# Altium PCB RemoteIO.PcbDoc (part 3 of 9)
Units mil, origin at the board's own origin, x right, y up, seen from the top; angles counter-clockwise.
Board outline 7874.02 x 2362.2 mil, 6 copper layers (Top Layer, GND1, Layer 2, PWR, GND2, Bottom Layer), stack 60.956 mil thick; 686 components, 447 nets, 2681 pads, 1481 vias.

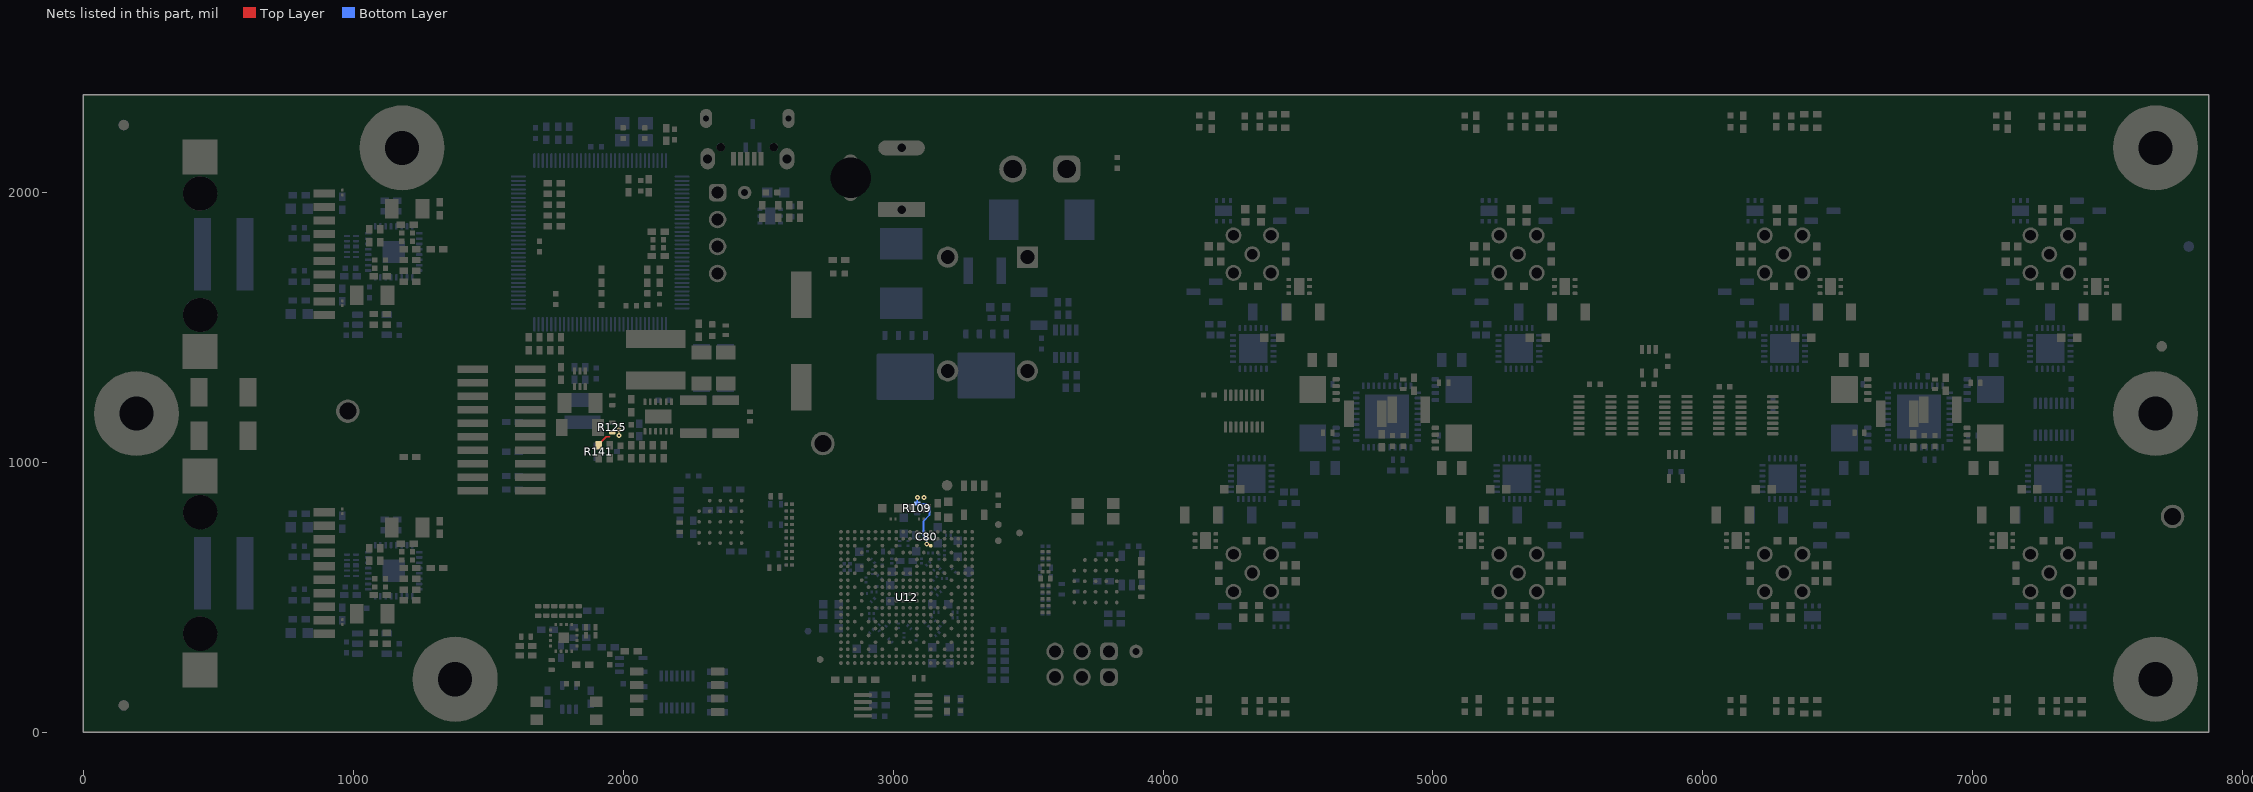
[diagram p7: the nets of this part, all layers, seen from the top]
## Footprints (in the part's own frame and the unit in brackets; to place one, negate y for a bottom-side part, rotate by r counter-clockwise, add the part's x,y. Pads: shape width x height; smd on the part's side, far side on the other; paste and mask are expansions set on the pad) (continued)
WE-MAPI_5030 [mm] "SMD Power Inductor, 2-leads, body 5.6x5.6mm"
  rect 1.7x5.6 smd: 1(-1.95,0) 2(1.95,0)
  silkscreen extent -0.75,-2.8 0.75,2.8, body extent -2.7,-2.7 2.7,2.7, height 3.1
WE-VS_0603 [mm] "SMD Varistor, 2-Leads, body 1.60x0.80mm"
  rect 0.75x0.7 smd: 1(-0.725,0) 2(0.725,0)
  body extent -0.8,-0.4 0.8,0.4, height 0.8
WEEE_Minimum [mil] "WEEElie bin"
  silkscreen extent -95,-172 99,104
WL-SMCC_0402_Green [mm] "SMD, 2-Leads, Body 1x0.5mm"
  rrect17% 0.6x0.6 smd: 1(-0.55,0) 2(0.55,0)
  body extent -0.5,-0.25 0.5,0.25, height 0.39
WURTH_61300311121 [mm] "Header, 2.54mm, 3x1, TH"
  rrect50% 1.65x1.65 hole 1.15: 1(-2.54,0)
  round 1.65 hole 1.15: 2(0,0) 3(2.54,0)
  body extent -3.81,-1.27 3.81,1.27, height 8.54
WURTH_61300411121 [mm] "Header, 2.54mm, 4x1, TH"
  rrect50% 1.65x1.65 hole 1.15: 1(-3.81,0)
  round 1.65 hole 1.15: 2(-1.27,0) 3(1.27,0) 4(3.81,0)
  body extent -5.08,-1.27 5.08,1.27, height 8.54
ZFG0304A-MFG [mm] "Recommended Land Pattern"
  round 0.35 smd paste+0 mask-1000: A1(-6.175,6.175) A2(-5.525,6.175) A3(-4.875,6.175) A4(-4.225,6.175) A5(-3.575,6.175) A6(-2.925,6.175) A7(-2.275,6.175) A8(-1.625,6.175) A9(-0.975,6.175) A10(-0.325,6.175) A11(0.325,6.175) A12(0.975,6.175) A13(1.625,6.175) A14(2.275,6.175) A15(2.925,6.175) A16(3.575,6.175) A17(4.225,6.175) A18(4.875,6.175) A19(5.525,6.175) A20(6.175,6.175) B1(-6.175,5.525) B2(-5.525,5.525) B3(-4.875,5.525) B4(-4.225,5.525) B5(-3.575,5.525) B6(-2.925,5.525) B7(-2.275,5.525) B8(-1.625,5.525) B9(-0.975,5.525) B10(-0.325,5.525) B11(0.325,5.525) B12(0.975,5.525) B13(1.625,5.525) B14(2.275,5.525) B15(2.925,5.525) B16(3.575,5.525) B17(4.225,5.525) B18(4.875,5.525) B19(5.525,5.525) B20(6.175,5.525) C1(-6.175,4.875) C2(-5.525,4.875) C3(-4.875,4.875) C5(-3.575,4.875) C7(-2.275,4.875) C9(-0.975,4.875) C12(0.975,4.875) C14(2.275,4.875) C16(3.575,4.875) C18(4.875,4.875) C19(5.525,4.875) C20(6.175,4.875) D1(-6.175,4.225) D2(-5.525,4.225) D4(-4.225,4.225) D6(-2.925,4.225) D8(-1.625,4.225) D10(-0.325,4.225) D11(0.325,4.225) D13(1.625,4.225) D15(2.925,4.225) D17(4.225,4.225) D19(5.525,4.225) D20(6.175,4.225) E1(-6.175,3.575) E2(-5.525,3.575) E3(-4.875,3.575) E5(-3.575,3.575) E7(-2.275,3.575) E9(-0.975,3.575) E12(0.975,3.575) E14(2.275,3.575) E16(3.575,3.575) E18(4.875,3.575) E19(5.525,3.575) E20(6.175,3.575) F1(-6.175,2.925) F2(-5.525,2.925) F4(-4.225,2.925) F6(-2.925,2.925) F7(-2.275,2.925) F9(-0.975,2.925) F12(0.975,2.925) F14(2.275,2.925) F15(2.925,2.925) F17(4.225,2.925) F19(5.525,2.925) F20(6.175,2.925) G1(-6.175,2.275) G2(-5.525,2.275) G3(-4.875,2.275) G5(-3.575,2.275) G6(-2.925,2.275) G7(-2.275,2.275) G8(-1.625,2.275) G9(-0.975,2.275) G10(-0.325,2.275) G11(0.325,2.275) G12(0.975,2.275) G13(1.625,2.275) G14(2.275,2.275) G15(2.925,2.275) G16(3.575,2.275) G18(4.875,2.275) G19(5.525,2.275) G20(6.175,2.275) H1(-6.175,1.625) H2(-5.525,1.625) H4(-4.225,1.625) H7(-2.275,1.625) H8(-1.625,1.625) H9(-0.975,1.625) H10(-0.325,1.625) H11(0.325,1.625) H12(0.975,1.625) H13(1.625,1.625) H14(2.275,1.625) H17(4.225,1.625) H19(5.525,1.625) H20(6.175,1.625) J1(-6.175,0.975) J2(-5.525,0.975) J3(-4.875,0.975) J5(-3.575,0.975) J6(-2.925,0.975) J7(-2.275,0.975) J8(-1.625,0.975) J9(-0.975,0.975) J10(-0.325,0.975) J11(0.325,0.975) J12(0.975,0.975) J13(1.625,0.975) J14(2.275,0.975) J15(2.925,0.975) J16(3.575,0.975) J18(4.875,0.975) J19(5.525,0.975) J20(6.175,0.975) K1(-6.175,0.325) K2(-5.525,0.325) K4(-4.225,0.325) K7(-2.275,0.325) K8(-1.625,0.325) K9(-0.975,0.325) K10(-0.325,0.325) K11(0.325,0.325) K12(0.975,0.325) K13(1.625,0.325) K14(2.275,0.325) K17(4.225,0.325) K19(5.525,0.325) K20(6.175,0.325) L1(-6.175,-0.325) L2(-5.525,-0.325) L4(-4.225,-0.325) L7(-2.275,-0.325) L8(-1.625,-0.325) L9(-0.975,-0.325) L10(-0.325,-0.325) L11(0.325,-0.325) L12(0.975,-0.325) L13(1.625,-0.325) L14(2.275,-0.325) L17(4.225,-0.325) L19(5.525,-0.325) L20(6.175,-0.325) M1(-6.175,-0.975) M2(-5.525,-0.975) M3(-4.875,-0.975) M5(-3.575,-0.975) M6(-2.925,-0.975) M7(-2.275,-0.975) M8(-1.625,-0.975) M9(-0.975,-0.975) M10(-0.325,-0.975) M11(0.325,-0.975) M12(0.975,-0.975) M13(1.625,-0.975) M14(2.275,-0.975) M15(2.925,-0.975) M16(3.575,-0.975) M18(4.875,-0.975) M19(5.525,-0.975) M20(6.175,-0.975) N1(-6.175,-1.625) N2(-5.525,-1.625) N4(-4.225,-1.625) N7(-2.275,-1.625) N8(-1.625,-1.625) N9(-0.975,-1.625) N10(-0.325,-1.625) N11(0.325,-1.625) N12(0.975,-1.625) N13(1.625,-1.625) N14(2.275,-1.625) N17(4.225,-1.625) N19(5.525,-1.625) N20(6.175,-1.625) P1(-6.175,-2.275) P2(-5.525,-2.275) P3(-4.875,-2.275) P5(-3.575,-2.275) P6(-2.925,-2.275) P7(-2.275,-2.275) P8(-1.625,-2.275) P9(-0.975,-2.275) P10(-0.325,-2.275) P11(0.325,-2.275) P12(0.975,-2.275) P13(1.625,-2.275) P14(2.275,-2.275) P15(2.925,-2.275) P16(3.575,-2.275) P18(4.875,-2.275) P19(5.525,-2.275) P20(6.175,-2.275) R1(-6.175,-2.925) R2(-5.525,-2.925) R4(-4.225,-2.925) R6(-2.925,-2.925) R7(-2.275,-2.925) R9(-0.975,-2.925) R12(0.975,-2.925) R14(2.275,-2.925) R15(2.925,-2.925) R17(4.225,-2.925) R19(5.525,-2.925) R20(6.175,-2.925) T1(-6.175,-3.575) T2(-5.525,-3.575) T3(-4.875,-3.575) T5(-3.575,-3.575) T7(-2.275,-3.575) T9(-0.975,-3.575) T12(0.975,-3.575) T14(2.275,-3.575) T16(3.575,-3.575) T18(4.875,-3.575) T19(5.525,-3.575) T20(6.175,-3.575) U1(-6.175,-4.225) U2(-5.525,-4.225) U4(-4.225,-4.225) U6(-2.925,-4.225) U8(-1.625,-4.225) U10(-0.325,-4.225) U11(0.325,-4.225) U13(1.625,-4.225) U15(2.925,-4.225) U17(4.225,-4.225) U19(5.525,-4.225) U20(6.175,-4.225) V1(-6.175,-4.875) V2(-5.525,-4.875) V3(-4.875,-4.875) V5(-3.575,-4.875) V7(-2.275,-4.875) V9(-0.975,-4.875) V12(0.975,-4.875) V14(2.275,-4.875) V16(3.575,-4.875) V18(4.875,-4.875) V19(5.525,-4.875) V20(6.175,-4.875) W1(-6.175,-5.525) W2(-5.525,-5.525) W3(-4.875,-5.525) W4(-4.225,-5.525) W5(-3.575,-5.525) W6(-2.925,-5.525) W7(-2.275,-5.525) W8(-1.625,-5.525) W9(-0.975,-5.525) W10(-0.325,-5.525) W11(0.325,-5.525) W12(0.975,-5.525) W13(1.625,-5.525) W14(2.275,-5.525) W15(2.925,-5.525) W16(3.575,-5.525) W17(4.225,-5.525) W18(4.875,-5.525) W19(5.525,-5.525) W20(6.175,-5.525) Y1(-6.175,-6.175) Y2(-5.525,-6.175) Y3(-4.875,-6.175) Y4(-4.225,-6.175) Y5(-3.575,-6.175) Y6(-2.925,-6.175) Y7(-2.275,-6.175) Y8(-1.625,-6.175) Y9(-0.975,-6.175) Y10(-0.325,-6.175) Y11(0.325,-6.175) Y12(0.975,-6.175) Y13(1.625,-6.175) Y14(2.275,-6.175) Y15(2.925,-6.175) Y16(3.575,-6.175) Y17(4.225,-6.175) Y18(4.875,-6.175) Y19(5.525,-6.175) Y20(6.175,-6.175)
  silkscreen extent -7.38,-6.78 6.78,6.77, body extent -6.63,-6.63 6.63,6.63, height 1.3

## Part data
C1.1 C1.2 C1.3 C1.4 C1.5 C1.6 C1.7 C1.8 C40.1 C40.2 C40.3 C40.4 C40.5 C40.6 C40.7 C40.8: library part CMP-0119636-1, "WCAP-CSGP Multilayer Ceramic Chip Capacitor, General Purpose, size 1206, X7R, 1µF, 50VDC", Capacitance Tolerance=+/-10%, Case/Size Code=1206, Insulation Resistance=0.5GOhm, Manufacturer="Wurth Elektronik", Operating Temperature Max=125°C, Operating Temperature Min=-55°C, PartNumber='885012208093, Rated Voltage (DC)=50V
C2.1 C2.2 C2.3 C2.4 C2.5 C2.6 C2.7 C2.8: library part CMP-0115435-1, "WCAP-CSGP Multilayer Ceramic Chip Capacitor, General Purpose, size 0603, X7R, 1µF, 16VDC", Capacitance Tolerance=+/-10%, Case/Size Code=0603, Insulation Resistance=0.1GOhm, Manufacturer="Wurth Elektronik", Operating Temperature Max=125°C, Operating Temperature Min=-55°C, Rated Voltage (DC)=16V
C3 C4 C5 C6 C7 C8 C9 C10 C23 C24 C30 C33 C34 C36 C37 C38 C103 C117 C135.1 C135.2 C137.1 C137.2 C139.1 C139.2 C141.1 C141.2 C142.1 C142.2 C143 C149 C150 C151 C152 C153 C157 C162 C170: library part CMP-0119143-1, "WCAP-CSGP Multilayer Ceramic Chip Capacitor, General Purpose, size 0402, X5R, 100nF, 25VDC", Capacitance Tolerance=+/-20%, Case/Size Code=0402, Insulation Resistance=5GOhm, Manufacturer="Wurth Elektronik", Operating Temperature Max=85°C, Operating Temperature Min=-55°C, PartNumber='885012105018, Rated Voltage (DC)=25V
C11 C12 C13 C14 C16 C17 C18 C19: library part CMP-0119538-1, "WCAP-CSGP Multilayer Ceramic Chip Capacitor, General Purpose, size 0805, X7R, 22nF, 100VDC", Capacitance Tolerance=+/-10%, Case/Size Code=0805, Insulation Resistance=4.5GOhm, Manufacturer="Wurth Elektronik", Operating Temperature Max=125°C, Operating Temperature Min=-55°C, Rated Voltage (DC)=100V
C15 C20: library part CMP-0097308-1, "100 pF ±5% 100V Ceramic Capacitor C0G, NP0 0402 (1005 Metric)", Digikey Part Number=732-12055-1-ND, Manufacturer="Wurth Electronics", Mouser Part Number=710-885012005080, Operating Temperature Range="-55°C to +125°C", TempCo=30ppm/°C, Temperature Characteristic=NP0, Tolerance_%=5%, ValueDisplayed=100pF
C21 C22 C148 C163: library part CMP-0119705-1, "WCAP-CSGP Multilayer Ceramic Chip Capacitor, General Purpose, size 1210, X7R, 2.2µF, 100VDC", Capacitance Tolerance=+/-10%, Case/Size Code=1210, Insulation Resistance=0.05GOhm, Manufacturer="Wurth Elektronik", Operating Temperature Max=125°C, Operating Temperature Min=-55°C, PartNumber='885012209071, Rated Voltage (DC)=100V
C25 C26 C27 C28 C29 C32 C35 C39 C41 C42 C43 C130.1 C130.2 C133.1 C133.2 C136.1 C136.2 C138.1 C138.2 C144 C146 C154 C155 C158 C159 C164: library part CMP-0064924-2, "CAP, CERM, 1 uF, 10 V,+/- 20%, X5R, 0402", Cap_Case=0402, Manufacturer="Wurth Elektronik", Supplier Part Number 1=732-7489-1-ND, TempCo=X5R, Tolerance_%=20%, Value1=Unknown, Value2=10V, ValueDisplayed=1uF
C31 C131.1 C131.2 C134.1 C134.2 C145 C147 C156 C167 C168.1 C168.2 C169.1 C169.2: library part CMP-0119242-1, "WCAP-CSGP Multilayer Ceramic Chip Capacitor, General Purpose, size 0402, X7R, 10nF, 10VDC", Capacitance Tolerance=+/-10%, Case/Size Code=0402, Insulation Resistance=10GOhm, Manufacturer="Wurth Elektronik", Operating Temperature Max=125°C, Operating Temperature Min=-55°C, Rated Voltage (DC)=10V
C44 C45 C46 C61 C63 C65 C66 C75 C84 C86 C91 C92 C93 C100 C121 C123 C125: library part CMP-0119149-1, "WCAP-CSGP Multilayer Ceramic Chip Capacitor, General Purpose, size 0603, X5R, 4.7µF, 6.3VDC", Capacitance Tolerance=+/-20%, Case/Size Code=0603, Insulation Resistance=0.02GOhm, Manufacturer="Wurth Elektronik", Operating Temperature Max=85°C, Operating Temperature Min=-55°C, Rated Voltage (DC)=6.3V
C47 C48 C49 C50 C51 C52 C53 C54 C55 C56 C57 C58 C59 C60 C62 C64 C67 C68 C69 C70 C71 C72 C73 C74 C76 C77 C78 C79 C80 C81 C82 C83 C85 C87 C88 C89 C90 C94 C95 C96 C97 C98 C99 C101 C102 C122 C124 C126: library part CMP-0119120-1, "WCAP-CSGP Multilayer Ceramic Chip Capacitor, General Purpose, size 0201, X5R Class II, 100nF, 6.3VDC", Capacitance Tolerance=+/-10%, Case/Size Code=0201, Insulation Resistance=0.5GOhm, Manufacturer="Wurth Elektronik", Operating Temperature Max=85°C, Operating Temperature Min=-55°C, Rated Voltage (DC)=6.3V
C104 C105 C106 C107 C120: library part CMP-0096739-1, "4.7 µF ±10% 50V Ceramic Capacitor X7R 1210 (3225 Metric)", Digikey Part Number=732-7386-1-ND, Manufacturer=Wurth, Mouser Part Number=710-885012209048, Operating Temperature Range="-55°C to +125°C", TempCo=15%, Temperature Characteristic=X7R, Tolerance_%=10%, ValueDisplayed=4.7uF
C108 C109 C115: library part CMP-0064937-2, "CAP, CERM, 22 uF, 10 V,+/- 10%, X7R, 1206", Cap_Case=1206, Manufacturer="Wurth Elektronik", Supplier Part Number 1=732-7566-1-ND, TempCo=X7R, Tolerance_%=10%, Value1=Unknown, Value2=10V, ValueDisplayed=22uF
C110 C111 C113 C129.1 C129.2 C132.1 C132.2: library part CMP-0750070-1, "CAP, CERM, 10 µF, 16 V,+/- 10%, X7R, 1206", Cap_Case=1206, Manufacturer="Wurth Elektronik", TempCo=X7R, Tolerance_%=10%, Value2=16V, ValueDisplayed=10µF
C112 C114: library part CMP-0112443-1, "WCAP-CSRF Multilayer Ceramic Chip Capacitor, High Frequency, size 0402, NP0 Class I, 27pF, 50VDC", Capacitance Tolerance=+/-5%, Case/Size Code=0402, Insulation Resistance=10GOhm, Manufacturer="Wurth Elektronik", Operating Temperature Max=125°C, Operating Temperature Min=-55°C, Rated Voltage (DC)=50V
C116: library part CMP-0114361-1, "WCAP-AS5H Aluminum Electrolytic Capacitor, V-Chip, D10 x H10.5mm, 220µF, 35V", Capacitance Tolerance=+/-20%, Leakage Current=77uA, Manufacturer="Wurth Elektronik", Operating Temperature Max=105°C, Operating Temperature Min=-40°C, Rated Voltage (DC)=35V, Ripple Current=280mA
C118: library part CMP-0119630-1, "WCAP-CSGP Multilayer Ceramic Chip Capacitor, General Purpose, size 1206, X7R, 100nF, 50VDC", Capacitance Tolerance=+/-10%, Case/Size Code=1206, Insulation Resistance=5GOhm, Manufacturer="Wurth Elektronik", Operating Temperature Max=125°C, Operating Temperature Min=-55°C, Rated Voltage (DC)=50V
C119: library part CMP-0119892-1, "WCAP-CSST Multilayer Ceramic Chip Capacitor, Soft Termination, size 0603, X7R Class II, 22nF, 50VDC", Capacitance Tolerance=+/-10%, Case/Size Code=0603, Insulation Resistance=10GOhm, Manufacturer="Wurth Elektronik", Operating Temperature Max=125°C, Operating Temperature Min=-55°C, Rated Voltage (DC)=50V
C127.1 C127.2: library part CMP-0006473-2, "CAP, CERM, 4.7 pF, 50 V, +/- 1%, C0G/NP0, 0402", Cap_Case=0402, Manufacturer=MuRata, Supplier Part Number 1=490-8210-1-ND, TempCo=C0G/NP0, Tolerance_%=1%, Value1=Unknown, Value2=50V, ValueDisplayed=4.7pF
C128.1 C128.2: library part CMP-0119293-1, "WCAP-CSGP Multilayer Ceramic Chip Capacitor, General Purpose, size 0402, X7R, 2.2nF, 50VDC", Capacitance Tolerance=+/-10%, Case/Size Code=0402, Insulation Resistance=10GOhm, Manufacturer="Wurth Elektronik", Operating Temperature Max=125°C, Operating Temperature Min=-55°C, Rated Voltage (DC)=50V
C140.1 C140.2: library part CMP-0009301-2, "CAP, CERM, 0.01 uF, 2000 V, +/- 10%, X7R, 1825", Cap_Case=1825, Manufacturer=AVX, Supplier Part Number 1=478-4008-1-ND, TempCo=X7R, Tolerance_%=10%, Value1=Unknown, Value2=2000V, ValueDisplayed=0.01uF
C160 C161: library part CMP-0124909-1, "12 pF ±2% 50V Ceramic Capacitor C0G, NP0 0402 (1005 Metric)", Digikey Part Number=732-885392005127CT-ND, Manufacturer=Wurth, Mouser Part Number=710-885392005127, Operating Temperature Range="-55°C to +125°C", TempCo=30ppm/°C, Temperature Characteristic=NP0, Tolerance_%=2%, ValueDisplayed=12pF
C165.1 C165.2 C165.3 C165.4 C165.5 C165.6 C165.7 C165.8 C166.1 C166.2 C166.3 C166.4 C166.5 C166.6 C166.7 C166.8: library part CMP-0118895-1, "WCAP-CSGP Multilayer Ceramic Chip Capacitor, General Purpose, size 0603, NP0, 1nF, 50VDC", Capacitance Tolerance=+/-5%, Case/Size Code=0603, Insulation Resistance=10GOhm, Manufacturer="Wurth Elektronik", Operating Temperature Max=125°C, Operating Temperature Min=-55°C, Rated Voltage (DC)=50V
D1 D2 D3 D4 D5 D6 D7 D8: library part CMP-0125609-1, "Green, Red 520nm Green, 625nm Red LED Indication - Discrete 3.2V Green, 2V Red 0606 (1616 Metric)", Color="Red, Green", Digikey Part Number=732-150066RG74000CT-ND, Forward Current=20mA, Manufacturer=Wurth, Mouser Part Number=710-150066RG74000, Operating Temperature Range="-40°C to +85°C"
D9 D10 D11 D12 D13 D14 D15 D16 D20 D21 D22 D24 D29 D30 D31: library part CMP-0081765-2, "LED, Green, SMD", Color=Green, Manufacturer="Wurth Elektronik", Power_TotalModule=99mW, Value1=0.099W, Value2=3.2V
D23 D28: library part CMP-0122246-1, "Red 624nm LED Indication - Discrete 2V 0402 (1005 Metric)", Color=Red, Digikey Part Number=732-13422-1-ND, Forward Current=20mA, Manufacturer=Wurth, Mouser Part Number=710-150040RS73240, Operating Temperature Range="-40°C to +85°C", Power_TotalModule=48mW
D25: library part CMP-0005695-3, "Diode, TVS, Bi, 33 V, SMC", Manufacturer=Bourns, Value1=1500W
D26.1 D26.2 D27.1 D27.2: library part CMP-0120655-1, "1-pF, 5.5-V, 30-KV ESD protection device in 0201 package 2-X2SON -40 to 125", Breakdown Voltage=6V, Clamping Voltage=3.8V, Digikey Part Number=296-ESD441DPLRTR-ND, Manufacturer="Texas Instruments", Mouser Part Number=595-ESD441DPLR, Operating Temperature Range="-40°C to +125°C", ValueDisplayed=1pF
D35: library part CMP-0091708-1, "12.4V (Typ) Clamp 5.5A (8/20µs) Ipp Tvs Diode Surface Mount SC-70-3", Breakdown Voltage=6.5V, Clamping Voltage=9.7V, Digikey Part Number=296-TPD2E2U06DCKRCT-ND, Manufacturer="Texas Instruments", Mouser Part Number=595-TPD2E2U06DCKR, Operating Temperature Range="-40°C to +125°C", ValueDisplayed=1.5pF
F1: library part CMP-0003609-2, "Fuse, 10 A, 125 VAC, 72 VDC, SMD", Irating_A=10A, Manufacturer=Eaton, Supplier Part Number 1=283-2961-1-ND
FID1 FID2 FID3 FID4 FID5 FID6: library part CMP-0077181-1, "Fiducial mark.  There is nothing to buy or mount.", Manufacturer=N/A
H1 H2 H3 H9 H11 H12: library part CMP-0003617-1, "Machine Screw, Round, #4-40 x 1/4, Nylon, Philips panhead", Manufacturer="B&F Fastener Supply", Supplier Part Number 1=H542-ND
H5 H6 H7 H10 H13 H14: library part CMP-0003610-1, "Standoff, Hex, 0.5\"L #4-40 Nylon", Manufacturer=Keystone, Supplier Part Number 1=36-1902C-ND
J1.1 J1.2 J1.3 J1.4 J1.5 J1.6 J1.7 J1.8: "WR-CIRCM12 Screw Mating Panel Connector Female Metal PG9, THT, 5p", Insulation Resistance=100MΩ, Manufacturer="Wurth Elektronik", Max Operating Temperature=90°C, Min Operating Temperature=-40°C, PartNumber='643260100605, Rated Current=5A, Withstanding Voltage="1000V AC", Working Voltage=60V
J2: library part CMP-0127094-1, "Power Barrel Connector Jack 2.10mm ID (0.083\"), 5.50mm OD (0.217\") Through Hole, Right Angle", Current_A=5A, Digikey Part Number=732-5930-ND, Manufacturer=Wurth, Mouser Part Number=710-694106301002, Operating Temperature Range="-40°C to +85°C", Voltage_V=30V
J3: library part CMP-0075640-2, "Header, 1.27mm, 10x2, Tin, SMT", Color=Black, Current_A=3.1A, Manufacturer=Samtec, Supplier Part Number 1=SAM8792-ND
J4.1 J4.2: "WE-RJ45 LAN Transformer, SMT, 10/100 Base-T, Tab Down, 1 Port", Manufacturer="Wurth Elektronik", Max Operating Temperature=85°C, Min Operating Temperature=-40°C
J5: "WR-TBL Series 3055 PCB Header Horizontal Entry with Plastic Latches, THT, pitch 5.08mm, 02p", Manufacturer="Wurth Elektronik", Max Operating Temperature=105°C, Min Operating Temperature=-40°C, Rated Current=16A, Working Voltage=300V
J6: library part CMP-0054798-2, "Header, 2.54 mm, 4x1, Gold, TH", Color=Black, Manufacturer="Wurth Elektronik", PartNumber=61300411121, Supplier Part Number 1=732-5317-ND
J7: library part CMP-0086695-3, "USB - micro B USB 2.0 Receptacle Connector 5 Position Surface Mount, Right Angle; Through Hole", Current_A=3A, Manufacturer="Wurth Electronics", Voltage_V=30V
J8 J9: library part CMP-0054796-4, "Header, 2.54 mm, 3x1, Gold, TH", Manufacturer="Wurth Elektronik", Supplier Part Number 1=732-5316-ND
L1 L7.1 L7.2 L8.1 L8.2 L9: library part CMP-0003233-1, "Ferrite Bead, 600 ohm @ 100 MHz, 0.3 A, 0402", Manufacturer="Wurth Elektronik", Supplier Part Number 1=732-2388-1-ND, Value1="0.6 ohm", Value2=0.3A, ValueDisplayed="600 ohm"
L2 L3: library part CMP-0003214-1, "Ferrite Bead, 120 ohm @ 100 MHz, 0.5 A, 0402", Manufacturer="Wurth Elektronik", Supplier Part Number 1=710-74279271, Value1="0.2 ohm", Value2=0.5A, ValueDisplayed="120 ohm"
L4: library part CMP-0099177-1, "WE-MAPI SMT Power Inductor, size 5030, 6.8uH, 4.3A, 48.3mOhm", Case/Size Code=5030, DC Resistance=42mOhm, DC Resistance Max=48.3mOhm, Inductance=6.8uH, Manufacturer="Wurth Elektronik", Operating Temperature Max=125°C, Operating Temperature Min=-40°C, Rated Current=4.3A, Saturation Current=5.7A, Self Resonant Frequency=15.5MHz
L5: library part CMP-0099114-2, "WE-MAPI SMT Power Inductor, size 3020, 1uH, 4A, 32mOhm", Case/Size Code=3020, DC Resistance=26mOhm, DC Resistance Max=32mOhm, Inductance=1uH, Manufacturer="Wurth Elektronik", Operating Temperature Max=125°C, Operating Temperature Min=-40°C, Rated Current=4A, Saturation Current=5A, Self Resonant Frequency=67MHz
L6: library part CMP-0098028-1, "2 mH @ 10 kHz 2 Line Common Mode Choke Through Hole 10A DCR 6mOhm", Digikey Part Number=732-5584-ND, Manufacturer="Wurth Electronics", Mouser Part Number=710-7448031002, Operating Temperature Range="-40°C to +125°C", Test Frequency=10kHz, Tolerance_%=50%
LBL1: library part CMP-0003625-1, "Thermal Transfer Printable Labels, 0.650\" W x 0.200\" H - 10,000 per roll", Manufacturer=Brady, Supplier Part Number 1=97C5133
Logo1: library part CMP-0074838-1, "Texas Instrument Corporate Signature"
Logo2: library part CMP-0074844-1
Logo3: library part CMP-0074847-1, "FCC_disclaimer"
Logo4: library part CMP-0074769-1
Logo5: library part CMP-0074837-2, "IEC 61010-1 Hot Surface Warning", Manufacturer="Texas Instruments"
Q1 Q2 Q3 Q4 Q5 Q6 Q7 Q8: library part CMP-0000826-2, "MOSFET, N-CH, 60 V, 35 A, DNH0008A (VSONP-8)", Alternate Manufacturer=None, Manufacturer="Texas Instruments", Supplier Part Number 1=CSD18543Q3A-ND, Value1=0.01, Value2="11.1 nC"
Q9 Q10: library part CMP-0000823-2, "MOSFET, N-CH, 60 V, 100 A, DNK0008A (VSON-CLIP-8)", Alternate Manufacturer=None, Manufacturer="Texas Instruments", Supplier Part Number 1=296-41076-1-ND, Value1=0.003, Value2="41 nC"
Q11: library part CMP-0000486-2, "Transistor, NPN, 45 V, 0.1 A, AEC-Q101, SOT-323", Manufacturer="NXP Semiconductor", Supplier Part Number 1=568-6067-1-ND, Value1="0.1 A", Value2=800
R1.1 R1.2 R1.3 R1.4 R1.5 R1.6 R1.7 R1.8 R27 R28 R30 R33 R34 R35 R37 R73 R85 R87 R88 R98 R99 R101 R102 R103 R104 R105 R106 R107 R108 R109 R110 R111 R112 R117 R125 R137 R139 R155 R156 R157 R158 R159 R160 R161 R162: library part CMP-0093210-1, "Jumper 0.063W, 1/16W Chip Resistor 0402 (1005 Metric) - Thick Film", Digikey Part Number=541-4062-1-ND, Manufacturer=Vishay, Mouser Part Number=71-CRCW04020000Z0EDC, Operating Temperature Range="-55°C to +155°C", Power_W=63mW
R2.1 R2.2 R2.3 R2.4 R2.5 R2.6 R2.7 R2.8 R29 R42 R43 R63 R64 R89 R90 R91 R92 R94 R95 R96 R97 R100 R113 R141 R144 R145 R146 R147 R148 R149 R150 R164.1 R164.2 R189.1 R189.2 R190.1 R190.2 R208 R209: library part CMP-0026825-5, "RES, 10 k, 5%, 0.063 W, AEC-Q200 Grade 0, 0402", Manufacturer=Vishay-Dale, Power_W=63mW, Supplier Part Number 1=541-10KJCT-ND, TempCo="200 ppm/C", Tolerance_%=5%, Value2=0.063W, Value_Code=10k0, ValueDisplayed=10k
R3 R4 R5 R6 R7 R8 R9 R10 R11 R12 R13 R14 R15 R16 R17 R18 R32 R36 R61 R83 R123 R143 R197 R198 R199 R200 R206: library part CMP-0026071-3, "RES, 1.00 k, 1%, 0.063 W, AEC-Q200 Grade 0, 0402", Manufacturer=Vishay-Dale, Power_W=63mW, Supplier Part Number 1=541-1.00KLCT-ND, TempCo="100 ppm/C", Tolerance_%=1%, Value2=0.063W, Value_Code=1k00, ValueDisplayed=1.00k
R19 R20 R21 R22 R23 R24 R25 R26 R138 R140 R142 R195 R207: library part CMP-0026918-5, "RES, 3.3 k, 5%, 0.063 W, AEC-Q200 Grade 0, 0402", Manufacturer=Vishay-Dale, Power_W=63mW, Supplier Part Number 1=541-3.3KJCT-ND, TempCo="200 ppm/C", Tolerance_%=5%, Value2=0.063W, Value_Code=3k30, ValueDisplayed=3.3k
R31: library part CMP-0026004-3, "RES, 13.3 k, 1%, 0.063 W, AEC-Q200 Grade 0, 0402", Manufacturer=Vishay-Dale, Power_W=63mW, Supplier Part Number 1=541-13.3KLCT-ND, TempCo="100 ppm/C", Tolerance_%=1%, Value2=0.063W, Value_Code=13k3, ValueDisplayed=13.3k
R38: library part CMP-0026187-2, "RES, 23.7 k, 1%, 0.063 W, AEC-Q200 Grade 0, 0402", Manufacturer=Vishay-Dale, Power_W=63mW, Supplier Part Number 1=541-23.7KLCT-ND, TempCo="100 ppm/C", Tolerance_%=1%, Value2=0.063W, Value_Code=23k7, ValueDisplayed=23.7k
R39 R40 R118 R119 R120: library part CMP-0026908-3, "RES, 33, 5%, 0.063 W, AEC-Q200 Grade 0, 0402", Manufacturer=Vishay-Dale, Power_W=63mW, Supplier Part Number 1=541-33JCT-ND, TempCo="200 ppm/C", Tolerance_%=5%, Value2=0.063W, Value_Code=33R0, ValueDisplayed=33
R41: library part CMP-0026890-5, "RES, 2.2 k, 5%, 0.063 W, AEC-Q200 Grade 0, 0402", Manufacturer=Vishay-Dale, Power_W=63mW, Supplier Part Number 1=541-2.2KJCT-ND, TempCo="200 ppm/C", Tolerance_%=5%, Value2=0.063W, Value_Code=2k20, ValueDisplayed=2.2k
R44 R45 R47 R48 R49 R50 R51 R65 R66 R68 R69 R70 R71 R72: library part CMP-0028027-1, "RES, 49.9 k, 1%, 0.05 W, 0201", Manufacturer="Yageo America", Power_W=50mW, Supplier Part Number 1=603-RC0201FR-7D49K9L, TempCo="200 ppm/C", Tolerance_%=1%, Value2=0.05W, Value_Code=49k9, ValueDisplayed=49.9k
R46 R67: library part CMP-0027242-1, "RES, 4.7 k, 5%, 0.05 W, 0201", Manufacturer="Yageo America", Power_W=50mW, Supplier Part Number 1=603-RC0201JR-7D4K7L, TempCo="200 ppm/C", Tolerance_%=5%, Value2=0.05W, Value_Code=4k70, ValueDisplayed=4.7k
R52 R53 R54 R55 R56 R57 R58 R59 R60 R74 R75 R76 R77 R78 R79 R80 R81 R82: library part CMP-0027210-3, "RES, 22, 5%, 0.05 W, 0201", Manufacturer="Yageo America", Power_W=50mW, Supplier Part Number 1=603-RC0201JR-7D22RL, TempCo="200 ppm/C", Tolerance_%=5%, Value2=0.05W, Value_Code=22R0, ValueDisplayed=22
R62 R84 R121 R122 R127 R128 R129 R130 R134: library part CMP-0026721-1, "RES, 100 k, 1%, 0.0625 W, 0402", Manufacturer="Yageo America", Power_W=62.5mW, Supplier Part Number 1=311-100KLRCT-ND, TempCo="100 ppm/C", Tolerance_%=1%, Value2=0.0625W, Value_Code=100k
R86 R114 R115: library part CMP-0027008-4, "RES, 0, 5%, 0.05 W, 0201", Manufacturer=Vishay-Dale, Power_W=50mW, Supplier Part Number 1=72M6743, TempCo=ppm/C, Tolerance_%=5%, Value2=0.05W, Value_Code=0000, ValueDisplayed=0
R93: library part CMP-0026964-3, "RES, 68, 5%, 0.063 W, AEC-Q200 Grade 0, 0402", Manufacturer=Vishay-Dale, Power_W=63mW, Supplier Part Number 1=541-68JCT-ND, TempCo="200 ppm/C", Tolerance_%=5%, Value2=0.063W, Value_Code=68R0, ValueDisplayed=68
R124: library part CMP-0026290-2, "RES, 31.6 k, 1%, 0.063 W, AEC-Q200 Grade 0, 0402", Manufacturer=Vishay-Dale, Power_W=63mW, Supplier Part Number 1=541-31.6KLCT-ND, TempCo="100 ppm/C", Tolerance_%=1%, Value2=0.063W, Value_Code=31k6, ValueDisplayed=31.6k
R126: library part CMP-0025956-3, "RES, 107 k, 1%, 0.063 W, AEC-Q200 Grade 0, 0402", Manufacturer=Vishay-Dale, Power_W=63mW, Supplier Part Number 1=541-107KLCT-ND, TempCo="100 ppm/C", Tolerance_%=1%, Value2=0.063W, Value_Code=107k
R131 R201: library part CMP-0026824-3, "RES, 100, 5%, 0.063 W, AEC-Q200 Grade 0, 0402", Manufacturer=Vishay-Dale, Power_W=63mW, Supplier Part Number 1=541-100JCT-ND, TempCo="200 ppm/C", Tolerance_%=5%, Value2=0.063W, Value_Code=100R, ValueDisplayed=100
R132: library part CMP-0026340-2, "RES, 3.92 k, 1%, 0.063 W, AEC-Q200 Grade 0, 0402", Manufacturer=Vishay-Dale, Power_W=63mW, Supplier Part Number 1=541-3.92KLCT-ND, TempCo="100 ppm/C", Tolerance_%=1%, Value2=0.063W, Value_Code=3k92, ValueDisplayed=3.92k
R133: library part CMP-0026555-2, "RES, 7.50 k, 1%, 0.063 W, AEC-Q200 Grade 0, 0402", Manufacturer=Vishay-Dale, Power_W=63mW, Supplier Part Number 1=541-7.50KLCT-ND, TempCo="100 ppm/C", Tolerance_%=1%, Value2=0.063W, Value_Code=7k50, ValueDisplayed=7.50k
R135: library part CMP-0026592-2, "RES, 8.87 k, 1%, 0.063 W, AEC-Q200 Grade 0, 0402", Manufacturer=Vishay-Dale, Power_W=63mW, Supplier Part Number 1=541-8.87KLCT-ND, TempCo="100 ppm/C", Tolerance_%=1%, Value2=0.063W, Value_Code=8k87, ValueDisplayed=8.87k
R136: library part CMP-0026963-3, "RES, 68 k, 5%, 0.063 W, AEC-Q200 Grade 0, 0402", Manufacturer=Vishay-Dale, Power_W=63mW, Supplier Part Number 1=541-68KJCT-ND, TempCo="200 ppm/C", Tolerance_%=5%, Value2=0.063W, Value_Code=68k0, ValueDisplayed=68k
R151 R152 R153 R154 R203 R204 R205 R212: library part CMP-0026880-3, "RES, 22, 5%, 0.063 W, AEC-Q200 Grade 0, 0402", Manufacturer=Vishay-Dale, Power_W=63mW, Supplier Part Number 1=541-22JCT-ND, TempCo="200 ppm/C", Tolerance_%=5%, Value2=0.063W, Value_Code=22R0, ValueDisplayed=22
R163.1 R163.2: library part CMP-0026515-2, "RES, 6.49 k, 1%, 0.063 W, AEC-Q200 Grade 0, 0402", Manufacturer=Vishay-Dale, Power_W=63mW, Supplier Part Number 1=541-6.49KLCT-ND, TempCo="100 ppm/C", Tolerance_%=1%, Value2=0.063W, Value_Code=6k49, ValueDisplayed=6.49k
R166.1 R166.2 R167.1 R167.2 R168.1 R168.2 R171.1 R171.2 R172.1 R172.2: library part CMP-0026237-2, "RES, 2.49 k, 1%, 0.063 W, AEC-Q200 Grade 0, 0402", Manufacturer=Vishay-Dale, Power_W=63mW, Supplier Part Number 1=541-2.49KLCT-ND, TempCo="100 ppm/C", Tolerance_%=1%, Value2=0.063W, Value_Code=2k49, ValueDisplayed=2.49k
R176.1 R176.2 R177.1 R177.2 R178.1 R178.2 R181.1 R181.2 R182.1 R182.2: library part CMP-0026088-3, "RES, 1.50 k, 1%, 0.063 W, AEC-Q200 Grade 0, 0402", Manufacturer=Vishay-Dale, Power_W=63mW, Supplier Part Number 1=541-1.50KLCT-ND, TempCo="100 ppm/C", Tolerance_%=1%, Value2=0.063W, Value_Code=1k50, ValueDisplayed=1.50k
R191.1 R191.2 R192.1 R192.2: library part CMP-0025756-4, "RES, 220, 5%, 0.1 W, AEC-Q200 Grade 0, 0603", Manufacturer=Vishay-Dale, Power_W=100mW, Supplier Part Number 1=541-220GCT-ND, TempCo="200 ppm/C", Tolerance_%=5%, Value2=0.1W, Value_Code=220R, ValueDisplayed=220
R193.1 R193.2: library part CMP-0016081-3, "RES, 1.0 M, 5%, 0.75 W, AEC-Q200 Grade 0, 2010", Manufacturer=Vishay-Dale, Power_W=750mW, Supplier Part Number 1=541-1.0MWCT-ND, TempCo="200 ppm/C", Tolerance_%=5%, Value2=0.75W, Value_Code=1M00, ValueDisplayed=1.0M
R194: library part CMP-0026441-2, "RES, 52.3 k, 1%, 0.063 W, AEC-Q200 Grade 0, 0402", Manufacturer=Vishay-Dale, Power_W=63mW, Supplier Part Number 1=541-52.3KLCT-ND, TempCo="100 ppm/C", Tolerance_%=1%, Value2=0.063W, Value_Code=52k3, ValueDisplayed=52.3k
R196: library part CMP-0078244-2, "RES, 30.0 k, 1%, 0.063 W, AEC-Q200 Grade 0, 0402", Manufacturer=Vishay-Dale, Power_W=63mW, Supplier Part Number 1=541-30.0KLCT-ND, TempCo="100 ppm/C", Tolerance_%=1%, Value2=0.063W, Value_Code=30k0, ValueDisplayed=30.0k
R210: library part CMP-0026413-2, "RES, 4.87 k, 1%, 0.063 W, AEC-Q200 Grade 0, 0402", Manufacturer=Vishay-Dale, Power_W=63mW, Supplier Part Number 1=541-4.87KLCT-ND, TempCo="100 ppm/C", Tolerance_%=1%, Value2=0.063W, Value_Code=4k87, ValueDisplayed=4.87k
R211: library part CMP-0026946-3, "RES, 51, 5%, 0.063 W, AEC-Q200 Grade 0, 0402", Manufacturer=Vishay-Dale, Power_W=63mW, Supplier Part Number 1=541-51JCT-ND, TempCo="200 ppm/C", Tolerance_%=5%, Value2=0.063W, Value_Code=51R0, ValueDisplayed=51
R213: library part CMP-0025862-4, "RES, 8.2 k, 5%, 0.1 W, AEC-Q200 Grade 0, 0603", Manufacturer=Vishay-Dale, Power_W=100mW, Supplier Part Number 1=541-8.2KGCT-ND, TempCo="200 ppm/C", Tolerance_%=5%, Value2=0.1W, Value_Code=8k20, ValueDisplayed=8.2k
RV1.1 RV1.2 RV1.3 RV1.4 RV1.5 RV1.6 RV1.7 RV1.8 RV2.1 RV2.2 RV2.3 RV2.4 RV2.5 RV2.6 RV2.7 RV2.8 RV3.1 RV3.2 RV3.3 RV3.4 RV3.5 RV3.6 RV3.7 RV3.8 RV4.1 RV4.2 RV4.3 RV4.4 RV4.5 RV4.6 RV4.7 RV4.8 RV5.1 RV5.2 RV5.3 RV5.4 RV5.5 RV5.6 RV5.7 RV5.8 RV6.1 RV6.2 RV6.3 RV6.4 RV6.5 RV6.6 RV6.7 RV6.8: library part 82556300, "WE-VS SMT Varistor, size 0603, 30VAC, 38VDC", (Reverse) Breakdown Voltage=47V, (Reverse) Peak Pulse Current=30A, Case/Size Code=0603, Clamping Voltage=77V, Manufacturer="Wurth Elektronik", Max Operating Temperature=85°C, Min Operating Temperature=-40°C, Operating Voltage (AC)=30V, Operating Voltage (DC)=38V
S1: library part CMP-0002302-1, "Switch, SPST, Off-Mom, 0.05 A, 12 VDC, SMD", CurrentRating_mA=50A, Manufacturer="Wurth Elektronik", Supplier Part Number 1=732-10143-1-ND
SW1: library part CMP-0093176-1, "Dip Switch SPST 4 Position Surface Mount Slide (Standard) Actuator 25mA 24VDC", Coil Resistance_ohm=100mΩ, Contact Current Rating=25mA, Digikey Part Number=732-3854-1-ND, Manufacturer=Wurth, Mouser Part Number=710-416131160804, Operating Temperature Range="-40°C to +85°C"
SW2: library part CMP-0093456-1, "Tactile Switch SPST-NO Side Actuated Surface Mount, Right Angle", Coil Resistance_ohm=100mΩ, Contact Current Rating=50mA, Digikey Part Number=732-7057-1-ND, Manufacturer="Wurth Electronics", Mouser Part Number=710-434351045816, Operating Force=160gf, Operating Temperature Range="-40°C to +85°C"
TP1 TP2: library part CMP-0003825-1, "1mm Test Point, SMT", Manufacturer=Any
TP3 TP4 TP5: library part CMP-0055143-2, "Test Point, Compact, Black, TH", Color=Black, Manufacturer="Keystone Electronics", Supplier Part Number 1=36-5006-ND
TP6 TP7 TP8 TP9 TP10 TP11 TP12: library part CMP-0078143-4, "TEST POINT.  No entry in BOM.", Manufacturer=N/A
U1.1 U1.2 U1.3 U1.4 U1.5 U1.6 U1.7 U1.8: library part CMP-0044977-1, "Dual Channel IO-Link Device PHY with Integrated LDO and SPI Interface", Manufacturer="Texas Instruments", Max Supply Voltage=36V, Min Supply Voltage=4.5V, Operating Temperature Range="-40°C to +150°C"
U2: library part CMP-0051326-3, "Single Bus Buffer Gate With 3-State Outputs, DCK0005A, LARGE T&R", F @ Nom Voltage(Max)(Mhz)=150, Generic Part Number=SN74LVC1G125, ICC @ Nom Voltage(Max)(mA)=0.01, Manufacturer="Texas Instruments", Operating Temperature Range(C)="-40 to 125,-40 to 85", Rating=Catalog, tpd @ Nom Voltage(Max)(ns)=9,5.5,4.5,4, Voltage(Nom)(V)=1.8,2.5,3.3,5
U3 U4 U6 U8 U9: library part CMP-0093041-1, "Eight-bit shift registers with Schmitt-trigger inputs and with output registers", Digikey Part Number=296-SN74HCS594DYYRCT-ND, Frequency_Fixed=115MHz, Manufacturer="Texas Instruments", Max Supply Voltage=6V, Min Supply Voltage=2V, Mouser Part Number=595-SN74HCS594DYYR, Nominal Supply Current=0.1uA, Operating Temperature Range="-40°C to +125°C"
U5: library part CMP-0093040-1, "Counter Shift Registers 8-bit parallel-load shift registers with Schmitt-trigger inputs", Frequency_Fixed=170MHz, Manufacturer="Texas Instruments", Max Supply Voltage=6V, Min Supply Voltage=2V, Mouser Part Number=595-SN74HCS165DYYR, Nominal Supply Current=0.1uA, Operating Temperature Range="-40°C to +125°C"
U7: library part CMP-0051641-4, "Single Schmitt-Trigger Inverter, DCK0005A (SOT-SC70-5)", Alternate Manufacturer="Texas Instruments", Alternate PartNumber=SN74LVC1G14DCKT, F @ Nom Voltage(Max)(Mhz)=150, Generic Part Number=SN74LVC1G14, ICC @ Nom Voltage(Max)(mA)=0.01, Operating Temperature Range="-40 to 125 C", Rating=Catalog, tpd @ Nom Voltage(Max)(ns)=11,6.5,5.5,5, Voltage(Nom)(V)=1.8,2.5,3.3,5
U10 U11: library part CMP-0093389-2, "65-mΩ, Quad-Channel Smart High-Side Switch with SPI interface and Diagnostics", Manufacturer="Texas Instruments", Max Supply Voltage=36V, Min Supply Voltage=3V, Operating Temperature Range="to +150°C"
U12: library part CMP-0126016-1, "ARM® Cortex®-R5F Sitara™ Microcontroller IC 32-Bit Dual-Core 500MHz 512KB (512K x 8) Tightly Coupled Memory (TCM) 304-NFBGA (13.25x13.25)", Digikey Part Number=296-AM2612AOFFHIZFGRCT-ND, Frequency_Fixed=500MHz, Manufacturer="Texas Instruments", Max Supply Voltage=3.465V, Min Supply Voltage=1.14V, Mouser Part Number=595-AM2612AOFFHIZFGR, Operating Temperature Range="-40°C to +125°C"
U13: library part CMP-0086110-1, "3V 512M-BIT [x 1/x 8] CMOS MXSMIO(R)(SERIAL MULTI I/O)FLASH MEMORY, BGA-24", Manufacturer="Macronix International Co., LTD"
U14: library part CMP-0126808-1, "DRAM IoT RAM 128Mb OPI (x8) DDR 133MHz, 3V, Ind. Temp., BGA24", Frequency_Fixed=133MHz, Manufacturer="AP Memory", Max Supply Voltage=3.6V, Min Supply Voltage=2.7V, Mouser Part Number=878-APS12808L3OBMBA, Nominal Supply Current=500-700uA, Operating Temperature Range="-40°C to +85°C"
U15: library part CMP-0127143-1, "Schmitt-trigger inputs quadruple bus buffer gates with 3-state outputs 14-SOT-23-THIN -40 to 125", Digikey Part Number=296-SN74HCS125DYYRCT-ND, Manufacturer="Texas Instruments", Max Supply Voltage=6V, Min Supply Voltage=2V, Mouser Part Number=595-SN74HCS125DYYR, Nominal Supply Current=0.1uA, Operating Temperature Range="-40°C to +125°C"
U16 U21: library part CMP-0051704-3, "Single Schmitt-Trigger Buffer, DCK0005A, LARGE T&R", F @ Nom Voltage(Max)(Mhz)=150, Generic Part Number=SN74LVC1G17, ICC @ Nom Voltage(Max)(mA)=0.01, Manufacturer="Texas Instruments", Operating Temperature Range(C)="-40 to 125,-40 to 85", Rating=Catalog, tpd @ Nom Voltage(Max)(ns)=11,6.5,5.5,5, Voltage(Nom)(V)=1.8,2.5,3.3,5
U17 U18 U26.1 U26.2: library part CMP-0051264-2, "Single 2-Input Positive–AND Gate with Open Drain Output,  DBV0005A (SOT-23-5)", F @ Nom Voltage(Max)(Mhz)=75, Generic Part Number=SN74AHC1G09, ICC @ Nom Voltage(Max)(mA)=0.01, Manufacturer="Texas Instruments", Operating Temperature Range="-55 to 125 C", Rating=Catalog, tpd @ Nom Voltage(Max)(ns)=11,7.5, Voltage(Nom)(V)=3.3,5
U19.1 U19.2: library part CMP-0124715-2, "Deterministic, Low-Latency, Low-Power, 10/100 Mbps, Industrial Ethernet PHY", Manufacturer="Texas Instruments", Max Supply Voltage=3.6V, Min Supply Voltage=1.62V, Operating Temperature Range="-40°C to +85°C"
U20: library part CMP-0051588-2, "Single 2-Input Positive-AND Gate, DBV0005A, LARGE T&R", Alternate Manufacturer="Texas Instruments", F @ Nom Voltage(Max)(Mhz)=150, Generic Part Number=SN74LVC1G08, ICC @ Nom Voltage(Max)(mA)=0.01, Operating Temperature Range(C)="-40 to 125,-40 to 85", Rating=Catalog, tpd @ Nom Voltage(Max)(ns)=4.5,6,4,5, Voltage(Nom)(V)=1.8,2.5,3.3,5
U22: library part CMP-0126121-1, "5 output reference-less clock generator with bulk acoustic wave (BAW) 16-TQFN -40 to 85", Digikey Part Number=296-LMK3C0105V33RERRTR-ND, Manufacturer="Texas Instruments", Max Frequency=200MHz, Max Supply Voltage=3.465V, Min Supply Voltage=1.71V, Mouser Part Number=595-LMK3C0105V33RERR, Operating Temperature Range="-40°C to +85°C"
U23: library part CMP-0096682-1, "4-V to 36-V, 5-A Synchronous Step-Down DC/DC Converter with Low IQ", Manufacturer="Texas Instruments", Max Supply Voltage=36V, Min Supply Voltage=4V, Nominal Supply Current=25uA, Operating Temperature Range="-40°C to +150°C", Output Voltage=1-16V, Switching Frequency=200-1100kHz
U24: library part CMP-0121127-1, "3-A, High-Efficiency, Synchronous Buck Converter in a SOT563 Package", Manufacturer="Texas Instruments", Max Supply Voltage=5.5V, Min Supply Voltage=2.5V, Nominal Supply Current=28.5uA, Operating Temperature Range="-40°C to +125°C", Output Voltage=0.6-5.5V, Switching Frequency=2.2MHz
U25: library part CMP-0095525-1, "Low IQ High Side Switch Controller With Reverse Polarity and Overvoltage Protection", Manufacturer="Texas Instruments", Max Supply Voltage=60V, Min Supply Voltage=4V, Nominal Supply Current=45uA, Operating Temperature Range="-40°C to +150°C"
U27.1 U27.2: library part CMP-0079927-2, "ESD204, DQA0010A (USON-10)", Alternate Manufacturer="Texas Instruments", Alternate PartNumber=ESD204DQAT
U28: library part CMP-0005248-2, "256K I2C™ CMOS Serial EEPROM, TSSOP-8", Manufacturer=Microchip, Supplier Part Number 1=24AA256-I/ST-ND
U29: library part CMP-0066914-5, "1% High-Accuracy, 1-A, Low-Dropout Regulator with Reverse Current Protection, DRV0006A (WSON-6)", Alternate Manufacturer="Texas Instruments", Alternate PartNumber=TPS7A3701DRVT
U30: library part CMP-0077953-1, "MSP432E401YTPDT, PDT0128A (TQFP-128)", Alternate Manufacturer="Texas Instruments", Alternate PartNumber=MSP432E401YTPDTR
U31.1 U31.2 U31.3 U31.4 U31.5 U31.6 U31.7 U31.8 U32.1 U32.2 U32.3 U32.4 U32.5 U32.6 U32.7 U32.8: library part CMP-0013424-7, "33-V Precision Surge Protection Clamp, DRV0006A (WSON-6)", Alternate Manufacturer="Texas Instruments", Alternate PartNumber=TVS3300DRVT
U33.1 U33.2 U33.3 U33.4 U33.5 U33.6 U33.7 U33.8 U34.1 U34.2 U34.3 U34.4 U34.5 U34.6 U34.7 U34.8: library part CMP-0097428-1, "Surge Protection Device in SOT-23 Package", Breakdown Voltage=37.8V, Clamping Voltage=57V, Manufacturer="Texas Instruments", Operating Supply Voltage=36V, Operating Temperature Range="-40°C to +125°C", ValueDisplayed=50pF
Y1: library part CMP-0094478-1, "Crystal 16 MHz ±20ppm Crystal 8pF 70 Ohms 4-SMD, No Lead", Digikey Part Number=732-830064296CT-ND, Frequency Stability=20ppm, Frequency_Fixed=16MHz, Load Capacitance=8pF, Manufacturer=Wurth, Mouser Part Number=710-830064296, Operating Temperature Range="-10°C to +70°C"
ZZ1: library part CMP-0003616-3
ZZ2: library part CMP-0077236-1
ZZ3: library part CMP-0077237-1
ZZ4: library part CMP-0077238-1

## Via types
v1: diameter 18, hole 8, Top Layer to Bottom Layer, tented both sides, 1314 vias
v2: diameter 19.68, hole 7.87, Top Layer to Bottom Layer, tented both sides, 133 vias
v3: diameter 19.68, hole 7.87, Top Layer to Bottom Layer, 34 vias

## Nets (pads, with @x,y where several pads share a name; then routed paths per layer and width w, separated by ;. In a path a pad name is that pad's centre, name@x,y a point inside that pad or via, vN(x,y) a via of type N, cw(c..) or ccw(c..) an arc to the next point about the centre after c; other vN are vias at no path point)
1V25: C80.2 R109.2 R125.2 R141.2 U12.V7 | length 313.4
  Top Layer w6: R141.2@1910,1063.62 1910,1067.56 1937.44,1095 1950,1095 ; R125.2@1960,1112.28 R125.2@1964.87,1117.16 ; v1@1978.91,1117.16 1981.75,1120 v1(1985,1120) ; v1(3124.83,698.51) 3127.12,696.21 3133.18,696.21 3137.46,691.93 U12.V7@3139.57,691.93
  Bottom Layer w6: v1(3090,870) R109.2@3090,847.72 3122.28,847.72 3135.04,834.96 3135.04,805.04 3112.59,782.59 3112.59,726.84 3116.84,722.59 3116.97,722.59 3123.23,716.34 C80.2@3125,716.34 ; v1(3124.83,698.51) 3124.91,698.59 3124.91,716.25 C80.2@3125,716.34 ; C80.2@3126.77,716.34 C80.2@3125,716.34
  other v1: 3115,870 1985,1100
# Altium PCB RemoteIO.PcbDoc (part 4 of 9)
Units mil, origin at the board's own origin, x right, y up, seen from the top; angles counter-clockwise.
Board outline 7874.02 x 2362.2 mil, 6 copper layers (Top Layer, GND1, Layer 2, PWR, GND2, Bottom Layer), stack 60.956 mil thick; 686 components, 447 nets, 2681 pads, 1481 vias.

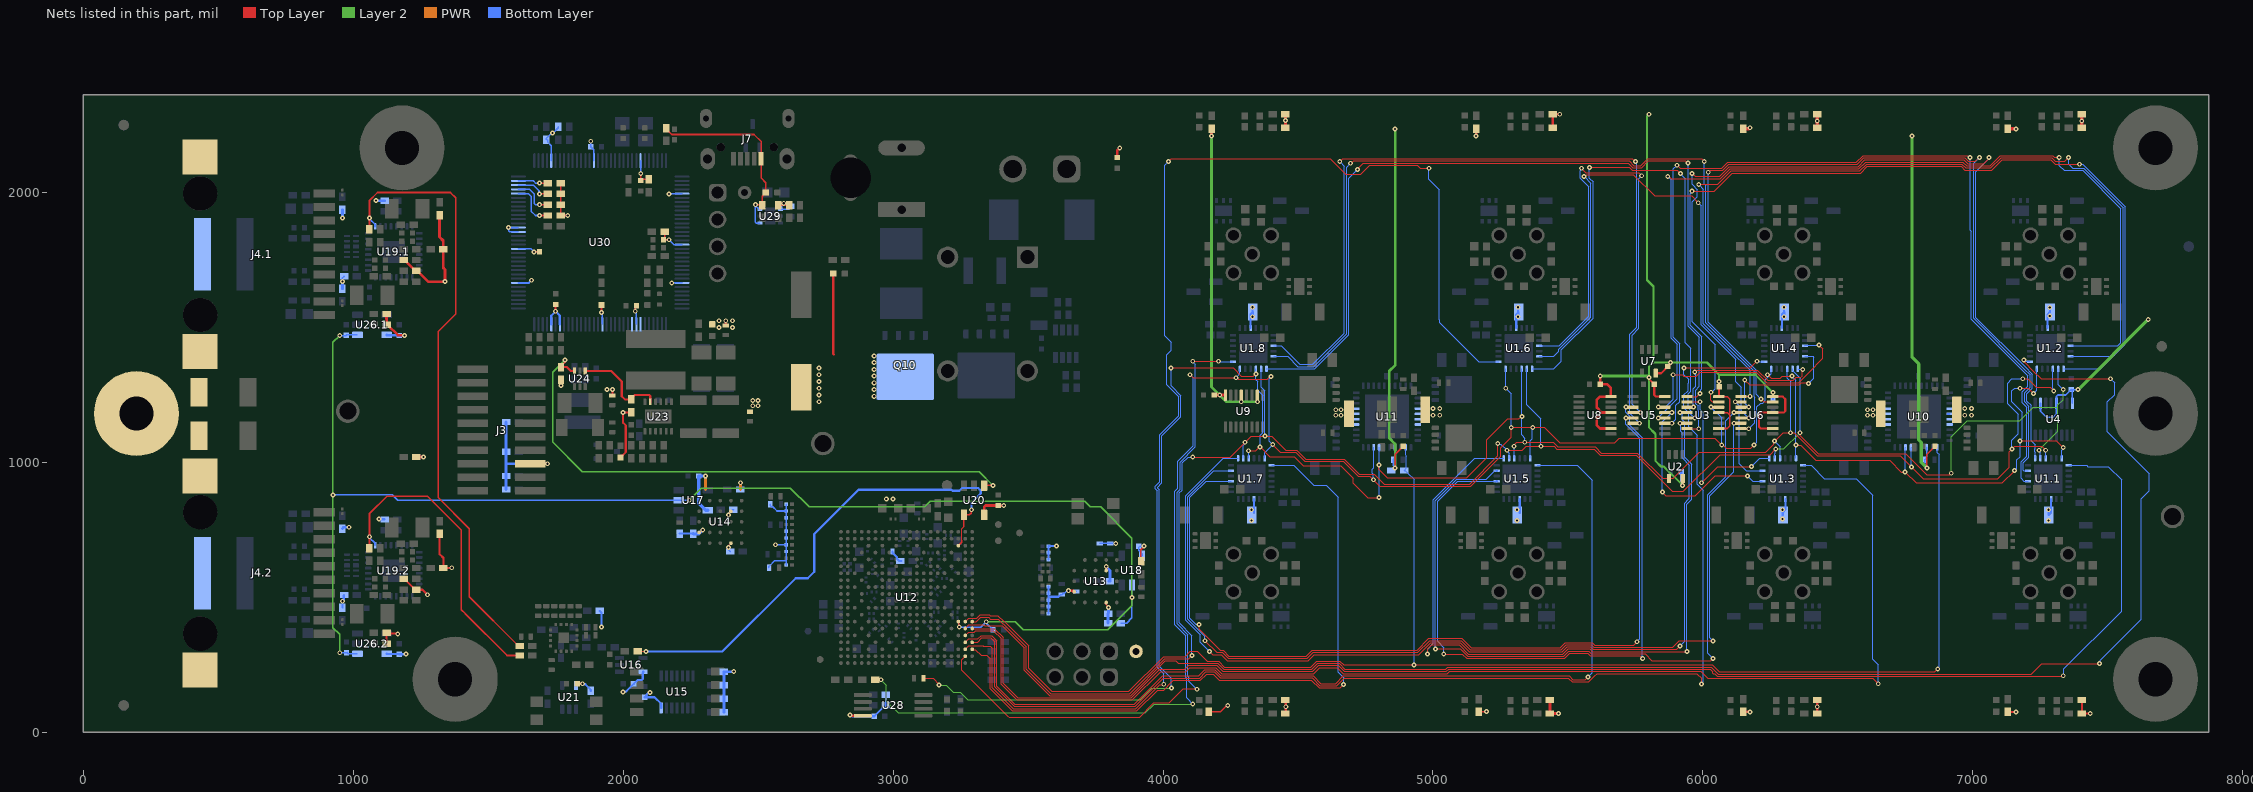
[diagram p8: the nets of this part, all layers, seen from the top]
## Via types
v1: diameter 18, hole 8, Top Layer to Bottom Layer, tented both sides, 1314 vias
v2: diameter 19.68, hole 7.87, Top Layer to Bottom Layer, tented both sides, 133 vias
v3: diameter 19.68, hole 7.87, Top Layer to Bottom Layer, 34 vias

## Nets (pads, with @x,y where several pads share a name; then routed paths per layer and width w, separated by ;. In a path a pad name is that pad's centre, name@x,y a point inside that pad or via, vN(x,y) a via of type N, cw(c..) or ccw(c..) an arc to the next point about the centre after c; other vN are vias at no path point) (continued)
3V3: C3.2 C4.2 C5.2 C6.2 C7.2 C8.2 C9.2 C10.2 C23.2 C24.2 C25.1 C26.1 C27.1 C28.1 C29.1 C30.2 C32.1 C33.2 C34.2 C36.2 C37.2 C38.2 C142.1.2 C142.2.2 C143.2 C170.2 D21.2 D22.2 J3.5 L1.2 L3.2 L7.1.2 L7.2.2 L8.1.2 L8.2.2 R3.2 R4.2 R5.2 R6.2 R7.2 R8.2 R9.2 R10.2 R11.2 R12.2 R13.2 R14.2 R15.2 R16.2 R17.2 R18.2 R19.2 R20.2 R21.2 R22.2 R23.2 R24.2 R25.2 R26.2 R28.2 R29.2 R34.2 R41.1 R42.2 R43.2 R44.2 R45.2 R46.2 R47.2 R48.2 R49.2 R50.2 R51.2 R63.2 R64.2 R65.2 R66.2 R67.2 R68.2 R69.2 R70.2 R71.2 R72.2 R89.2 R90.2 R91.2 R92.2 R94.2 R95.2 R96.2 R97.2 R100.2 R110.2 R113.1 R117.2 R121.2 R127.2 R139.2 R145.1 R146.1 R147.2 R148.2 R149.2 R150.2 R164.1.2 R164.2.2 R166.1.2 R166.2.2 R167.1.2 R167.2.2 R168.1.2 R168.2.2 R171.1.2 R171.2.2 R172.1.2 R172.2.2 R189.1.2 R189.2.2 R190.1.2 R190.2.2 TP12.1 U2.5 U3.10 U3.13 U3.16 U4.10 U4.13 U4.16 U5.16 U6.10 U6.13 U6.16 U7.5 U8.10 U8.13 U8.16 U9.10 U9.13 U9.16 U10.4 U11.4 U13.B4 U13.D1 U13.E4 U14.B4 U14.D1 U14.E4 U15.14 U16.5 U17.5 U18.5 U20.5 U21.5 U26.1.5 U26.2.5 U28.8 | length 13502.6
  Top Layer w6: U14.D1@2281.26,740.63 2283.26,740.63 2292.63,750 v1(2295,750) ; v1(2390,685) 2392.3,687.3 2392.3,692.19 2399.37,699.26 U14.E4@2399.37,701.26 ; v1(2390,805) 2390,808 2399.37,817.37 U14.B4@2399.37,819.37 ; U13.E4@3787.19,478.76 3787.19,476.65 3795.75,468.09 3795.75,464.57 v1(3798.04,462.27) ; R97.2@3917.81,631.12 3917.81,676.73 3930,688.91 v1(3930,690) ; R25.2@4170,76.38 4213.13,76.38 4236.75,100 v1(4240,100) ; v1(4290,1225) 4290.08,1225.08 4290.08,1248.98 U9.13@4290.16,1249.06 ; v1(4860,980) 4860,1030.31 C23.2@4890,1060.31 ; R23.2@5170,76.38 5170.4,76.78 v1(5198.19,76.78) ; v1(5925,915) 5925.3,915.3 5925.3,940.41 U2.5@5925.59,940.71 ; U3.10@6059.06,1125.79 6090.79,1125.79 6099,1134 6099,1176 6090.16,1184.84 U3.13@6059.06,1184.84 ; U3.16@6059.06,1243.9 6091.1,1243.9 6099,1236 6099,1180 ; v1(6830,980) 6830,1030.31 C24.2@6860,1060.31
  Top Layer w8: R164.2.2@1125,327.52 R164.2.2@1123.62,328.9 L7.2.2@1123.62,368.9 1123.62,375.38 1132.09,366.91 1163.09,366.91 v1(1165,365) ; R190.2.2@1186.38,568.9 1190.32,568.9 1198.13,561.09 1198.13,560.46 1229.68,528.9 R168.2.2@1233.62,528.9 1234.2,528.32 1256.68,528.32 v1(1275,510) ; L8.2.2@1320,735.28 1320,660 1334.17,645.83 1334.17,609.45 1364.45,609.45 v1(1365,610) ; v1(1770,1285) R127.2@1770,1306.38 ; C38.2@1829.69,180 v1(1850,180) ; R139.2@1960,1247.72 v1(1960,1270) ; D22.2@1990,1018.35 2009.81,1038.16 2009.81,1137.48 2000,1147.29 v1(2000,1185) 2028.62,1185 R121.2@2030,1186.38 ; v1(2840,65) 2843.39,61.61 U28.8@2887.8,61.61 ; U13.B4@3789.37,599.37 3789.69,599.69 3789.69,614.68 v1(3790,615) ; v1@5801.91,1307.78 C5.2@5819.69,1290 ; C5.2@5820,1290 5820,1250 5826.1,1243.9 U5.16@5859.06,1243.9 ; U7.5@5825.59,1330.71 5845.4,1330.71 C9.2@5870,1355.31 5878.09,1363.4 5878.09,1368.09 v1(5880,1370) ; v1(6060,1300) 6060,1280.31 C6.2@6060.31,1280 U3.16@6060.31,1245.8 ; R21.2@6150,76.38 6173.62,76.38 v1(6175,75) ; U6.10@6259.06,1125.79 6214.69,1125.79 6208,1132.47 6208,1178 6215,1185 U6.13@6260,1185 ; U6.13@6260,1184.84 6299.84,1184.84 6305,1190 6305,1235 6296.1,1243.9 U6.16@6259.06,1243.9 6260,1244.84 v1(6260,1258.79) ; R7.2@6423.62,70 v1(6423.62,95) R8.2@6423.62,120 ; R19.2@7130,72.44 R19.2@7130,76.38 7131.38,75 v1(7160,75) ; R3.2@7399.69,70 R3.2@7403.62,70 ; R4.2@7405,120 7405,71.38 R3.2@7403.62,70 ; v1(7435,70) R3.2@7403.62,70
  Top Layer w10: L7.1.2@1123.62,1550 R164.1.2@1123.62,1510 1127.56,1510 1166.03,1471.53 1188.47,1471.53 v1(1190,1470) ; R190.1.2@1186.38,1750 1190.32,1750 1222.87,1717.44 1222.87,1716.81 1229.68,1710 R168.1.2@1233.62,1710 1237.56,1710 1277.56,1670 v1(1340,1670) 1340,1715 1333.62,1721.38 R171.1.2@1333.62,1790 1333.62,1821.38 1320,1835 L8.1.2@1320,1916.38 ; R41.1@1233.62,1020 v1(1260,1020) ; J3.5@1656.5,995 v1(1720,995) ; R117.2@2380,1507.72 v1(2380,1525) ; U20.5@3337.4,805.87 3337.4,834.46 3343.26,840.31 C37.2@3390,840.31 3390.32,840 v1(3410,840) ; v1(3650,525) 3665.87,525 3670.24,520.63 U13.D1@3671.26,520.63 ; C170.2@3830,2129.69 3830,2155 v1(3840,2165) ; v1(4180,2210) R26.2@4180,2236.38 ; C3.2@4190,1250 4230.2,1250 U9.16@4231.1,1249.06 ; U9.10@4349.21,1249.06 4349.61,1248.66 4349.61,1225.39 v1(4350,1225) ; R15.2@4453.62,70 4455,71.38 v1(4455,95) ; v1@4453.62,96.38 4455,97.76 4455,118.62 R16.2@4453.62,120 ; R17.2@4453.62,2243.62 v1(4453.62,2266.81) R18.2@4453.62,2290 ; v1(5160,2210) R24.2@5160,2236.38 ; R12.2@5433.62,120 R11.2@5433.62,70 v1(5465,70) ; R13.2@5445,2240 5443.62,2241.38 R14.2@5443.62,2290 v1(5470,2290) ; C4.2@5619.69,1290 5619.69,1319.69 v1(5620,1320) ; C4.2@5619.84,1289.85 5645.15,1289.85 5659.06,1275.94 U8.16@5659.06,1243.9 5618.44,1243.9 5607,1232.46 5607,1203 5625,1185 ; U8.10@5659.06,1125.79 5618.76,1125.79 5607,1137.54 5607,1167 5625,1185 ; U8.13@5659.06,1184.84 5658.98,1184.92 5625.08,1184.92 5625,1185
  Top Layer w12: R22.2@6150,2236.38 6171.38,2236.38 v1(6175,2240) ; R9.2@6423.62,2240 v1(6423.62,2265) R10.2@6423.62,2290 ; R20.2@7130,2236.38 7153.62,2236.38 7155,2235 v1(7160,2235) ; R5.2@7403.62,2240 v1(7403.62,2265) R6.2@7403.62,2290
  Layer 2 w8: v1(5800,2290) 5793,2283 5793,1675.87 5817,1651.87 5817,1372 ; v1(5925,915) 5855,985 5845,985 5825,1005 5825,1105 5822.66,1107.34 5800,1130 v1(5800,1315) 5800,1320 5800,1355 5817,1372 ; v1(6060,1300) 6060,1325 ; v1(6260,1258.79) 6193.79,1325 6060,1325 ; 5817,1372 5819,1370 v1(5880,1370) 6015,1370 6060,1325
  Layer 2 w10: v1(4180,2210) 4180,1280 v1(4210,1250) 4235,1225 v1(4290,1225) v1(4350,1225) ; v1(4860,980) 4860,1068.47 4838.13,1090.34 4838.13,1338.13 4860,1360 v1(4860,2235) ; v1(5620,1320) v1@5800,1320
  Layer 2 w12: v1(6775,2210) 6775,1390 6800,1365 6800,1083.31 6809,1074.31 6809,1001 v1(6830,980) ; v1(7390,1270) v1(7650,1530)
  PWR w10: 2435,900 v1(2435,925)
  PWR w12: 2305,900 v1(2305,950)
  Bottom Layer w6: v1(960,1670) 960,1683.62 R189.1.2@966.38,1690 ; v1(2390,685) 2390,676.38 C29.1@2396.38,670 ; v1(2390,805) 2392.3,807.3 2392.3,812.61 2404.68,825 C32.1@2408.62,825 ; R63.2@2540,610 2540,614.5 2560.94,635.44 2602.49,635.44 2603.98,633.95 R71.2@2603.98,620 ; R64.2@2545,845 2545,840.5 2549.5,836 2554,836 2570,820 R67.2@2603.98,820 ; v1(2565,695) R65.2@2603.98,695 ; 2603.98,635.44 R70.2@2603.98,670 R65.2@2603.98,695 ; R66.2@2603.98,845 R67.2@2603.98,820 ; R43.2@3615.5,505 3620.5,510 R43.2@3625,510 3629.5,514.5 3634,514.5 3642.2,522.7 3647.7,522.7 v1(3650,525) 3651.25,523.75 3676.56,523.75 C27.1@3677.81,522.5 ; R96.2@3765,700 R42.2@3805,700 v1(3825,700) ; C30.2@3910,685 3910,674.33 3913.51,670.82 3913.59,670.82 3922.4,662.01 U18.5@3922.4,654.13 ; C30.2@3915,690 v1(3930,690) ; R34.2@4857.16,1014.87 R34.2@4852.28,1010 4852.28,989.19 R29.2@4860,981.47 ; R34.2@4857.16,1019.96 4859.53,1022.33 U11.4@4859.53,1055.83 ; U10.4@6829.53,1055.83 6829.53,1022.33 6827.16,1019.96 6827.16,1014.87 R28.2@6822.28,1010 6822.28,989.19 6830,981.47 v1(6830,980) ; U4.10@7250.79,1219.06 7250.79,1189.39 7272.1,1168.07 7298.07,1168.07 7310,1180 U4.13@7310,1219.06 ; U4.13@7309.84,1219.06 7310.03,1219.24 7310.03,1245.03 7315,1250 7344.68,1250 7364.68,1270 7365,1270 7368.9,1266.1 U4.16@7368.9,1219.06 ; C10.2@7365,1270.31 7365.31,1270 v1(7390,1270) ; R65.2@2603.98,695 R72.2@2603.98,720 R69.2@2603.98,745 R68.2@2603.98,795 R67.2@2603.98,820
  Bottom Layer w8: R166.2.2@960,462.52 960.58,463.1 v1(960.58,485.58) 964.77,489.77 964.77,507.29 R189.2.2@966.38,508.9 ; v1(1095,790) 1095.55,789.45 1115.83,789.45 R172.2.2@1116.38,788.9 ; U26.2.5@1124.13,291.5 1125.28,290.35 1168.85,290.35 C142.2.2@1170,289.21 1170.39,289.61 1194.61,289.61 v1(1195,290) ; U21.5@1825.59,174.29 1825.59,176.13 1829.46,180 v1(1850,180) 1851.91,178.09 1859.47,178.09 1880,157.56 R100.2@1880,153.62 ; L1.2@1913.62,450 1920,443.62 v1(1920,390) ; v1(2000,150) 2001.91,151.91 2011.6,151.91 C36.2@2039.69,180 2053.16,193.47 2068.1,193.47 2072.79,198.16 2072.79,220.54 2074.29,222.04 U16.5@2074.29,224.41 ; v1(2100,148) 2098.09,146.09 2092.83,146.09 2085.84,139.09 2085.84,136.16 C34.2@2080,130.31 2116.34,130.31 2140.94,105.71 U15.14@2140.94,90.94 ; R95.2@2210,736.38 C28.1@2260,736.38 ; v1(2840,65) 2842.71,65 2847.7,60 C143.2@2930.31,60 2961.87,91.56 2961.87,92.19 2969.68,100 R146.1@2973.62,100 R145.1@2973.62,140 ; R110.2@2997.72,670 2997.72,666.06 3014.63,649.15 3014.63,642.81 3022.44,635 L3.2@3026.38,635 L3.2@3030,635 ; R49.2@3576.02,440 R44.2@3576.02,465 R47.2@3576.02,490 3576.02,502.5 ; R45.2@3576.02,540 R51.2@3576.02,515 3576.02,502.5 ; R46.2@3576.02,640 R50.2@3576.02,665 R48.2@3576.02,690 v1(3605,690) ; R43.2@3615.5,505 3613,502.5 3576.02,502.5 ; C8.2@5919.69,965 5919.69,923.02 5925,917.71 v1(5925,915) ; C7.2@6260,1234.69 v1(6260,1258.79)
  Bottom Layer w10: R167.2.2@960,755.28 964.72,760 v1(985,760) ; R166.1.2@960,1643.62 v1(960,1670) ; v1(960,1905) R167.1.2@960,1936.38 ; v1(1085,1970) R172.1.2@1116.38,1970 ; U26.1.5@1124.13,1472.6 1125.28,1471.46 1168.85,1471.46 C142.1.2@1170,1470.31 1170.15,1470.16 1189.84,1470.16 v1(1190,1470) ; R150.2@1566.38,900 R148.2@1566.38,950 1566.38,995 ; R147.2@1566.38,1150 R149.2@1566.38,1040 1566.38,995 ; v1(1720,995) 1566.38,995 ; R89.2@2373.62,75 R90.2@2373.62,125 R91.2@2373.62,175 R92.2@2373.62,225 v1(2410,225) ; R94.2@2433.62,900 2433.62,923.62 v1(2435,925) ; v1(3790,615) 3790,612.84 3803.62,599.21 C25.1@3803.62,560 C25.1@3799.68,560 ; R113.1@3796.38,405 C26.1@3796.38,440 ; C26.1@3798.04,443.04 v1(3798.04,462.27)
  Bottom Layer w12: C28.1@2260,736.38 2261.38,735 2280,735 v1(2295,750) ; v1(2305,950) C33.2@2279.69,950 2279.69,849.17 2306.26,822.6 U17.5@2314.13,822.6
  other v1: 2975,865 3000,865 1940,1270 2355,1500 2405,1500 2355,1525 2405,1525
3V3_PG: R121.1 U23.5 U24.4 | length 348.3
  Top Layer w8: U24.4@1859.68,1339.13 1955.87,1339.13 1995,1300 1995,1245 2006.38,1233.62 R121.1@2030,1233.62 2030,1237.56 2042.44,1250 2095.79,1250 2100.47,1245.31 U23.5@2100.47,1224.72
24V: C21.2 C22.2 C40.1.2 C40.2.2 C40.3.2 C40.4.2 C40.5.2 C40.6.2 C40.7.2 C40.8.2 C116.1 C148.2 C163.2 D20.2 Q10.5 Q10.6 Q10.7 Q10.8 Q10.9@3045,1317.44 R137.2 U1.1.9 U1.2.9 U1.3.9 U1.4.9 U1.5.9 U1.6.9 U1.7.9 U1.8.9 U10.14 U10.15 U10.16 U10.17 U10.34 U10.35 U10.36 U10.37 U11.14 U11.15 U11.16 U11.17 U11.34 U11.35 U11.36 U11.37 | length 1032.1
  Top Layer w8: D20.2@2778.35,1700 2778.35,1401.65 2780,1400
  Bottom Layer w8: U1.8.9@4324.33,1497.5 4324.33,1548.39 C40.8.2@4331.5,1555.55 ; v1(4331.5,1575) C40.8.2@4331.5,1555.55 ; C40.7.2@4337.09,813.82 U1.7.9@4337.09,864.7 ; U1.6.9@5308.58,1497.5 5308.58,1548.39 C40.6.2@5315.75,1555.55 ; v1(5315.75,1575) C40.6.2@5315.75,1555.55 ; C40.5.2@5321.34,813.82 U1.5.9@5321.34,864.7 ; U1.4.9@6292.83,1497.5 6292.83,1548.39 C40.4.2@6300,1555.55 ; v1(6295,790) C40.3.2@6295,815 ; C40.3.2@6296.77,805 C40.3.2@6296.77,816.77 ; v1(6300,1575) C40.4.2@6300,1555.55 ; U1.3.9@6305.59,864.7 6305.59,825.59 C40.3.2@6296.77,816.77 ; U10.35@6907.28,1179.84 U10.35@6914.17,1179.84 ; U1.2.9@7277.09,1497.5 7277.09,1548.39 C40.2.2@7285.91,1557.2 C40.2.2@7285.91,1574.27 ; v1(7280,825) 7281.02,823.98 C40.1.2@7281.02,805 7289.84,813.82 U1.1.9@7289.84,864.7 ; C40.8.2@4331.5,1555.55 C40.8.2@4333.15,1557.2 4333.15,1541.65 v1(4331.5,1540) C40.8.2@4331.5,1555.55 ; C40.6.2@5315.75,1555.55 C40.6.2@5317.4,1557.2 5317.4,1541.65 v1(5315.75,1540) C40.6.2@5315.75,1555.55 ; C40.3.2@6295,815 C40.3.2@6296.77,816.77 ; C40.3.2@6295,815 v1(6295,825) 6296.77,823.23 C40.3.2@6296.77,816.77 ; C40.4.2@6300,1555.55 v1(6300,1540) 6301.65,1541.65 C40.4.2@6301.65,1557.2 C40.4.2@6300,1555.55
  other v1: 4327.24,785 5311.5,785 7280,785 4327.24,825 5311.5,825 4640,1175 4660,1175 5000.39,1175 5025.39,1175 6610,1175 6630,1175 6970,1175 6995,1175 4640,1195 4660,1195 6610,1195 6630,1195 5000.39,1200 5025.39,1200 6970,1200 6995,1200 2480,1210 2500,1210 2725,1225 2480,1230 2500,1230 2930,1245 2725,1250 2930,1270 2725,1275 2930,1295 2725,1300 2930,1320 2725,1325 2930,1345 2725,1350 2930,1370 2930,1395 7285,1542.2 7285,1574.27
25MHz.1: C127.1.1 R119.2 U19.1.9 | length 2304
  Top Layer w6.45: C127.1.1@1060,1860 C127.1.1@1060,1863.62 v1(1060,1905) 1060,1970 1090,2000 1360,2000 1380,1980 1380,1550 1315,1485 1315,870 1430,755 1430,502.44 1612.44,320 R119.2@1616.38,320
  Bottom Layer w6.45: v1(1060,1905) 1060,1902.48 1081.1,1881.38 U19.1.9@1081.1,1874.49
25MHz.2: C127.2.1 R118.2 U19.2.9 | length 1166.2
  Top Layer w6.45: C127.2.1@1060,682.52 v1(1060,725) 1060,810 1125,875 1275,875 1400,750 1400,455 1416.03,438.97 ; 1417.5,437.5 1570,285 R118.2@1616.38,285
  Bottom Layer w6.45: v1(1060,725) 1060,721.38 1081.1,700.28 U19.2.9@1081.1,693.39
+3V3_XDS110: C145.2 C146.1 C149.2 C150.2 C151.2 C152.2 C153.2 C154.1 C155.1 C156.2 D30.2 R194.2 R197.2 R198.2 R199.2 R200.2 R208.1 R211.2 U29.1 U30.7 U30.8 U30.9 U30.16 U30.26 U30.28 U30.39 U30.47 U30.51 U30.52 U30.69 U30.79 U30.90 U30.101 U30.113 U30.122 | length 1307.5
  Top Layer w6: v1(1670,1780) 1689.69,1780 C153.2@1690,1780.31 ; R197.2@1768.62,2035 R198.2@1768.62,1995 R199.2@1768.62,1955 R200.2@1768.62,1915 v1(1795,1915) ; v1(1920,1555) D30.2@1920,1583.35 ; v1(2045,1560) 2045,1575.32 C151.2@2049.69,1580 ; v1@2065,2065 2065,2045 2068.62,2048.62 C154.1@2095,2048.62 ; C156.2@2149.69,1825 v1(2170,1825) ; C156.2@2153.62,1825 C155.1@2153.62,1855 ; v1(2595,1960) 2581.38,1960 C146.1@2575,1953.62 R194.2@2615,1953.62
  Top Layer w8: v1@1750,1555 C152.2@1750,1585.31
  Bottom Layer w6: U30.47@1611.85,1791.38 1658.62,1791.38 v1(1670,1780) ; U30.51@1611.85,1854.37 1579.86,1854.37 1575.59,1858.63 1575.59,1864.46 1575,1865.05 v1(1575,1870) 1575.12,1870.12 U30.52@1611.85,1870.12 ; R211.2@1715,2196.38 1715,2200.32 1734.68,2220 1737.68,2220 v1(1738.82,2221.14) ; R211.2@1720,2195 1720,2187.44 1733.9,2173.54 U30.69@1733.9,2118.15 ; v1@1740.32,2220 1760,2239.68 R208.1@1760,2243.62 ; v1(1880,2190) 1880.31,2189.69 C150.2@1880.31,2170 1891.38,2158.94 U30.79@1891.38,2118.15 ; v1(1920,1555) 1922.87,1552.13 U30.16@1922.87,1511.85 ; v1(2045,1560) 2045,1556.75 2048.86,1552.89 U30.8@2048.86,1511.85 ; U30.90@2064.61,2118.15 2064.8,2117.95 2064.8,2070.2 v1(2065,2070) ; v1(2170,1825) 2187.87,1807.13 U30.113@2218.15,1807.13 ; v1(2170,1995) 2171.1,1996.1 U30.101@2218.15,1996.1 ; v1(2180,1665) 2180.39,1665.39 U30.122@2218.15,1665.39 ; U29.1@2583.39,1937.87 U29.1@2584.87,1937.87 ; v1(2595,1960) 2587.78,1952.78 2587.78,1940.78 U29.1@2584.87,1937.87 ; C145.2@2625,1949.69 2613.19,1937.87 U29.1@2584.87,1937.87
  Bottom Layer w8: U30.39@1611.85,1665.39 1650.39,1665.39 v1(1660,1675) ; U30.28@1733.9,1511.85 1733.96,1511.91 1733.96,1543.96 v1(1750,1560) 1765.33,1544.67 1765.33,1511.91 U30.26@1765.39,1511.85
+5V0_USB: C144.1 D31.2 J7.1 R201.1 U29.4 U29.6 | length 752.6
  Top Layer w6: R201.1@2160,2238.62 2160,2234.68 2179.68,2215 2485,2215 2511.18,2188.82 J7.1@2511.18,2125 2511.18,2053.82 2528.31,2036.69 D31.2@2528.31,2000 2515,1986.69 C144.1@2515,1953.62 2513.62,1955 v1(2490,1955)
  Bottom Layer w6: v1(2490,1955) v1@2490,1951.54 ; U29.4@2506.61,1886.69 2493.51,1886.69 2490,1890.21 v1@2490,1951.54 ; U29.6@2506.61,1937.87 2503.66,1937.87 v1@2490,1951.54
\Fault: U1.1.20 U1.2.20 U1.3.20 U1.4.20 U1.5.20 U1.6.20 U1.7.20 U1.8.20 U12.G1 | length 6982
  Top Layer w4: U12.G1@3293.11,410.43 3308.92,410.43 3325.49,427 3353.79,427 3360.79,420 3389.16,420 3406.16,403 3408.31,403 3494,317.31 3494,233.95 3583.95,144 3876.63,144 4005.63,273 4095.24,273 v1(4107.24,285) ; v1(4110,1020) 4249.3,1020 v1(4304.17,1074.88) 4326.97,1097.67 v1(4377.48,1097.67) 4403.45,1097.67 4455.07,1046.05 4495.26,1046.05 4529.31,1012 4671.99,1012 4726.99,957 4783,957 4820,920 5135.87,920 5240.16,1024.29 v1(5240.16,1070) ; v1(5274,1045) 5330.28,1045 5345.28,1060 5448.69,1060 5459.37,1049.31 5598.16,1049.31 5620.47,1027 5753,1027 5887,893 5928,893 6064,1029 6249,1029 v1(6270,1050) ; v1(6360,1110) 6361.66,1108.34 6361.66,1098.44 6427.1,1033 6752,1033 6830,955 6915,955 v1(6920,960)
  Layer 2 w4: v1(6270,1050) 6300,1050 v1(6360,1110) ; v1(6920,960) 6920,1095 6979,1154 7174,1154 7223.94,1203.94 7315,1203.94 ; v1(7245,1045) 7315,1115 7315,1203.94 ; v1(7335,1270) 7335,1233.11 7315,1213.11 7315,1203.94
  Bottom Layer w4: v1(4107.24,285) 4107.24,358.35 4060,405.6 4060,886.96 4071,897.96 4071,998.31 4092.69,1020 v1(4110,1020) ; U1.7.20@4297.72,1015.3 4297.72,1064.63 4304.17,1071.09 v1(4304.17,1074.88) ; U1.8.20@4363.7,1346.91 4363.7,1278.79 4377.48,1265.01 v1(4377.48,1097.67) ; v1(5240.16,1070) 5242.84,1067.32 5251.67,1067.32 5272.8,1046.2 5272.8,1043.8 5281.97,1034.63 U1.5.20@5281.97,1015.3 U1.5.20@5280.94,1016.32 ; U1.6.20@5347.95,1346.91 5347.95,1214.39 5400,1162.34 v1(5400,1060) ; U1.3.20@6266.22,1015.3 6266.22,1033 6268.22,1035 6268.22,1048.22 v1(6270,1050) ; U1.4.20@6332.2,1346.91 6332.2,1340.22 6360,1312.42 v1(6360,1110) ; v1(7245,1045) 7245,1041.21 7250.47,1035.74 U1.1.20@7250.47,1015.3 ; U1.2.20@7316.46,1346.91 7316.46,1288.54 v1(7335,1270)
\FLT: R29.1 U10.2 U11.2 U12.G2 | length 5546
  Top Layer w4: U12.G2@3267.52,410.43 3279.91,422.82 3310,422.82 3322.18,435 3357.1,435 3360.1,432 3388.47,432 3409.47,411 3411.63,411 3502,320.63 3502,237.27 3587.27,152 3873.31,152 4002.31,281 4082.03,281 4101.03,300 4127.16,300 4163.16,264 4205.79,264 4227.79,242 4548.04,242 4570.04,264 4655.47,264 4669.47,250 v1(4930,250) ; v1@4931.34,250 6034.49,250 6060.49,224 6859,224 v1(6870,235)
  Bottom Layer w4: U11.2@4898.9,1055.83 4898.9,1025.84 4901.59,1023.14 4901.59,977.97 R29.1@4893.62,970 4897.56,970 4907.37,960.19 4930,937.56 v1(4930,250) ; U10.2@6868.9,1055.83 6868.9,1036.1 6875,1030 6875,243.79 6870,238.79 v1(6870,235)
\POR: R93.1 U12.V3 U20.4 | length 1863.7
  Top Layer w3.5: 3254.72,754.72 3255,755
  Top Layer w4: R93.1@2053.62,300 v1(2085,300) ; 3254.72,711.38 3254.72,754.72 ; 3255,755 3262.6,762.6
  Top Layer w5: U12.V3@3241.93,689.55 U12.V3@3241.93,691.93 3254.72,704.72 3254.72,711.38 ; 3262.6,762.6 U20.4@3262.6,805.87 3283.08,805.87 3289.44,812.23 3289.44,824.44 v1(3290,825)
  Bottom Layer w8: v1(2085,300) 2368.03,300 2639.01,570.99 2684.01,570.99 2708,594.97 2708,734.97 2872.03,899 3216,899 3220,895 3245,895 3255,905 3315.63,905 3320.31,900.31 3320.31,900 3325,895.31 3325,885 3290,850 v1(3290,825)
\WARMRST: C167.2 C169.1.2 C169.2.2 R113.2 U12.G3 U17.2 U18.2 U26.1.1 U26.2.1 | length 5590.9
  Top Layer w6: U12.G3@3241.93,410.43 3243.42,408.94 3243.42,391.58 v1(3245,390)
  Layer 2 w5: v1(950,295) 950,363.08 925,388.08 v1(925,880) 925,1445 v1(950,1470) ; v1(2245,860) 2290,905 2620,905 2690,835 3117.73,835 3138.23,855.5 3709.5,855.5 3730,835 3770,835 3885,720 v1(3885,500) 3885,470 3795,380 3650,380 3649.5,379.5 3482.72,379.5 3452.22,410 v1(3345,410)
  Bottom Layer w5: v1(925,880) 1145,880 1165,860 U17.2@2205.87,860 v1(2245,860) ; v1(950,295) 950.31,295.31 C169.2.2@975,295.31 ; v1(950,1470) 973.6,1470 C169.1.2@974.32,1470.72 976.19,1472.6 U26.1.1@1015.87,1472.6 ; C169.2.2@976.76,297.08 982.34,291.5 U26.2.1@1015.87,291.5 ; v1(3245,390) 3325,390 v1(3345,410) 3347.49,407.51 3347.49,402.83 C167.2@3370.31,380 ; R113.2@3843.62,405 3865,405 3885,425 v1(3885,500) U18.2@3885,545.87
CS1: U1.1.1 U12.F1 | length 5376.3
  Top Layer w4: U12.F1@3293.11,384.84 3375.16,384.84 3408,352 3408,181.63 3461.63,128 3883.25,128 3988.25,233 4080.41,233 4095.41,248 4199.16,248 4221.16,226 4554.67,226 4576.67,248 4648.84,248 4670.84,226 5050.21,226 5058.21,234 6027.87,234 6036.65,225.21 6036.65,219.34 6039,217 6044.87,217 6053.87,208 7333,208 v1(7335,210)
  Bottom Layer w4: v1(7335,210) 7337.53,212.53 7337.53,235.15 7551,448.63 7551,935.31 7501.31,985 7425.86,985 7421.65,989.21 U1.1.1@7355.3,989.21
CS2: U1.2.1 U12.F2 | length 6071.2
  Top Layer w4: U12.F2@3267.52,384.84 3280.72,398.04 3335.74,398.04 3338.79,395 3405,395 3486,314 3486,230.64 3580.64,136 3879.94,136 4008.94,265 4047.43,265 4056.43,256 4202.48,256 4224.47,234 4551.35,234 4573.35,256 4652.15,256 4674.15,234 5046.9,234 5054.9,242 6031.18,242 6057.18,216 7216,216 7255,255 v1(7470,255) ; v1(7189.04,1379.8) 7191.72,1377.12 7191.72,1371.2 7222.32,1340.6 7252.92,1310 v1(7510,1310)
  Bottom Layer w4: v1(7189.04,1379.8) 7192.83,1379.8 7196.91,1375.72 7208.91,1375.72 U1.2.1@7211.63,1372.99 ; v1(7470,255) 7471.63,256.63 7471.63,266.58 7624,418.95 7624,864.69 7654,894.69 7654,958.73 7499,1113.73 7499,1225.16 7525,1251.16 7525,1295 v1(7510,1310)
CS3: U1.3.1 U12.E2 | length 4707.3
  Top Layer w4: U12.E2@3267.52,359.25 3279.91,371.64 3301.64,371.64 3306.84,376.84 3371.84,376.84 3400,348.69 3400,178.31 3458.31,120 3886.57,120 3991.57,225 4084.73,225 4099.73,240 4195.85,240 4217.85,218 4557.98,218 4579.98,240 4645.53,240 4668.53,217 5052.53,217 5061.53,226 5992,226 6018,200 6630,200 v1(6650,180)
  Bottom Layer w4: U1.3.1@6371.04,989.21 6400.79,989.21 6450,940 6567.63,940 6630,877.63 6630,271.31 6650,251.31 v1(6650,180)
CS4: U1.4.1 U12.D1 | length 4584.8
  Top Layer w4: 3306,334.69 3294.14,334.69 U12.D1@3293.11,333.66 3312.82,333.66 3329.15,350 3362.37,350 3376,336.37 3376,168.37 3448.37,96 3896.51,96 4001.51,201 4135.38,201 4158.39,224 4189.22,224 4211.22,202 4552.57,202 4581.57,173 4642.79,173 4670.79,201 5501.47,201 5515.47,187 5578,187 5600,209 5609,218 5977,218 5995,200 v1(5995,179) ; v1(5930,1350) 6175,1350 v1(6200,1375)
  Bottom Layer w4: v1(5930,1350) 5930,1325.2 5947,1308.2 5947,1295.77 5945,1293.77 5945,1265 5930,1250 5930,1202.53 5948,1184.53 5948,1132.32 5980,1100.32 5980,918.79 6002,896.79 6002,188.34 5995,181.34 v1(5995,179) ; v1(6200,1375) 6201,1374 6226.38,1374 U1.4.1@6227.38,1372.99
CS5: U1.5.1 U12.D2 | length 3578.8
  Top Layer w4: U12.D2@3267.52,333.66 3279.91,346.05 3313.89,346.05 3325.84,358 3365.69,358 3384,339.69 3384,171.69 3451.69,104 3893.2,104 3998.2,209 4132.07,209 4155.07,232 4192.53,232 4214.53,210 4555.88,210 4584.88,181 4639.47,181 4667.47,209 5504.79,209 5518.79,195 5564.79,195 v1(5575.05,205.26)
  Bottom Layer w4: U1.5.1@5386.79,989.21 5535.23,989.21 5590.63,933.81 5590.63,220.84 v1(5575.05,205.26)
CS6: U1.6.1 U12.C2 | length 4863.5
  Top Layer w4: U12.C2@3267.52,308.07 3279.91,320.46 3333.33,320.46 3333.79,320 3360,320 3368,312 3368,165.06 3445.06,88 3899.82,88 3987.52,175.7 3999.89,175.7 v1(4002.52,178.32) ; v1(4020,2115) 4021.21,2115 4031.21,2125 4619.43,2125 4676.43,2068 4733,2068 4766,2101 4941.63,2101 4952.63,2090 v1(4985,2090)
  Bottom Layer w4: v1(4002.52,178.32) 4002.52,217.62 3979,241.14 3979,894.94 3972.05,901.89 3972.05,912.15 3988.08,928.18 3988.08,1102.34 4058,1172.26 4058,1244.2 4014,1288.2 4014,1399 4030,1415 4030,1445 4006,1469 4006,2101 v1(4020,2115) ; v1(4985,2090) 4985,2050 5024.22,2010.78 5024.22,1529.56 5024.83,1528.96 5024.83,1517.65 5169.48,1372.99 U1.6.1@5243.13,1372.99
CS7: U1.7.1 U12.C1 | length 2617.9
  Top Layer w4: U12.C1@3294.98,309.94 U12.C1@3293.11,308.07 3294.98,306.2 3305.11,306.2 3326.31,285 3347.66,285 3360,272.66 3360,161.75 3441.75,80 3903.14,80 3980.14,157 4002.41,157 4017.21,171.8 4017.21,172.42 4037.79,193 4138.7,193 4161.7,216 4185.91,216 4207.91,194 4549.25,194 4578.25,165 4656,165 v1(4669,178)
  Bottom Layer w4: U1.7.1@4402.54,989.21 4484.73,989.21 4558.78,915.16 4604.8,915.16 4648.57,871.39 4648.57,222.96 4669,202.53 v1(4669,178)
CS8: U1.8.1 U12.B2 | length 2471.2
  Top Layer w4: U12.B2@3267.52,282.48 3255,269.96 3255,230 3425,60 3425.65,60 3429.65,56 3913.08,56 3966.08,109 4023.81,109 4075.81,161 4124.39,161 v1(4125.39,160) ; v1(4110,1375) v1(4205,1375)
  Bottom Layer w4: v1(4110,1375) 4110,1372.13 4119.17,1362.96 4119.17,1057.8 4063,1001.63 4063,901.28 4052,890.28 4052,402.28 4092.24,362.04 4092.24,207.09 4095.17,204.16 4095.17,190.21 v1(4125.39,160) ; v1(4205,1375) 4206.22,1373.78 4206.22,1372.99 U1.8.1@4258.88,1372.99
DCDC_PG: R127.1 U20.1 U24.6 | length 2142.6
  Top Layer w6: R127.1@1770,1353.62 1770,1357.56 1785,1372.56 v1(1785,1380) ; U20.1@3337.4,914.13 3338.27,915 v1(3370,915)
  Top Layer w8: R127.1@1770,1353.62 1791.38,1353.62 1805.87,1339.13 U24.6@1820.32,1339.13
  Layer 2 w6: v1(1785,1380) 1739,1334 1739,1076 1849,966 3319,966 v1(3370,915)
DEBUG_ID4: R197.1 U30.63 | length 113
  Top Layer w6: v1(1690,2035) R197.1@1721.38,2035
  Bottom Layer w6: U30.63@1611.85,2043.35 1666.65,2043.35 1675,2035 v1(1690,2035)
DEBUG_ID5: R198.1 U30.62 | length 128.9
  Top Layer w6: v1(1690,1995) R198.1@1721.38,1995
  Bottom Layer w6: U30.62@1611.85,2027.6 1667.4,2027.6 1688.27,2006.73 1688.27,1996.73 v1(1690,1995)
DEBUG_ID6: R199.1 U30.61 | length 153.6
  Top Layer w6: v1(1690,1955) R199.1@1721.38,1955
  Bottom Layer w6: U30.61@1611.85,2011.85 1653.15,2011.85 1670,1995 1670,1960 1675,1955 v1(1690,1955)
DEBUG_ID7: R200.1 U30.60 | length 175.3
  Top Layer w6: v1(1690,1915) R200.1@1721.38,1915
  Bottom Layer w6: U30.60@1611.85,1996.1 1648.9,1996.1 1660,1985 1660,1930 1675,1915 v1(1690,1915)
DIN: R39.2 U1.1.24 U1.2.24 U1.3.24 U1.4.24 U1.5.24 U1.6.24 U1.7.24 U1.8.24 U3.14 U10.8 U11.8 | length 8344.1
  Top Layer w4: v1(4100,1325) 4111.38,1313.62 4274.26,1313.62 4279.34,1308.54 4386.43,1308.54 4396.52,1318.63 v1(4400.31,1318.63) ; v1(4406.38,1066.08) 4434.41,1038.05 4491.95,1038.05 4525.99,1004 4668.67,1004 4723.67,949 4766.67,949 v1(4779.67,936) 4795.67,920 4803.67,912 5139.18,912 5251,1023.81 5251,1054.53 5290,1093.53 v1(5290,1130) v1(5370,1130) 5412.63,1130 5469.31,1073.31 5673.31,1073.31 5690,1090 6043.79,1090 v1@6068.79,1065 ; v1(6070,1065) 6073.79,1065 6085.79,1053 6178,1053 v1(6190,1065) ; v1(6240,1325) 6252.8,1312.2 6287.2,1312.2 6295,1320 v1(6330,1320) ; v1(6345,1065) 6346.26,1063.74 6362.42,1063.74 6418.16,1008 6692,1008 6735.61,964.39 v1(6749.39,964.39) 6789.79,924 7109,924 v1(7155,970) ; v1(7175,1080) 7310,1080 v1(7335,1055) ; v1(7175,1275) 7205,1275 v1(7225,1255)
  Top Layer w8: R39.2@2933.62,195 v1(2955,195) ; v1(6030,1205) 6030.24,1204.76 6058.82,1204.76 U3.14@6059.06,1204.53
  Layer 2 w4: v1(2955,195) 2975,175 2975,115.26 3018.26,72 3934.37,72 3967.37,105 v1(4110,105)
  Bottom Layer w4: v1(4100,1325) 4111.17,1313.83 4111.17,1061.11 4055,1004.94 4055,904.59 4044,893.59 4044,398.97 4084.24,358.73 4084.24,203.78 4087.17,200.85 4087.17,127.83 v1(4110,105) ; v1(4270.47,1313.62) 4285.17,1328.32 4285.17,1346.7 U1.8.24@4284.96,1346.91 ; U1.7.24@4376.46,1015.3 4376.46,1036.16 v1(4406.38,1066.08) 4393.42,1079.04 4393.42,1309.29 4400.31,1316.17 v1(4400.31,1318.63) ; v1(4779.67,936) 4779.67,955.29 4775.23,959.73 4775.23,975.23 4780.79,980.79 U11.8@4780.79,1055.83 ; U1.6.24@5269.61,1346.52 5269.61,1275.39 v1(5270,1275) 5290,1255 v1(5290,1130) ; U1.5.24@5360.71,1015.3 5360.71,1080.71 5367.32,1087.32 5367.32,1127.32 v1(5370,1130) ; v1(6030,1205) 6070,1165 v1(6070,1065) ; v1(6190,1065) 6200,1075 6200,1206.21 6213.79,1220 6221.21,1220 6232,1230.79 6232,1307 v1@6245,1320 ; v1(6240,1325) v1@6245,1320 ; U1.4.24@6253.46,1346.91 6253.46,1328.46 v1@6245,1320 ; v1(6330,1320) 6345,1305 v1(6345,1065) U1.3.24@6344.96,1015.3 ; v1(6749.39,964.39) 6750.09,965.09 6750.09,1055.13 U10.8@6750.79,1055.83 ; v1(7155,970) 7155,971.06 7163.29,979.34 7163.29,1009.35 7175,1021.06 v1(7175,1080) 7184,1089 7184,1186 7145,1225 7145,1265 7155,1275 v1(7175,1275) ; v1(7225,1255) 7237.72,1267.72 U1.2.24@7237.72,1346.91 ; U1.1.24@7329.21,1015.3 7329.21,1045.42 7335,1051.21 v1(7335,1055)
DIO_EN1: U1.1.19 U3.15 | length 3315
  Top Layer w4: v1(5960,2070) 5961.21,2070 5971.21,2060 6062.63,2060 6098.63,2096 6574.94,2096 6599.94,2121 6966.47,2121 6980.47,2107 7040.79,2107 v1@7061.01,2127.22 ; v1(6030,1260) 6030,1230 6034.73,1225.27 6058,1225.27 U3.15@6059.06,1224.21
  Bottom Layer w4: v1(5960,2070) 5960,2030 5980,2010 5980,1984.6 5961,1965.6 5961,1520.69 6045,1436.69 6045,1272.5 6032.5,1260 v1(6030,1260) ; v1@7060.81,2127.02 7011,2077.21 7011,1536.63 7191.63,1356 7220,1327.63 7220,1275 7200,1255 7200,1227.63 7216,1211.63 7216,1079.82 7230.47,1065.34 7230.47,1051.69 7230,1051.21 7230,1038.79 7230.79,1038 U1.1.19@7230.79,1015.3
  other v1: 7060,2130
DIO_EN2: U1.2.19 U3.1 | length 3338.4
  Top Layer w4: U3.1@5940.94,1243.9 5977.06,1243.9 5988.16,1255 v1(5990,1255) ; v1(5960,2005) 6041.57,2005 6108.57,2072 6584.88,2072 6609.88,2097 6956.53,2097 6970.53,2083 7070.63,2083 7108.63,2121 7289,2121 7305,2105 v1(7395,2105)
  Bottom Layer w4: v1(5960,2005) 5960,2002.66 5953,1995.66 5953,1508.31 5995,1466.31 5995,1273.69 5991.31,1270 5991.31,1256.31 v1(5990,1255) ; U1.2.19@7336.14,1346.91 7474.28,1346.91 7565,1437.63 7565,1946.66 7407.44,2104.23 7395.77,2104.23 v1(7395,2105)
DIO_EN3: U1.3.19 U3.2 | length 646.2
  Top Layer w4: U3.2@5940.94,1224.21 5941.34,1224.61 5989.61,1224.61 v1(5990,1225) ; v1(5995,925) 6055,985 v1(6180,985)
  Bottom Layer w4: v1(5990,1225) 5990,1195.32 6002,1183.32 6002,934.34 5995,927.34 v1(5995,925) ; v1(6180,985) 6210.3,1015.3 U1.3.19@6246.54,1015.3
DIO_EN4: U1.4.19 U3.3 | length 626.3
  Top Layer w4: U3.3@5940.94,1204.53 5941.42,1205 v1(5965,1205) ; v1(5970,1335) 5972.34,1335 5979.34,1342 6201.79,1342 6239.58,1304.21 6335.42,1304.21 6346.21,1315 6362.37,1315 6367.32,1319.95 6367.32,1342.32 v1(6370,1345)
  Bottom Layer w4: v1(5965,1205) 5965,1273.69 5973,1281.69 5973,1325.66 5972.68,1325.98 5972.68,1332.32 v1(5970,1335) ; U1.4.19@6351.89,1346.91 6353.8,1345 v1(6370,1345)
DIO_EN5: U1.5.19 U3.4 | length 2854.9
  Top Layer w4: v1(4980,290) 4980,308.94 4995.06,324 5097.55,324 5131.55,290 5481.55,290 5500.55,309 5580.23,309 5589.9,299.34 v1(5940.71,299.34) ; v1(5915,1185) 5915.08,1184.92 5940.87,1184.92 U3.4@5940.94,1184.84
  Bottom Layer w4: v1(4980,290) 4980,308.35 5000.98,329.33 5000.98,862.07 5154.21,1015.3 U1.5.19@5262.28,1015.3 ; v1(5915,1185) 5923.5,1176.5 5923.5,1157.71 5932,1149.21 5932,1019.96 5958.34,993.61 5958.34,863.97 5940,845.63 5940,300.04 v1(5940.71,299.34)
DIO_EN6: U1.6.19 U3.5 | length 2201.9
  Top Layer w4: v1(5580,2093) 5728.16,2093 5739.16,2082 5904.53,2082 v1(5916.54,2070) ; U3.5@5940.94,1165.16 5941.02,1165.08 5969.92,1165.08 v1(5970,1165)
  Bottom Layer w4: U1.6.19@5367.64,1346.91 5446.91,1346.91 5475,1375 5475,1416.83 5593,1534.83 5593,2039.64 5580,2052.64 v1(5580,2093) ; v1(5916.54,2070) 5935.66,2050.88 5935.66,1443.15 5955,1423.8 5955,1263.69 5945,1253.69 5945,1201.79 5956,1190.79 5956,1179 v1(5970,1165)
DIO_EN7: U1.7.19 U3.6 | length 3560.8
  Top Layer w4: v1(4172.11,300) 4184.11,288 4215.73,288 4237.73,266 4538.1,266 4560.1,288 4947.75,288 4991.75,332 5100.86,332 5134.86,298 5478.24,298 5497.24,317 5583.55,317 5593.21,307.34 5902.34,307.34 v1(5915,320) ; v1(5915,1145) 5915.24,1145.24 5940.71,1145.24 U3.6@5940.94,1145.47
  Bottom Layer w4: v1(4172.11,300) 4138.24,333.87 4138.24,361.3 4118.71,380.83 4084,415.54 4084,877.02 4095,888.02 4222.27,1015.3 U1.7.19@4278.03,1015.3 ; v1(5915,320) 5932,337 5932,848.94 5948.51,865.45 5948.51,866.47 5950.34,868.31 5950.34,990.3 5924,1016.64 5924,1109.08 5917.57,1115.51 5917.57,1142.43 v1(5915,1145)
DIO_EN8: U1.8.19 U3.7 | length 3296.3
  Top Layer w4: v1(4720,2085) 4720,2086.99 4742.01,2109 5723.47,2109 5740.47,2092 5773.31,2092 5798.31,2117 5935.66,2117 5942.66,2110 v1(5945,2110) ; U3.7@5940.94,1125.79 5941.34,1125.39 5984.61,1125.39 v1(5985,1125)
  Bottom Layer w4: U1.8.19@4383.39,1346.91 4562.29,1346.91 4688,1472.62 4688,2053 v1(4720,2085) ; v1(5945,2110) 5945,1505 5987,1463 5987,1282 5973,1268 5973,1218.21 5982,1209.21 5982,1192 5985,1189 v1(5985,1125)
DIO_RX1: U1.1.15 U5.11 | length 3453.1
  Top Layer w4: U5.11@5859.06,1145.47 5859.29,1145.24 5884.76,1145.24 v1(5885,1145) ; v1(5904.53,2101) 5915.53,2090 6070,2090 6092,2112 6568.31,2112 6593.31,2137 6980.66,2137 6987.66,2130 v1(6990,2130)
  Bottom Layer w4: v1(5885,1145) 5900,1160 5900,1211.31 5914,1225.31 5914,1440.5 5890.71,1463.79 5890.71,2087.17 v1(5904.53,2101) ; v1(6990,2130) 6990,1860 6995,1855 6995,1530 7204,1321 7204,1281.63 7184,1261.63 7184,1221 7200,1205 7200,1023.43 7179.29,1002.72 7179.29,940.71 7189.63,930.37 7204.49,930.37 U1.1.15@7204.7,930.16
DIO_RX2: U1.2.15 U5.12 | length 3480
  Top Layer w4: v1(5835,1165) 5858.9,1165 U5.12@5859.06,1165.16 ; v1(5870,2060) 5873.64,2060 5882.43,2051.21 6065.15,2051.21 6101.94,2088 6578.25,2088 6603.25,2113 6963.16,2113 6977.16,2099 7064,2099 7102,2137 7295.63,2137 7302.63,2130 v1(7320,2130)
  Bottom Layer w4: v1(5835,1165) 5906,1236 5906,1437.19 5882.71,1460.48 5882.71,2047.3 v1(5870,2060) ; v1(7320,2130) 7320,2100 7338,2082 7407.04,2082 7549,1940.04 7549,1444.25 7536.79,1432.05 U1.2.15@7362.22,1432.05
DIO_RX3: U1.3.15 U5.13 | length 751.2
  Top Layer w4: v1(5850,890) 5863,877 5972,877 6045,950 v1(6165,950) ; U5.13@5859.06,1184.84 5884.84,1184.84 v1(5885,1185)
  Bottom Layer w4: v1(5850,890) 5850,1150 5882.66,1182.66 5885,1182.66 v1(5885,1185) ; v1(6165,950) 6184.84,930.16 U1.3.15@6220.45,930.16
DIO_RX4: U1.4.15 U5.14 | length 905.1
  Top Layer w4: v1(5835,1205) 5835.47,1204.53 U5.14@5859.06,1204.53 ; v1(5890,1325) 5925,1325 5930,1320 5976.21,1320 5985,1328.79 5990.21,1334 6198.47,1334 6236.27,1296.21 6354.89,1296.21 6393.69,1335 6444.34,1385.66 6444.34,1420.66 v1(6430,1435)
  Bottom Layer w4: v1(5835,1205) 5860,1205 5890,1235 v1(5890,1325) ; U1.4.15@6377.97,1432.05 6379.45,1433.52 6428.52,1433.52 v1(6430,1435)
DIO_RX5: U1.5.15 U5.3 | length 2569.3
  Top Layer w4: v1(5040,290) 5108.92,290 5124.92,274 5488.18,274 5507.18,293 5573.61,293 5583.27,283.34 5767.01,283.34 v1(5777,273.34) ; v1(5715,1205) 5715.24,1204.76 5740.71,1204.76 U5.3@5740.94,1204.53
  Bottom Layer w4: v1(5040,290) 5040,313.74 5016.98,336.76 5016.98,855.44 5091.7,930.16 U1.5.15@5236.2,930.16 ; v1(5715,1205) 5715,1186.21 5730,1171.21 5730,1137.31 5775,1092.31 5775,275.34 v1(5777,273.34)
  Bottom Layer w8: U1.5.15@5235.48,930.88 U1.5.15@5236.2,930.16
DIO_RX6: U1.6.15 U5.4 | length 1960.7
  Top Layer w4: v1(5550,2090) 5566,2074 5761.65,2074 v1(5773.31,2062.34) ; U5.4@5740.94,1184.84 5741.02,1184.92 5769.31,1184.92 v1(5769.39,1185)
  Bottom Layer w4: U1.6.15@5393.72,1432.05 5467.59,1432.05 5577,1541.46 5577,2021.79 5545,2053.79 5545,2081.21 5550,2086.21 v1(5550,2090) ; v1(5769.39,1185) 5738,1216.39 5738,1471.69 5763,1496.69 5763,2051.44 5773.31,2061.75 v1(5773.31,2062.34)
DIO_RX7: U1.7.15 U5.5 | length 3289.3
  Top Layer w4: v1(4133.66,400.21) 4133.66,382.31 4211.97,304 4222.36,304 4244.36,282 4531.47,282 4553.47,304 4941.12,304 4985.12,348 5107.49,348 5141.49,314 5471.61,314 5490.61,333 5590.17,333 5599.84,323.34 5743.65,323.34 v1(5756.31,336) ; v1(5715,1165) 5715.08,1165.08 5740.87,1165.08 U5.5@5740.94,1165.16
  Bottom Layer w4: v1(4133.66,400.21) 4132.9,400.96 4121.2,400.96 4100,422.17 4100,870.39 4111,881.39 4159.76,930.16 U1.7.15@4251.95,930.16 ; v1(5715,1165) 5715,1140.99 5767,1088.99 5767,346.69 v1(5756.31,336)
DIO_RX8: U1.8.15 U5.6 | length 3101.3
  Top Layer w4: v1(4655,2115) 4656.21,2115 4666.21,2125 5737.66,2125 5747.66,2115 v1(5750,2115) ; U5.6@5740.94,1145.47 5764.53,1145.47 v1(5765,1145)
  Bottom Layer w4: U1.8.15@4409.47,1432.05 4437.22,1432.05 4506.36,1362.91 4555.67,1362.91 4672,1479.24 4672,2098 v1(4655,2115) ; v1@5755,2111.79 5755,1500 5730,1475 5730,1182.53 5765,1147.53 v1(5765,1145)
DIO_TX1: U1.1.17 U6.15 | length 3304.4
  Top Layer w4: v1(6020,2075) 6022.34,2075 6029.34,2082 6073.31,2082 6095.31,2104 6571.63,2104 6596.63,2129 6969.79,2129 6983.79,2115 7010,2115 v1(7025,2130) ; v1(6215,1235) 6225.79,1224.21 U6.15@6259.06,1224.21
  Bottom Layer w4: v1(6020,2075) 6020,1518.84 6198,1340.84 6198,1252 v1(6215,1235) ; v1(7025,2130) 7003,2108 7003,1533.31 7188.31,1348 7212,1324.31 7212,1278.31 7192,1258.31 7192,1224.31 7208,1208.31 7208,1020.12 7187.29,999.41 7187.29,971.87 7189.63,969.53 U1.1.17@7204.7,969.53
DIO_TX2: U1.2.17 U6.1 | length 3344
  Top Layer w4: v1(5985,2030) 6055.25,2030 6105.25,2080 6581.57,2080 6606.57,2105 6959.85,2105 6973.85,2091 7067.31,2091 7105.31,2129 7292.31,2129 7306.31,2115 7340,2115 v1(7355,2130) ; U6.1@6140.94,1243.9 6141.5,1244.45 6174.45,1244.45 v1(6175,1245)
  Bottom Layer w4: v1(5985,2030) 6002,2013 6002,1514.21 6096.21,1420 6175,1341.21 v1(6175,1245) ; v1(7355,2130) 7355,2105 7370,2090 7410.35,2090 7557,1943.35 7557,1440.94 7508.74,1392.68 U1.2.17@7362.22,1392.68
DIO_TX3: U1.3.17 U6.2 | length 353.5
  Top Layer w4: v1(6120,1225) 6120.79,1224.21 U6.2@6140.94,1224.21
  Bottom Layer w4: v1(6120,1225) 6134.61,1210.39 6134.61,995.39 6160.47,969.53 U1.3.17@6220.45,969.53
DIO_TX4: U1.4.17 U6.3 | length 516.5
  Top Layer w4: U6.3@6140.94,1204.53 6141.18,1204.76 6169.76,1204.76 v1(6170,1205) ; v1(6155,1305) 6173,1287 6357,1287 6365,1295 v1@6386.14,1295
  Bottom Layer w4: v1(6155,1305) 6155,1220 v1(6170,1205) ; U1.4.17@6377.97,1392.68 6408.65,1392.68 6410.99,1390.33 6410.99,1312.21 v1(6391.89,1293.11)
DIO_TX5: U1.5.17 U6.4 | length 2875.4
  Top Layer w4: v1(5008.98,309) 5101.23,309 5128.23,282 5484.87,282 5503.87,301 5576.92,301 5586.58,291.34 5785.66,291.34 5811,266 6028.46,266 6035.81,273.34 v1(6037.81,273.34) ; v1(6115,1185) 6115.08,1184.92 6140.87,1184.92 U6.4@6140.94,1184.84
  Bottom Layer w4: v1(5008.98,309) 5008.98,858.75 5088.38,938.16 5198.14,938.16 5229.51,969.53 U1.5.17@5236.2,969.53 ; v1(6037.81,273.34) 6018,293.15 6018,880 6085,947 6085,1155 v1(6115,1185)
  Bottom Layer w8: U1.5.17@5235.48,968.8 U1.5.17@5236.2,969.53
DIO_TX6: U1.6.17 U6.5 | length 2161.1
  Top Layer w4: v1(5560,2060) 5563.34,2060 5569.35,2066 5742.31,2066 5821.11,1987.2 5958,1987.2 v1(5983,1962.2) ; U6.5@6140.94,1165.16 6141.22,1164.88 6169.72,1164.88 v1(6170,1164.61)
  Bottom Layer w4: U1.6.17@5393.72,1392.68 5447.31,1392.68 5467,1412.36 5467,1420.14 5585,1538.14 5585,2035 v1(5560,2060) ; v1(5983,1962.2) 5994,1951.2 5994,1510.9 6122.43,1382.47 6122.43,1299.21 6142.61,1279.04 6142.61,1192 v1(6170,1164.61)
DIO_TX7: U1.7.17 U6.6 | length 3609.1
  Top Layer w4: v1(4155.07,339.69) 4198.76,296 4219.04,296 4241.04,274 4534.78,274 4556.78,296 4944.44,296 4988.44,340 5104.17,340 5138.17,306 5474.93,306 5493.93,325 5586.86,325 5596.53,315.34 5889.12,315.34 5912.64,338.85 v1(6037.81,338.85) ; v1(6115,1145) 6115.24,1145.24 6140.71,1145.24 U6.6@6140.94,1145.47
  Bottom Layer w4: v1(4155.07,339.69) 4155.07,355.78 4092,418.85 4092,873.71 4103,884.71 4187.82,969.53 U1.7.17@4251.95,969.53 ; v1(6037.81,338.85) 6026,350.66 6026,876.69 6115,965.69 v1(6115,1145) v1@6116.61,1146.61
DIO_TX8: U1.8.17 U6.7 | length 3416.4
  Top Layer w4: v1(4694.52,2108.61) 4698.31,2108.61 4706.7,2117 5726.79,2117 5743.79,2100 5770,2100 5795,2125 5995,2125 v1(6005,2115) ; U6.7@6140.94,1125.79 6141.34,1125.39 6169.61,1125.39 v1(6170,1125)
  Bottom Layer w4: U1.8.17@4409.47,1392.68 4462.2,1392.68 4499.96,1354.91 4558.98,1354.91 4680,1475.93 4680,2094.09 v1(4694.52,2108.61) ; v1(6005,2115) 6005,2031.21 6010,2026.21 6010,1517.53 6190,1337.53 6190,1243.26 6192,1241.26 6192,1147 v1(6170,1125)
DOUT: R35.1 U1.1.21 U1.2.21 U1.3.21 U1.4.21 U1.5.21 U1.6.21 U1.7.21 U1.8.21 U2.4 U10.7 U11.7 | length 7907.9
  Top Layer w4: R35.1@3112.72,200 3148.69,200 3170,178.69 v1(3170,175) ; v1(4030,1350) 4260,1350 4290.31,1319.69 4334.67,1319.69 4342.25,1327.27 v1(4344.02,1327.27) ; v1(4317.24,1043.27) 4344.19,1043.27 4358.73,1057.8 v1(4359.47,1057.8) 4395.22,1022.05 4485.32,1022.05 4519.37,988 4658.21,988 4704.65,941.56 4704.65,923.02 4739.98,887.7 4757.67,870 v1(4800,870) ; v1(4800,990) 4800,973.94 4829.94,944 5125.93,944 5200.18,1018.25 5200.18,1084.02 5277.16,1161 5317.79,1161 5326.79,1170 v1(5330,1170) ; v1(5300,1060) 5300,1063.79 5306.69,1070.48 5306.69,1071.69 5310,1075 v1(5340,1075) 5445,1075 5462.69,1057.31 5601.47,1057.31 5623.79,1035 5756.31,1035 5850.61,940.71 U2.4@5874.41,940.71 5890.71,940.71 5987,1037 6233.21,1037 6263.39,1067.18 6263.39,1078.39 v1(6265,1080) 6268.41,1080 6298.41,1110 v1(6325,1110) 6338.79,1110 6423.79,1025 6731.21,1025 6770,986.21 6770,985 6771.89,983.11 v1(6773.11,983.11) 6816.21,940 7092.47,940 7135,982.53 7135,1040 7155,1060 7255,1060 v1(7270,1045) ; v1(7185,1310) 7203.69,1310 7235.69,1278 7287,1278 v1(7300,1265)
  Layer 2 w4: v1(3170,175) 3196.66,175 3199,172.66 3199,172.16 3222.16,149 3249.18,149 3277.18,121 3915.49,121 3957.81,163.32 4029.32,163.32 v1(4031,165)
  Bottom Layer w4: v1(4030,1350) 4030,1283.51 4066,1247.51 4066,1168.94 3996.08,1099.03 3996.08,924.87 3980.05,908.83 3980.05,905.2 3987,898.25 3987,244.45 4031,200.45 v1(4031,165) ; v1(4317.24,1043.27) 4317.32,1043.19 4317.32,1015.37 U1.7.21@4317.4,1015.3 ; U1.8.21@4344.02,1346.91 v1(4344.02,1327.27) 4344.02,1306.7 4350.51,1300.21 4350.51,1268.08 4369.17,1249.42 4369.17,1110.58 4359.84,1101.24 4359.84,1065.16 4357.63,1062.95 4357.63,1059.64 v1(4359.47,1057.8) ; v1(4800,870) 4800.24,870.24 v1@4800.24,990 ; v1(4800,990) v1@4800.24,990 ; U11.7@4800.47,1055.83 4800.24,1055.59 v1@4800.24,990 ; v1(5300,1060) 5300.83,1059.17 5300.83,1016.12 U1.5.21@5301.65,1015.3 ; U1.6.21@5328.27,1346.91 5328.27,1101.73 5340,1090 v1(5340,1075) ; v1(6265,1080) 6285.91,1059.09 U1.3.21@6285.91,1015.3 ; U1.4.21@6312.52,1346.91 6312.52,1312.48 6325,1300 v1(6325,1110) ; U10.7@6770.47,1055.83 6771.79,1054.51 6771.79,984.42 v1(6773.11,983.11) ; v1(7145,1050) 7145,1082.53 7168,1105.53 7168,1179.37 7129,1218.37 7129,1294 7145,1310 v1(7185,1310) ; v1(7270,1045) 7270.08,1044.92 7270.08,1015.37 U1.1.21@7270.16,1015.3 ; U1.2.21@7296.77,1346.91 7296.77,1272.02 7300,1268.79 v1(7300,1265)
EARTH: C140.1.2 C140.2.2 H2.1 J4.1.Shell J4.2.Shell R193.1.1 R193.2.1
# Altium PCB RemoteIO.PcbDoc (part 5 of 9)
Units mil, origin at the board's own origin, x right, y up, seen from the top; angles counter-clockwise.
Board outline 7874.02 x 2362.2 mil, 6 copper layers (Top Layer, GND1, Layer 2, PWR, GND2, Bottom Layer), stack 60.956 mil thick; 686 components, 447 nets, 2681 pads, 1481 vias.

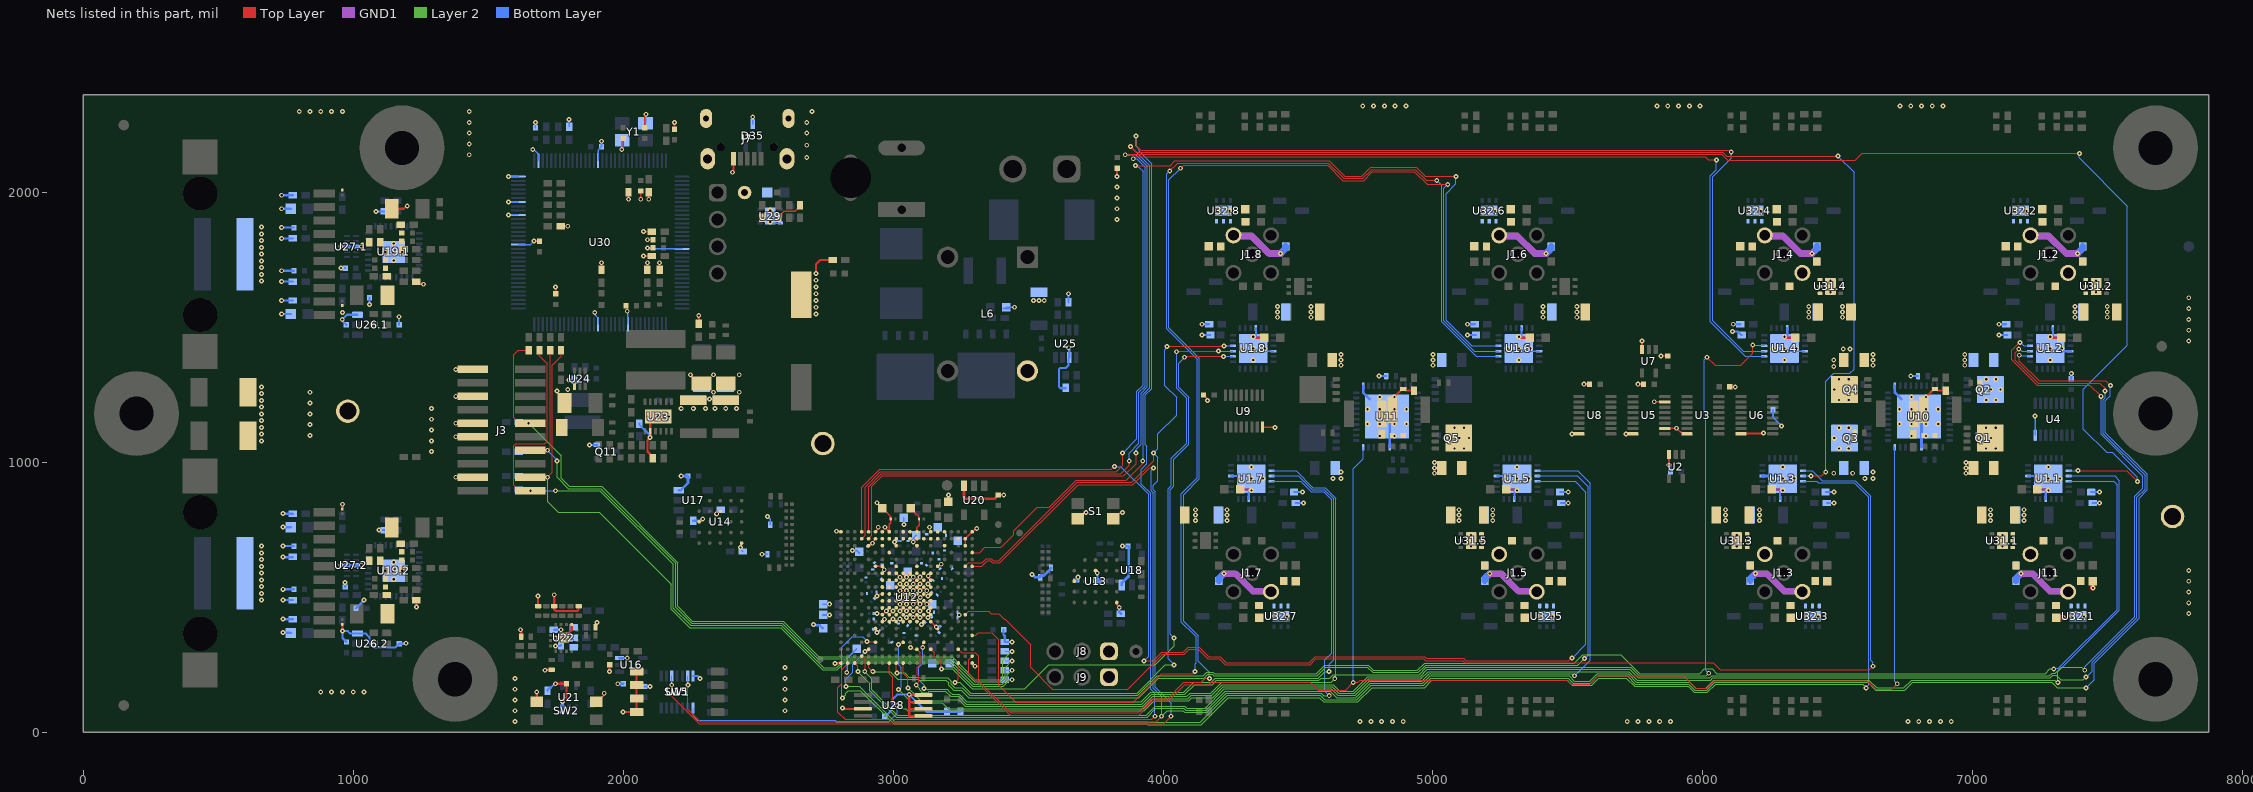
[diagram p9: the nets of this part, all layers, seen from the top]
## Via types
v1: diameter 18, hole 8, Top Layer to Bottom Layer, tented both sides, 1314 vias
v2: diameter 19.68, hole 7.87, Top Layer to Bottom Layer, tented both sides, 133 vias
v3: diameter 19.68, hole 7.87, Top Layer to Bottom Layer, 34 vias

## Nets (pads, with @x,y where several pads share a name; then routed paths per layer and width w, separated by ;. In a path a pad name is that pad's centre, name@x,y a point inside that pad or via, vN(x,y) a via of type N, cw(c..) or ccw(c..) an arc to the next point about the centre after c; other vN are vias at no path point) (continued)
GND: C1.1.1 C1.2.1 C1.3.1 C1.4.1 C1.5.1 C1.6.1 C1.7.1 C1.8.1 C2.1.1 C2.2.1 C2.3.1 C2.4.1 C2.5.1 C2.6.1 C2.7.1 C2.8.1 C3.1 C4.1 C5.1 C6.1 C7.1 C8.1 C9.1 C10.1 C11.1 C12.1 C13.1 C14.1 C15.1 C16.1 C17.1 C18.1 C19.1 C20.1 C21.1 C22.1 C23.1 C24.1 C25.2 C26.2 C27.2 C28.2 C29.2 C30.1 C31.1 C32.2 C33.1 C34.1 C35.2 C36.1 C37.1 C38.1 C39.2 C40.1.1 C40.2.1 C40.3.1 C40.4.1 C40.5.1 C40.6.1 C40.7.1 C40.8.1 C41.2 C42.2 C43.2 C44.1 C45.1 C46.1 C47.1 C48.1 C49.1 C50.1 C51.1 C52.1 C53.1 C54.1 C55.1 C56.1 C57.1 C58.1 C59.1 C60.1 C61.1 C62.1 C63.1 C64.1 C65.1 C66.1 C67.1 C68.1 C69.1 C70.1 C71.1 C72.1 C73.1 C74.1 C75.1 C76.1 C77.1 C78.1 C79.1 C80.1 C81.1 C82.1 C83.1 C84.1 C85.1 C86.1 C87.1 C88.1 C89.1 C90.1 C91.1 C92.1 C93.1 C94.1 C95.1 C96.1 C97.1 C98.1 C99.1 C100.1 C101.1 C102.1 C104.1 C105.1 C106.1 C107.1 C108.2 C109.2 C110.2 C111.2 C113.2 C115.2 C116.2 C118.1 C119.1 C121.1 C122.1 C123.1 C124.1 C125.1 C126.1 C127.1.2 C127.2.2 C128.1.1 C128.2.1 C129.1.2 C129.2.2 C130.1.2 C130.2.2 C131.1.1 C131.2.1 C132.1.2 C132.2.2 C133.1.2 C133.2.2 C134.1.1 C134.2.1 C135.1.1 C135.2.1 C136.1.2 C136.2.2 C137.1.1 C137.2.1 C138.1.2 C138.2.2 C139.1.1 C139.2.1 C140.1.1 C140.2.1 C141.1.1 C141.2.1 C142.1.1 C142.2.1 C143.1 C144.2 C146.2 C147.1 C148.1 C149.1 C150.1 C151.1 C152.1 C153.1 C154.2 C155.2 C156.1 C157.1 C158.2 C159.2 C160.1 C161.1 C162.1 C163.1 C164.2 C165.1.1 C165.2.1 C165.3.1 C165.4.1 C165.5.1 C165.6.1 C165.7.1 C165.8.1 C166.1.1 C166.2.1 C166.3.1 C166.4.1 C166.5.1 C166.6.1 C166.7.1 C166.8.1 C167.1 C168.1.1 C168.2.1 C169.1.1 C169.2.1 C170.1 D26.1.2 D26.2.2 D27.1.2 D27.2.2 D35.3 J1.1.3 J1.2.3 J1.3.3 J1.4.3 J1.5.3 J1.6.3 J1.7.3 J1.8.3 J3.4 J3.10 J3.12 J3.16 J3.20 J7.5 J7.Z1 J7.Z2 J7.Z3 J7.Z4 J8.1 J9.1 L6.4 Q11.2 R1.1.1 R1.2.1 R1.3.1 R1.4.1 R1.5.1 R1.6.1 R1.7.1 R1.8.1 R2.1.1 R2.2.1 R2.3.1 R2.4.1 R2.5.1 R2.6.1 R2.7.1 R2.8.1 R27.1 R30.2 R31.1 R32.1 R33.1 R36.1 R37.2 R38.1 R61.1 R62.1 R83.1 R84.1 R105.1 R106.1 R107.1 R108.1 R111.1 R112.1 R124.1 R128.1 R132.1 R133.1 R135.1 R136.1 R138.1 R142.1 R143.1 R144.1 R163.1.1 R163.2.1 R176.1.1 R176.2.1 R177.1.1 R177.2.1 R178.1.1 R178.2.1 R181.1.1 R181.2.1 R182.1.1 R182.2.1 R191.1.1 R191.2.1 R192.1.1 R192.2.1 R193.1.2 R193.2.2 R195.1 R196.1 R206.1 R207.1 R209.2 R210.1 R213.1 RV3.1.1 RV3.2.1 RV3.3.1 RV3.4.1 RV3.5.1 RV3.6.1 RV3.7.1 RV3.8.1 RV4.1.1 RV4.2.1 RV4.3.1 RV4.4.1 RV4.5.1 RV4.6.1 RV4.7.1 RV4.8.1 RV6.1.2 RV6.2.2 RV6.3.2 RV6.4.2 RV6.5.2 RV6.6.2 RV6.7.2 RV6.8.2 S1.2 S1.4 SW1.1 SW1.2 SW1.3 SW1.4 SW2.1 SW2.3 TP3.1 TP4.1 TP5.1 TP9.1 U1.1.10 U1.1.16 U1.1.25 U1.2.10 U1.2.16 U1.2.25 U1.3.10 U1.3.16 U1.3.25 U1.4.10 U1.4.16 U1.4.25 U1.5.10 U1.5.16 U1.5.25 U1.6.10 U1.6.16 U1.6.25 U1.7.10 U1.7.16 U1.7.25 U1.8.10 U1.8.16 U1.8.25 U2.3 U3.8 U4.8 U5.8 U5.10 U5.15 U6.8 U7.3 U8.8 U9.8 U10.5 U10.21 U10.41 U11.5 U11.21 U11.41 U12.A1 U12.A20 U12.F6 U12.F15 U12.G7 U12.G8 U12.G9 U12.G10 U12.G11 U12.G12 U12.G13 U12.G14 U12.H7 U12.H8 U12.H9 U12.H10 U12.H11 U12.H12 U12.H13 U12.H14 U12.J7 U12.J8 U12.J9 U12.J10 U12.J11 U12.J12 U12.J13 U12.J14 U12.K7 U12.K8 U12.K9 U12.K10 U12.K11 U12.K12 U12.K13 U12.K14 U12.L7 U12.L8 U12.L9 U12.L10 U12.L11 U12.L12 U12.L13 U12.L14 U12.M7 U12.M8 U12.M9 U12.M10 U12.M11 U12.M12 U12.M13 U12.M14 U12.N7 U12.N8 U12.N9 U12.N10 U12.N11 U12.N12 U12.N13 U12.N14 U12.P7 U12.P8 U12.P9 U12.P10 U12.P11 U12.P12 U12.P13 U12.P14 U12.R6 U12.R9 U12.R12 U12.R14 U12.R15 U12.U13 U12.V2 U12.V5 U12.V9 U12.V12 U12.V14 U12.V16 U12.W2 U12.W3 U12.W6 U12.W7 U12.W8 U12.W9 U12.W10 U12.W11 U12.W12 U12.W13 U12.W14 U12.W15 U12.Y1 U12.Y5 U12.Y6 U12.Y7 U12.Y9 U12.Y10 U12.Y11 U12.Y13 U12.Y14 U12.Y15 U12.Y20 U13.B3 U13.C1 U13.E5 U14.B3 U14.C1 U14.E5 U15.7 U16.3 U17.3 U18.3 U19.1.33 U19.2.33 U20.3 U21.3 U22.1 U22.17 U23.8 U23.13 U24.1 U25.2 U26.1.3 U26.2.3 U27.1.3@977.13,1800 U27.1.8@1010,1800 U27.2.3@977.13,618.9 U27.2.8@1010,618.9 U28.1 U28.2 U28.3 U28.4 U28.7 U29.3 U29.7@2545,1912.28 U30.10 U30.17 U30.48 U30.55 U30.58 U30.64 U30.66 U30.80 U30.114 U32.1.1 U32.1.2 U32.1.3 U32.1.7@7390,430 U32.2.1 U32.2.2 U32.2.3 U32.2.7@7176.93,1932.2 U32.3.1 U32.3.2 U32.3.3 U32.3.7@6405.75,430 U32.4.1 U32.4.2 U32.4.3 U32.4.7@6192.68,1932.2 U32.5.1 U32.5.2 U32.5.3 U32.5.7@5421.5,430 U32.6.1 U32.6.2 U32.6.3 U32.6.7@5208.43,1932.2 U32.7.1 U32.7.2 U32.7.3 U32.7.7@4437.24,430 U32.8.1 U32.8.2 U32.8.3 U32.8.7@4224.17,1932.2 Y1.2 Y1.4 | length 13264.5
  Top Layer w6: v1(1670,1820) 1689.69,1820 C153.1@1690,1819.68 ; C152.1@1750,1624.68 v1(1750,1650) ; R210.1@1768.62,1875 v1(1795,1875) ; R195.1@1920,1713.62 v1(1920,1740) ; v1(1995,2160) 1995,2163.25 2000,2168.25 C160.1@2000,2200.32 ; C151.1@2010.32,1580 2015,1575.32 v1(2015,1560) ; v1(2020,1975) C158.2@2020,2001.38 ; v1(2065,1975) C149.1@2065,2005.32 ; v1(2075,1765) C159.2@2106.38,1765 ; v1(2075,1855) C155.2@2106.38,1855 ; C161.1@2080,2239.68 2080,2281.75 2085,2286.75 v1(2085,2290) ; R207.1@2090,1713.62 v1(2090,1740) ; v1(2090,1795) C157.1@2110.32,1795 ; v1(2090,1825) C156.1@2110.32,1825 ; v1(2095,1975) C154.2@2095,2001.38 ; R206.1@2135,1713.62 v1(2135,1740) ; C147.1@2190,2234.68 v1(2190,2260) ; U14.C1@2281.26,780 2283.13,780 2293.13,790 v1(2295,790) ; v1(2346.49,809.68) 2348.4,809.68 2358.09,819.37 U14.B3@2360,819.37 U14.B3@2360,817.37 ; v1@2437.33,690.57 2437.33,699.85 U14.E5@2438.74,701.26 ; C146.2@2575,1906.38 2575,1910.32 2594.68,1930 2635.32,1930 2655,1949.68 R196.1@2655,1953.62 ; U12.V16@2909.25,691.93 2911.36,691.93 2920.34,700.91 v1(2923.51,700.91) ; v1@2925,700 2925,705.57 2934.84,715.41 U12.W15@2934.84,717.52 ; U12.F15@2934.84,384.84 2936.33,383.35 2936.33,376.92 2940,373.25 v1(2940,370) ; U12.R15@2934.84,615.16 U12.R14@2960.43,615.16 ; v1(2940,505) 2943.25,505 2949.55,511.31 2958.94,511.31 U12.L14@2960.43,512.8 ; v1(2940,850.5) C125.1@2960.47,830 2981.71,808.76 2990.52,799.95 2990.52,790.82 C126.1@2991.34,790 2991.34,776.34 2986.02,771.02 U12.Y13@2986.02,743.11 ; U12.G14@2960.43,410.43 2960.43,410.75 2968.57,418.9 v1(2968.57,419.22) ; U12.H14@2960.43,436.02 2960.73,436.02 2974.7,450 v1(2975,450) ; U12.V14@2960.43,691.93 U12.V14@2961.18,691.93 ; U12.W14@2960.43,717.52 U12.W14@2961.46,717.52 ; v1(2970,760) 2975,755 2975,754.13 U12.Y13@2986.02,743.11 ; U12.G13@2986.02,410.43 2988.13,410.43 2997.7,420 v1(3000,420) ; U12.H13@2986.02,436.02 v1(3000,450) ; U12.Y13@2986.02,742.07 U12.Y13@2986.02,743.11 ; U12.P12@3011.61,589.57 3011.61,589.17 3025.55,575.23 v1(3025.55,574.83) ; U12.W12@3011.61,717.07 U12.W12@3011.61,717.52 ; v1(3025,420) 3026.32,420 3035.89,410.43 U12.G11@3037.2,410.43 ; v1(3025.55,474.83) 3025.55,475.19 3037.2,486.84 U12.K11@3037.2,487.2 ; v1(3025.55,524.83) 3025.55,525.78 3037.2,537.43 U12.M11@3037.2,538.39 ; v1(3026.22,450) 3026.22,450.32 3037.2,461.3 U12.J11@3037.2,461.61 ; v1(3026.22,500) 3026.22,500.91 3037.2,511.89 U12.L11@3037.2,512.8 ; v1(3026.22,550) 3026.22,551.5 3037.2,562.48 U12.N11@3037.2,563.98 ; v1(3050,425) 3050,424.11 3062.8,411.32 U12.G10@3062.8,410.43 ; v1(3050,450) 3050.59,450 3062.2,461.61 U12.J10@3062.8,461.61 ; v1(3050,475) 3050.3,475 3062.5,487.2 U12.K10@3062.8,487.2 ; v1(3050,500) U12.L10@3062.8,512.8 ; v1(3050,525) 3050,525.3 3062.8,538.09 U12.M10@3062.8,538.39 ; v1(3050,550) 3050,550.59 3062.8,563.39 U12.N10@3062.8,563.98 ; v1(3050,575) 3050,575.89 3062.8,588.68 U12.P10@3062.8,589.57 ; C123.1@3065.47,830 3095.52,799.95 3095.52,790.82 C124.1@3096.34,790 3096.34,766.34 3095,765 ; v1(3075,425) 3076.18,425 3087.2,436.02 U12.H9@3088.39,436.02 ; v1(3075,450) 3075.89,450 3087.5,461.61 U12.J9@3088.39,461.61 ; v1(3075,475) 3075.59,475 3087.8,487.2 U12.K9@3088.39,487.2 ; v1(3075,500) 3075.3,500 3088.09,512.8 U12.L9@3088.39,512.8 ; v1(3075,525) U12.M9@3088.39,538.39 ; v1(3075,550) 3075,550.59 U12.N9@3088.39,563.98 ; v1(3075,575) 3075,575.59 3088.39,588.98 U12.P9@3088.39,589.57 ; v1(3075,705) 3075.43,705 3087.95,717.52 U12.W9@3088.39,717.52 ; U12.Y9@3088.39,743.11 3088.39,759.3 3094.54,765.46 ; v1(3100,425) 3101.48,425 3112.5,436.02 U12.H8@3113.98,436.02 ; v1(3100,450) 3101.18,450 3112.8,461.61 U12.J8@3113.98,461.61 ; v1(3100,475) 3100.89,475 3113.09,487.2 U12.K8@3113.98,487.2 ; v1(3100,525) 3100.46,525 3113.84,538.39 U12.M8@3113.98,538.39 ; v1(3100,550) U12.N8@3113.98,563.98 ; v1(3100,575) 3100,575.3 3113.98,589.27 U12.P8@3113.98,589.57 ; v1(3100.59,500) 3113.39,512.8 U12.L8@3113.98,512.8 ; v1(3105,400) 3105,400.73 3113.98,409.7 U12.G8@3113.98,410.43 ; v1(3125,475) 3126.18,475 3138.39,487.2 U12.K7@3139.57,487.2 ; v1(3125,525) v1@3130,530 ; v1(3130,425) 3130,425.73 3139.57,435.3 U12.H7@3139.57,436.02 ; v1(3130,505) 3130.89,505 3138.68,512.8 U12.L7@3139.57,512.8 ; v1(3130,550) 3130,548.98 3139.57,539.41 U12.M7@3139.57,538.39 ; v1(3130.25,579.93) 3132.54,577.64 3132.54,573.11 3139.57,566.08 U12.N7@3139.57,563.98 ; v1(3130.75,450) 3130.75,451.4 3139.57,460.22 U12.J7@3139.57,461.61 ; U12.G7@3139.57,410.43 v1(3160,390) U12.F6@3165.16,384.84 ; U12.R6@3165.16,615.16 3167.26,615.16 3172.48,620.37 3176.11,620.37 v1(3178.41,622.67) ; C121.1@3205,854.53 v1(3205,880) ; U12.V2@3267.52,691.93 U12.W2@3267.52,717.52 U12.Y1@3293.11,743.11 U12.Y1@3295,745 ; C37.1@3389.69,880 C37.1@3390,879.68 3409.68,879.68 v1(3410,880) ; U13.C1@3671.26,560 3671.26,560.63 3685,574.37 v1(3685,575) ; S1.2@3684.06,791.46 3686.02,791.46 3707.27,812.7 3712.7,812.7 v1(3715,815) ; U13.B3@3752.11,599.37 U13.B3@3750,599.37 3750,597.92 3756.6,591.32 v1(3756.6,589.87) ; S1.4@3815.94,791.46 3817.91,791.46 3839.16,812.7 3847.7,812.7 v1(3850,815) ; U13.E5@3826.56,478.76 3826.56,476.65 3837.81,465.39 v1(3837.81,462.5) ; C3.1@4150.25,1250.07 C3.1@4150.32,1250 4162.7,1237.62 4162.7,1232.3 v1(4165,1230) ; U9.8@4368.9,1130.94 4369.84,1130 v1(4415,1130) ; v1(5515,1105) 5515.55,1105.55 5540.39,1105.55 U8.8@5540.94,1106.1 ; v1(5715,1105) 5715.55,1105.55 5740.39,1105.55 U5.8@5740.94,1106.1 ; U7.3@5774.41,1419.29 5774.7,1419.59 5774.7,1449.7 v1(5775,1450) ; v1(5820,1225) 5820.39,1224.61 5858.66,1224.61 U5.15@5859.06,1224.21 ; v1(5845,1395) 5869.69,1395 C9.1@5870,1394.68 ; U5.10@5859.06,1125.79 5859.59,1126.32 5902.04,1126.32 v1(5902.57,1126.85) 5916.54,1112.88 5919.4,1112.88 5926.18,1106.1 U3.8@5940.94,1106.1 ; U2.3@5874.41,1029.29 5874.7,1029 5874.7,990.3 v1(5875,990) ; U6.8@6140.94,1106.1 6142.29,1107.44 6223.66,1107.44 v1(6225,1108.79)
  Top Layer w8: v1(960,375) D27.2.2@960,400.24 ; D26.2.2@960,827.56 v1(960,845) ; v1(960,1555) v1@965,1555 ; C132.1.2@1142.91,1940 1187.29,1940 1197.29,1950 v1(1200,1950) ; R178.2.1@1233.62,488.9 1235,487.52 v1(1235,465) ; R178.1.1@1233.62,1670 1241.43,1662.19 1255.1,1662.19 1257.29,1660 v1(1260,1660) ; SW2.3@1679.76,113.46 1679.76,149.76 v1(1680,150) ; R107.1@1685,467.72 v1(1685,505) ; v1@1745,508 R108.1@1745,467.72 1745,455 1750,450 1830.31,450 1835,454.69 R106.1@1835,467.72 ; v1(1750,180) 1755,180 C38.1@1790.32,180 1790.32,130.32 v1(1775,115) ; v2(1780,350) 1809.53,379.53 U22.1@1809.53,399.21 ; R105.1@1897.72,390 1900,392.28 1900,404 v1(1903,407) ; SW2.1@1900.24,113.46 1904.17,113.46 1930,139.29 v1(1930,145) ; v1(1950,225) C31.1@1950,250.32 ; v1(2000,75) SW1.4@2050,75 SW1.3@2050,125 SW1.2@2050,175 SW1.1@2050,225 ; R135.1@2110,1016.38 2110,1020.32 2090,1040.32 2090,1082.49 2099.88,1092.37 v1(2100,1092.37) 2100.24,1092.61 2100.24,1115.04 U23.8@2100.47,1115.28 2100.47,1148.41 2122.06,1170 v2(2130,1170) ; R138.1@2280,1513.62 v1(2280,1545) ; v1(2405,2075) 2405,2077.71 2408.82,2081.52 J7.5@2408.82,2125 ; C116.2@2660,1621.26 C116.2@2660,1670.47 ; v1(2715,1700) 2715,1735 2730,1750 R136.1@2776.38,1750 ; v1(2790,745) 2790.94,744.06 2805.94,744.06 U12.Y20@2806.89,743.11 ; v1(2812.02,90) 2814.82,87.2 U28.7@2887.8,87.2 ; U12.Y15@2934.84,743.11 2934.84,744.67 2943.09,752.92 2943.09,758.09 v1(2945,760) ; v1@3060,133.7 3060,108.11 ; v1@3064.69,138.39 U28.4@3112.2,138.39 ; U28.1@3112.2,61.61 3111.4,60.81 3060.81,60.81 3060,60 3060,82.52 ; U28.2@3112.2,87.2 3064.69,87.2 3060,82.52 ; U28.3@3112.2,112.8 3064.69,112.8 3060,108.11 ; U12.Y1@3293.11,743.11 3294.67,743.11 3304.65,753.09 3308.09,753.09 v1(3310,755) ; v1(3830,2060) C170.1@3830,2090.32 ; C2.7.1@4286.77,900 4320.78,900 4321.85,898.93 4326.17,898.93 v2@4327.24,900 ; v2@4334.17,1462.2 4335.24,1463.28 4339.57,1463.28 4340.64,1462.2 C2.8.1@4374.65,1462.2 ; C163.1@4856.97,1243.19 R37.2@4886.06,1272.28 ; R37.2@4890,1272.28 4893.94,1272.28 4899.84,1266.38 R38.1@4930,1266.38 ; v1(5005.39,980) C19.1@5032.99,980 ; C2.5.1@5271.02,900 5305.03,900 5306.1,898.93 5310.42,898.93 v2@5311.5,900 ; v2@5318.43,1462.2 5319.5,1463.28 5323.82,1463.28 5324.89,1462.2 C2.6.1@5358.9,1462.2 ; v1(5560,1290) C4.1@5580.32,1290 ; C2.3.1@6255.28,900 6289.28,900 6290.35,898.93 6294.68,898.93 v2@6295.75,900 ; v2@6302.68,1462.2 6303.75,1463.28 6308.07,1463.28 6309.15,1462.2 C2.4.1@6343.15,1462.2 ; v2(6826.97,1241.85) 6826.97,1243.19 6856.06,1272.28 R30.2@6860,1272.28 6863.94,1272.28 6869.84,1266.38 R31.1@6900,1266.38 ; v1(6975,980) C14.1@7002.6,980 ; C2.1.1@7239.53,900 7273.53,900 7274.6,898.93 7278.93,898.93 v2@7280,900 ; v2@7286.93,1462.2 7288,1463.28 7292.33,1463.28 7293.4,1462.2 C2.2.1@7327.4,1462.2 ; 3060,82.52 3060,108.11
  Top Layer w10: v1(1380,945) J3.4@1443.5,945 ; v1(1380,1095) J3.10@1443.5,1095 ; v1(1380,1145) J3.12@1443.5,1145 ; v1(1380,1245) J3.16@1443.5,1245 ; v1(1380,1345) J3.20@1443.5,1345 ; v1(1620,380) 1622.28,377.72 R112.1@1622.28,355 ; v1(1710,230) 1712.28,232.28 R111.1@1735,232.28 ; v1@2250,1320 2252.09,1320 2279.17,1292.91 C111.2@2290,1292.91 ; v1(2785,255) 2786.17,256.17 2806.17,256.17 U12.A20@2806.89,256.89 ; v1@2967.22,600.31 v1(2967.22,602.48) ; U20.3@3262.6,914.13 3262.6,870.86 3268.46,865 3375.32,865 C37.1@3390,879.68 ; U12.A1@3293.11,256.89 3293.11,256.28 3303.78,245.61 v1(3303.78,245) ; v1@3685,573.43 v1@3685,574.37 ; v1(5760,1290) C5.1@5780.32,1290 ; C6.1@6099.68,1280 v1(6120,1280)
  Top Layer w20: C166.1.1@7309.53,425 v1(7335,425) ; v1(7445,535) C165.1.1@7445,560.47
  GND1 w25: v1(4226.24,588.13) 4268.04,588.13 4333.28,522.89 4394.36,522.89 J1.7.3@4397.24,520 ; J1.8.3@4264.17,1842.2 4267.06,1839.32 4328.14,1839.32 4393.38,1774.08 v1(4435.17,1774.08) ; v1(5210.49,588.13) 5252.29,588.13 5317.53,522.89 5378.61,522.89 J1.5.3@5381.5,520 ; J1.6.3@5248.43,1842.2 5251.31,1839.32 5312.39,1839.32 5377.63,1774.08 v1(5419.43,1774.08) ; v1(6194.75,588.13) 6236.54,588.13 6301.78,522.89 6362.86,522.89 J1.3.3@6365.75,520 ; J1.4.3@6232.68,1842.2 6235.57,1839.32 6296.64,1839.32 6361.88,1774.08 v1(6403.68,1774.08) ; v1(7179,588.13) 7220.8,588.13 7286.03,522.89 7347.11,522.89 J1.1.3@7350,520 ; J1.2.3@7216.93,1842.2 7219.82,1839.32 7280.9,1839.32 7346.13,1774.08 v1(7387.93,1774.08)
  Bottom Layer w6: v1(1575,1965) 1575.2,1964.8 1611.65,1964.8 U30.58@1611.85,1964.61 ; v1(1575,2060) 1575.55,2059.45 1611.49,2059.45 U30.64@1611.85,2059.09 ; v1@1577.36,1917.36 U30.55@1611.85,1917.36 ; U30.48@1611.85,1807.13 1657.13,1807.13 v1(1670,1820) ; v1(1665,2160) 1668.14,2160 1686.65,2141.49 U30.66@1686.65,2118.15 ; C162.1@1675,2239.68 v1(1675,2260) ; R209.2@1800,2243.62 v1(1800,2270) ; v1(1895,1555) 1897.3,1552.7 1897.3,1545.3 1907.13,1535.47 U30.17@1907.13,1511.85 ; U30.80@1907.13,2118.15 1907.13,2157.45 C150.1@1919.68,2170 1919.68,2189.68 v1(1920,2190) ; v1(1995,2160) 1995,2191.81 Y1.2@1996.69,2193.5 ; v1(2015,1560) 2017.36,1557.64 U30.10@2017.36,1511.85 ; Y1.4@2083.31,2256.5 2083.31,2288.31 v1(2085,2290) ; v1(2090,1795) 2095,1795 2098.62,1791.38 U30.114@2218.15,1791.38 ; v1@2350,810 2348.63,811.37 2348.63,816.19 2357.44,825 C32.2@2361.38,825 ; v1(2435,685) 2435,678.62 C29.2@2443.62,670 ; D35.3@2480,2253.31 v1(2480,2280) ; v1@2515,659.31 2531.94,659.31 R83.1@2534,661.38 ; v1(2535,800) 2545,790 R84.1@2545,770 ; v3(2545,1890.63) 2548.94,1886.69 U29.3@2583.39,1886.69 ; C63.1@2740.47,475 v1(2765,475) ; v1(2828.34,221.66) 2830,223.33 2830,274.53 C91.1@2865.47,310 ; C95.1@2928.66,440 v1(2940,440) ; v1(3040,770) C100.1@3040,794.53 ; v1(3075,705) 3075,719.53 C75.1@3085,729.53 ; v1(3105,400) 3107.3,402.3 3113.44,402.3 3117.27,406.12 C51.1@3118.88,406.12 ; v1(3160,390) 3163.25,390 3167.12,393.88 3169.77,393.88 3171.02,395.13 3172.62,395.13 C99.1@3173.88,393.88 ; C119.1@3419.53,1575 v1(3450,1575) ; U1.7.16@4251.95,949.84 4298.78,949.84 U1.7.25@4301.42,947.2 ; U1.8.25@4371.42,1422.2 4381.26,1412.36 U1.8.16@4409.47,1412.36 ; U1.5.16@5236.2,949.84 5301.65,949.84 v2(5311.5,940) ; v2(5318.43,1422.2) 5328.27,1412.36 U1.6.16@5393.72,1412.36 ; v1(5875,990) 5880.32,984.68 C8.1@5880.32,965 ; C7.1@6260,1195.32 6260,1167.14 v1(6291.52,1135.63) ; v2(6302.68,1422.2) 6312.52,1412.36 U1.4.16@6377.97,1412.36 ; v1(7231,1172.21) 7231.1,1172.11 U4.8@7231.1,1100.94
  Bottom Layer w8: v1(735,1550) R191.1.1@768.5,1550 ; v1(735,1600) R176.1.1@776.38,1600 ; v1(735,1670) C138.1.2@776.38,1670 ; v1(735,1710) C141.1.1@780.32,1710 ; v1(735,1830) C136.1.2@776.38,1830 ; v1(735,1870) C139.1.1@780.32,1870 ; v1(735,1940) R192.1.1@768.5,1940 ; v1(735,1990) R177.1.1@776.38,1990 ; v1(740,370) 741.1,368.9 R191.2.1@768.5,368.9 ; v1(740,420) 741.1,418.9 R176.2.1@776.38,418.9 ; v1(740,490) C138.2.2@776.38,490 ; v1(740,530) C141.2.1@780.32,530 ; v1(740,650) 741.1,648.9 C136.2.2@776.38,648.9 ; v1(740,691.1) 741.11,690 C139.2.1@780.32,690 ; v1(740,761.1) 741.1,760 R192.2.1@768.5,760 ; v1(740,811.1) 741.1,810 R177.2.1@776.38,810 ; v1(955,620) 956.1,618.9 U27.2.3@977.13,618.9 U27.2.8@1010,618.9 1028.9,618.9 v1(1030,620) ; v1(955,1720) C128.1.1@970.32,1720 ; v1(955,1800) U27.1.3@977.13,1800 U27.1.8@1010,1800 v1(1030,1800) ; v1(970,555) 970.32,554.68 C128.2.1@970.32,538.89 ; C169.1.1@974.32,1510.09 961.44,1522.97 961.44,1528.09 v1(959.52,1530) 976.92,1547.4 U26.1.3@1015.87,1547.4 ; C169.2.1@975,334.68 960,349.68 v1(960,375) 980,375 988.7,366.3 U26.2.3@1015.87,366.3 1046.2,366.3 1060,352.5 1060,330 1075,315 1156.42,315 C142.2.1@1170,328.58 1193.58,328.58 v1(1195,330) ; C168.2.1@1010.32,460 v1(1040.19,489.88) ; v1(1060,1585) 1060,1588.79 C168.1.1@1060,1610.32 ; v1(1085,1930) R182.1.1@1116.38,1930 ; v1(1095,750) 1115.28,750 R182.2.1@1116.38,748.9 ; C142.1.1@1170,1509.68 v1(1170,1540) ; C35.2@1720,153.62 1720,157.56 1727.81,165.37 1731.75,165.37 1744.46,178.09 1748.09,178.09 v1(1750,180) ; C39.2@1743.62,380 v1(1770,380) ; v1(1750,320) 1766.38,320 C41.2@1770,323.62 ; U21.3@1774.41,85.71 1774.7,86 1774.7,114.7 v1(1775,115) ; v1(1800,1305) 1818.62,1305 R128.1@1820,1306.38 ; v1(1875,1065) 1902.01,1065 Q11.2@1902.6,1065.59 ; v1(1980,180) C36.1@2000.32,180 ; U16.3@1985.71,275.59 1986.3,275 v1(2015,275) ; R124.1@2060,1143.62 2060,1139.68 2098.09,1101.6 2098.09,1094.28 v1(2100,1092.37) ; C34.1@2080,169.68 2099.68,169.68 v1(2100,170) ; U15.7@2259.06,209.06 2275.94,209.06 v1(2285,200) ; v1(2705,400) 2707.71,400 2710.96,396.75 2728.72,396.75 C44.1@2740.47,385 ; C61.1@2740.47,435 v1(2765,435) ; v1(2850.2,674.21) 2865.32,674.21 C84.1@2875,664.53 ; C143.1@2969.68,60 2975.53,65.85 2978.34,65.85 2989.65,77.16 2998,85.51 2998,123 3015,140 v1(3060,140) 3123.62,76.38 R142.1@3200,76.38 R143.1@3250,76.38 ; v1(3005,705) 3007.71,705 3011.23,708.53 3024.87,708.53 C122.1@3025,708.66 ; C167.1@3409.68,380 3409.68,361.82 3413.62,357.88 R144.1@3413.62,335 v1(3440,335) ; C119.1@3410,1570 C119.1@3430,1570 ; R133.1@3640,1276.38 3638.62,1275 3620,1275 3615,1280 3615,1345 3620,1350 3640,1350 3650,1360 3650,1386.02 U25.2@3652.8,1388.82 3652.8,1422.2 v1(3650,1425) ; R132.1@3650,1593.62 v1(3650,1625) ; v1(4144.17,1472.2) R1.8.1@4175.42,1472.2 ; v1(4144.17,1512.2) R2.8.1@4170.55,1512.2 ; U1.7.10@4317.4,864.7 4317.4,890.85 4321.55,895 U1.7.25@4327.24,895 ; U1.8.25@4334.17,1467.2 4339.87,1467.2 4344.02,1471.35 U1.8.10@4344.02,1497.5 ; R1.7.1@4485.99,890 v1(4517.24,890) ; R2.7.1@4490.87,850 v1(4520,850) ; v1(4800,1320) R33.1@4827.28,1320 ; v1(5128.43,1472.2) R1.6.1@5159.68,1472.2 ; v1(5128.43,1512.2) R2.6.1@5154.8,1512.2 ; U1.5.10@5301.65,864.7 5301.65,890.85 5305.8,895 U1.5.25@5311.5,895 ; U1.6.25@5318.43,1467.2 5324.12,1467.2 5328.27,1471.35 U1.6.10@5328.27,1497.5 ; R1.5.1@5470.25,890 v1(5501.5,890) ; R2.5.1@5475.12,850 v1(5501.5,850) ; v1(6110,1485) 6129.42,1485 6142.21,1472.2 R1.4.1@6143.93,1472.2 ; v1(6112.68,1512.2) R2.4.1@6139.06,1512.2 ; U1.3.10@6285.91,864.7 6285.91,890.85 6290.06,895 U1.3.25@6295.75,895 ; U1.4.25@6302.68,1467.2 6308.37,1467.2 6312.52,1471.35 U1.4.10@6312.52,1497.5 ; R1.3.1@6454.5,890 v1(6485.75,890) ; R2.3.1@6459.37,850 v1(6485.75,850) ; v1(6770,1320) R27.1@6797.28,1320 ; v1(7096.93,1472.2) R1.2.1@7128.18,1472.2 ; v1(7096.93,1512.2) R2.2.1@7123.31,1512.2 ; U1.1.16@7204.7,949.84 7230.85,949.84 7235,945.69 U1.1.25@7235,945 ; U1.1.10@7270.16,864.7 7270.16,890.85 7274.31,895 U1.1.25@7280,895 ; U1.2.25@7286.93,1467.2 7292.62,1467.2 7296.77,1471.35 U1.2.10@7296.77,1497.5 ; R1.1.1@7438.75,890 v1(7470,890) ; R2.1.1@7443.62,850 v1(7470,850)
  Bottom Layer w10: U17.3@2205.87,897.4 2213.74,897.4 2240.32,923.98 C33.1@2240.32,950 v1(2215,950) ; C28.2@2260,783.62 2286.46,783.62 2292.84,790 v1(2295,790) ; v1(3515,585) 3525,575 R62.1@3545,575 3545,578.97 3547.5,581.47 3559.24,581.47 3580.77,603 3582.5,603 3585,605.5 R61.1@3585,610 ; C27.2@3677.81,562.5 3680.97,562.5 3683.47,565 3683.47,573.47 v1(3685,575) ; v1(3756.6,589.87) 3756.6,560.22 C25.2@3756.38,560 3760.31,560 C25.2@3767.13,566.81 ; v1(3837.81,462.5) 3837.81,446.81 3844.63,440 C26.2@3845,440 ; U18.3@3847.6,545.87 3847.6,553.74 3869.43,575.57 ; v1(3850,690) 3870.63,690 3873.13,687.5 3873.13,578.13 3870,575 ; U11.21@4741.42,1284.17 4741.42,1258.58 U11.41@4765,1235 ; U11.5@4839.84,1055.83 U11.41@4839.84,1160.16 ; U1.3.16@6220.45,949.84 6269.84,949.84 U1.3.25@6270,950 ; U10.21@6711.42,1284.17 6711.42,1258.58 U10.41@6735,1235 ; U10.41@6800,1170 6809.84,1160.16 U10.5@6809.84,1055.83 ; U1.2.25@7310,1415 7312.64,1412.36 U1.2.16@7362.22,1412.36 ; C10.1@7365,1309.68 v1(7365,1330)
  Bottom Layer w25: RV3.7.1@4207.24,561.46 4207.24,570 4216.31,579.06 4217.18,579.06 v1(4226.24,588.13) ; v1(4435.17,1774.08) 4444.24,1783.14 4445.11,1783.14 4454.17,1792.2 RV3.8.1@4454.17,1800.75 ; RV3.5.1@5191.5,561.46 5191.5,570 5200.56,579.06 5201.43,579.06 v1(5210.49,588.13) ; v1(5419.43,1774.08) 5428.49,1783.14 5429.36,1783.14 5438.43,1792.2 RV3.6.1@5438.43,1800.75 ; RV3.3.1@6175.75,561.46 6175.75,570 6184.81,579.06 6185.68,579.06 v1(6194.75,588.13) ; v1(6403.68,1774.08) 6412.74,1783.14 6413.61,1783.14 6422.68,1792.2 RV3.4.1@6422.68,1800.75 ; RV3.1.1@7160,561.46 7160,570 7169.06,579.06 7169.94,579.06 v1(7179,588.13) ; v1(7387.93,1774.08) 7396.99,1783.14 7397.87,1783.14 7406.93,1792.2 RV3.2.1@7406.93,1800.75
  other v1: 1600,40 4730,40 4770,40 4810,40 4850,40 4890,40 5720,40 5760,40 5800,40 5840,40 5880,40 6760,40 6800,40 6840,40 6880,40 6920,40 1600,80 2600,80 1600,120 2600,120 880,150 920,150 960,150 1000,150 1040,150 1600,160 2600,160 1600,200 2600,200 2600,240 1750,350 3245,435 7800,440 7800,480 660,490 1745,510 660,515 7800,520 660,540 7800,560 660,565 660,590 7800,600 660,615 660,640 2515,660 660,665 660,690 3135,760 4120,785 4237.24,785 5096.5,785 5221.5,785 6084.25,785 6209.25,785 7065,785 7190,785 4120,805 4237.24,805 5096.5,805 5221.5,805 6084.25,805 6209.25,805 7065,805 7190,805 4120,825 4237.24,825 5096.5,825 5221.5,825 6084.25,825 6209.25,825 7065,825 7190,825 4630,940 4660,940 6600,940 6630,940 5005.39,960 6975,960 4660,965 6630,965 5005.39,1000 6975,1000 1290,1040 660,1080 1290,1080 840,1100 660,1105 1290,1120 660,1130 840,1140 660,1155 1290,1160 660,1180 840,1180 1290,1200 2215,1200 2260,1200 2305,1200 2340,1200 2380,1200 2420,1200 660,1205 840,1220 660,1230 2320,1235 660,1255 840,1260 2335,1260 2430,1260 1755,1265 1795,1270 660,1280 2250,1325 2335,1325 2430,1325 4660,1360 5000,1360 6630,1360 6970,1360 4660,1380 5000,1380 6630,1380 6970,1380 4660,1400 5000,1400 6630,1400 6970,1400 7800,1450 7800,1490 7800,1530 4423.82,1537.8 4548.82,1537.8 5408.07,1537.8 5533.07,1537.8 6392.32,1537.8 6517.32,1537.8 7378.07,1537.8 7498.07,1537.8 2715,1550 4423.82,1557.8 4548.82,1557.8 5408.07,1557.8 5533.07,1557.8 6392.32,1557.8 6517.32,1557.8 7378.07,1557.8 7498.07,1557.8 7800,1570 2715,1575 4423.82,1577.8 4548.82,1577.8 5408.07,1577.8 5533.07,1577.8 6392.32,1577.8 6517.32,1577.8 7378.07,1577.8 7498.07,1577.8 2715,1600 3520,1600 3540,1600 3560,1600 7800,1610 2715,1625 2715,1650 660,1671.79 2715,1675 660,1696.79 660,1721.79 660,1746.79 660,1771.79 660,1796.79 660,1821.79 660,1846.79 660,1871.79 3830,1900 1575,1917.36 3830,1940 3830,1980 3830,2020 2680,2130 1430,2140 2680,2175 1430,2180 1430,2220 2680,2220 1430,2260 2680,2260 800,2300 840,2300 880,2300 920,2300 960,2300 1430,2300 2700,2300 4740,2320 4780,2320 4820,2320 4860,2320 4900,2320 5830,2320 5870,2320 5910,2320 5950,2320 5990,2320 6730,2320 6770,2320 6810,2320 6850,2320 6890,2320
  other v2: 1150,567.4 1118.5,598.9 1150,598.9 1181.5,598.9 1150,630.39 4327.24,896.69 5311.5,896.69 6295.75,896.69 7280,896.69 4283.94,940 4327.24,940 4370.55,940 5268.19,940 5354.8,940 6252.44,940 6295.75,940 6339.06,940 7236.69,940 7280,940 7323.31,940 4327.24,983.31 5311.5,983.31 6295.75,983.31 7280,983.31 4803.03,1098.15 4856.97,1098.15 6773.03,1098.15 6826.97,1098.15 4758.15,1143.03 4803.03,1143.03 4856.97,1143.03 4901.85,1143.03 6728.15,1143.03 6773.03,1143.03 6826.97,1143.03 6871.85,1143.03 2090.63,1170 2169.37,1170 4758.15,1196.97 4803.03,1196.97 4856.97,1196.97 4901.85,1196.97 6728.15,1196.97 6773.03,1196.97 6826.97,1196.97 6871.85,1196.97 4803.03,1241.85 4856.97,1241.85 6773.03,1241.85 4334.17,1378.9 5318.43,1378.9 6302.68,1378.9 7286.93,1378.9 4290.87,1422.2 4334.17,1422.2 4377.48,1422.2 5275.12,1422.2 5361.73,1422.2 6259.37,1422.2 6345.98,1422.2 7243.62,1422.2 7286.93,1422.2 7330.24,1422.2 4334.17,1465.51 5318.43,1465.51 6302.68,1465.51 7286.93,1465.51 1150,1748.5 1118.5,1780 1150,1780 1181.5,1780 1150,1811.5
  other v3: 4415.59,430 4458.9,430 5399.84,430 5443.15,430 6384.09,430 6427.4,430 7368.35,430 7411.65,430 4202.52,1932.2 4245.83,1932.2 5186.77,1932.2 5230.08,1932.2 6171.02,1932.2 6214.33,1932.2 7155.28,1932.2 7198.58,1932.2 2545,1933.94
HSS_C\S\: U10.10 U11.10 U12.B1 | length 5488
  Top Layer w4: U12.B1@3293.11,282.48 3280,269.37 3280,216.96 3431.96,65 3434.12,65 3435.12,64 3909.76,64 3962.76,117 4020.5,117 4080.5,177 4170.2,177 4179.2,186 4545.94,186 4574.94,157 4676.65,157 v1(4704.65,185) 4722.3,185 4730.3,193 5498.16,193 5512.16,179 5581.31,179 5603.31,201 5612.31,210 5927.79,210 5973.79,164 6014.65,164 6042.65,192 6608,192 6640,160 6700,160 v1(6720,180)
  Bottom Layer w4: v1(4704.65,185) 4704.65,977.04 4741.42,1013.8 U11.10@4741.42,1055.83 ; U10.10@6711.42,1055.83 6711.42,189.32 6720,180.73 v1(6720,180)
IO_EN1: U1.1.3 U12.A18 | length 5774.4
  Top Layer w4: U12.A18@2858.07,256.89 2870,244.96 v1(2870,225)
  Layer 2 w4: v1(2870,225) 2905,190 2913,182 2913,154.63 3011.63,56 3941,56 3974,89 4077.22,89 4084.22,82 4160.01,82 4231.01,153 4620.21,153 4644.21,129 4714.94,129 4767.94,182 4962.25,182 4989.25,209 5504.79,209 5523.52,190.26 5581.26,190.26 5608,217 5722.74,217 5753.75,186 5951.79,186 5973.79,164 6010.49,164 6040.49,194 6614.79,194 6643.79,165 6745,165 6774,194 7303.66,194 7312.66,185 v1(7315,185)
  Bottom Layer w4: v1(7315,185) 7315,223.94 7543,451.94 7543,932 7525.16,949.84 U1.1.3@7355.3,949.84
IO_EN2: U1.2.3 U12.A13 U15.8 | length 7225.4
  Top Layer w4: U12.A13@2986.02,256.89 2986.02,217.02 2999.17,203.87 2999.17,115.83 v1(3015,100) ; v1(7170,1420) 7156.92,1406.92 7156.92,1379.39 7242.31,1294 7471,1294 7490,1275 v1(7490,1265)
  Layer 2 w4: v1(3015,100) 3017.21,97.79 3026,97.79 3036.79,87 3046.69,87 3053.69,80 3931.06,80 3968.06,117 4095.2,117 4107.2,129 4183.69,129 4223.69,169 4609.87,169 4626.84,169 4650.84,145 4708.31,145 4761.31,198 4955.63,198 4982.63,225 5726.06,225 5757.06,194 6029.18,194 6037.18,202 7287.1,202 7297.1,212 7309.21,212 7326.21,195 7410,195 v1(7420,205)
  Bottom Layer w4: U15.8@2259.06,90.94 2259.06,60.94 2275,45 2785,45 2790,40 2983.69,40 3015,71.31 v1(3015,100) ; v1(7170,1420) 7173.79,1420 7181.43,1412.36 U1.2.3@7211.63,1412.36 ; v1(7420,205) 7442,227 7442,259.57 7608,425.57 7608,871.31 7638,901.31 7638,952.1 7483,1107.1 7483,1231.79 7491.13,1239.92 7491.13,1252.34 7490.84,1252.63 7490.84,1264.16 v1(7490,1265)
IO_EN3: U1.3.3 U12.U1 | length 5989.4
  Top Layer w4: U12.U1@3293.11,666.34 3321.34,666.34 3340,685 3399.97,685 3446.75,731.78 3446.75,746.75 3534.46,834.46 3579.46,834.46 3671,926 3679,934 3864,934 3923.39,993.39 3923.39,1003.39 v1(3925,1005) ; v1(3880,2170) 3901,2149 6073.63,2149 6087.63,2135 v1(6500,2135) ; v1(6400,950) 6440,950 v1(6455,965)
  Bottom Layer w4: v1(3880,2170) 3950,2100 3950,1276.31 3927,1253.31 3927,1007 v1(3925,1005) ; U1.3.3@6371.04,949.84 6371.12,949.92 6399.92,949.92 v1(6400,950) ; v1(6455,965) 6455,1300 6485,1330 6545,1330 6560,1345 6560,2075 v1(6500,2135)
IO_EN4: U1.4.3 U12.A19 | length 6745.6
  Top Layer w4: U12.A19@2832.48,256.89 2832.48,255.36 2826.78,249.66 2826.78,247.94 2810,231.16 2810,180 2795,165 2795,75 2822,48 3958,48 v1(3970,60) ; v1(3900,2210) 3900,2173.79 3916.79,2157 6095.66,2157 6102.66,2150 v1(6105,2150)
  Bottom Layer w4: v1(3900,2210) 3900,2171.21 3912,2159.21 3912,2153 3958,2107 3958,1273 3935,1250 3935,1065 3940,1060 3940,995 3920,975 3920,920 3955,885 3955,160.13 3968.69,146.44 3968.69,61.31 v1(3970,60) ; v1(6105,2150) 6105,2127.47 6036,2058.47 6036,1525.47 6149.11,1412.36 U1.4.3@6227.38,1412.36
IO_EN5: U1.5.3 U12.A16 | length 3647
  Top Layer w4: U12.A16@2909.25,256.89 2909.25,239.54 2923.79,225 v1(2925,225)
  Layer 2 w4: v1(2925,225) 2989.36,225 3017.36,197 3092.27,197 3095.27,194 3196,194 3207,183 3207,175.47 3225.47,157 3252.49,157 3280.49,129 3910.31,129 3982.45,201.13 4072.18,201.13 4151.9,201.13 4165.9,215.13 4181.71,215.13 4187.7,209.13 4571.14,209.13 4603.01,241 4757.21,241 4776.21,222 4945.69,222 4972.69,249 5537.15,249 v1(5561.5,273.34)
  Bottom Layer w4: U1.5.3@5386.79,949.84 5535.26,949.84 5574.63,910.47 5574.63,286.48 v1(5561.5,273.34)
IO_EN6: U1.6.3 U12.C3 | length 4967.3
  Top Layer w4: U12.C3@3241.93,308.07 3255,295 3305,295 3318.28,281.72 3318.28,190 3433.28,75 3435.43,75 3438.43,72 3906.45,72 3959.45,125 4017.19,125 4077.19,185 4142.01,185 4157.14,200.13 v1(4172.11,200.13) ; v1(4065,2090) 4076,2101 4609.49,2101 4666.49,2044 4742.94,2044 4775.94,2077 4931.69,2077 4978.69,2030 v1(5055,2030)
  Top Layer w6: U12.C3@3241.93,308.07 U12.C3@3241.93,310.18
  Bottom Layer w4: v1(4065,2090) 4022,2047 4022,1499.31 4135.17,1386.14 4135.17,939.51 4076,880.33 4076,412.23 4115.4,372.83 4130.24,357.98 4130.24,264.21 4172.11,222.34 v1(4172.11,200.13) ; v1(5055,2030) 5040.83,2015.83 5040.83,1524.27 5152.74,1412.36 U1.6.3@5243.13,1412.36
IO_EN7: U1.7.3 U12.D8 | length 2667.3
  Top Layer w4: v1(3110,315) 3112.11,317.11 3112.11,331.79 U12.D8@3113.98,333.66
  Layer 2 w4: v1(3115,162) 3117,160 3199.85,160 3210.85,149 3218.85,141 3245.86,141 3273.86,113 3918.8,113 3954.8,149 4077.69,149 4113.82,185.13 4178.33,185.13 4194.33,201.13 4574.46,201.13 4598.33,225 v1(4615,225)
  Bottom Layer w4: v1(3110,315) 3110,256.09 3094.42,240.51 3094.42,195.58 3115,175 v1(3115,162) ; U1.7.3@4402.54,949.84 4501.47,949.84 4552.16,899.16 4598.17,899.16 4632.57,864.76 4632.57,269.92 4615,252.35 v1(4615,225)
IO_EN8: U1.8.3 U12.A3 | length 2370.8
  Top Layer w4: v1(3230,185) 3230,185.07 3241.93,197 U12.A3@3241.93,256.89 ; v1(4050,1410) 4051.18,1411.18 4205.04,1411.18 v1(4206.22,1412.36)
  Layer 2 w4: v1(3230,185) 3247.12,185 3287.12,145 3903.69,145 4008.69,250 v1(4041.21,250)
  Bottom Layer w4: v1(4041.21,250) 4019,272.21 4019,902.53 4031,914.53 4031,1014.88 4087.17,1071.05 4087.17,1237.83 4050,1275 4050,1371.31 v1(4050,1410) ; v1(4206.22,1412.36) U1.8.3@4258.88,1412.36
IO_RX1: U1.1.2 U12.W16 | length 7708.8
  Top Layer w4: U12.W16@2909.25,717.52 2921.64,729.91 2921.64,911.64 2960,950 3855,950 3900,995 v1(3900,1035) ; v1(3860,2140) 3876,2140 3877,2141 6070.31,2141 6091.31,2120 6565,2120 6590,2145 v1(7395,2145) ; v1(7390,970) 7570,970 v1(7610,930)
  Bottom Layer w4: v1(3860,2140) 3898.69,2140 3942,2096.69 3942,1279.63 3919,1256.63 3919,1067.69 3900,1048.69 v1(3900,1035) ; U1.1.2@7355.3,969.53 7355.53,969.76 7389.76,969.76 v1(7390,970) ; v1(7395,2145) 7395,2127.98 7573,1949.98 7573,1434.31 7410,1271.31 7410,1122.63 7495.63,1037 7517.2,1037 7609.2,945 7609.2,930.8 v1(7610,930)
IO_RX2: U1.2.2 U12.C16 | length 6716.5
  Top Layer w4: v1(7171.92,1396.92) 7171.92,1375.71 7245.63,1302 7493,1302 v1(7510,1285)
  Top Layer w6: v1(2896.28,299.1) 2898.28,299.1 2907.25,308.07 U12.C16@2909.25,308.07
  Layer 2 w4: v1(2825,170) 2875,170 3000,45 3005,40 3944.31,40 3947.31,37 4137.64,37 4237.64,137 4582.46,137 4598.46,121 4718.26,121 4771.25,174 4965.57,174 4992.57,201 5501.47,201 5520.21,182.26 5584.58,182.26 5611.31,209 5719.43,209 5750.43,178 5948.47,178 5970.47,156 6013.81,156 6043.81,186 6611.47,186 6640.47,157 6748.31,157 6777.31,186 7292.79,186 7313.79,165 v1(7420,165)
  Bottom Layer w4: v1(2825,170) 2825,197.12 2850,222.12 2850,252.82 v1(2896.28,299.1) ; v1(7171.92,1396.92) 7174.04,1394.8 7209.51,1394.8 U1.2.2@7211.63,1392.68 ; v1(7420,165) 7450,195 7450,256.26 7616,422.26 7616,868 7646,898 7646,955.41 7491,1110.41 7491,1228.47 7510,1247.47 v1(7510,1285)
IO_RX3: U1.3.2 U12.H2 | length 4575.3
  Top Layer w4: U12.H2@3267.52,436.02 3279.91,448.41 3355,448.41 3363.41,440 3391.79,440 3412.79,419 3414.94,419 3510,323.94 3510,240.58 3590.58,160 3870,160 3999,289 4078.72,289 4097.72,308 4130.48,308 4166.48,272 4209.1,272 4231.1,250 4544.72,250 4566.72,272 4965.47,272 4971.47,266 5110.29,266 5118.29,258 6037.81,258 6063.81,232 6617,232 v1(6630,245)
  Bottom Layer w4: U1.3.2@6371.04,969.53 6405.47,969.53 6443,932 6564.31,932 6622,874.31 6622,268 6630,260 v1(6630,245)
IO_RX4: U1.4.2 U12.Y16 | length 5379.7
  Top Layer w4: U12.Y16@2909.25,743.11 2909.25,910.57 2956.69,958 3843,958 3875,990 v1(3875,1005) ; v1(3890,2125) 3891.34,2125 3899.34,2133 6008.21,2133 6019.25,2121.96 6048.04,2121.96 v1(6050,2120)
  Bottom Layer w4: v1(3875,1005) 3875,1035 3911,1071 3911,1259.94 3934,1282.94 3934,2093.37 3902.66,2124.72 3890.28,2124.72 v1(3890,2125) ; v1(6050,2120) 6050,2083.79 6028,2061.79 6028,1522.15 6157.48,1392.68 U1.4.2@6227.38,1392.68
IO_RX5: U1.5.2 U12.B17 | length 3827.7
  Top Layer w4: U12.B17@2883.66,282.48 2896.05,270.09 2896.05,226.05 v1(2895,225)
  Layer 2 w4: v1(2895,225) 2921,199 2921,157.94 3014.94,64 3937.69,64 3970.69,97 4080.53,97 4087.53,90 4156,90 4227,161 4623.53,161 4647.53,137 4711.63,137 4764.63,190 4958.94,190 4985.94,217 5515.66,217 5522.66,210 v1(5525,210)
  Bottom Layer w4: U1.5.2@5386.79,969.53 5536.12,969.53 5582.63,923.02 5582.63,267.63 v1(5525,210)
IO_RX6: U1.6.2 U12.E1 | length 4886.3
  Top Layer w4: U12.E1@3293.11,359.25 3306.52,359.25 3316.12,368.84 3366.16,368.84 3392,343 3392,175 3455,112 3889.88,112 3994.88,217 4109.52,217 4117.52,225 v1(4118.86,225) ; v1(4025,2080) 4054,2109 4612.81,2109 4669.81,2052 4739.63,2052 4772.63,2085 4935,2085 4975,2045 v1(5014.04,2045)
  Bottom Layer w4: v1(4025,2080) 4014,2069 4014,1496 4127.17,1382.83 4127.17,942.82 4068,883.65 4068,408.91 4112.08,364.83 4122.24,354.67 4122.24,257.69 4118.86,254.31 v1(4118.86,225) ; v1(5014.04,2045) 5032.83,2026.21 5032.83,1520.96 5161.11,1392.68 U1.6.2@5243.13,1392.68
IO_RX7: U1.7.2 U12.A11 | length 2705
  Top Layer w4: U12.A11@3037.2,256.89 3038,256.09 3038,219.62 3055,202.62 v1(3055,165)
  Layer 2 w4: v1(3055,165) 3065,155 3066.21,155 3075,146.21 3075,145 3102,118 3189.02,118 3191.02,120 3244.24,120 3268.24,96 3875,96 3924.43,96 3961.43,133 4088.58,133 4100.58,145 4177.06,145 4217.19,185.13 4622.39,185.13 v1(4636.26,199)
  Bottom Layer w4: U1.7.2@4402.54,969.53 4493.1,969.53 4555.47,907.16 4601.48,907.16 4640.57,868.07 4640.57,207.1 4636.26,202.79 v1(4636.26,199)
IO_RX8: U1.8.2 U12.C7 | length 2361.2
  Top Layer w4: U12.C7@3139.57,308.07 3151.96,295.68 3151.96,278.16 3160.03,270.09 3169.48,270.09 3178.36,261.21 3178.36,236.64 v1(3180,235) ; v1(4080,1390) 4082.68,1392.68 4115.4,1392.68 v1(4224.56,1392.68)
  Layer 2 w4: v1(3180,235) 3219.75,235 3293.75,161 3488,161 3577,250 3970.35,250 4041.21,320.86 v1(4041.21,349.28)
  Bottom Layer w4: v1(4041.21,349.28) 4027,363.49 4027,899.22 4039,911.22 4039,1011.57 4095.17,1067.74 4095.17,1241.14 4058,1278.31 4058,1368 v1(4080,1390) ; v1(4224.56,1392.68) U1.8.2@4258.88,1392.68
IO_TX1: U1.1.4 U12.A12 | length 5470.7
  Top Layer w4: U12.A12@3011.61,256.89 3011.61,227.75 3015,224.36 v1(3015,220.57)
  Layer 2 w4: v1(3015,220.57) 3043.21,220.57 3058.79,205 3095.58,205 3098.58,202 3203,202 3215,190 3215,178.79 3228.79,165 3255.8,165 3283.8,137 3907,137 3979.13,209.13 4148.59,209.13 4162.59,223.13 4185.02,223.13 4191.02,217.13 4567.83,217.13 4599.7,249 4760.53,249 4779.53,230 4942.37,230 4969.37,257 5523.94,257 5555.28,288.34 5696.66,288.34 5767,218 5988,218 6005,235 6035,235 6052,218 7268,218 7285,235 v1(7300,235)
  Bottom Layer w4: v1(7300,235) 7302.68,237.68 7317.42,237.68 7535,455.25 7535,917 7521.84,930.16 U1.1.4@7355.3,930.16
IO_TX2: U1.2.4 U12.D11 | length 6409.6
  Top Layer w4: v1(3020.22,325.45) 3022.9,328.12 3029.02,328.12 3034.56,333.66 U12.D11@3037.2,333.66 ; v1(7175,1445) 7173.79,1445 7145,1416.21 7145,1380 7239,1286 7434,1286 v1(7475,1245)
  Layer 2 w4: v1(3020,158.58) 3033.43,145.15 3033.64,145.15 3068.79,110 3182.39,110 3204.39,88 3614.57,88 3927.75,88 3964.75,125 4091.89,125 4103.89,137 4180.37,137 4220.37,177 4609.87,177 4630.15,177 4654.15,153 4705,153 4758,206 4952.31,206 4979.31,233 5729.37,233 5760.37,202 6025.87,202 6033.87,210 7283.79,210 7293.79,220 7306.21,220 7327.21,241 7404,241 v1(7415,230)
  Bottom Layer w4: v1(3020,158.58) 3021.42,160 3025,160 3030,165 3030,240 3020.22,249.78 v1(3020.22,325.45) ; v1(7175,1445) 7187.95,1432.05 U1.2.4@7211.63,1432.05 ; v1(7415,230) 7415,243.89 7600,428.89 7600,874.63 7630,904.63 7630,948.79 7475,1103.79 v1(7475,1245)
IO_TX3: U1.3.4 U12.D15 | length 5314.4
  Top Layer w4: v1(2904,337.3) 2905.82,335.48 2933.02,335.48 U12.D15@2934.84,333.66
  Layer 2 w4: v1(2812.02,128) 2824.24,140.22 2824.24,145.46 2833.79,155 2878.69,155 2998.69,35 3001.69,32 3941,32 3944,29 4140.95,29 4240.95,129 4579.14,129 4595.15,113 4721.57,113 4774.57,166 4968.88,166 4995.88,193 5498.16,193 5516.9,174.26 5587.89,174.26 5614.63,201 5716.12,201 5747.12,170 5945.16,170 5967.16,148 6017.12,148 6047.12,178 6592,178 v1(6605,165)
  Bottom Layer w4: v1(2812.02,128) 2810,130.02 2810,315.51 2848.99,354.5 2886.8,354.5 v1(2904,337.3) ; U1.3.4@6371.04,930.16 6422.15,930.16 6428.31,924 6561,924 6614,871 6614,177.21 6605,168.21 v1(6605,165)
IO_TX4: U1.4.4 U12.C9 | length 4678.8
  Top Layer w4: v1(3065.07,314.41) 3068.86,314.41 3075.19,308.07 U12.C9@3088.39,308.07 3100.78,295.68 3100.78,251.76 3090,240.98 3090,214.3 3095,209.3 3095,187.43 3085.8,178.22 v1(3085.8,175.42) ; v1(6015,1390) 6045,1360 6141.21,1360 6185,1403.79 6185,1430 v1@6180,1435
  Layer 2 w4: v1(3085.8,175.42) 3098.63,162.58 3098.63,157.16 3108.79,147 3129.79,147 3134.79,152 3194.21,152 3213.21,133 3242.55,133 3270.55,105 3922.12,105 3958.12,141 4081,141 4117.13,177.13 4181.64,177.13 4197.64,193.13 4577.77,193.13 4585.77,201.13 4617.18,201.13 4630.05,214 4949,214 4976,241 5732.69,241 5763.69,210 6012.65,210 v1(6021.65,219)
  Bottom Layer w4: v1(6015,1390) 6005,1380 6005,1191.63 6010,1186.63 6010,230.65 v1(6021.65,219) ; v1(6185,1435) 6186.48,1433.52 6225.91,1433.52 U1.4.4@6227.38,1432.05
IO_TX5: U1.5.4 U12.Y17 | length 4408.3
  Top Layer w4: U12.Y17@2883.66,743.11 2883.66,907.6 2950.06,974 3809,974 v1(3820,985) ; v1(3930,265) 3963.69,265 3995.69,297 4075.4,297 4094.4,316 4133.79,316 4169.79,280 4212.42,280 4234.42,258 4541.41,258 4563.41,280 4968.79,280 4974.79,274 5113.61,274 5121.61,266 5503.18,266 5512.18,275 v1(5515.39,275)
  Bottom Layer w4: v1(3820,985) 3843.69,985 3947,881.69 3947,282 v1(3930,265) ; U1.5.4@5386.79,930.16 5526.47,930.16 5566.63,890 5566.63,326.24 v1(5515.39,275)
IO_TX6: U1.6.4 U12.W17 | length 4365.6
  Top Layer w4: U12.W17@2883.66,717.52 2896.05,729.91 2896.05,908.68 2953.37,966 3825.91,966 3850,990.09 v1(3850,1035) ; v1(3898.69,2100) 4026.21,2100 4043.21,2117 4616.12,2117 4673.12,2060 4736.31,2060 4769.31,2093 4938.31,2093 4971.31,2060 v1(5085,2060)
  Bottom Layer w4: v1(3850,1035) 3903,1088 3903,1263.25 3926,1286.25 3926,2078.37 3911,2093.37 3909.1,2093.37 3902.47,2100 v1(3898.69,2100) ; v1(5085,2060) 5085,2032.34 5048.83,1996.17 5048.83,1527.59 5144.29,1432.13 5243.05,1432.13 U1.6.4@5243.13,1432.05
IO_TX7: U1.7.4 U12.R1 U15.6 | length 5337.2
  Top Layer w4: v1(2240,176) 2240,85 2285,40 3975,40 v1(3995,60) ; U12.R1@3293.11,615.16 3328.94,615.16 3348.79,635 3361.21,635 3368.21,628 3395.63,628 3685.63,918 3888.31,918 3950.31,980 v1(3965,980)
  Layer 2 w4: v1@3998.79,60 v1(3995,60) 4016,81 4073.9,81 4080.9,74 4163.32,74 4234.32,145 4585.77,145 4594.77,136 v1(4616,136)
  Bottom Layer w4: U15.6@2239.37,209.06 2239.69,208.74 2239.69,176.31 v1(2240,176) ; v1(3965,980) 3956.05,971.05 3956.05,895.26 3963,888.31 3963,163.44 3995,131.44 v1(3995,60) ; U1.7.4@4402.54,930.16 4509.84,930.16 4548.84,891.16 4594.86,891.16 4624.57,861.44 4624.57,293.48 4600,268.91 4600,152 v1(4616,136)
IO_TX8: U1.8.4 U12.R2 U15.3 | length 4585.6
  Top Layer w4: v1(2180,175) 2180,133.69 2281.69,32 4002.12,32 v1(4030.12,60) ; U12.R2@3267.52,615.16 3279.91,627.55 3330.02,627.55 3345.47,643 3364.53,643 3371.53,636 3392.31,636 3661.81,905.5 3682.31,926 3885,926 3965,1006 v1(3965,1035) ; v1(4015,1430) 4016.02,1431.02 4225.22,1431.02 v1(4226.24,1432.05)
  Bottom Layer w4: v1(2180,175) 2180.16,175.16 2180.16,208.9 U15.3@2180.32,209.06 ; v1(4015,1430) 4015,1426.79 4006,1417.79 4006,1402.31 4006,1284.88 4050,1240.88 4050,1175.57 3980.08,1105.65 3980.08,1050.08 v1(3965,1035) 3980,1020 3980,931.41 3964.05,915.46 3964.05,898.58 3971,891.63 3971,166.76 4030.12,107.63 v1(4030.12,60) ; v1(4226.24,1432.05) U1.8.4@4258.88,1432.05
JTAG_TCK: J3.11 R147.1 R151.1 R203.1 | length 2832.8
  Top Layer w4: v1(1650,1145) 1614,1145 1602,1157 1602,1158 1594,1166 1594,1399 1611.38,1416.38 R203.1@1650,1416.38
  Layer 2 w4: v1(1650,1145) 1770,1025 1770,941.31 1800.31,911 1920.31,911 2202,629.31 2202,466.69 2256.69,412 2593,412 2724.5,280.5 3219.5,280.5 3305,195 3398.69,195 3407,203.31 3407,267 v1(3440,300)
  Bottom Layer w4: R147.1@1613.62,1150 v1@1650,1150 ; R151.1@3413.62,300 v1(3440,300)
JTAG_TDI: J3.3 R148.1 R152.1 R212.1 | length 2869.2
  Top Layer w4: J3.3@1656.5,945 v1(1720,945) 1738,963 1738,1360.34 1767.66,1390 1770,1392.34 R212.1@1770,1416.38
  Layer 2 w4: v1(1720,945) 1720,855 1759,816 1911.63,816 2178,549.63 2178,456.75 2246.75,388 2583.06,388 2739.06,232 2793.82,232 2819.32,257.5 3208.56,257.5 3225.1,240.96 3295.06,171 3408.63,171 3429.95,192.32 3437.32,192.32 v1(3440,195)
  Bottom Layer w4: R148.1@1613.62,950 1690,950 1695,945 v1(1720,945) ; R152.1@3413.62,195 v1(3440,195)
JTAG_TDO: J3.7 R149.1 R153.1 R205.1 | length 2838.3
  Top Layer w4: J3.7@1656.5,1045 v1(1720,1045) 1730,1055 R205.1@1730,1416.38
  Layer 2 w4: v1(1755,1005) 1755,945 1797,903 1917,903 2194,626 2194,463.37 2253.37,404 2589.69,404 2721.19,272.5 3216.19,272.5 3301.69,187 3402,187 3415,200 3415,240 v1(3440,265)
  Bottom Layer w4: R149.1@1613.62,1040 1695,1040 1700,1045 v1(1720,1045) 1720,1042.5 1755,1007.5 v1(1755,1005) ; R153.1@3413.62,265 v1(3440,265)
JTAG_TMS: J3.1 R150.1 R154.1 R204.1 | length 2997.7
  Top Layer w4: v1(1656.5,895) 1614,895 1594,915 1594,1061.48 1602.52,1070 1710.47,1070 1719.54,1079.06 1719.54,1365.46 1690,1395 R204.1@1690,1416.38
  Layer 2 w4: v1(1750,895) 1913.69,895 2186,622.69 2186,460.06 2250.06,396 2586.37,396 2691.19,291.19 2742.37,240 2790.51,240 2815.51,265 3212.37,265 3298.37,179 3405.31,179 3423,196.69 3423,213 v1(3440,230)
  Bottom Layer w4: R150.1@1613.62,900 1647.71,900 1652.71,895 v1(1656.5,895) v1(1750,895) ; R154.1@3413.62,230 v1(3440,230)
L+1: C1.1.2 C14.2 J1.1.1 Q1.5 Q1.6 Q1.7 Q1.8 Q1.9 R155.2 RV1.1.2 RV2.1.2 RV3.1.2 U31.1.1 U31.1.2 U31.1.3 U31.1.7@7110,710
  other v2: 7049.25,1051.61 7084.88,1051.61 7031.44,1090 7067.07,1090 7049.25,1128.39 7084.88,1128.39
  other v3: 7110,688.35 7110,731.65
L+2: C1.2.2 C13.2 J1.2.1 Q2.5 Q2.6 Q2.7 Q2.8 Q2.9 R156.2 RV1.2.2 RV2.2.2 RV3.2.2 U31.2.1 U31.2.2 U31.2.3 U31.2.7@7456.93,1652.2
  other v2: 7049.65,1231.61 7085.28,1231.61 7031.83,1270 7067.46,1270 7103.09,1270 7049.65,1308.39 7085.28,1308.39
  other v3: 7456.93,1630.55 7456.93,1673.86
L+3: C1.3.2 C12.2 J1.3.1 Q3.5 Q3.6 Q3.7 Q3.8 Q3.9 R157.2 RV1.3.2 RV2.3.2 RV3.3.2 U31.3.1 U31.3.2 U31.3.3 U31.3.7@6125.75,710
  other v1: 6485,960 6555,960
  other v2: 6504.72,1051.61 6540.35,1051.61 6486.91,1090 6522.54,1090 6558.17,1090 6504.72,1128.39 6540.35,1128.39
  other v3: 6125.75,688.35 6125.75,731.65
L+4: C1.4.2 C11.2 J1.4.1 Q4.5 Q4.6 Q4.7 Q4.8 Q4.9 R158.2 RV1.4.2 RV2.4.2 RV3.4.2 U31.4.1 U31.4.2 U31.4.3 U31.4.7@6472.68,1652.2
  other v1: 6485,1355 6485,1380 6520,1420 6545,1420
  other v2: 6504.72,1231.61 6540.35,1231.61 6486.91,1270 6522.54,1270 6558.17,1270 6504.72,1308.39 6540.35,1308.39
  other v3: 6472.68,1630.55 6472.68,1673.86
L+5: C1.5.2 C19.2 J1.5.1 Q5.5 Q5.6 Q5.7 Q5.8 Q5.9 R159.2 RV1.5.2 RV2.5.2 RV3.5.2 U31.5.1 U31.5.2 U31.5.3 U31.5.7@5141.5,710
  other v2: 5079.65,1051.61 5115.28,1051.61 5061.83,1090 5097.46,1090 5133.09,1090 5079.65,1128.39 5115.28,1128.39
  other v3: 5141.5,688.35 5141.5,731.65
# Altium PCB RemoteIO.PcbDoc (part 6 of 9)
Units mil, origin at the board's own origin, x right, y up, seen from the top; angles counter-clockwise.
Board outline 7874.02 x 2362.2 mil, 6 copper layers (Top Layer, GND1, Layer 2, PWR, GND2, Bottom Layer), stack 60.956 mil thick; 686 components, 447 nets, 2681 pads, 1481 vias.

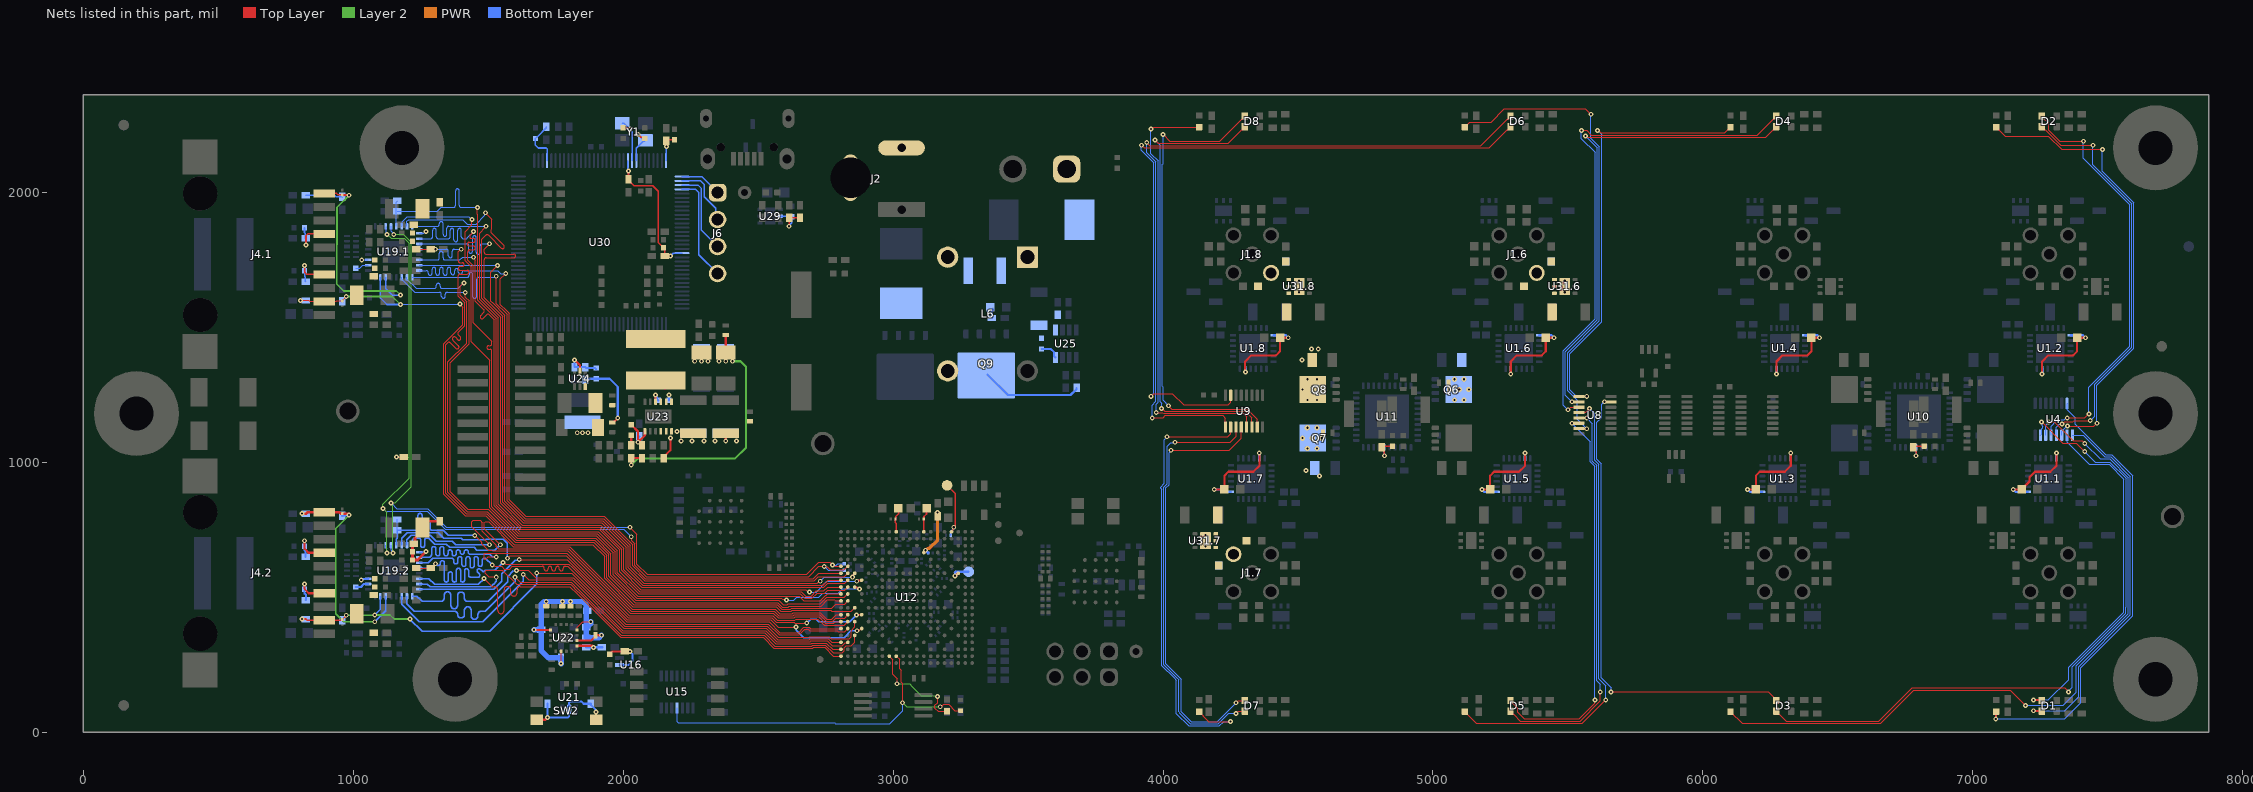
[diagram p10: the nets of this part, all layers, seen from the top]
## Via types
v1: diameter 18, hole 8, Top Layer to Bottom Layer, tented both sides, 1314 vias
v2: diameter 19.68, hole 7.87, Top Layer to Bottom Layer, tented both sides, 133 vias
v3: diameter 19.68, hole 7.87, Top Layer to Bottom Layer, 34 vias

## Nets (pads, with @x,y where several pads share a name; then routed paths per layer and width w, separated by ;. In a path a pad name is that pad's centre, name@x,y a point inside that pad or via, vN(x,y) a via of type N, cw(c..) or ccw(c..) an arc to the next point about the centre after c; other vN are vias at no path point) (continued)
L+6: C1.6.2 C18.2 J1.6.1 Q6.5 Q6.6 Q6.7 Q6.8 Q6.9 R160.2 RV1.6.2 RV2.6.2 RV3.6.2 U31.6.1 U31.6.2 U31.6.3 U31.6.7@5488.43,1652.2
  other v2: 5079.65,1231.61 5115.28,1231.61 5061.83,1270 5097.46,1270 5133.09,1270 5079.65,1308.39 5115.28,1308.39
  other v3: 5488.43,1630.55 5488.43,1673.86
L+7: C1.7.2 C17.2 J1.7.1 Q7.5 Q7.6 Q7.7 Q7.8 Q7.9 R161.2 RV1.7.2 RV2.7.2 RV3.7.2 U31.7.1 U31.7.2 U31.7.3 U31.7.7@4157.24,710
  other v1: 4580,950 4530,970
  other v2: 4534.72,1051.61 4570.35,1051.61 4516.91,1090 4552.54,1090 4588.17,1090 4534.72,1128.39 4570.35,1128.39
  other v3: 4157.24,688.35 4157.24,731.65
L+8: C1.8.2 C16.2 J1.8.1 Q8.5 Q8.6 Q8.7 Q8.8 Q8.9 R162.2 RV1.8.2 RV2.8.2 RV3.8.2 U31.8.1 U31.8.2 U31.8.3 U31.8.7@4504.17,1652.2
  other v1: 4515,1380 4550,1420 4575,1420
  other v2: 4534.72,1231.61 4570.35,1231.61 4516.91,1270 4552.54,1270 4588.17,1270 4534.72,1308.39 4570.35,1308.39
  other v3: 4504.17,1630.55 4504.17,1673.86
LED1: D9.1 U4.15 | length 1669.1
  Top Layer w8: v1(7085,50) 7085.81,50.81 7085.81,75.96 D9.1@7086.61,76.77
  Bottom Layer w4: v1(7085,50) 7340,50 7400,110 7400,240 7407,247 7407,247.2 7592,432.2 7592,435.79 7592,950.88 7513.88,1029 7492.31,1029 7380,1141.31 7380,1165 7350.27,1194.73 7350.27,1218 U4.15@7349.21,1219.06
LED2: D1.2 U4.1 | length 1393.7
  Top Layer w8: v1(7225,80) 7225.63,79.37 7255.28,79.37 D1.2@7255.91,78.74
  Bottom Layer w4: v1(7225,80) 7340,80 7392,132 7392,243.52 7584,435.51 7584,439.16 7584,947.57 7510.57,1021 7489,1021 7409.06,1100.94 U4.1@7368.9,1100.94
LED3: D1.1 U4.2 | length 1317.6
  Top Layer w8: v1@7220,120 v1(7225,120) 7254.02,120 D1.1@7255.91,118.11
  Bottom Layer w4: v1(7225,120) 7280,120 7355,195 7355,241.31 7559,445.31 7559,938.63 7504.63,993 7432,993 7349.84,1075.16 U4.2@7349.84,1100.32
  Bottom Layer w8: U4.2@7349.21,1100.94 U4.2@7349.84,1100.32
LED4: D10.1 U4.3 | length 1705
  Top Layer w4: D10.1@7086.61,2242.13 7119.37,2209.37 7279.32,2209.37 7328.69,2160 v1(7480,2160) ; v1(7350.49,1134.81) 7448.98,1134.81 7459.17,1145 v1(7460,1145)
  Bottom Layer w4: U4.3@7329.53,1100.94 7329.53,1115.71 7348.63,1134.81 v1(7350.49,1134.81) ; v1(7460,1145) 7460,1286.31 7597,1423.31 7597,1961.69 7480,2078.69 v1(7480,2160)
LED5: D2.2 U4.4 | length 1528.4
  Top Layer w4: D2.2@7255.91,2244.09 7255.91,2242.13 7265.72,2232.32 7267.68,2232.32 7325,2175 v1(7445,2175) ; v1(7330,1142.83) 7333.79,1142.83 7340.96,1150 7370,1150 7375,1155 v1(7435,1155)
  Bottom Layer w4: U4.4@7309.84,1100.94 7309.84,1129.84 7324.76,1144.76 7328.07,1144.76 v1(7330,1142.83) ; v1(7435,1155) 7452,1172 7452,1289.63 7589,1426.63 7589,1958.37 7445,2102.37 v1(7445,2175)
LED6: D2.1 U4.5 | length 1545.5
  Top Layer w4: D2.1@7255.91,2283.46 7255.91,2281.5 7280.68,2256.72 7280.68,2230.63 7321.31,2190 v1(7410,2190) ; v1(7350,1165) 7415,1165 v1(7430,1180)
  Bottom Layer w4: U4.5@7290.16,1100.94 7290.16,1134.89 7310,1154.73 7310,1155.49 7312.34,1157.83 7339.04,1157.83 7346.21,1165 v1(7350,1165) ; v1(7410,2190) 7410,2126.06 7581,1955.06 7581,1431 7533.03,1383.03 7533.03,1381.97 7430,1278.94 v1(7430,1180)
LED7: D11.1 U4.6 | length 2703.2
  Top Layer w4: D11.1@6102.36,76.77 6145.13,34 6659,34 6782,157 7138,157 v1(7195,100) ; v1(7280,1150) 7301.62,1150 7371.62,1080 7405,1080 v1(7415,1070)
  Bottom Layer w4: v1(7195,100) 7335,100 7384,149 7384,246.83 7576,438.83 7576,442.47 7576,944.25 7507.25,1013 7472,1013 v1(7415,1070) ; U4.6@7270.47,1100.94 7270.47,1138.31 7280,1147.84 v1(7280,1150)
LED8: D3.2 U4.7 | length 2489.3
  Top Layer w4: D3.2@6271.65,78.74 6271.65,76.78 6281.46,66.97 6283.43,66.97 6308.39,42 6652,42 6775,165 7340,165 v1(7355,150) ; v1(7255,1150) 7333,1072 7383,1072 v1(7415,1040)
  Bottom Layer w4: U4.7@7250.79,1100.94 7254.69,1104.85 7254.69,1124.69 7258.49,1128.49 7258.49,1134.72 7257.68,1135.53 7257.68,1147.32 v1(7255,1150) ; v1(7355,150) 7355,153.34 7369,167.34 7369,244 7567,442 7567,448 7567.5,448.5 7567.5,464.5 7568,465 7568,940.94 7507.94,1001 7454,1001 v1(7415,1040)
LED9: D3.1 U8.15 | length 1758.9
  Top Layer w4: v1(5635,1225) 5635.79,1224.21 U8.15@5659.06,1224.21 ; v1(5660,150) 6241.73,150 6271.65,120.07 D3.1@6271.65,118.11
  Bottom Layer w4: v1(5635,1225) 5625,1215 5625,1166.21 5607,1148.21 5607,1011.69 5622.63,996.06 5622.63,202.37 5660,165 v1(5660,150)
LED10: D12.1 U8.1 | length 1623.2
  Top Layer w4: U8.1@5540.94,1243.9 5541.5,1244.45 5569.45,1244.45 v1(5570,1245) ; v1(5610,2230) 5613.21,2230 5622.21,2221 6081.24,2221 D12.1@6102.36,2242.13
  Bottom Layer w4: v1(5570,1245) 5531.31,1245 5507,1269.31 5507,1403.57 5625,1521.57 5625,2215 v1(5610,2230)
LED11: D4.2 U8.2 | length 1814.4
  Top Layer w4: v1(5515,1225) 5515.39,1224.61 5540.55,1224.61 U8.2@5540.94,1224.21 ; v1(5565,2210) 5568.79,2210 5573.79,2205 6232.56,2205 6259.88,2232.32 6261.84,2232.32 6271.65,2242.13 D4.2@6271.65,2244.09
  Bottom Layer w4: v1(5515,1225) 5491,1249 5491,1262.69 5491,1410.2 5609,1528.2 5609,2166 v1(5565,2210)
LED12: D4.1 U8.3 | length 1916.2
  Top Layer w4: v1(5500,1195) 5501.69,1195 5511.45,1204.76 5540.71,1204.76 U8.3@5540.94,1204.53 ; v1(5550,2230) 5570,2230 5587,2213 6201.19,2213 6259.88,2271.69 6261.84,2271.69 6271.65,2281.5 D4.1@6271.65,2283.46
  Bottom Layer w4: v1(5500,1195) 5483,1212 5483,1259.37 5483,1413.52 5601,1531.52 5601,2149 5550,2200 v1(5550,2230)
LED13: D13.1 U8.4 | length 1725.4
  Top Layer w4: D13.1@5118.11,76.77 5160.88,34 5554,34 v1(5640,120) ; U8.4@5540.94,1184.84 5541.37,1185.27 5565.27,1185.27 v1(5580,1200)
  Bottom Layer w4: v1(5580,1200) 5599,1181 5599,1147.31 5599,1008.37 5614.63,992.74 5614.63,199.06 5640,173.69 v1(5640,120)
LED14: D5.2 U8.5 | length 1477.9
  Top Layer w4: D5.2@5287.4,78.74 5287.4,76.78 5297.21,66.97 5299.18,66.97 5324.14,42 5545,42 5620,117 v1(5620,150) ; U8.5@5540.94,1165.16 5541.02,1165.08 5569.92,1165.08 v1(5570,1165)
  Bottom Layer w4: v1(5570,1165) 5591,1144 5591,1005.06 5606.63,989.43 5606.63,191.53 5608,190.16 5620,178.16 v1(5620,150)
LED15: D5.1 U8.6 | length 1473
  Top Layer w4: D5.1@5287.4,118.11 5287.4,116.14 5313.3,90.24 5313.3,75.06 5338.36,50 5541.69,50 5599.24,107.55 5599.24,119.24 v1(5600,120) ; v1(5515,1145) 5515.24,1145.24 5540.71,1145.24 U8.6@5540.94,1145.47
  Bottom Layer w4: v1(5515,1145) 5530,1130 5583,1077 5583,1001.75 5598.63,986.12 5598.63,188.22 5600,186.85 v1(5600,120)
LED16: D14.1 U8.7 | length 1789.2
  Top Layer w4: D14.1@5118.11,2242.13 5136.95,2260.97 5215.97,2260.97 5265,2310 5565,2310 v1(5585,2290) ; U8.7@5540.94,1125.79 5541.34,1125.39 5569.61,1125.39 v1(5570,1125)
  Bottom Layer w4: v1(5570,1125) 5535,1160 5535,1230 5499,1266 5499,1406.89 5617,1524.89 5617,2169.31 5585,2201.31 v1(5585,2290)
LED17: D6.2 U9.15 | length 2706.1
  Top Layer w4: v1(3920,2175) 3930,2165 5208.31,2165 5275.63,2232.32 5277.59,2232.32 5287.4,2242.13 D6.2@5287.4,2244.09 ; v1(3955,1245) 3956.21,1245 3966.21,1255 4035,1255 4076,1214 4242.4,1214 4250.79,1222.39 U9.15@4250.79,1249.06
  Bottom Layer w4: v1(3920,2175) 3920,2156.31 3966,2110.31 3966,1256 v1(3955,1245)
LED18: D6.1 U9.1 | length 2750.3
  Top Layer w4: v1(3940,2185) 3951,2174 5177.94,2174 5275.63,2271.69 5277.59,2271.69 5287.4,2281.5 D6.1@5287.4,2283.46 ; v1(3960,1165) 4000,1165 4009,1174 4221,1174 4231.1,1163.9 U9.1@4231.1,1130.94
  Bottom Layer w4: v1(3940,2185) 3940,2147.63 3974,2113.63 3974,1226.53 3960,1212.53 v1(3960,1165)
LED19: D15.1 U9.2 | length 1682.5
  Top Layer w4: v1(4015,1095) 4240,1095 4250.79,1105.79 U9.2@4250.79,1130.94 ; D15.1@4133.86,76.77 4149.69,60.94 4149.69,60.65 4170.33,40 v1(4250,40)
  Bottom Layer w4: v1(4015,1095) 4015,1093.79 4005,1083.79 4005,922.47 3991.21,908.68 3991.21,905.36 3995,901.57 3995,247.76 4039,203.76 4049.44,193.32 4049.44,69.47 4094.91,24 4208.36,24 4224.36,40 v1(4250,40)
LED20: D7.2 U9.3 | length 1600.3
  Top Layer w4: v1(4045,1075) 4248.69,1075 4270.47,1096.79 U9.3@4270.47,1130.94 ; v1(4270,70) 4278.74,78.74 D7.2@4303.15,78.74
  Bottom Layer w4: v1(4045,1075) 4043.39,1073.39 4028.39,1073.39 4015,1060 4015,921.16 4002.52,908.68 4002.52,905.36 4003,904.88 4003,251.08 4052.68,201.39 4057.44,196.64 4057.44,76.06 4060.24,73.26 4060.24,72.75 4100.99,32 4205.05,32 4243.05,70 v1(4270,70)
LED21: D7.1 U9.4 | length 1603.4
  Top Layer w4: v1(4030,1045) 4245,1045 4290.16,1090.16 U9.4@4290.16,1130.94 ; v1(4270,110) 4278.11,118.11 D7.1@4303.15,118.11
  Bottom Layer w4: v1(4030,1045) 4030,1042.66 4023,1035.66 4023,917.84 4011,905.84 4011,254.39 4068.24,197.15 4068.24,76.06 4104.31,40 4201.73,40 4270,108.27 v1(4270,110)
LED22: D16.1 U9.5 | length 1626.1
  Top Layer w4: v1(3955,2235) 3962.13,2242.13 D16.1@4133.86,2242.13 ; v1(3975,1185) 3999.9,1185 4002.9,1182 4298,1182 4309.84,1170.16 U9.5@4309.84,1130.94
  Bottom Layer w4: v1(3955,2235) 3955,2143.94 3982,2116.94 3982,1223.21 3975,1216.21 v1(3975,1185)
LED23: D8.2 U9.6 | length 1754.1
  Top Layer w4: v1(3970,2195) 3983,2182 4241.06,2182 4291.38,2232.32 4293.34,2232.32 4303.15,2242.13 D8.2@4303.15,2244.09 ; v1(3995,1200) 3996.21,1200 4006.21,1190 4305,1190 4329.53,1165.47 U9.6@4329.53,1130.94
  Bottom Layer w4: v1(3970,2195) 3990,2175 3990,1225 3995,1220 v1(3995,1200)
LED24: D8.1 U9.7 | length 1747.8
  Top Layer w4: v1(4000,2215) 4025,2190 4209.69,2190 4291.38,2271.69 4293.34,2271.69 4303.15,2281.5 D8.1@4303.15,2283.46 ; v1(4020,1210) 4032.04,1198 4312,1198 4349.21,1160.79 U9.7@4349.21,1130.94
  Bottom Layer w4: v1(4000,2215) 4000,2106.31 3998,2104.31 3998,1405.63 3998,1281.57 4000,1279.57 4000,1230 v1(4020,1210)
LED_Activity.1: D26.1.1 J4.1.1 R167.1.1 R177.1.2 U19.1.30 | length 971
  Top Layer w6: J4.1.1@892.91,1996.65 896.26,2000 899.62,1996.64 938.36,1996.64 943.66,1991.34 D26.1.1@960,1991.34 960.67,1990.67 984.33,1990.67 v1(985,1990)
  Layer 2 w6: v1(985,1990) 940,1945 940,1807.63 939,1806.63 939,1661 965,1635 1160,1635 v1(1175,1620)
  Bottom Layer w6: R177.1.2@823.62,1990 930,1990 935,1985 958.62,1985 R167.1.1@960,1983.62 966.38,1990 v1(985,1990) ; U19.1.30@1120.47,1685.51 1120.47,1644.53 1145,1620 v1(1175,1620)
LED_Activity.2: D26.2.1 J4.2.1 R167.2.1 R177.2.2 U19.2.30 | length 862.4
  Top Layer w10: v1@810.02,810.02 825.02,810.02 830.55,815.55 J4.2.1@892.91,815.55 947.87,815.55 952.68,810.75 959.92,810.75 960,810.67 D26.2.1@960,810.24 960,810.08 960.08,810 980,810 v1(985,805)
  Layer 2 w6: v1(985,805) 935,755 935,440 965,410 v1(1080,410)
  Bottom Layer w6: v1(1080,410) 1120.47,450.47 U19.2.30@1120.47,504.41
  Bottom Layer w10: R167.2.1@960,802.52 962.48,805 v1(985,805)
  other v1: 810,811.1
LED_ERR: D23.2 U12.B12 U15.11 | length 1355.9
  Top Layer w4: U12.B12@3011.61,282.48 3024,270.09 3024,236 3030,230 3030,185 3035,180 v1(3035,110) ; v1(3175,95) 3178.53,95 3187.37,103.84 3205.43,103.84 3228.96,80.32 D23.2@3250,80.32
  Layer 2 w4: v1(3035,110) 3050,95 v1(3175,95)
  Bottom Layer w4: U15.11@2200,90.94 2200,40 2205,35 2783.69,35 2786.69,32 2987,32 3035,80 v1(3035,110)
LED_Link.1: D27.1.1 J4.1.9 R166.1.1 R176.1.2 U12.J18 U19.1.31 | length 3316
  Top Layer w4: v1(805.13,1600) 835,1600 838.35,1596.65 J4.1.9@892.91,1596.65 936.65,1596.65 938.66,1598.66 D27.1.1@960,1598.66 960,1599.25 974.32,1613.57 v1(974.32,1615) ; v1(1396.23,1587.56) 1396.23,1583.9 1405,1575.12 1405,1510 1335,1440 1335,882.37 1415.14,802.24 1490.69,802.24 1596.92,696 1887.69,696 1931,652.69 1931,570.31 2036.31,465 2566.69,465 2583.69,448 2623.22,448 2627.22,452 2769.21,452 2771.99,449.22 2845.68,449.22 U12.J18@2858.07,461.61
  Layer 2 w6: v1(974.32,1615) 1145,1615 v1(1175,1585)
  Bottom Layer w4: v1(805.13,1600) R176.1.2@825,1600 ; R166.1.1@960,1596.38 960,1600.32 974.32,1614.64 v1(974.32,1615) ; v1(1175,1585) 1176.28,1586.28 1392.49,1586.28 v1@1395,1588.79
  Bottom Layer w6: U19.1.31@1100.79,1685.51 1100.79,1609.21 1125,1585 v1(1175,1585)
LED_Link.2: D27.2.1 J4.2.9 R166.2.1 R176.2.2 U12.G18 U19.2.31 | length 2454.1
  Top Layer w4: v1(1680,590) 1809.09,590 2006.09,393 2534.37,393 2575.37,352 2686.21,352 2689.21,355 2762.78,355 2770.92,346.86 2785,346.86 2837.61,346.86 2844.87,354.12 2844.87,359.87 2845,360 2845,377.36 2858.07,390.43 U12.G18@2858.07,410.43
  Top Layer w6: v1(810,420) 825,420 829.45,415.55 J4.2.9@892.91,415.55 958.08,415.55 960,417.47 D27.2.1@960,417.56 960,418.15 974.32,432.47 v1(974.32,434.02)
  Layer 2 w6: v1(974.32,434.02) 974.81,434.51 1079.51,434.51 v1(1080,435) 1136.62,435 1151.62,420 v1(1210,420)
  Bottom Layer w5: v1(1210,420) 1255,375 1505,375 1680,550 v1(1680,590)
  Bottom Layer w6: R166.2.1@960,415.28 960,419.21 974.32,433.54 v1(974.32,434.02) ; v1(1080,435) 1100.79,455.79 U19.2.31@1100.79,504.41
LED_STATUS: D24.2 U12.B13 | length 381.6
  Top Layer w4: U12.B13@2986.02,282.48 2999.22,269.28 2999.22,215.14 3015,199.36 v1(3015,180) ; v1(3165,133) 3165,110 3155,100 3155,90 3166.65,78.35 D24.2@3200,78.35
  Layer 2 w4: v1(3015,180) 3061.21,180 3070,171.21 3070,170 3105,135 3163,135 v1(3165,133)
MDIO.MDC: R114.1 U12.R20 U19.1.12 U19.2.12 | length 3242.3
  Top Layer w4: v1(2025,760) 2051,734 2051,623.2 2089.2,585 2680,585 2724.95,629.95 2765.05,629.95 v1(2775,620) 2778.79,620 2783.63,615.16 U12.R20@2806.89,615.16
  Layer 2 w4: v1(1147,665) 1147,843 v1(1140,850) 1155,850 1215,910 1215,1815 1185,1845 v1(1150,1845)
  Bottom Layer w4: v1(1140,850) 1162,828 1277,828 1345,760 v1(2025,760) ; U19.2.12@1140.16,693.39 1140.16,675.57 1147,668.73 v1(1147,665) ; U19.1.12@1140.16,1874.49 1140.16,1856.37 1150,1846.53 v1(1150,1845) ; v1@2780,620 2790,620 2795,625 R114.1@2818.98,625
MDIO.MDIO: R41.2 R115.1 U12.R19 U19.1.11 U19.2.11 | length 3411.9
  Top Layer w4: v1(1160,1020) R41.2@1186.38,1020 ; v1(2030,725) 2032.08,722.92 2032.08,710 2043,699.08 2043,619.88 2085.88,577 2687,577 2724.95,614.95 v1(2745,614.95) 2746.58,613.37 2756.63,613.37 2768.04,601.96 2819.28,601.96 U12.R19@2832.48,615.16
  Layer 2 w4: v1(1125,665) 1125,815 v1(1110,830) 1110,845 1207,942 1207,1020 ; v1(1125,1845) 1140,1830 1188.69,1830 1207,1811.69 1207,1020 ; v1(1160,1020) 1207,1020
  Bottom Layer w4: v1(1110,830) 1111.21,830 1121.21,820 1273.69,820 1341.69,752 2003,752 v1(2030,725) ; U19.2.11@1120.47,693.39 1120.47,686.5 1125,681.97 v1(1125,665) ; U19.1.11@1120.47,1874.49 1122.74,1872.22 1122.74,1847.26 v1(1125,1845) ; v1@2745,615 v1(2745,614.95) 2759.95,600 R115.1@2818.98,600
MII1_RX_ER: R171.1.1 R181.1.2 U12.K19 U19.1.20 | length 3163.2
  Top Layer w4: R181.1.2@1233.62,1790 R171.1.1@1285,1790 ; R171.1.1@1286.38,1790 v1(1304.87,1790) ; 1389.92,1422.55 cw(c1384.98,1427.5) 1380.03,1422.55 1359.4,1443.18 ccw(c1354.45,1438.23) 1349.5,1443.18 1343,1436.69 1343,1432 1343,885.69 1418.45,810.24 1494,810.24 1600.24,704 1891,704 1939,656 1939,573.63 2039.63,473 2570,473 2587,456 2619.91,456 2623.91,460 2773.28,460 2788.1,474.82 2820.09,474.82 U12.K19@2832.48,487.2 ; 1389.93,1422.55 ccw(c1384.98,1427.5) 1389.92,1432.45 1369.3,1453.08 cw(c1374.24,1458.03) 1369.29,1462.98 cw(c1374.24,1458.03) 1379.19,1462.98 1386.91,1455.27 ccw(c1391.86,1460.22) 1396.81,1455.27 ccw(c1391.86,1460.22) 1396.81,1465.17 1389.09,1472.88 cw(c1394.04,1477.83) 1389.09,1482.78 1405.66,1499.34 1413,1506.69 1413,1592 1389.23,1615.77 1389.23,1675 1389.23,1691 cw(c1396.23,1691) 1396.23,1698 1422,1698 ccw(c1422,1705) 1422,1712 1396.23,1712 cw(c1396.23,1719) 1396.23,1726 1403.69,1726 ccw(c1403.69,1733) 1403.69,1740 1396.23,1740 cw(c1396.23,1747) 1389.23,1747 1389.23,1779.23 1390,1780 v1(1400,1790)
  Bottom Layer w4: U19.1.20@1244.49,1789.84 1244.57,1789.92 1330,1789.92 1346,1789.92 cw(c1346,1782.92) 1353,1782.92 1353,1765.47 ccw(c1360,1765.47) 1367,1765.47 1367,1782.92 cw(c1374,1782.92) 1374,1789.92 1385,1789.92 1399.92,1789.92 v1(1400,1790)
MII1_RXCLK: U12.N20 U19.1.19 | length 3093.4
  Top Layer w4: v1(1505,1810) 1485,1790 1485,1779 ccw(c1492,1779) 1492,1772 1594.54,1772 cw(c1594.54,1765) 1594.54,1758 1492,1758 ccw(c1492,1751) 1485,1751 1485,1735 1485,1611.06 1554,1542.06 1554,852.06 1630.06,776 1920.82,776 2011,685.82 2011,606.63 2072.63,545 2740,545 2758.98,563.98 U12.N20@2806.89,563.98
  Bottom Layer w4: U19.1.19@1244.49,1809.53 1244.72,1809.76 1405,1809.76 1421,1809.76 cw(c1421,1802.76) 1428,1802.76 1428,1782 ccw(c1435,1782) 1442,1782 1442,1832.69 cw(c1449,1832.69) 1456,1832.69 1456,1778.21 ccw(c1463,1778.21) 1470,1778.21 1470,1802.76 cw(c1477,1802.76) 1477,1809.76 1490,1809.76 1504.76,1809.76 v1(1505,1810)
MII1_RXD0: U12.N17 U19.1.16 | length 2974.8
  Top Layer w4: v1@1490,1875 1490,1871 1469,1850 1469,1604.43 1538,1535.43 1538,845.43 1623.43,760 1914.2,760 1995,679.2 1995,600 2066,529 2662.31,529 2677.21,529 2686.21,520 v1(2690,520)
  Top Layer w6: v1(2865.2,559.8) 2868.45,559.8 2871.14,562.49 2882.17,562.49 U12.N17@2883.66,563.98
  Bottom Layer w4: U19.1.16@1218.9,1874.49 1219.41,1875 1310,1875 1312,1875 ccw(c1312,1882) 1319,1882 1319,1885 cw(c1326,1885) 1333,1885 1333,1845.18 ccw(c1340,1845.18) 1347,1845.18 1347,1868 cw(c1354,1868) 1354,1875 1410,1875 v1(1492,1875) ; v1(2690,520) 2715,520 2754.8,559.8 v1(2865.2,559.8)
MII1_RXD1: U12.N19 U19.1.15 | length 3092.3
  Top Layer w4: v1@1495,1925 1494.57,1924.57 1494.57,1920.43 1513.34,1901.66 1513.34,1886.66 1513.34,1863.34 1511.11,1861.11 ccw(c1516.06,1856.16) 1511.11,1851.21 1558.43,1803.89 cw(c1553.48,1798.94) 1558.43,1793.99 cw(c1553.48,1798.94) 1548.53,1793.99 1501.21,1841.31 ccw(c1496.26,1836.36) 1491.31,1841.31 1480,1830 1477,1827 1477,1607.74 1546,1538.74 1546,848.75 1626.75,768 1917.51,768 2003,682.51 2003,603.31 2069.31,537 2743.31,537 2757.9,551.59 2820.09,551.59 U12.N19@2832.48,563.98
  Bottom Layer w4: U19.1.15@1199.21,1874.49 1199.21,1894.21 1205,1900 1405,1900 1422,1883 1455,1883 1487.32,1915.32 1487.32,1922.32 v1(1490,1925)
MII1_RXD2: U12.M18 U19.1.14 | length 3000
  Top Layer w4: v1(1440,1900) 1440,1880 1415,1855 1415,1747 1437,1725 1437,1448 1506,1379 1506,832.18 1610.18,728 1900.94,728 1963,665.94 1963,584.63 2050.63,497 2586.31,497 2590.64,492.68 2602.32,492.68 v1(2605,490)
  Top Layer w6: U12.M18@2858.07,538.39 2859.56,536.9 2866.52,536.9 2872.07,531.34 v1(2875.32,531.34)
  Bottom Layer w4: U19.1.14@1179.53,1874.49 1182.3,1877.26 1182.3,1892.3 1200,1910 1428.79,1910 1438.79,1900 v1(1440,1900) ; v1(2605,490) 2632.34,490 2642.34,500 2725,500 2740,515 2797.6,515 2813.94,531.34 v1(2875.32,531.34)
MII1_RXD3: R172.1.1 R182.1.2 U12.M20 U19.1.13 | length 3134.8
  Top Layer w4: v1(1460,1945) 1460,1920 1461,1919 1461,1601.12 1530,1532.12 1530,842.12 1620.12,752 1910.88,752 1987,675.88 1987,595.63 2061.63,521 2659,521 2675.77,504.23 2696.21,504.23 2715.98,524 2744,524 2758.39,538.39 U12.M20@2806.89,538.39
  Bottom Layer w4: U19.1.13@1159.84,1874.49 1159.84,1964.84 R172.1.1@1165,1970 ; R182.1.2@1163.62,1930 1311.19,1930 1326.19,1945 1370,1945 1372,1945 ccw(c1372,1952) 1379,1952 1379,2006.35 cw(c1386,2006.35) 1393,2006.35 1393,1952 ccw(c1400,1952) 1400,1945 1435,1945 v1(1460,1945)
MII1_RXDV: U12.L20 U19.1.18 | length 3092.8
  Top Layer w4: v1@1445,1855 1445,1854 1432.95,1841.95 ccw(c1437.9,1837) 1437.9,1830 1446,1830 cw(c1446,1823) 1446,1816 1430,1816 ccw(c1430,1809) 1430,1802 1446,1802 cw(c1446,1795) 1446,1788 1432,1788 ccw(c1432,1781) 1425,1781 1425,1765 1425,1748.31 1445,1728.31 1445,1518.48 1514,1449.48 1514,1440 cw(c1507,1440) 1507,1433 1502.4,1433 ccw(c1502.4,1426) 1502.4,1419 1507,1419 cw(c1507,1412) 1514,1412 1514,1410 1514,835.49 1613.49,736 1904.25,736 1971,669.25 1971,589 2055,505 2652.37,505 2669.14,488.23 2730.61,488.23 2750.37,508 2753,508 2757.8,512.8 U12.L20@2806.89,512.8
  Bottom Layer w4: U19.1.18@1244.49,1829.21 1285,1829.21 1287,1829.21 ccw(c1287,1836.21) 1294,1836.21 1294,1860 cw(c1301,1860) 1308,1860 1308,1836.21 ccw(c1315,1836.21) 1315,1829.21 1325,1829.21 1350,1829.21 1352,1829.21 ccw(c1352,1836.21) 1359,1836.21 1359,1860 cw(c1366,1860) 1373,1860 1373,1824.76 ccw(c1380,1824.76) 1387,1824.76 1387,1860 cw(c1394,1860) 1401,1860 1401,1836.21 ccw(c1408,1836.21) 1408,1829.21 1420.21,1829.21 1425,1834 v1(1446,1855)
MII1_TXCLK: U12.M19 U19.1.22 | length 2775.9
  Top Layer w4: v1(1446,1760) 1446,1757 1453,1750 1453,1597.8 1460.4,1590.4 1484.19,1566.62 cw(c1479.24,1561.67) 1484.19,1556.72 1471.79,1544.32 ccw(c1476.74,1539.37) 1471.79,1534.42 ccw(c1476.74,1539.37) 1481.69,1534.42 1494.09,1546.82 cw(c1499.04,1541.87) 1503.99,1546.82 1505.4,1545.4 1522,1528.8 1522,838.8 1616.8,744 1907.57,744 1979,672.57 1979,592.31 2058.31,513 2655.69,513 2672.45,496.23 2699.53,496.23 2719.29,516 2747.31,516 2757.31,526 2820.09,526 U12.M19@2832.48,538.39
  Bottom Layer w4: U19.1.22@1244.49,1750.47 1310,1750.47 1312,1750.47 ccw(c1312,1757.47) 1319,1757.47 1319,1774.92 cw(c1326,1774.92) 1333,1774.92 1333,1757.47 ccw(c1340,1757.47) 1340,1750.47 1370,1750.47 1395.47,1750.47 1405,1760 v1@1445,1760
MII1_TXD0: U12.P20 U19.1.24 | length 2776.9
  Top Layer w4: v1(1565,1700) 1545,1680 1545,1585 1565,1565 1578,1552 1578,862 1640,800 1920,800 1930.76,800 2035,695.76 2035,616.57 2082.57,569 2704.13,569 2724.69,589.57 U12.P20@2806.89,589.57
  Bottom Layer w4: U19.1.24@1244.49,1711.1 1255,1711.1 1271,1711.1 cw(c1271,1704.1) 1278,1704.1 1278,1700.51 ccw(c1285,1700.51) 1292,1700.51 1292,1715.39 cw(c1299,1715.39) 1306,1715.39 1306,1700.51 ccw(c1313,1700.51) 1320,1700.51 1320,1715.39 cw(c1327,1715.39) 1334,1715.39 1334,1700.51 ccw(c1341,1700.51) 1348,1700.51 1348,1715.39 cw(c1355,1715.39) 1362,1715.39 1362,1702.37 ccw(c1369,1702.37) 1376,1702.37 1376,1711.1 cw(c1383,1711.1) 1390,1711.1 1390,1704.1 ccw(c1397,1704.1) 1404,1704.1 cw(c1411,1704.1) 1411,1711.1 1430,1711.1 1535.11,1711.1 1546.21,1700 v1(1565,1700)
MII1_TXD1: U12.P19 U19.1.25 | length 2777.6
  Top Layer w4: v1(1530,1690) 1530,1588.69 1565,1553.69 1570,1548.69 1570,858.69 1636.69,792 1916.14,792 1927.45,792 2027,692.45 2027,613.25 2079.25,561 2707.44,561 2722.81,576.37 2819.28,576.37 U12.P19@2832.48,589.57
  Bottom Layer w4: U19.1.25@1218.9,1685.51 1420,1685.51 1422,1685.51 ccw(c1422,1692.51) 1429,1692.51 1429,1696.1 cw(c1436,1696.1) 1443,1696.1 1443,1614.7 ccw(c1450,1614.7) 1457,1614.7 1457,1678.51 cw(c1464,1678.51) 1464,1685.51 1505,1685.51 1521.72,1685.51 1526.21,1690 v1(1530,1690)
MII1_TXD2: U12.K20 U19.1.26 | length 2777.9
  Top Layer w4: v1(1410,1665) 1397.23,1652.23 1397.23,1619.09 1421,1595.31 1421,1442.31 1351,1372.31 1351,889 1421.76,818.24 1497.31,818.24 1603.55,712 1894.31,712 1947,659.31 1947,578 2044,481 2573.31,481 2590.31,464 2611.63,464 2615.63,468 2733,468 2757,492 2782.22,492 2787.02,487.2 U12.K20@2806.89,487.2
  Bottom Layer w4: U19.1.26@1199.21,1685.51 1199.21,1678.62 1232.83,1645 1270,1645 1301,1645 ccw(c1301,1652) 1308,1652 1308,1656.38 cw(c1315,1656.38) 1322,1656.38 1322,1652 ccw(c1329,1652) 1329,1645 1345,1645 1390,1645 v1(1410,1665)
MII1_TXD3: U12.L19 U19.1.27 | length 2777.9
  Top Layer w4: v1(1415,1630) 1415,1612.63 1429,1598.63 1429,1439 1359,1369 1359,892.31 1425.08,826.24 1500.63,826.24 1606.86,720 1897.63,720 1955,662.63 1955,581.31 2047.31,489 2576.63,489 2593.63,472 2608.31,472 2612.31,476 2729.69,476 2753.69,500 2819.68,500 U12.L19@2832.48,512.8
  Bottom Layer w4: U19.1.27@1179.53,1685.51 1179.53,1678.62 1228.15,1630 1290,1630 1320,1630 cw(c1320,1623) 1327,1623 1327,1615.58 ccw(c1334,1615.58) 1341,1615.58 1341,1623 cw(c1348,1623) 1348,1630 1350,1630 v1(1415,1630)
MII1_TXEN: U12.P18 U19.1.23 | length 2684
  Top Layer w4: v1(1535,1730) 1510,1705 1510,1597.37 1516.19,1591.19 1562,1545.37 1562,855.37 1633.37,784 1924.14,784 2019,689.14 2019,609.94 2075.94,553 2710.75,553 2719.73,553 2726.73,560 v1(2730,560)
  Top Layer w6: v1(2850,575) 2852.3,577.3 2852.3,581.69 2858.07,587.46 U12.P18@2858.07,589.57
  Bottom Layer w4: U19.1.23@1244.49,1730.79 1244.88,1730.39 1534.61,1730.39 v1(1535,1730) ; v1(2730,560) 2745,575 2785,575 v1(2850,575)
MII2_RX_ER: R171.2.1 R181.2.2 U12.F20 U19.2.20 | length 2127.7
  Top Layer w4: R181.2.2@1233.62,608.9 R171.2.1@1286.38,608.9 1290.32,608.9 1305,623.58 v1(1305,625) ; v1(1555,630) 1557.34,630 1564.34,623 1798.72,623 1810.83,610.89 2012.72,409 2541,409 2580,370 2650,370 2670,390 2690,390 2695.16,384.84 U12.F20@2806.89,384.84
  Bottom Layer w5: U19.2.20@1244.49,608.74 1288.74,608.74 v1(1305,625) 1309.7,620.3 ccw(c1315,625.61) 1322.5,625.61 1322.5,628.5 cw(c1330,628.5) 1337.5,628.5 1337.5,564.5 ccw(c1345,564.5) 1352.5,564.5 1352.5,587 cw(c1360,587) 1367.5,587 1367.5,564.5 ccw(c1375,564.5) 1382.5,564.5 1382.5,600.42 cw(c1390,600.42) 1397.5,600.42 1397.5,564.5 ccw(c1405,564.5) 1412.5,564.5 1412.5,598.59 cw(c1420,598.59) 1427.5,598.59 1427.5,582.5 ccw(c1435,582.5) 1435,575 1455,575 1465,575 1466.77,576.77 ccw(c1461.46,582.07) 1466.77,587.37 1460.84,593.3 cw(c1466.15,598.6) 1460.84,603.91 cw(c1466.15,598.6) 1471.45,603.91 1477.37,597.98 ccw(c1482.68,603.28) 1487.98,597.98 1490,600 1519.06,600 1525,600 v1(1555,630)
MII2_RXCLK: U12.F19 U19.2.19 | length 2021.8
  Top Layer w4: v1(1515,620) 1518.79,620 1523.79,615 1550,615 1560,605 1580,605 1590,615 1685,615 1701,615 cw(c1701,608) 1708,608 1708,605 ccw(c1715,605) 1722,605 1722,608 cw(c1729,608) 1736,608 1736,605 ccw(c1743,605) 1750,605 1750,608 cw(c1757,608) 1764,608 1764,605 ccw(c1771,605) 1778,605 1778,608 cw(c1785,608) 1785,615 1795.41,615 1802.83,607.58 2009.41,401 2537.69,401 2577.69,361 2652.31,361 2673.31,382 2686.69,382 2691.84,376.84 2793.16,376.84 2797.55,372.45 2820.09,372.45 U12.F19@2832.48,384.84
  Bottom Layer w5: U19.2.19@1244.49,628.43 1278.86,628.43 1295.44,645 1317.72,645 1365.22,645 cw(c1365.22,637.5) 1372.72,637.5 1372.72,631.7 ccw(c1380.22,631.7) 1387.72,631.7 1387.72,643.5 cw(c1395.22,643.5) 1402.72,643.5 1402.72,622.59 ccw(c1410.22,622.59) 1417.72,622.59 1417.72,643.5 cw(c1425.22,643.5) 1432.72,643.5 1432.72,616.71 ccw(c1440.22,616.71) 1447.72,616.71 1447.72,643.5 cw(c1455.22,643.5) 1462.72,643.5 1462.72,622.6 ccw(c1470.22,622.6) 1477.72,622.6 1477.72,637.5 cw(c1485.22,637.5) 1485.22,645 1490,645 1514.73,620.27 v1(1515,620)
MII2_RXD0: U12.H20 U19.2.16 | length 2018.8
  Top Layer w4: v1(1545,695) 1486.29,753.71 1486.29,777.66 1488.63,780 1501.61,780 1593.61,688 1802,688 2033,457 2563.37,457 2580.37,440 2626.53,440 2630.53,444 2731,444 2755,420 2773.5,420 2789.53,436.02 U12.H20@2806.89,436.02
  Bottom Layer w5: U19.2.16@1218.9,693.39 1218.9,712.19 1225,718.29 1226.71,720 1242.5,720 cw(c1242.5,712.5) 1250,712.5 1250,693 ccw(c1257.5,693) 1265,693 1265,712.5 cw(c1272.5,712.5) 1272.5,720 1280,720 1302.5,697.5 1345,697.5 1357.5,685 1447.5,685 1457.5,675 1525,675 v1(1545,695)
MII2_RXD1: U12.H19 U19.2.15 | length 2044.2
  Top Layer w4: v1(1505,695) 1465,735 1465,736.21 1440,761.21 1440,780 1445,785 1470,785 1478.29,776.71 1478.29,745.4 1530,693.69 1530,686.84 1536.84,680 1798.29,680 2029.29,449 2560.06,449 2577.06,432 2629.85,432 2633.85,436 2727.69,436 2751.69,412 2776.82,412 2788.45,423.63 2820.09,423.63 U12.H19@2832.48,436.02
  Bottom Layer w5: U19.2.15@1199.21,693.39 1199.21,714.21 1215,730 1285,730 1307.5,707.5 1367.5,707.5 1380,695 v1(1505,695)
MII2_RXD2: U12.H17 U19.2.14 | length 1938.7
  Top Layer w4: v1(1571.09,645) 1581.09,655 1789.35,655 1826.83,617.52 2019.35,425 2550.12,425 2567.12,408 2633.31,408 2636.31,405 v1(2680,405)
  Top Layer w6: v1(2865,435) 2865.51,435.51 2883.15,435.51 U12.H17@2883.66,436.02
  Bottom Layer w5: U19.2.14@1179.53,693.39 1179.53,719.53 1199.9,739.9 1315.1,739.9 1335,720 1400.46,720 1405.96,714.5 1491.42,714.5 1491.92,715 1555,715 1570,700 1570,646.09 v1(1571.09,645) ; v1(2680,405) 2694.78,419.78 2715,419.78 2724.78,410 2840,410 v1(2865,435)
MII2_RXD3: R172.2.1 R182.2.2 U12.G20 U19.2.13 | length 2063.8
  Top Layer w4: v1(1450,730) 1476.34,703.66 1476.34,698.66 1500,675 1513.69,675 1516.69,672 1794.98,672 2025.98,441 2556.75,441 2573.75,424 2633.16,424 2637.16,428 2724.37,428 2748.37,404 2780.13,404 2786.56,410.43 U12.G20@2806.89,410.43
  Bottom Layer w4: R182.2.2@1163.62,748.9 R172.2.1@1163.62,788.9
  Bottom Layer w5: U19.2.13@1159.84,693.39 1159.84,714.84 1163.62,718.62 R182.2.2@1163.62,748.9 1230,748.9 1232.5,748.9 ccw(c1232.5,756.4) 1240,756.4 1240,804 cw(c1247.5,804) 1255,804 1255,756.4 ccw(c1262.5,756.4) 1270,756.4 1270,777.51 cw(c1277.5,777.51) 1285,777.51 1285,756.4 ccw(c1292.5,756.4) 1292.5,748.9 1320,748.9 1332.77,748.9 1351.67,730 v1(1450,730)
MII2_RXDV: U12.G19 U19.2.18 | length 2018.3
  Top Layer w4: v1(1530,650) 1500,650 1490.66,640.66 1487.34,640.66 1485,643 1485,661.66 1487.34,664 1791.66,664 2022.66,433 2553.43,433 2570.43,416 2636.48,416 2640.48,420 2721.06,420 2745.06,396 2783.44,396 2784.68,397.23 2819.28,397.23 U12.G19@2832.48,410.43
  Bottom Layer w5: U19.2.18@1244.49,648.11 1283.11,648.11 1285,650 1287.5,652.5 ccw(c1278.45,661.55) 1291.25,661.55 1291.25,681 cw(c1298.75,681) 1306.25,681 1306.25,661.5 ccw(c1313.75,661.5) 1321.25,661.5 1321.25,681 cw(c1328.75,681) 1336.25,681 1336.25,661.5 ccw(c1343.75,661.5) 1351.25,661.5 1351.25,668.5 cw(c1358.75,668.5) 1366.25,668.5 1366.25,661.5 ccw(c1373.75,661.5) 1381.25,661.5 1381.25,668.5 cw(c1388.75,668.5) 1396.25,668.5 1396.25,667.5 ccw(c1403.75,667.5) 1411.25,667.5 1411.25,668.5 cw(c1418.75,668.5) 1426.25,668.5 1426.25,667.5 ccw(c1433.75,667.5) 1433.75,660 1445,660 1505,660 1515,650 v1(1530,650)
MII2_TXCLK: U12.B20 U19.2.22 | length 1930.8
  Top Layer w4: v1(1485,570) 1515,540 1523,540 cw(c1523,528) 1535,528 1535,452 ccw(c1547,452) 1559,452 1559,528 cw(c1571,528) 1583,528 1583,516.96 ccw(c1595,516.96) 1607,516.96 1607,528 cw(c1619,528) 1619,540 1650,540 1802.37,540 1829.37,513 1829.53,513 1990.53,352 2518.8,352 2558.8,312 2702.78,312 2705.78,315 2746.21,315 2778.73,282.48 U12.B20@2806.89,282.48
  Bottom Layer w5: U19.2.22@1244.49,569.37 1280.63,569.37 1302,548 1463,548 v1(1485,570)
MII2_TXD0: U12.F17 U19.2.24 | length 1840
  Top Layer w4: v1(1615,640) 1793.04,640 1802.04,631 1818.83,614.2 2016.04,417 2546.8,417 2573.8,390 v1(2640,390)
  Top Layer w6: v1(2866.39,376.77) 2868.69,379.06 2875.78,379.06 2881.56,384.84 U12.F17@2883.66,384.84
  Bottom Layer w4: v1@1612.5,637.5 v1(1615,640)
  Bottom Layer w5: U19.2.24@1244.49,530 1520,530 1550,560 1550,587.5 1600,637.5 v1@1612.5,637.5 ; v1(2640,390) 2641.67,388.33 2641.67,378.33 2668.5,351.5 2785,351.5 2818.74,351.5 2844,376.77 v1(2866.39,376.77)
MII2_TXD1: U12.D20 U19.2.25 | length 1920.9
  Top Layer w4: v1(1605,600) 1648.79,600 1675.79,573 1814.78,573 2002.78,385 2531.06,385 2572.06,344 2689.53,344 2692.53,347 2759.47,347 2772.81,333.66 2785,333.66 U12.D20@2806.89,333.66
  Bottom Layer w4: 1593.39,598.39 1603.39,598.39 v1(1605,600)
  Bottom Layer w5: U19.2.25@1218.9,504.41 1235.59,504.41 1255,485 1321.88,485 1324.38,485 ccw(c1324.38,497.5) 1336.88,497.5 1336.88,508.5 cw(c1349.38,508.5) 1361.88,508.5 1361.88,470.5 ccw(c1374.38,470.5) 1386.88,470.5 1386.88,507.31 cw(c1399.38,507.31) 1411.88,507.31 1411.88,497.5 ccw(c1424.38,497.5) 1424.38,485 1500,485 1572.5,557.5 1572.5,577.5 1593.39,598.39
MII2_TXD2: U12.C20 U19.2.26 | length 1920.9
  Top Layer w4: v1(1600,575) 1618,557 1808,557 1836,529 1836.15,529 1996.15,369 2524.43,369 2565.43,328 2696.15,328 2699.15,331 2752.84,331 2775.77,308.07 2785,308.07 U12.C20@2806.89,308.07
  Bottom Layer w5: U19.2.26@1199.21,504.41 1199.21,475.79 1210,465 1226,449 1348.75,449 1374.5,449 cw(c1374.5,436.5) 1387,436.5 ccw(c1399.5,436.5) 1412,436.5 1412,452.69 cw(c1424.5,452.69) 1437,452.69 1437,431.5 ccw(c1449.5,431.5) 1462,431.5 1462,436.5 cw(c1474.5,436.5) 1474.5,449 1477,449 1489,449 1600,560 v1(1600,575)
MII2_TXD3: U12.D19 U19.2.27 | length 1913
  Top Layer w4: v1(1630,585) 1650,565 1811.47,565 1999.47,377 2527.75,377 2568.75,336 2692.84,336 2695.84,339 2756.15,339 2773.88,321.27 2785,321.27 2812.02,321.27 2823.33,332.58 2831.4,332.58 U12.D19@2832.48,333.66
  Bottom Layer w5: U19.2.27@1179.53,504.41 1179.53,475.47 1245,410 1480,410 1630,560 v1(1630,585)
MII2_TXEN: U12.E18 U19.2.23 | length 1913
  Top Layer w4: v1(1530,575) 1527.66,577.34 1502.66,577.34 1490,590 1490,597.66 1492.34,600 1553,600 1605,548 1805.69,548 1832.69,521 1832.84,521 1993.84,360 2522.12,360 2562.12,320 2699.47,320 2702.47,323 2749.53,323 2777.53,295 2785,295 2811.34,295 2819.68,303.34 2819.68,312.8 2827.35,320.46 2845.03,320.46 2858.07,333.5 U12.E18@2858.07,359.25
  Bottom Layer w5: U19.2.23@1244.49,549.68 1275,549.68 1285.68,539 1509,539 1519.68,549.68 1520.32,549.68 1530,559.37 v1(1530,575)
MSP432_SWCLK: J6.4 U30.100 | length 395.8
  Bottom Layer w6: U30.100@2218.15,2011.85 2268.15,2011.85 2280,2000 2280,1770 J6.4@2350,1700
MSP432_SWDIO: J6.3 U30.99 | length 316.9
  Bottom Layer w6: U30.99@2218.15,2027.6 2277.4,2027.6 2290,2015 2290,1860 J6.3@2350,1800
MSP432_TDI: J6.2 U30.98 | length 238.1
  Bottom Layer w6: U30.98@2218.15,2043.35 2286.65,2043.35 2300,2030 2300,1984.65 2343.17,1941.48 2343.17,1906.83 J6.2@2350,1900
MSP432_TDO: J6.1 U30.97 | length 156.3
  Bottom Layer w6: U30.97@2218.15,2059.09 2290.91,2059.09 J6.1@2350,2000
NetC2.1_2: C2.1.2 U1.1.13 U1.1.23 | length 331.1
  Top Layer w8: v1(7150,900) C2.1.2@7180.47,900 7210,929.53 7210,945.31 7214.69,950 7215,950 7230.46,965.46 7287.39,965.46 7310,988.07 v1(7310,1035)
  Bottom Layer w8: v1(7150,900) 7159.21,890.79 U1.1.13@7204.7,890.79 ; U1.1.23@7309.53,1015.3 7309.53,1034.53 v1(7310,1035)
NetC2.2_2: C2.2.2 U1.2.13 U1.2.23 | length 351.2
  Top Layer w8: v1(7256.93,1327.2) 7256.93,1374.13 7279.54,1396.74 7371.93,1396.74 ; 7371.93,1397.2 7386.46,1411.73 C2.2.2@7386.46,1462.2 v1(7416.93,1462.2)
  Bottom Layer w8: v1(7256.93,1327.2) 7257.4,1327.68 U1.2.23@7257.4,1346.91 ; U1.2.13@7362.22,1471.42 7407.72,1471.42 v1(7416.93,1462.2)
NetC2.3_2: C2.3.2 U1.3.13 U1.3.23 | length 351.2
  Top Layer w8: v1(6165.75,900) C2.3.2@6196.22,900 6196.22,950.47 6210.75,965 ; 6210.75,965.46 6303.14,965.46 6325.75,988.07 v1(6325.75,1035)
  Bottom Layer w8: v1(6165.75,900) 6174.96,890.79 U1.3.13@6220.45,890.79 ; U1.3.23@6325.28,1015.3 6325.28,1034.53 v1(6325.75,1035)
NetC2.4_2: C2.4.2 U1.4.13 U1.4.23 | length 351.2
  Top Layer w8: v1(6272.68,1327.2) 6272.68,1374.13 6295.29,1396.74 6387.68,1396.74 ; 6387.68,1397.2 6402.2,1411.73 C2.4.2@6402.2,1462.2 v1(6432.68,1462.2)
  Bottom Layer w8: v1(6272.68,1327.2) 6273.15,1327.68 U1.4.23@6273.15,1346.91 ; U1.4.13@6377.97,1471.42 6423.46,1471.42 v1(6432.68,1462.2)
NetC2.5_2: C2.5.2 U1.5.13 U1.5.23 | length 351.2
  Top Layer w8: v1(5181.5,900) C2.5.2@5211.97,900 5211.97,950.47 5226.5,965 ; 5226.5,965.46 5318.89,965.46 5341.5,988.07 v1(5341.5,1035)
  Bottom Layer w8: v1(5181.5,900) 5190.71,890.79 U1.5.13@5236.2,890.79 ; U1.5.23@5341.02,1015.3 5341.02,1034.53 v1(5341.5,1035)
NetC2.6_2: C2.6.2 U1.6.13 U1.6.23 | length 350.5
  Top Layer w8: v1(5288.43,1327.2) 5288.43,1374.13 5311.03,1396.74 5403.43,1396.74 ; 5403.43,1397.2 5417.95,1411.73 C2.6.2@5417.95,1462.2 v1(5448.43,1462.2)
  Bottom Layer w8: v1@5288.9,1327.68 U1.6.23@5288.9,1346.91 ; U1.6.13@5393.72,1471.42 5439.21,1471.42 v1(5448.43,1462.2)
NetC2.7_2: C2.7.2 U1.7.13 U1.7.23 | length 365.1
  Top Layer w8: v1(4190,900) C2.7.2@4227.72,900 4227.72,950.47 4242.24,965 ; 4242.24,965.46 4334.63,965.46 4357.24,988.07 v1@4357.24,1035
  Bottom Layer w8: v1(4190,900) 4220,900 4229.21,890.79 U1.7.13@4251.95,890.79 ; U1.7.23@4356.77,1015.3 v1(4356.77,1034.63)
NetC2.8_2: C2.8.2 U1.8.13 U1.8.23 | length 336.2
  Top Layer w8: v1@4304.17,1334.69 4304.17,1374.13 4326.78,1396.74 4419.17,1396.74 ; 4419.17,1397.2 4433.7,1411.73 C2.8.2@4433.7,1462.2 v1(4464.17,1462.2)
  Bottom Layer w8: U1.8.23@4304.65,1346.91 4304.88,1346.67 4304.88,1334.93 v1(4305.12,1334.69) ; U1.8.13@4409.47,1471.42 4454.96,1471.42 v1(4464.17,1462.2)
NetC15_2: C15.2 R32.2 U10.6 | length 108
  Top Layer w6: v1(6790,1025) 6790,1040.11 6788.81,1041.3 6788.81,1047.57 R32.2@6780,1056.38 6783.94,1060.32 C15.2@6820,1060.32
  Bottom Layer w4: v1(6790,1025) 6790.08,1025.08 6790.08,1055.75 U10.6@6790.16,1055.83
NetC20_2: C20.2 R36.2 U11.6 | length 96
  Top Layer w6: R36.2@4810,1056.38 R36.2@4818.81,1047.57 ; R36.2@4813.94,1060.32 C20.2@4850,1060.32 ; R36.2@4818.81,1041.3 4820,1040.11 v1(4820,1025)
  Bottom Layer w4: v1@4820.08,1025.08 U11.6@4820.08,1055.75
NetC31_2: C31.2 R93.2 U16.2 | length 173.7
  Top Layer w6.45: C31.2@1950,289.69 1960.31,300 R93.2@2006.38,300 v1(2024.87,300)
  Bottom Layer w6.45: U16.2@1985.71,250 2020,250 2034.87,264.87 2034.87,290 v1(2024.87,300)
NetC35_1: C35.1 R100.1 SW2.2 SW2.4 U21.2 | length 381.1
  Top Layer w8: SW2.4@1679.76,46.54 1711.54,46.54 v1(1720,55) ; v1(1900,75) 1900,46.77 SW2.2@1900.24,46.54
  Bottom Layer w8: C35.1@1720,106.38 v1(1720,55) 1795,55 1800,60 U21.2@1800,85.71 1800,110 1805,115 1845,115 1853.62,106.38 R100.1@1880,106.38 1880,102.44 1900,82.44 v1(1900,75)
NetC39_1: C39.1 C41.1 C42.1 C43.1 L1.1 R101.2 R102.2 R103.2 R104.2 U22.5 U22.10 U22.14 U22.16 | length 1028.6
  Top Layer w4: v1(1770,255) 1770.16,255.16 U22.10@1770.16,300.79 ; U22.16@1829.21,379.53 1829.21,389.21 1850,410 v1(1880,410)
  Top Layer w8: v1(1670,380) 1670.47,379.53 U22.5@1730.79,379.53 ; R103.2@1715,467.72 v1(1715,485) ; R104.2@1775,467.72 v1(1775,485) ; R102.2@1805,467.72 v1(1805,485) ; U22.14@1829.21,340.16 1881.81,340.16 1897.72,356.06 R101.2@1897.72,360 v1(1920,360)
  Bottom Layer w4: 1863.62,430 1867.56,430 ; v1@1877.37,412.63 v1(1880,410)
  Bottom Layer w20: v1(1670,380) C39.1@1696.38,380 ; v1(1770,255) C41.1@1770,276.38 1723.62,276.38 1696.38,303.62 C39.1@1696.38,380 ; v1(1880,410) 1880,402.44 1867.56,390 C43.1@1863.62,390 ; v1(1920,360) 1910,350 C42.1@1863.62,350 C43.1@1863.62,390 ; C39.1@1696.38,380 1696.38,474.66 1706.72,485 v1(1715,485) v1(1775,485) v1(1805,485) 1850,485 1863.62,471.38 1863.62,430 C43.1@1863.62,390
NetC79_2: C79.2 L2.1 U12.U8 | length 188.7
  Top Layer w10: U12.U8@3113.98,666.34 3113.98,667.36 3120,673.39 v1(3120,675)
  PWR w10: v1(3120,675) 3122.16,675 3128.17,681.01 3134.2,681.01 3136.59,683.41
  PWR w12: 3136.59,683.41 3165,711.81 v1(3165,815)
  Bottom Layer w10: v1(3120,675) C79.2@3130,665
NetC81_2: C81.2 TP1.1 U12.Y4 | length 224.7
  Top Layer w6: TP1.1@3200,915 3230,885 v1@3230,760 ; U12.Y4@3216.34,743.11 3216.34,745.22 3222.7,751.58 3222.7,757.7 v1(3225,760)
  Bottom Layer w6: C81.2@3213.66,730 3213.66,743.66 v1@3230,760
NetC82_2: C82.2 TP2.1 U12.P3 | length 79.8
  Top Layer w8: v1(3230,580) 3231.18,580 3240.75,589.57 U12.P3@3241.93,589.57
  Bottom Layer w8: v1(3230,580) 3229.87,580.13 3229.87,592.62 C82.2@3231.12,593.88 3232.38,595.13 3279.87,595.13 TP2.1@3280,595
NetC103_1: C103.1 L4.1 U23.1 U23.2 U23.3 | length 67.3
  Top Layer w8: L4.1@2120,1303.23 2125.54,1303.23 L4.1@2155,1273.76
  Bottom Layer w8: C103.1@2169.68,1230 2169.68,1249.68 v1(2170,1250)
NetC103_2: C103.2 U23.4 | length 49.6
  Top Layer w8: v1(2120,1250) 2120.08,1249.92 2120.08,1224.8 U23.4@2120.16,1224.72
  Bottom Layer w8: v1(2120,1250) 2120,1247.29 2124.47,1242.82 2124.47,1235.85 C103.2@2130.31,1230
NetC104_2: C104.2 C105.2 C106.2 C107.2 R134.2 R137.1 U23.10 U23.11 U23.12 | length 113
  Top Layer w8: R134.2@2150,1016.38 2150,1020.32 2175,1045.32 v1(2175,1090) ; v1(2380,1080) C106.2@2380,1108.98
  other v1: 2215,1080 2255,1080 2300,1080 2340,1080 2420,1080 2200,1115
NetC108_1: C108.1 C109.1 C110.1 C111.1 L4.2 R117.1 R122.2 R123.2 | length 983.7
  Top Layer w8: v1(2030,990) R123.2@2030,1016.38 R122.2@2070,1016.38 ; C110.1@2380,1407.09 R117.1@2380,1472.28
  Layer 2 w8: v1(2030,990) 2055,1015 2415,1015 2455,1055 2455,1355 2435,1375 v1(2405,1375)
  Bottom Layer w8: v1(2290,1375) C109.1@2290,1416.93
  other v1: 2265,1375 2315,1375 2355,1375 2380,1375
NetC112_1: C112.1 R122.1 R124.2 U23.7 | length 144.8
  Top Layer w8: C112.1@2030,1139.68 2055,1114.68 2055,1084.12 ; 2056.91,1084.12 2056.91,1076.91 2079.87,1099.87 2079.87,1114.35 U23.7@2080.79,1115.28
  Bottom Layer w8: v1(2055,1075) 2056.91,1076.91 2056.91,1093.29 R124.2@2060,1096.38
NetC112_2: C112.2 R123.1 | length 36.7
  Top Layer w8: R123.1@2030,1063.62 C112.2@2030,1100.32
NetC113_1: C113.1 R139.1 U24.3
NetC114_1: C114.1 R126.1 R128.2 U24.5 | length 159.1
  Top Layer w8: v1(1820,1380) 1840,1360 U24.5@1840,1339.13
  Bottom Layer w8: v1(1820,1380) R128.2@1820,1353.62 R126.1@1860,1353.62 1863.94,1349.68 1895.32,1349.68 C114.1@1900,1345
NetC114_2: C114.2 C115.1 L5.2 R125.1 R126.2 | length 277.1
  Top Layer w8: R125.1@1960,1147.72 1963.94,1147.72 1980,1163.78 v1(1980,1165)
  Bottom Layer w8: R126.2@1860,1306.38 1863.94,1310.32 1899.68,1310.32 1900,1310 1950,1310 1980,1280 v1(1980,1165)
  other v1: 1830,1110 1850,1110 1870,1110
NetC117_1: C117.1 U25.4 | length 73.2
  Bottom Layer w8: C117.1@3550,1420.32 3584.68,1420.32 3596.76,1408.24 3596.76,1393.68 U25.4@3601.61,1388.82
NetC117_2: C117.2 C118.2 L6.3 Q9.5 Q9.6 Q9.7 Q9.8 Q9.9@3345,1322.52 R129.2 R130.2 U25.5 | length 374.5
  Bottom Layer w8: Q9.9@3350,1325.47 3425.47,1250 3657.56,1250 3680,1272.44 R130.2@3680,1276.38
NetC119_2: C119.2 R131.1 | length 36.5
  Bottom Layer w8: R131.1@3366.38,1535 3366.38,1561.88 3370,1565.5 C119.2@3370,1570
NetC120_1: C120.1 D25.1 J2.2 J2.3 J5.1 L6.1
NetC120_2: C120.2 F1.1 L6.2
NetC123_2: C123.2 C124.2 U12.Y8 | length 91.3
  Top Layer w6: C124.2@3113.66,790 3114.71,791.05 3114.71,799.71 3123.77,808.77 3123.77,828.77 C123.2@3125,830 ; U12.Y8@3113.98,743.11 C124.2@3113.98,789.68
NetC125_2: C125.2 C126.2 U12.Y12 | length 93.9
  Top Layer w6: U12.Y12@3011.61,743.11 3011.61,773.39 3008.66,776.34 C126.2@3008.66,790 3009.71,791.05 3009.71,799.71 3021.13,811.13 3021.13,828.4 C125.2@3019.53,830
NetC128.1_2: C128.1.2 U19.1.2 | length 50.3
  Bottom Layer w4: C128.1.2@1009.69,1720 1025,1720 1035.79,1730.79 U19.1.2@1055.51,1730.79
NetC128.2_2: C128.2.2 U19.2.2 | length 50.3
  Bottom Layer w8: C128.2.2@1009.69,538.89 1028.71,538.89 1039.23,549.42 1055.24,549.42 U19.2.2@1055.51,549.68
NetC129.1_1: C129.1.1 C130.1.1 C131.1.2 C135.1.2 L7.1.1 U19.1.3 | length 23.8
  Bottom Layer w4: v1(1031.8,1750.66) 1031.89,1750.56 1055.42,1750.56 U19.1.3@1055.51,1750.47
NetC129.2_1: C129.2.1 C130.2.1 C131.2.2 C135.2.2 L7.2.1 U19.2.3 | length 27.3
  Bottom Layer w8: v1(1030,565) 1032.71,565 1036.35,568.65 1054.79,568.65 U19.2.3@1055.51,569.37
NetC132.1_1: C132.1.1 C133.1.1 C134.1.2 C137.1.2 L8.1.1 U19.1.17 | length 28
  Bottom Layer w4: U19.1.17@1244.49,1848.9 1261.19,1848.9 1267.29,1855 v1(1270,1855)
NetC132.2_1: C132.2.1 C133.2.1 C134.2.2 C137.2.2 L8.2.1 U19.2.17 | length 299.6
  Top Layer w10: v1(1270,670) 1238.9,638.9 C137.2.2@1219.69,638.9 C134.2.2@1219.69,668.9 1219.69,694.96 C133.2.1@1223.62,698.9 1228.87,704.14 1228.87,719.85 1257.09,748.07 C132.2.1@1257.09,758.9 1257.09,761.93 1277.68,782.52 L8.2.1@1320,782.52
  Bottom Layer w5: U19.2.17@1244.49,667.8 1267.8,667.8 v1(1270,670)
NetC136.1_1: C136.1.1 C139.1.2 J4.1.4 | length 172.9
  Top Layer w6: v1(825,1805) 825,1840 831.65,1846.65 J4.1.4@892.91,1846.65
  Bottom Layer w6: C139.1.2@819.69,1870 819.69,1850.31 822.7,1847.3 822.7,1830.92 C136.1.1@823.62,1830 825,1828.62 v1(825,1805)
NetC136.2_1: C136.2.1 C139.2.2 J4.2.4 | length 170.7
  Top Layer w8: v1(820,710) 820,680 834.45,665.55 J4.2.4@892.91,665.55
  Bottom Layer w8: v1(820,710) 819.84,709.84 819.84,690.15 C139.2.2@819.69,690 820,689.68 820,675 823.62,671.38 C136.2.1@823.62,650
NetC138.1_1: C138.1.1 C141.1.2 J4.1.7 | length 163.1
  Top Layer w6: v1(820,1730) 820,1705 828.35,1696.65 J4.1.7@892.91,1696.65
  Bottom Layer w6: v1(820,1730) 820,1710.31 C141.1.2@819.69,1710 820,1709.68 820,1690 822.7,1687.3 822.7,1670.92 C138.1.1@823.62,1670
NetC138.2_1: C138.2.1 C141.2.2 J4.2.7 | length 161.4
  Top Layer w8: v1(820,550) 820,530.72 835.17,515.55 J4.2.7@892.91,515.55
  Bottom Layer w8: v1(820,550) 819.84,549.84 819.84,530.15 C141.2.2@819.69,530 819.69,514.69 825,509.37 825,491.38 C138.2.1@823.62,490
NetC145_1: C145.1 R194.1 R196.2 U29.2 | length 153.3
  Top Layer w6: v1(2615,1875) R194.1@2615,1906.38 R196.2@2655,1906.38
  Bottom Layer w6: U29.2@2583.39,1912.28 2623.04,1912.28 C145.1@2625,1910.32 2625,1888.25 2615,1878.25 v1(2615,1875)
NetC147_2: C147.2 R201.2 U30.96 | length 105.2
  Top Layer w6: v1(2160,2170) R201.2@2160,2191.38 2163.94,2195.31 C147.2@2190,2195.31
  Bottom Layer w6: U30.96@2159.09,2118.15 2159.45,2118.51 2159.45,2169.45 v1(2160,2170)
NetC157_2: C157.2 C158.1 C159.1 U30.87 U30.115 | length 511
  Top Layer w6: C158.1@2020,2045 2020,2044.68 2028.81,2035.87 2029.13,2035.87 2040,2025 2110,2025 2130,2005 2130,1814.69 C157.2@2149.69,1795 ; C158.1@2020,2048.62 v1@2020,2075 ; C157.2@2150,1795 2153.62,1791.38 C159.1@2153.62,1765 v1(2175,1765)
  Bottom Layer w6: U30.87@2017.36,2118.15 2017.36,2082.64 v1(2020,2080) ; v1(2175,1765) 2185.27,1775.27 2217.79,1775.27 U30.115@2218.15,1775.63
NetC160_2: C160.2 U30.88 Y1.3 | length 183.8
  Top Layer w6: C160.2@2000,2239.68 2017.07,2239.68 2021.75,2235 v1(2025,2235)
  Bottom Layer w6: Y1.3@1996.69,2256.5 2003.5,2256.5 v1(2025,2235) ; v1@2024.06,2234.06 2033.11,2225 U30.88@2033.11,2118.15
NetC161_2: C161.2 U30.89 Y1.1 | length 156
  Top Layer w6: v1(2055,2215) 2065.51,2204.49 2075.83,2204.49 C161.2@2080,2200.32
  Bottom Layer w6: U30.89@2048.86,2118.15 2048.86,2163.98 2074.88,2190 Y1.1@2080,2190 ; v1(2055,2215) 2076.5,2193.5 Y1.1@2083.31,2193.5
NetC162_2: C162.2 R211.1 U30.68 | length 177.3
  Bottom Layer w6: C162.2@1675,2200 1675,2175 1685,2165 1714.63,2165 1718.15,2161.49 U30.68@1718.15,2118.15 ; C162.2@1675,2200.31 1681.84,2207.16 1682.47,2207.16 1715,2239.68 R211.1@1715,2243.62
NetC164_1: C164.1 L9.1 U22.13 | length 120.8
  Top Layer w10: U22.13@1829.21,320.47 1884.53,320.47 v1(1890,315)
  Bottom Layer w10: C164.1@1863.62,315 v1(1890,315) L9.1@1921.38,315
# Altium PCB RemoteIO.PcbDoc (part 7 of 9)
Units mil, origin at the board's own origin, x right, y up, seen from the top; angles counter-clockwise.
Board outline 7874.02 x 2362.2 mil, 6 copper layers (Top Layer, GND1, Layer 2, PWR, GND2, Bottom Layer), stack 60.956 mil thick; 686 components, 447 nets, 2681 pads, 1481 vias.

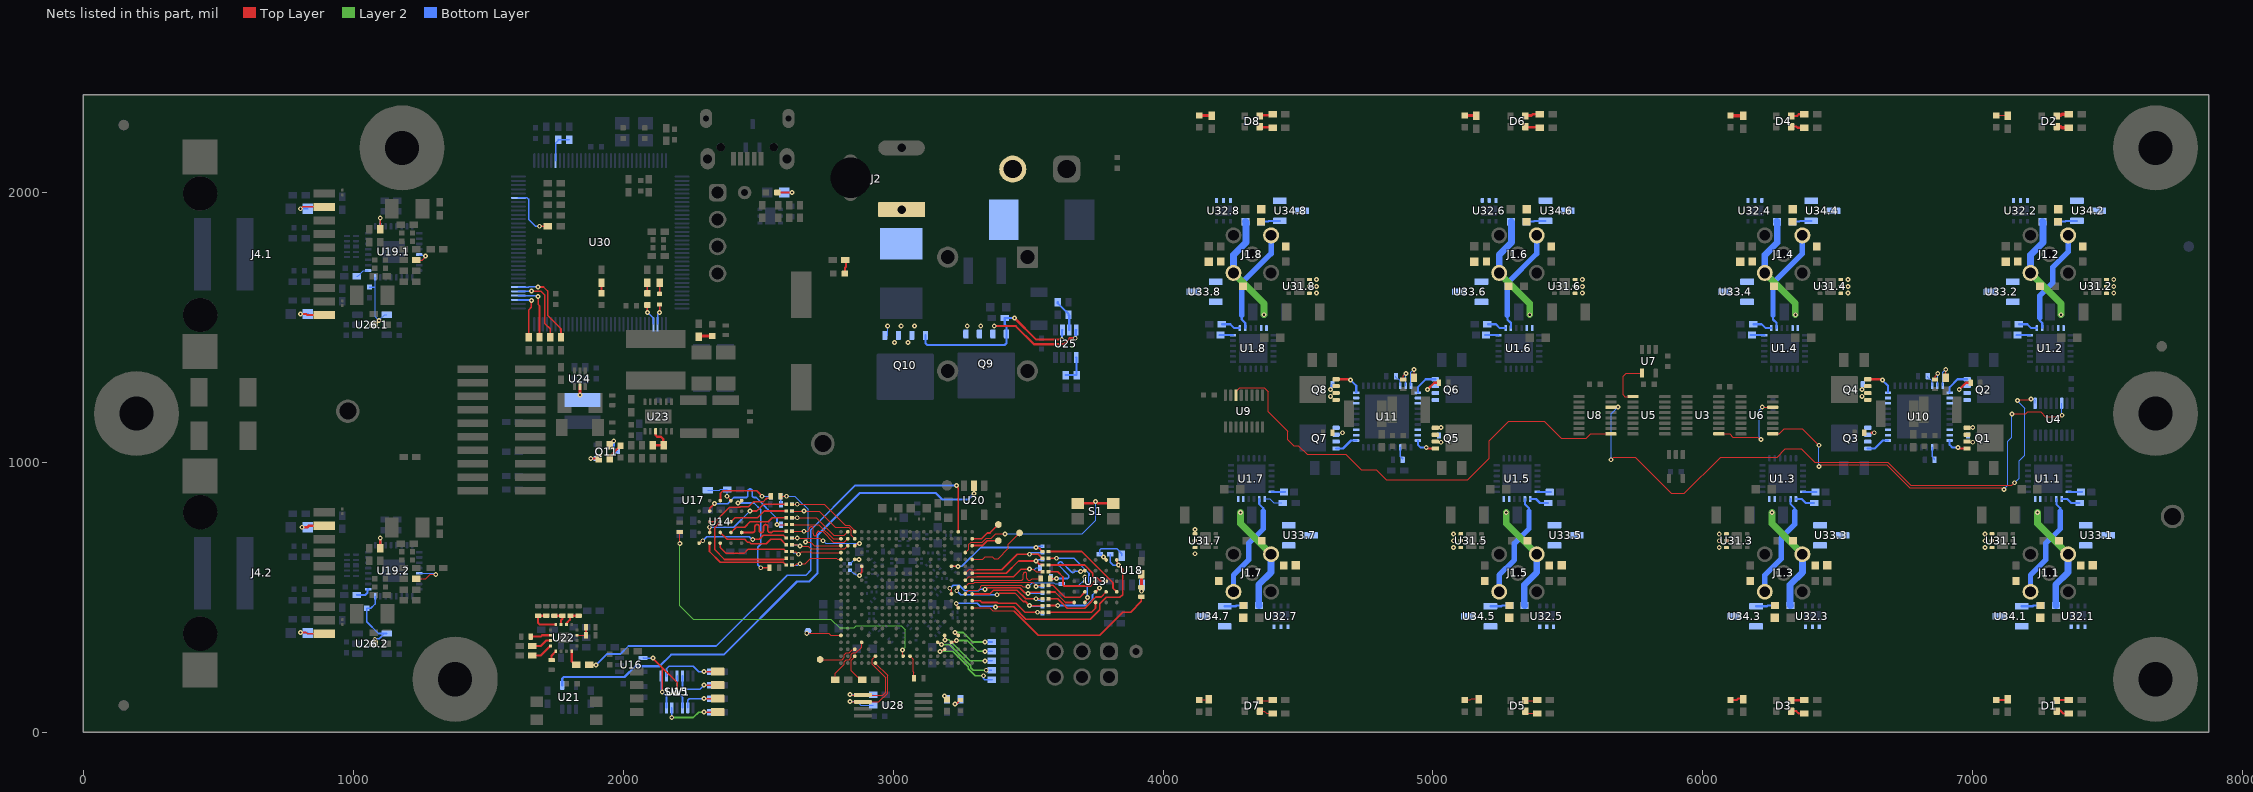
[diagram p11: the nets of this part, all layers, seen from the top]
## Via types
v1: diameter 18, hole 8, Top Layer to Bottom Layer, tented both sides, 1314 vias
v2: diameter 19.68, hole 7.87, Top Layer to Bottom Layer, tented both sides, 133 vias
v3: diameter 19.68, hole 7.87, Top Layer to Bottom Layer, 34 vias

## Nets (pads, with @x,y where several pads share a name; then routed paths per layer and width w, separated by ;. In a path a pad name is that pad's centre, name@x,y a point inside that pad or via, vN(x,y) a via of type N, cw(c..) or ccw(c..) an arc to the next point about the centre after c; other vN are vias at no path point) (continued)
NetC165.1_2: C165.1.2 J1.1.2 RV1.1.1 RV4.1.2 RV5.1.2 U1.1.11 U1.1.12 U33.1.1 U33.1.2 | length 411.7
  Layer 2 w25: v1(7240,815) 7240,773.21 J1.1.2@7353.06,660.15
  Bottom Layer w25: RV5.1.2@7308.54,470 7308.31,470 7307.03,471.28 7307.03,547.03 7353.06,593.06 J1.1.2@7353.06,660.15
NetC165.2_2: C165.2.2 J1.2.2 RV1.2.1 RV4.2.2 RV5.2.2 U1.2.11 U1.2.12 U33.2.1 U33.2.2 | length 411.7
  Layer 2 w25: J1.2.2@7213.87,1702.06 7326.93,1588.99 v1(7326.93,1547.2)
  Bottom Layer w25: J1.2.2@7213.87,1702.06 7213.87,1769.14 7259.9,1815.17 7259.9,1890.93 7258.62,1892.2 RV5.2.2@7258.39,1892.2
NetC165.3_2: C165.3.2 J1.3.2 RV1.3.1 RV4.3.2 RV5.3.2 U1.3.11 U1.3.12 U33.3.1 U33.3.2 | length 411.7
  Layer 2 w25: v1(6255.75,815) 6255.75,773.21 J1.3.2@6368.81,660.15
  Bottom Layer w25: RV5.3.2@6324.29,470 6324.06,470 6322.78,471.28 6322.78,547.03 6368.81,593.06 J1.3.2@6368.81,660.15
NetC165.4_2: C165.4.2 J1.4.2 RV1.4.1 RV4.4.2 RV5.4.2 U1.4.11 U1.4.12 U33.4.1 U33.4.2 | length 411.7
  Layer 2 w25: J1.4.2@6229.62,1702.06 6342.68,1588.99 v1(6342.68,1547.2)
  Bottom Layer w25: J1.4.2@6229.62,1702.06 6229.62,1769.14 6275.64,1815.17 6275.64,1890.93 6274.36,1892.2 RV5.4.2@6274.13,1892.2
NetC165.5_2: C165.5.2 J1.5.2 RV1.5.1 RV4.5.2 RV5.5.2 U1.5.11 U1.5.12 U33.5.1 U33.5.2 | length 411.7
  Layer 2 w25: v1(5271.5,815) 5271.5,773.21 J1.5.2@5384.56,660.15
  Bottom Layer w25: RV5.5.2@5340.04,470 5339.81,470 5338.53,471.28 5338.53,547.03 5384.56,593.06 J1.5.2@5384.56,660.15
NetC165.6_2: C165.6.2 J1.6.2 RV1.6.1 RV4.6.2 RV5.6.2 U1.6.11 U1.6.12 U33.6.1 U33.6.2 | length 411.7
  Layer 2 w25: J1.6.2@5245.36,1702.06 5358.43,1588.99 v1(5358.43,1547.2)
  Bottom Layer w25: J1.6.2@5245.36,1702.06 5245.36,1769.14 5291.39,1815.17 5291.39,1890.93 5290.11,1892.2 RV5.6.2@5289.88,1892.2
NetC165.7_2: C165.7.2 J1.7.2 RV1.7.1 RV4.7.2 RV5.7.2 U1.7.11 U1.7.12 U33.7.1 U33.7.2 | length 411.7
  Layer 2 w25: v1(4287.24,815) 4287.24,773.21 J1.7.2@4400.31,660.15
  Bottom Layer w25: RV5.7.2@4355.79,470 4355.56,470 4354.28,471.28 4354.28,547.03 4400.31,593.06 J1.7.2@4400.31,660.15
NetC165.8_2: C165.8.2 J1.8.2 RV1.8.1 RV4.8.2 RV5.8.2 U1.8.11 U1.8.12 U33.8.1 U33.8.2 | length 411.7
  Layer 2 w25: J1.8.2@4261.11,1702.06 4374.17,1588.99 v1(4374.17,1547.2)
  Bottom Layer w25: J1.8.2@4261.11,1702.06 4261.11,1769.14 4307.14,1815.17 4307.14,1890.93 4305.86,1892.2 RV5.8.2@4305.63,1892.2
NetC166.1_2: C166.1.2 J1.1.4 RV2.1.1 RV5.1.1 RV6.1.1 U1.1.8 U34.1.1 U34.1.2 | length 466.8
  Bottom Layer w8: U34.1.1@7181.34,467.4 7222.4,467.4 7225,470 RV5.1.1@7250,470 ; J1.1.4@7212.91,520 J1.1.4@7213.87,520.95 ; U1.1.8@7309.53,864.7 7309.53,845.51 7324.43,830.61 7324.43,820
  Bottom Layer w20: J1.1.4@7213.87,520.95 7213.87,582.51 7270,638.64 7270,700 7324.43,754.43 7324.43,820
NetC166.2_2: C166.2.2 J1.2.4 RV2.2.1 RV5.2.1 RV6.2.1 U1.2.8 U34.2.1 U34.2.2 | length 462.1
  Bottom Layer w8: 7248.19,1535.21 7248.19,1525.91 7257.4,1516.7 U1.2.8@7257.4,1497.5 ; RV5.2.1@7316.93,1892.2 7341.93,1892.2 7344.53,1894.8 U34.2.1@7385.59,1894.8 ; J1.2.4@7353.06,1841.25 J1.2.4@7354.02,1842.2
  Bottom Layer w20: 7248.19,1535.21 7248.19,1618.46 7296.93,1667.2 7296.93,1723.56 7353.06,1779.69 J1.2.4@7353.06,1841.25
NetC166.3_2: C166.3.2 J1.3.4 RV2.3.1 RV5.3.1 RV6.3.1 U1.3.8 U34.3.1 U34.3.2 | length 466.7
  Bottom Layer w8: U34.3.1@6197.09,467.4 6238.15,467.4 6240.75,470 RV5.3.1@6265.75,470 ; J1.3.4@6228.66,520 J1.3.4@6229.62,520.95 ; U1.3.8@6325.28,864.7 6325.28,845.51 6340,830.78 6340,820
  Bottom Layer w20: J1.3.4@6229.62,520.95 6229.62,582.51 6290,642.9 6290,720 6340,770 6340,820
NetC166.4_2: C166.4.2 J1.4.4 RV2.4.1 RV5.4.1 RV6.4.1 U1.4.8 U34.4.1 U34.4.2 | length 464
  Bottom Layer w8: 6260,1545 6260,1529.85 6273.15,1516.7 U1.4.8@6273.15,1497.5 ; RV5.4.1@6332.68,1892.2 6357.68,1892.2 6360.28,1894.8 U34.4.1@6401.34,1894.8
  Bottom Layer w20: 6260,1545 6260,1665 6368.81,1773.81 J1.4.4@6368.81,1841.25
NetC166.5_2: C166.5.2 J1.5.4 RV2.5.1 RV5.5.1 RV6.5.1 U1.5.8 U34.5.1 U34.5.2 | length 466.8
  Bottom Layer w8: U34.5.1@5212.83,467.4 5253.9,467.4 5256.5,470 RV5.5.1@5281.5,470 ; J1.5.4@5244.41,520 J1.5.4@5245.36,520.95 ; U1.5.8@5341.02,864.7 5341.02,845.51 5355.93,830.61 5355.93,820
  Bottom Layer w20: J1.5.4@5245.36,520.95 5245.36,582.51 5301.5,638.64 ; 5301.5,640.34 5301.5,701.69 ; 5301.5,700 5355.93,754.43 5355.93,820
NetC166.6_2: C166.6.2 J1.6.4 RV2.6.1 RV5.6.1 RV6.6.1 U1.6.8 U34.6.1 U34.6.2 | length 459.5
  Bottom Layer w8: 5275.75,1545 5275.75,1529.85 5288.9,1516.7 U1.6.8@5288.9,1497.5 ; RV5.6.1@5348.43,1892.2 5373.43,1892.2 5376.02,1894.8 U34.6.1@5417.09,1894.8 ; J1.6.4@5384.56,1841.25 J1.6.4@5385.51,1842.2
  Bottom Layer w20: 5275.75,1545 5275.75,1665 5384.56,1773.81 ; 5384.56,1779.69 J1.6.4@5384.56,1841.25
NetC166.7_2: C166.7.2 J1.7.4 RV2.7.1 RV5.7.1 RV6.7.1 U1.7.8 U34.7.1 U34.7.2 | length 466.8
  Bottom Layer w8: U34.7.1@4228.58,467.4 4269.65,467.4 4272.24,470 RV5.7.1@4297.24,470 ; J1.7.4@4260.16,520 J1.7.4@4261.11,520.95 ; U1.7.8@4356.77,864.7 4356.77,845.51 4371.67,830.61 4371.67,820
  Bottom Layer w20: J1.7.4@4261.11,520.95 4261.11,582.51 4317.24,638.64 ; 4317.24,640.34 4317.24,701.69 ; 4317.24,700 4371.67,754.43 4371.67,820
NetC166.8_2: C166.8.2 J1.8.4 RV2.8.1 RV5.8.1 RV6.8.1 U1.8.8 U34.8.1 U34.8.2 | length 459.5
  Bottom Layer w8: 4291.5,1545 4291.5,1529.85 4304.65,1516.7 U1.8.8@4304.65,1497.5 ; RV5.8.1@4364.17,1892.2 4389.17,1892.2 4391.77,1894.8 U34.8.1@4432.83,1894.8 ; J1.8.4@4400.31,1841.25 J1.8.4@4401.26,1842.2
  Bottom Layer w20: 4291.5,1545 4291.5,1665 4400.31,1773.81 ; 4400.31,1779.69 J1.8.4@4400.31,1841.25
NetC168.1_2: C168.1.2 R164.1.1 U19.1.32 U26.1.4 | length 251.2
  Top Layer w4: R164.1.1@1076.38,1510 1080.32,1510 1095.44,1525.13 v1(1095.44,1525.62)
  Bottom Layer w4: U19.1.32@1081.1,1685.51 1081.1,1650 1081.1,1539.96 v1(1095.44,1525.62) 1095.44,1526.58 1116.26,1547.4 U26.1.4@1124.13,1547.4
  Bottom Layer w5: C168.1.2@1060,1649.69 1080.79,1649.69 1081.1,1650
NetC168.2_2: C168.2.2 R164.2.1 U19.2.32 U26.2.4 | length 273.3
  Top Layer w6: R164.2.1@1076.38,328.9 1075,330.28 1075,340.57 1078.51,344.09 v1(1080,344.09)
  Bottom Layer w6: C168.2.2@1049.69,460 1065.33,460 1081.1,475.76 U19.2.32@1081.1,504.41 ; C168.2.2@1050,460.31 1050,410 1093.7,366.3 U26.2.4@1116.26,366.3 ; v1(1080,344.09) 1082.3,346.38 1096.34,346.38 U26.2.4@1116.26,366.3 ; U26.2.4@1124.13,366.3 U26.2.4@1116.26,366.3
NetD1_3: D1.3 R3.1 | length 48.6
  Top Layer w8: D1.3@7311.02,78.74 7312.28,80 7325,80 7335,70 R3.1@7355,70
NetD1_4: D1.4 R4.1 | length 44.1
  Top Layer w8: D1.4@7315,115 7315,116.17 7318.83,120 R4.1@7356.38,120
NetD2_3: D2.3 R5.1 | length 47.8
  Top Layer w12: D2.3@7311.02,2244.09 7311.93,2245 7325,2245 7330,2240 R5.1@7356.38,2240
NetD2_4: D2.4 R6.1 | length 48.1
  Top Layer w12: D2.4@7311.02,2283.46 7312.56,2285 7325,2285 7330,2290 R6.1@7356.38,2290
NetD3_3: D3.3 R7.1 | length 53.2
  Top Layer w8: D3.3@6326.77,78.74 6346.26,78.74 6355,70 R7.1@6376.38,70
NetD3_4: D3.4 R8.1 | length 50.4
  Top Layer w8: D3.4@6326.77,118.11 6327.72,119.06 6375.43,119.06 R8.1@6376.38,120
NetD4_3: D4.3 R9.1 | length 51.3
  Top Layer w8: D4.3@6326.77,2244.09 6345.91,2244.09 6350,2240 R9.1@6376.38,2240
NetD4_4: D4.4 R10.1 | length 52.3
  Top Layer w8: D4.4@6326.77,2283.46 6348.46,2283.46 6355,2290 R10.1@6376.38,2290
NetD5_3: D5.3 R11.1 | length 47.5
  Top Layer w4: D5.3@5342.52,78.74 5349.88,71.38 5385,71.38 R11.1@5386.38,70
NetD5_4: D5.4 R12.1 | length 44.6
  Top Layer w4: D5.4@5342.52,118.11 5384.49,118.11 R12.1@5386.38,120
NetD6_3: D6.3 R13.1 | length 56.2
  Top Layer w10: D6.3@5342.52,2244.09 5344.57,2242.05 5387.95,2242.05 R13.1@5395,2235
NetD6_4: D6.4 R14.1 | length 55.2
  Top Layer w10: D6.4@5342.52,2283.46 5344.06,2285 5365,2285 5370,2290 R14.1@5395,2290
NetD7_3: D7.3 R15.1 | length 51.7
  Top Layer w4: D7.3@4358.27,78.74 4375.53,78.74 4384.27,70 R15.1@4406.38,70
NetD7_4: D7.4 R16.1 | length 48.9
  Top Layer w4: D7.4@4358.27,118.11 4404.49,118.11 R16.1@4406.38,120
NetD8_3: D8.3 R17.1 | length 49.8
  Top Layer w8: D8.3@4358.27,2244.09 D8.3@4360.32,2242.05 ; R17.1@4404.33,2242.05 R17.1@4406.38,2240
  Top Layer w10: D8.3@4360.32,2242.05 R17.1@4404.33,2242.05
NetD8_4: D8.4 R18.1 | length 49.4
  Top Layer w10: D8.4@4358.27,2283.46 4361.54,2286.73 4401.73,2286.73 R18.1@4405,2290
NetD9_2: D9.2 R19.1 | length 43.4
  Top Layer w8: D9.2@7086.61,120.08 7129.92,120.08 R19.1@7130,120
NetD10_2: D10.2 R20.1 | length 44.1
  Top Layer w4: D10.2@7086.61,2285.43 7128.19,2285.43 R20.1@7130,2283.62
NetD11_2: D11.2 R21.1 | length 50.2
  Top Layer w8: D11.2@6102.36,120.08 6125.08,120.08 6130,125 6148.62,125 R21.1@6150,123.62
NetD12_2: D12.2 R22.1 | length 48.4
  Top Layer w12: D12.2@6102.36,2285.43 6103.27,2284.53 6149.09,2284.53 R22.1@6150,2283.62
NetD13_2: D13.2 R23.1 | length 54.5
  Top Layer w4: D13.2@5118.11,120.08 5139.07,120.08 5144,125 5168.62,125 R23.1@5170,123.62
NetD14_2: D14.2 R24.1 | length 45.9
  Top Layer w10: D14.2@5115,2285 5115.43,2285.43 D14.2@5118.11,2285.43 5158.19,2285.43 R24.1@5160,2283.62
NetD15_2: D15.2 R25.1 | length 37.6
  Top Layer w4: D15.2@4133.86,120.08 4166.46,120.08 R25.1@4170,123.62
NetD16_2: D16.2 R26.1 | length 45.9
  Top Layer w10: D16.2@4135,2285 4135.43,2285.43 4178.19,2285.43 R26.1@4180,2283.62
NetD20_1: D20.1 R136.2 | length 52
  Top Layer w8: D20.1@2821.65,1700 2821.65,1721.65 2825,1725 2825,1748.62 R136.2@2823.62,1750
NetD21_1: D21.1 R138.2 | length 50.8
  Top Layer w10: R138.2@2280,1466.38 2281.97,1468.35 D21.1@2330,1468.35
NetD22_1: D22.1 R140.2 | length 61.8
  Top Layer w8: R140.2@1950,1016.38 1957.81,1024.19 1957.81,1029.46 D22.1@1990,1061.65
NetD23_1: D23.1 R143.2 | length 49.3
  Top Layer w8: v1@3236.05,106.91 3248.82,119.68 D23.1@3250,119.68
  Bottom Layer w8: v1(3230,105) 3231.91,106.91 3237.23,106.91 3250,119.68 R143.2@3250,123.62
NetD24_1: D24.1 R142.2 | length 17.5
  Top Layer w8: v1(3190,135) 3190,132.29 3192.19,130.11 3192.19,129.46 D24.1@3200,121.65
NetD25_2: D25.2 F1.2 J2.1 J5.2
NetD28_1: D28.1 R206.2 | length 42.4
  Top Layer w6: D28.1@2135,1624.68 2135,1660 R206.2@2140,1665
NetD28_2: D28.2 U30.3 | length 76.5
  Top Layer w6: v1(2135,1555) D28.2@2135,1585.32
  Bottom Layer w6: U30.3@2127.6,1511.85 2127.6,1547.6 v1(2135,1555)
NetD29_1: D29.1 R207.2 | length 43.3
  Top Layer w6: D29.1@2090,1626.65 R207.2@2090,1666.38 R207.2@2090,1670
NetD29_2: D29.2 U30.4 | length 81.9
  Top Layer w6: v1(2090,1555) D29.2@2090,1583.35
  Bottom Layer w6: v1(2090,1555) 2092.32,1555 2111.85,1535.47 U30.4@2111.85,1511.85
NetD30_1: D30.1 R195.2 | length 43.3
  Top Layer w6: D30.1@1920,1626.65 R195.2@1920,1666.38 R195.2@1920,1670
NetD31_1: D31.1 R213.2 | length 81.9
  Top Layer w6: D31.1@2571.61,2000 v1(2625,2000)
  Bottom Layer w6: R213.2@2596.5,2000 v1(2625,2000)
NetJ4.1_2: J4.1.2 R192.1.2 | length 117.2
  Top Layer w6: v1(805,1940) 811.65,1946.65 J4.1.2@892.91,1946.65
  Bottom Layer w6: v1(805,1940) R192.1.2@831.5,1940
NetJ4.1_10: J4.1.10 R191.1.2 | length 115.8
  Top Layer w8: v1(805,1550) 825,1550 828.35,1546.65 J4.1.10@892.91,1546.65
  Bottom Layer w8: v1(805,1550) R191.1.2@831.5,1550
NetJ4.2_2: J4.2.2 R192.2.2 | length 106.7
  Top Layer w10: v1(810,760) 830,760 835.55,765.55 J4.2.2@892.91,765.55
  Bottom Layer w10: v1(810,760) R192.2.2@831.5,760
NetJ4.2_10: J4.2.10 R191.2.2 | length 116.7
  Top Layer w6: v1(805,370) 826.1,370 830.55,365.55 J4.2.10@892.91,365.55
  Bottom Layer w6: v1(805,370) 830.39,370 R191.2.2@831.5,368.9
NetL5_1: L5.1 U24.2 | length 30.9
  Top Layer w12: v1(1840,1250) U24.2@1840,1280.87
NetQ1_1: Q1.1 Q1.2 Q1.3 R155.1 U10.38 U10.39 | length 5.9
  Top Layer w8: Q1.2@6973.07,1102.8 Q1.2@6978.58,1102.8 Q1.2@6978.98,1102.8
  other v1: 7000,1075 7000,1130
NetQ1_4: Q1.4 U10.40 | length 81.3
  Top Layer w8: v1(6945,1055) 6948.39,1051.61 Q1.4@6978.58,1051.61 Q1.4@6978.98,1051.61
  Bottom Layer w8: U10.40@6914.17,1081.42 6914.17,1065.83 6925,1055 v1@6940,1055
NetQ2_1: Q2.1 Q2.2 Q2.3 R156.1 U10.32 U10.33 | length 52.6
  Top Layer w8: v1(6950,1270) 6975,1295 R156.1@6992.28,1295
NetQ2_4: Q2.4 U10.31 | length 97.5
  Bottom Layer w8: U10.31@6914.17,1258.58 6914.17,1279.17 6943.39,1308.39 Q2.4@6978.98,1308.39
NetQ3_1: Q3.1 Q3.2 Q3.3 R157.1 U10.12 U10.13 | length 10
  Top Layer w8: 6625,1110 v1(6635,1110)
NetQ3_4: Q3.4 U10.11 | length 87.1
  Bottom Layer w8: Q3.4@6611.02,1051.61 6636.61,1051.61 6666.42,1081.42 U10.11@6685.83,1081.42
NetQ4_1: Q4.1 Q4.2 Q4.3 R158.1 U10.18 U10.19 | length 1.1
  Top Layer w8: Q4.1@6610.22,1230.81 Q4.1@6611.02,1231.61
  other v1: 6590,1245 6590,1270
NetQ4_4: Q4.4 U10.20 | length 115.4
  Top Layer w8: Q4.4@6611.02,1308.39 6666.61,1308.39 v1@6670,1305
  Bottom Layer w8: v1(6665,1305) 6685.83,1284.17 U10.20@6685.83,1258.58
NetQ5_1: Q5.1 Q5.2 Q5.3 R159.1 U11.38 U11.39
  other v1: 5030,1075 5030,1130
NetQ5_4: Q5.4 U11.40 | length 76.1
  Top Layer w8: v1@4978.39,1051.61 Q5.4@5008.58,1051.61
  Bottom Layer w8: U11.40@4944.17,1081.42 4944.17,1065.83 4955,1055 v1@4970,1055
  other v1: 4975,1055
NetQ6_1: Q6.1 Q6.2 Q6.3 R160.1 U11.32 U11.33 | length 52.6
  Top Layer w8: v1(4980,1270) 5005,1295 R160.1@5022.28,1295
NetQ6_4: Q6.4 U11.31 | length 97.5
  Bottom Layer w8: U11.31@4944.17,1258.58 4944.17,1279.17 4973.39,1308.39 Q6.4@5008.98,1308.39
NetQ7_1: Q7.1 Q7.2 Q7.3 R161.1 U11.12 U11.13
  other v1: 4665,1110
NetQ7_4: Q7.4 U11.11 | length 87.1
  Bottom Layer w8: Q7.4@4641.02,1051.61 4666.61,1051.61 4696.42,1081.42 U11.11@4715.83,1081.42
NetQ8_1: Q8.1 Q8.2 Q8.3 R162.1 U11.18 U11.19 | length 24.1
  Bottom Layer w8: v1(4620,1270) 4620,1272.71 4623.84,1276.55 4623.84,1283.84 R162.1@4630,1290
  other v1: 4620,1245
NetQ8_4: Q8.4 U11.20 | length 110.6
  Top Layer w8: Q8.4@4641.02,1308.39 v1@4696.61,1308.39
  Bottom Layer w8: v1(4695,1305) 4715.83,1284.17 U11.20@4715.83,1258.58
NetQ9_1: Q9.1 Q9.2 Q9.3 Q10.1 Q10.2 Q10.3 U25.8 | length 404.4
  Top Layer w8: v1(3375,1505) 3455,1505 3522,1438 3632.04,1438 3654.04,1460 v1(3675,1460)
  Bottom Layer w4: Q10.1@2980,1470 v1(2980,1505)
  Bottom Layer w8: v1(3675,1460) 3676.69,1461.69 3676.69,1489.49 U25.8@3678.39,1491.18
  other v1: 3005,1445 3055,1445 3030,1505 3080,1505 3275,1505 3325,1505
NetQ9_4: Q9.4 Q10.4 R131.2 U25.6 | length 712
  Top Layer w8: v1(3450,1535) 3530,1455 v1(3625,1455)
  Bottom Layer w8: Q10.4@3120,1470.98 3120,1442.02 3127.02,1435 3412.98,1435 3420,1442.02 Q9.4@3420,1476.06 3420,1504.76 3418.57,1506.19 3413.62,1511.34 R131.2@3413.62,1535 v1(3450,1535) ; v1(3625,1455) 3626.1,1456.1 3626.1,1490.08 U25.6@3627.2,1491.18
NetQ11_1: Q11.1 R141.1 | length 53.4
  Top Layer w8: v1(1880,1015) 1908.62,1015 R141.1@1910,1016.38
  Bottom Layer w8: v1(1880,1015) 1880.59,1014.41 Q11.1@1902.6,1014.41
NetQ11_3: Q11.3 R140.1 | length 70.7
  Top Layer w8: R140.1@1950,1063.62 1950,1067.56 1962.44,1080 v1(1965,1080)
  Bottom Layer w8: v1(1965,1080) 1965,1052.4 1969.59,1047.81 1969.59,1045.25 1974.84,1040 Q11.3@1977.4,1040
NetR1.1_2: R1.1.2 U1.1.6 | length 50
  Bottom Layer w8: U1.1.6@7355.3,890.79 7355.69,890.39 7404.61,890.39 R1.1.2@7405,890
NetR1.2_2: R1.2.2 U1.2.6 | length 50
  Bottom Layer w8: R1.2.2@7161.93,1472.2 7162.32,1471.81 7211.24,1471.81 U1.2.6@7211.63,1471.42
NetR1.3_2: R1.3.2 U1.3.6 | length 50
  Bottom Layer w8: U1.3.6@6371.04,890.79 6371.44,890.39 6420.35,890.39 R1.3.2@6420.75,890
NetR1.4_2: R1.4.2 U1.4.6 | length 50
  Bottom Layer w8: R1.4.2@6177.68,1472.2 6178.07,1471.81 6226.99,1471.81 U1.4.6@6227.38,1471.42
NetR1.5_2: R1.5.2 U1.5.6 | length 50
  Bottom Layer w8: U1.5.6@5386.79,890.79 5387.19,890.39 5436.1,890.39 R1.5.2@5436.5,890
NetR1.6_2: R1.6.2 U1.6.6 | length 50
  Bottom Layer w8: R1.6.2@5193.43,1472.2 5193.82,1471.81 5242.74,1471.81 U1.6.6@5243.13,1471.42
NetR1.7_2: R1.7.2 U1.7.6 | length 50
  Bottom Layer w8: U1.7.6@4402.54,890.79 4402.93,890.39 4451.85,890.39 R1.7.2@4452.24,890
NetR1.8_2: R1.8.2 U1.8.6 | length 50
  Bottom Layer w8: R1.8.2@4209.17,1472.2 4209.57,1471.81 4258.48,1471.81 U1.8.6@4258.88,1471.42
NetR2.1_2: R2.1.2 U1.1.7 | length 71.9
  Bottom Layer w8: U1.1.7@7329.21,864.7 7350.3,864.7 7365,850 R2.1.2@7395,850
NetR2.2_2: R2.2.2 U1.2.7 | length 71.9
  Bottom Layer w8: R2.2.2@7171.93,1512.2 7201.93,1512.2 7216.63,1497.5 U1.2.7@7237.72,1497.5
NetR2.3_2: R2.3.2 U1.3.7 | length 71.9
  Bottom Layer w8: U1.3.7@6344.96,864.7 6366.04,864.7 6380.75,850 R2.3.2@6410.75,850
NetR2.4_2: R2.4.2 U1.4.7 | length 71.9
  Bottom Layer w8: R2.4.2@6187.68,1512.2 6217.68,1512.2 6232.38,1497.5 U1.4.7@6253.46,1497.5
NetR2.5_2: R2.5.2 U1.5.7 | length 71.9
  Bottom Layer w8: U1.5.7@5360.71,864.7 5381.79,864.7 5396.5,850 R2.5.2@5426.5,850
NetR2.6_2: R2.6.2 U1.6.7 | length 71.9
  Bottom Layer w8: R2.6.2@5203.43,1512.2 5233.43,1512.2 5248.13,1497.5 U1.6.7@5269.21,1497.5
NetR2.7_2: R2.7.2 U1.7.7 | length 69.6
  Bottom Layer w4: U1.7.7@4376.46,864.7 4395.3,864.7 4410,850 R2.7.2@4440,850
NetR2.8_2: R2.8.2 U1.8.7 | length 71.9
  Bottom Layer w8: R2.8.2@4219.17,1512.2 4249.17,1512.2 4263.88,1497.5 U1.8.7@4284.96,1497.5
NetR27_2: R27.2 U10.28 | length 44.1
  Bottom Layer w4: R27.2@6832.72,1320 6832.72,1316.06 6838.59,1310.19 6841.01,1310.19 6849.21,1301.98 U10.28@6849.21,1284.17
NetR28_1: R28.1 U10.3 | length 49.3
  Bottom Layer w6: U10.3@6849.21,1055.83 6849.21,1022.44 6857.72,1013.94 R28.1@6857.72,1010
NetR30_1: R30.1 U10.29 | length 72.7
  Top Layer w4: R30.1@6860,1307.72 6860,1320 v1(6870,1330)
  Bottom Layer w4: U10.29@6868.9,1284.17 6869.45,1284.72 6869.45,1329.45 v1(6870,1330)
NetR31_2: R31.2 U10.30 | length 96.9
  Top Layer w4: R31.2@6900,1313.62 v1(6900,1345)
  Bottom Layer w4: U10.30@6888.58,1284.17 6888.58,1333.58 v1(6900,1345)
NetR33_2: R33.2 U11.28 | length 44.1
  Bottom Layer w4: R33.2@4862.72,1320 4862.72,1316.06 4868.59,1310.19 4871.01,1310.19 4879.21,1301.98 U11.28@4879.21,1284.17
NetR34_1: R34.1 U11.3 | length 45.4
  Bottom Layer w6: U11.3@4879.21,1055.83 4879.21,1022.44 R34.1@4887.72,1013.94
NetR35_2: R35.2 U12.B10 | length 88.6
  Top Layer w4: U12.B10@3062.8,282.48 3075.19,270.09 3075.19,225.19 3075,225 3077.28,222.72 R35.2@3077.28,200
NetR37_1: R37.1 U11.29 | length 115.9
  Top Layer w4: R37.1@4890,1308.39 4890,1320.67 v1@4900,1330.67
  Bottom Layer w4: U11.29@4899.45,1284.72 4899.45,1329.45 U11.29@4899.45,1284.72
  other v1: 4900,1330
NetR38_2: R38.2 U11.30 | length 162.5
  Top Layer w4: R38.2@4930,1314.29 v1@4930,1345.67
  Bottom Layer w4: 4918.58,1333.58 v1(4930,1345) 4918.58,1333.58 ; 4918.58,1333.58 U11.30@4918.58,1284.17 4918.58,1333.58
NetR39_1: R39.1 U12.B18 | length 113.9
  Top Layer w4: U12.B18@2858.07,282.48 2858.07,279.94 2845.68,267.55 2845.68,228.11 2868.79,205 2870.29,205 2870.48,204.81 2872.63,204.81 2882.44,195 R39.1@2886.38,195
NetR40_1: R40.1 U12.D17 | length 186.8
  Top Layer w4: R40.1@2786.38,200 2786.38,218.86 2819.28,251.76 2819.28,261.21 2827.35,269.28 2836.8,269.28 2845,277.48 2845,290 2849.87,294.87 2862.39,294.87 2883.66,316.14 U12.D17@2883.66,333.66
NetR52_2: R52.2 U13.C3 | length 220.3
  Top Layer w6: R52.2@3576.02,595 3610,595 3629.37,575.63 3629.37,546 3632.89,542.49 3732.49,542.49 U13.C3@3750,560
NetR53_2: R53.2 U13.D3 | length 245.5
  Top Layer w6: R53.2@3576.02,470 v1(3610,470) ; U13.D3@3750,520.63 3750.31,520.63 3764.69,535 v1(3765,535)
  Bottom Layer w6: v1(3610,470) 3714.84,470 3738.77,493.93 3738.77,508.77 v1(3765,535)
NetR54_2: R54.2 U13.D2 | length 162.8
  Top Layer w5: U13.D2@3710.63,518.95 U13.D2@3710.63,520.63
  Top Layer w6: R54.2@3576.02,545 3592.73,545 3637.73,500 3691.68,500 U13.D2@3710.63,518.95
NetR55_2: R55.2 U13.C4 | length 245.4
  Top Layer w6: R55.2@3576.02,620 3709.64,620 3740,589.64 3740,577.4 3743.51,573.89 3755.75,573.89 3769.64,560 U13.C4@3789.37,560
NetR56_2: R56.2 U13.D4 | length 250.3
  Top Layer w5: 3744.45,494.65 3744.65,494.65
  Top Layer w6: R56.2@3576.02,495 3610,495 3645,460 3710,460 3736.11,486.11 3736.11,487.01 3743.75,494.65 3744.45,494.65 ; 3744.65,494.65 3751.73,501.73 3770.78,501.73 U13.D4@3787.19,518.13
NetR57_2: R57.2 U13.D5 | length 326.1
  Top Layer w6: R57.2@3576.02,670 3699.1,670 3775.48,593.62 3775.48,593.53 3814.85,554.16 3814.85,534.52 U13.D5@3828.74,520.63
NetR58_2: R58.2 U13.E3 | length 194.6
  Top Layer w6: R58.2@3582.88,445 3735,445 3750,460 U13.E3@3750,481.26
NetR59_2: R59.2 U13.E2 | length 287.3
  Top Layer w6: R59.2@3576.02,645 v1(3605,645) ; U13.E2@3710.63,481.26 3710.63,483.37 3717.7,490.44 3717.7,497.7 v1(3720,500)
  Bottom Layer w6: v1(3605,645) 3670,645 3726,589 3726,549.12 3720,543.12 v1(3720,500)
NetR60_2: R60.2 U13.E1 | length 108.7
  Top Layer w6: R60.2@3578.61,520 3600,520 3638.74,481.26 U13.E1@3671.26,481.26
NetR73_2: R73.2 U14.A5 | length 369.8
  Top Layer w4: v1(2425,850) 2425.84,849.16 2429.16,849.16 U14.A5@2438.74,858.74
  Top Layer w6: v1(2510,610) R73.2@2542.28,610
  Bottom Layer w6: v1(2425,850) 2485,850 2510,825 2510,697.19 2499,686.19 2499,621 v1(2510,610)
NetR74_2: R74.2 U14.C3 | length 392.5
  Top Layer w4: 2595.7,640.7 2599.68,640.7 R74.2@2603.98,645
  Top Layer w6: U14.C3@2360,780 2340,760 2340,676.31 2375.61,640.7 2595.7,640.7
NetR75_2: R75.2 U14.D3 | length 276.6
  Top Layer w6: U14.D3@2360,740.63 2385.63,715 2450,715 2460,705 2467.37,705 2473.37,699 2530.67,699 2546.67,715 2583.98,715 2599.89,699.09 2599.89,698.3 2603.19,695 R75.2@2603.98,695
NetR76_2: R76.2 U14.D2 | length 338.8
  Top Layer w4: v1(2320,760) v1@2320.32,759.68 ; U14.D2@2320.32,740.94 U14.D2@2320.63,740.63
  Top Layer w6: U14.D2@2320.32,740.94 v1@2320.32,759.68 ; v1(2470,820) 2495,820 2520,845 R76.2@2603.98,845
  Bottom Layer w6: v1(2320,760) 2410,760 v1(2470,820)
NetR77_2: R77.2 U14.C4 | length 221.2
  Top Layer w6: U14.C4@2399.37,780 2414.37,795 2497.5,795 2522.5,820 R77.2@2603.98,820
NetR78_2: R78.2 U14.D4 | length 227.1
  Top Layer w6: U14.D4@2399.37,740.63 2418.74,760 2450,760 2470,780 2537.63,780 2552.63,795 R78.2@2603.98,795
NetR79_2: R79.2 U14.D5 | length 258.4
  Top Layer w6: U14.D5@2438.74,740.63 2445,740.63 2480,740.63 ccw(c2480,748.63) 2488,748.63 2488,762 cw(c2496,762) 2504,762 2504,747.96 ccw(c2512,747.96) 2520,747.96 2520,762 cw(c2528,762) 2536,762 2536,748.63 ccw(c2544,748.63) 2544,740.63 2550.63,740.63 2555,745 2565,745 R79.2@2603.98,745
NetR80_2: R80.2 U14.E3 | length 279.4
  Top Layer w6: U14.E3@2360,701.26 2360,685 2381.93,663.07 2447.46,663.07 2462.5,678.11 2595.87,678.11 2599.89,674.09 2599.89,673.3 2603.19,670 R80.2@2603.98,670
NetR81_2: R81.2 U14.E2 | length 336.7
  Top Layer w4: U14.E2@2320,700.63 U14.E2@2320.63,701.26
  Top Layer w6: U14.E2@2320,700.63 2320,670 2359.3,630.7 2593.28,630.7 2599.89,624.09 2599.89,623.3 2603.19,620 R81.2@2603.98,620
NetR82_2: R82.2 U14.E1 | length 347.5
  Top Layer w4: U14.E1@2281.26,701.26 2281.73,701.26 2290.47,710 v1(2295,710)
  Top Layer w6: v1(2480,715) 2480.45,715.45 2504,715.45 2518.55,730 2593.98,730 2599.89,724.09 2599.89,723.3 2603.19,720 R82.2@2603.98,720
  Bottom Layer w6: v1(2295,710) 2310,725 2466.75,725 2476.75,715 v1(2480,715)
NetR85_2: R85.2 U12.N1 | length 302.3
  Top Layer w4: U12.N1@3293.11,563.98 3445,563.98 3475,563.98 ccw(c3475,570.98) 3482,570.98 3482,585.79 cw(c3489,585.79) 3496,585.79 3496,570.98 ccw(c3503,570.98) 3503,563.98 3508.98,563.98 3515,570 3520,570 R85.2@3547.28,570
NetR86_2: R86.2 U12.W20 | length 202.6
  Top Layer w4: R86.2@2626.02,770 2725,770 2777.48,717.52 U12.W20@2806.89,717.52
NetR87_2: R87.2 U14.C2 | length 267.2
  Top Layer w4: R87.2@2541.41,867.16 2547.28,873.03 R87.2@2547.28,875
  Top Layer w6: U14.C2@2320.63,780 2340,780 2390,830 2390.64,830 2394.64,834 2431.63,834 2433.63,836 2464.79,836 2483.79,855 2520,855 2532.16,867.16 R87.2@2541.41,867.16
NetR88_2: R88.2 U14.A3 | length 226
  Top Layer w4: U14.A3@2360,858.74 U14.A3@2360.61,859.35
  Top Layer w6: U14.A3@2360.61,859.35 2360.61,885.61 2370,895 2495,895 v1(2515,875)
  Bottom Layer w4: v1(2515,875) R88.2@2547.28,875
NetR89_1: R89.1 SW1.5 U15.12 | length 240.7
  Top Layer w6: v1(2300,75) SW1.5@2350,75
  Layer 2 w6: v1(2180,55) 2260,55 2280,75 v1(2300,75)
  Bottom Layer w6: v1(2180,55) 2180.16,55.16 2180.16,90.79 U15.12@2180.32,90.94 ; v1(2300,75) R89.1@2326.38,75
NetR90_1: R90.1 SW1.6 U15.9 | length 167.8
  Top Layer w6: v1(2300,125) SW1.6@2350,125
  Bottom Layer w6: U15.9@2239.37,90.94 2239.37,119.37 2245,125 v1(2300,125) R90.1@2326.38,125
NetR91_1: R91.1 SW1.7 U15.5 | length 205.9
  Top Layer w6: v1(2300,175) SW1.7@2350,175
  Bottom Layer w6: U15.5@2219.68,209.06 2220,208.74 2220,170 2230,160 2285,160 v1(2300,175) R91.1@2326.38,175
NetR92_1: R92.1 SW1.8 U15.2 | length 254.5
  Top Layer w6: v1(2300,225) SW1.8@2350,225
  Bottom Layer w6: U15.2@2160.63,209.06 2160.63,235.63 2170,245 2260,245 2280,225 v1(2300,225) R92.1@2326.38,225
NetR94_1: R94.1 U14.A4 U17.4 | length 121.1
  Top Layer w4: v1(2385,875) 2385,874.06 2399.37,859.68 U14.A4@2399.37,858.74
  Bottom Layer w4: U17.4@2314.13,897.4 2357.4,897.4 2360,900 R94.1@2386.38,900 2385,898.62 v1(2385,875)
NetR96_1: R96.1 U13.A4 U18.4 | length 146.5
  Top Layer w6: v1(3780,650) 3780,649.06 3788.59,640.46 U13.A4@3788.59,636.24
  Bottom Layer w6: R96.1@3765,660 3769.5,660 3779.5,650 v1(3780,650) ; R96.1@3765,665 3765,675 3770,680 3829.61,680 3847.6,662.01 U18.4@3847.6,654.13
NetR98_2: R98.2 U12.J1 | length 735.8
  Top Layer w4: U12.J1@3293.11,461.61 3357.53,461.61 3369.14,450 3448.58,450 3449.29,449.29
  Top Layer w5: 3449.29,449.29 3478.58,420 3538.58,360 3765,360 3850,445 3880,445 3920,485 R98.2@3920,500
NetR99_2: R99.2 U12.B11 | length 1252.9
  Top Layer w4: v1(2210,700) R99.2@2210,742.28 ; v1(3035,305) 3036.1,303.9 3036.1,283.58 U12.B11@3037.2,282.48
  Layer 2 w4: v1(2210,700) 2210,470 2260,420 2770,420 2802.5,387.5 2856.62,387.5 2863.62,394.5 3030.5,394.5 3045,380 3045,316.21 3035,306.21 v1(3035,305)
NetR101_1: R101.1 R105.2 U22.15 | length 63.1
  Top Layer w4: U22.15@1829.21,359.84 R101.1@1862.13,359.84
  Top Layer w6: R101.1@1862.13,359.84 R101.1@1862.28,360 R105.2@1862.28,390
NetR102_1: R102.1 R106.2 U22.2 | length 70.7
  Top Layer w8: U22.2@1789.84,399.21 1791.26,400.63 1791.26,405.28 1802.76,416.79 1802.76,432.28 R102.1@1805,432.28 R106.2@1835,432.28
NetR103_1: R103.1 R107.2 U22.4 | length 141
  Top Layer w8: R107.2@1685,432.28 1685,405 1690.79,399.21 U22.4@1750.47,399.21 1749.68,400 1735,400 ; R107.2@1690,432.28 R103.1@1715,432.28 R103.1@1720,432.28
NetR104_1: R104.1 R108.2 U22.3 | length 65.1
  Top Layer w8: R108.2@1745,432.28 R104.1@1775,432.28 1775,420 1770.16,415.16 U22.3@1770.16,399.21
NetR111_2: R111.2 U22.9 | length 39.5
  Top Layer w8: R111.2@1735,267.72 1735,284.82 1750.47,300.3 U22.9@1750.47,300.79
NetR112_2: R112.2 U22.6 | length 75.1
  Top Layer w8: R112.2@1657.72,355 1695,355 1699.84,359.84 U22.6@1730.79,359.84
NetR114_2: R114.2 U12.T18 | length 54.4
  Top Layer w4: U12.T18@2858.07,640.75 2858.44,640.37 2873.13,640.37 v1(2873.5,640)
  Bottom Layer w4: R114.2@2841.02,625 2841.81,625 2856.81,640 v1(2873.5,640)
NetR115_2: R115.2 U12.R17 | length 80.3
  Top Layer w5: v1(2875.79,581.7) 2875.79,585.22 2883.66,593.08 U12.R17@2883.66,615.16
  Bottom Layer w4: R115.2@2841.02,600 2841.81,600 2852.31,589.5 2856.2,589.5 2861.32,584.38 2874.38,584.38 v1@2875,585
  Bottom Layer w5: v1@2873.74,583.74 v1(2875.79,581.7)
NetR118_1: R118.1 U22.8 | length 82.1
  Top Layer w8: R118.1@1663.62,285 1695.32,285 1728.88,318.57 1728.88,319.06 1730.3,320.47 U22.8@1730.79,320.47
NetR119_1: R119.1 U22.7 | length 75.6
  Top Layer w8: R119.1@1663.62,320 1695,320 1715.16,340.16 U22.7@1730.79,340.16 U22.7@1730.71,340.08
NetR120_1: R120.1 U22.12 | length 60.1
  Top Layer w8: U22.12@1809.53,300.79 1809.53,262.91 1822.44,250 R120.1@1826.38,250
NetR120_2: R120.2 U12.Y3 | length 1893.1
  Top Layer w6.45: R120.2@1880,250 v1(1900,250) ; v1(3235,915) 3235,911.87 3241.93,904.95 U12.Y3@3241.93,743.11
  Bottom Layer w6.45: v1(1900,250) 1940.69,290.69 1990.69,290.69 2020,320 2345,320 2607.5,582.5 2677.5,582.5 2695,600 2695,750 2860,915 v1(3235,915)
NetR129_1: R129.1 R132.2 U25.7 | length 120.5
  Bottom Layer w8: R129.1@3610,1593.62 3610,1589.68 3641.56,1558.13 3642.19,1558.13 3650,1550.32 R132.2@3650,1546.38 3652.8,1543.58 U25.7@3652.8,1491.18
NetR130_1: R130.1 R133.2 U25.1 | length 105.9
  Bottom Layer w8: R133.2@3640,1323.62 R130.1@3680,1323.62 3679.19,1324.43 3679.19,1388.01 U25.1@3678.39,1388.82
NetR134_1: R134.1 R135.2 U23.9 | length 112.6
  Top Layer w8: R135.2@2110,1063.62 R134.1@2150,1063.62 2148.75,1064.87 2148.75,1086.68 2140.43,1095 2125.77,1095 2121.08,1099.69 2121.08,1114.35 U23.9@2120.16,1115.28
NetR144_2: R144.2 U12.E3 | length 167.3
  Top Layer w6: v1(3230,370) 3230.59,370 3241.34,359.25 U12.E3@3241.93,359.25
  Layer 2 w6: v1(3230,370) 3260,370 3295,335 v1(3340,335)
  Bottom Layer w6: v1(3340,335) R144.2@3366.38,335
NetR145_2: R145.2 U12.B15 U28.5 | length 383
  Top Layer w4: v1(2840,140) 2841.61,138.39 U28.5@2887.8,138.39 2962.07,138.39 2972,148.31 2972,202.21 2922.45,251.76 2922.45,270.09 U12.B15@2934.84,282.48
  Bottom Layer w4: v1(2840,140) R145.2@2926.38,140
NetR146_2: R146.2 U12.A15 U28.6 | length 377.4
  Top Layer w4: v1(2840,115) 2842.2,112.8 U28.6@2887.8,112.8 2947.8,112.8 2980,145 2980,211.73 U12.A15@2934.84,256.89
  Bottom Layer w4: v1(2840,115) 2865,115 2880,100 R146.2@2926.38,100
NetR151_2: R151.2 U12.D4 | length 169.5
  Top Layer w6: U12.D4@3216.34,333.66 3217.83,335.15 3226.9,335.15 3231.75,340 v1(3235,340)
  Layer 2 w6: v1(3235,340) 3235.3,340.3 3274.7,340.3 3315,300 v1(3340,300)
  Bottom Layer w6: v1(3340,300) R151.2@3366.38,300
NetR152_2: R152.2 U12.C5 | length 270.9
  Top Layer w6: v1(3173.25,300.1) 3175.54,302.4 3182.97,302.4 3188.64,308.07 U12.C5@3190.75,308.07 ; v1(3335,210) v1@3337.3,207.7
  Layer 2 w6: v1(3173.25,300.1) 3221.46,300.1 3278.28,243.29 3278.28,235.85 3304.13,210 v1(3335,210)
  Bottom Layer w6: v1(3335,210) 3335,200 3340,195 R152.2@3366.38,195
NetR153_2: R153.2 U12.E5 | length 223.4
  Top Layer w6: U12.E5@3190.75,359.25 3191.62,358.38 3191.62,343.53 v1(3192.5,342.65)
  Layer 2 w6: v1(3192.5,342.65) 3207.35,342.65 3285,265 v1(3340,265)
  Bottom Layer w6: v1(3340,265) R153.2@3366.38,265
NetR154_2: R154.2 U12.D6 | length 241.2
  Top Layer w6: U12.D6@3165.16,333.66 3167.26,333.66 v1@3173.63,327.3
  Layer 2 w5: 3287.78,240 3287.78,239.79 3297.56,230 v1(3345,230)
  Layer 2 w6: v1(3180,325) 3210,325 3287.78,247.22 3287.78,240
  Bottom Layer w5: v1(3345,230) R154.2@3366.38,230
NetR163.1_2: R163.1.2 U19.1.10 | length 72.2
  Top Layer w6: R163.1.2@1100,1863.62 v1(1100,1905)
  Bottom Layer w4: v1(1100,1905) 1100.39,1904.61 1100.39,1874.88 U19.1.10@1100.79,1874.49
NetR163.2_2: R163.2.2 U19.2.10 | length 64.4
  Top Layer w10: R163.2.2@1100,682.52 v1(1100,720)
  Bottom Layer w10: v1(1100,720) 1100.71,719.29 1100.71,693.46 U19.2.10@1100.79,693.39
NetR189.1_1: R189.1.1 U19.1.1 | length 51.2
  Bottom Layer w4: R189.1.1@1013.62,1690 1017.56,1690 1027.37,1699.81 1027.37,1700.77 1037.7,1711.1 U19.1.1@1055.51,1711.1
NetR189.2_1: R189.2.1 U19.2.1 | length 57.3
  Bottom Layer w8: R189.2.1@1013.62,508.9 1013.89,509.16 1044.61,509.16 1053.21,517.76 1053.21,529.08 1054.13,530 U19.2.1@1055.51,530
NetR190.1_1: R190.1.1 U19.1.21 | length 68
  Top Layer w4: R190.1.1@1233.62,1750 1255,1750 v1@1270,1765
  Bottom Layer w4: U19.1.21@1244.49,1770.16 1246.45,1768.19 1261.42,1768.19 1264.14,1765.47 v1(1267.93,1765.47)
NetR190.2_1: R190.2.1 U19.2.21 | length 142.5
  Top Layer w4: R190.2.1@1233.62,568.9 1268.9,568.9 1285,585 1305.71,585 v1(1306.02,584.68)
  Bottom Layer w4: U19.2.21@1244.49,589.06 1297.87,589.06 1302.24,584.68 v1(1306.02,584.68)
NetR203_2: R203.2 U30.35 | length 189.7
  Top Layer w6: R203.2@1650,1463.62 1650,1565 1660,1575 v1(1660,1600)
  Bottom Layer w6: U30.35@1611.85,1602.4 1612.21,1602.04 1657.96,1602.04 v1(1660,1600)
NetR204_2: R204.2 U30.36 | length 227.9
  Top Layer w6: v1(1685,1615) 1685,1585 1690,1580 R204.2@1690,1463.62
  Bottom Layer w6: U30.36@1611.85,1618.15 1678.6,1618.15 1681.75,1615 v1(1685,1615)
NetR205_2: R205.2 U30.37 | length 269.5
  Top Layer w6: v1(1660,1635) 1661,1634 1696,1634 1710,1620 1710,1515 1730,1495 R205.2@1730,1463.62
  Bottom Layer w6: U30.37@1611.85,1633.9 1612.21,1634.26 1659.26,1634.26 v1(1660,1635)
NetR208_2: R208.2 R209.1 U30.70 | length 121.7
  Bottom Layer w6: U30.70@1749.65,2118.15 1749.65,2182.09 1760,2192.44 R208.2@1760,2195 ; R208.2@1760,2196.38 1761.38,2195 R209.1@1800,2195
NetR210_2: R210.2 U30.59 | length 197.1
  Top Layer w6: v1(1690,1875) R210.2@1721.38,1875
  Bottom Layer w6: U30.59@1611.85,1980.35 1612.21,1980 1645,1980 1650,1975 1650,1900 1675,1875 v1(1690,1875)
NetR212_2: R212.2 U30.38 | length 307.4
  Top Layer w6: v1(1685,1650) 1705,1650 1720,1635 1720,1545 1770,1495 R212.2@1770,1463.62
  Bottom Layer w6: U30.38@1611.85,1649.65 1650.81,1649.65 1652.16,1651 1684,1651 v1(1685,1650)
NetS1_1: S1.1 S1.3 U12.U2 | length 749.1
  Top Layer w4: U12.U2@3267.52,666.34 3279.91,678.73 3279.91,696.25 3288.79,705.13 3331.16,705.13 3345.25,719.23 3364.23,719.23 3380,735 v1(3415,735)
  Top Layer w10: S1.1@3684.06,848.54 3741.38,848.54 3747.84,855 v1(3750,855) 3752.16,855 3758.62,848.54 S1.3@3815.94,848.54
  Bottom Layer w4: v1(3415,735) 3700,735 3750,785 v1(3750,855)
NetTP6_1: TP6.1 U12.V1 | length 104.4
  Top Layer w6.45: U12.V1@3293.11,691.93 3331,691.93 3349.07,710 TP6.1@3390,710
NetTP7_1: TP7.1 U12.W1 | length 118.6
  Top Layer w6.45: U12.W1@3293.11,717.52 3310,717.52 3327.52,717.52 3348.77,738.77 3358.77,738.77 TP7.1@3390,770
NetTP8_1: TP8.1 U12.E20 | length 130.1
  Top Layer w4: v1(2680,367) 2762.1,367 2769.84,359.25 U12.E20@2806.89,359.25
NetTP10_1: TP10.1 U12.C18 | length 149.4
  Top Layer w4: TP10.1@2730,270 2811.93,270 2819.64,277.71 2819.64,287.16 2827.35,294.87 2836.8,294.87 2848.13,306.2 2856.2,306.2 U12.C18@2858.07,308.07
NetTP11_1: TP11.1 U12.T1 | length 230.7
  Top Layer w4: U12.T1@3293.11,640.75 3331.91,640.75 3342.16,651 3367.84,651 3374.84,644 3389,644 3426.74,681.74 3426.74,697.02 TP11.1@3468.5,738.77
NetU3_9: U3.9 U6.14 | length 331.8
  Top Layer w4: U3.9@6059.06,1106.1 6098.9,1106.1 6110.8,1094.2 6202.98,1094.2 6212.18,1085 v1(6215,1085) ; v1(6220,1205) 6220.24,1204.76 6258.82,1204.76 U6.14@6259.06,1204.53
  Bottom Layer w4: v1(6215,1085) 6215,1087.34 6208,1094.34 6208,1193 v1(6220,1205)
NetU4_9: U4.9 U8.14 | length 2327.5
  Top Layer w4: U8.14@5659.06,1204.53 5659.29,1204.76 5684.76,1204.76 v1(5685,1205) ; v1(5660,1010) 5669,1019 5749.69,1019 5883.69,885 5931.31,885 6066.31,1020 6275.15,1020 6305.15,1050 6364.85,1050 6414.85,1000 6685,1000 6770,915 7143.79,915 7153.79,925 v1(7155,925) ; v1(7165,1230) 7167.5,1232.5 7212.5,1232.5 v1(7215,1235)
  Bottom Layer w4: v1(5660,1010) 5660,1180 v1(5685,1205) ; v1(7155,925) 7171.29,941.29 7171.29,1006.03 7192,1026.75 7192,1201.69 7165,1228.69 v1(7165,1230) ; v1(7215,1235) 7227.2,1235 7231.1,1231.09 U4.9@7231.1,1219.06
NetU4_14: U4.14 U6.9 | length 1542.8
  Top Layer w4: U6.9@6259.06,1106.1 6259.23,1106.28 6283.38,1106.28 6302.1,1125 6368.74,1125 v1(6430,1063.74) ; v1(6430,985) 6432.34,985 6439.34,992 6681.69,992 6766.69,907 7105.66,907 7112.66,900 v1(7115,900) ; v1(7145,1180) 7196.73,1180 7203.95,1187.21 7251.89,1187.21 7269.11,1170 7325,1170 v1(7330,1175)
  Bottom Layer w4: v1(6430,985) v1(6430,1063.74) ; v1(7115,900) 7130,915 7130,1078.84 7145,1093.84 v1(7145,1180) ; U4.14@7329.53,1219.06 7329.76,1218.82 7329.76,1175.24 v1(7330,1175)
NetU5_1: U5.1 U7.4 | length 182.3
  Top Layer w4: U5.1@5740.94,1243.9 5711.1,1243.9 5705,1250 5705,1320 5715.71,1330.71 U7.4@5774.41,1330.71
NetU8_9: U8.9 U9.14 | length 1772.3
  Top Layer w4: U9.14@4270.47,1249.06 4270.47,1263.82 4283.65,1277 4374.87,1277 4390,1261.87 4390,1187.53 4462.17,1115.35 4462.17,1084.39 4484.52,1062.05 4501.89,1062.05 4533.93,1030 4676.61,1030 4733.61,973 4789.63,973 4826.63,936 5129.24,936 5208.18,1014.94 5208.18,1080.7 5280.47,1153 5412.25,1153 5475.25,1090 5568.49,1090 5584.59,1106.1 5656.85,1106.1 U8.9@5657.95,1105
NetU15_1: U15.1 U15.4 U15.10 U15.13 U16.4 | length 540.8
  Top Layer w6: v1(2110,275) 2145,240 ; v1(2145,150) 2145,240 ; v1(2200,150) 2200,185 2145,240
  Bottom Layer w6: U16.4@2074.29,275.59 2074.59,275.3 2109.7,275.3 v1(2110,275) ; U15.1@2140.94,209.06 2140.94,157.3 2145,153.25 v1(2145,150) 2160.63,134.37 U15.13@2160.63,90.94 ; U15.4@2200,209.06 v1(2200,150) 2219.68,130.32 U15.10@2219.68,90.94
NetU20_2: U20.2 U21.4 | length 1965.7
  Top Layer w8: v1(3300,885) U20.2@3300,914.13
  Bottom Layer w8: U21.4@1774.41,174.29 1774.41,199.41 1780,205 2005,205 2045,245 2135,245 2178,288 2373,288 2643.99,558.99 2688.99,558.99 2720,590 2720,730 2877,887 3158,887 3182,863 3278,863 v1(3300,885)
NetU31.1_4: U31.1.4 U31.1.5 U31.1.6 U32.1.4 U32.1.5 U32.1.6 U33.1.3 U34.1.3
  other v1: 7045,685 7045,710 7045,735
NetU31.2_4: U31.2.4 U31.2.5 U31.2.6 U32.2.4 U32.2.5 U32.2.6 U33.2.3 U34.2.3
  other v1: 7521.93,1627.2 7521.93,1652.2 7521.93,1677.2
NetU31.3_4: U31.3.4 U31.3.5 U31.3.6 U32.3.4 U32.3.5 U32.3.6 U33.3.3 U34.3.3
  other v1: 6060.75,685 6060.75,710 6060.75,735
NetU31.4_4: U31.4.4 U31.4.5 U31.4.6 U32.4.4 U32.4.5 U32.4.6 U33.4.3 U34.4.3
  other v1: 6537.68,1627.2 6537.68,1652.2 6537.68,1677.2
NetU31.5_4: U31.5.4 U31.5.5 U31.5.6 U32.5.4 U32.5.5 U32.5.6 U33.5.3 U34.5.3
  other v1: 5076.5,685 5076.5,710 5076.5,735
NetU31.6_4: U31.6.4 U31.6.5 U31.6.6 U32.6.4 U32.6.5 U32.6.6 U33.6.3 U34.6.3
  other v1: 5553.43,1627.2 5553.43,1652.2 5553.43,1677.2
NetU31.7_4: U31.7.4 U31.7.5 U31.7.6 U32.7.4 U32.7.5 U32.7.6 U33.7.3 U34.7.3
  other v1: 4118.86,662.01 4118.86,752.01
NetU31.8_4: U31.8.4 U31.8.5 U31.8.6 U32.8.4 U32.8.5 U32.8.6 U33.8.3 U34.8.3
  other v1: 4569.17,1627.2 4569.17,1652.2 4569.17,1677.2
OSPI0_C\S\: R43.1 U12.L2 U13.C2 | length 498.8
  Top Layer w4: U12.L2@3267.52,512.8 3280.72,526 3315.51,526 3324.5,534.99 3324.5,540.5 3329,545 3475.61,545 3480.61,540 v1(3500,540) ; v1(3710,575) 3710.31,574.68 3710.31,560.31 U13.C2@3710.63,560
  Bottom Layer w4: v1(3500,540) 3515,555 3595,555 3600,550 R43.1@3625,550 ; R43.1@3630,549.5 3634.5,545 3688.3,545 3707.32,564.02 3707.32,572.32 v1(3710,575)
OSPI0_CLK: R62.2 R85.1 U13.B2 | length 269.6
  Top Layer w5: R85.1@3582.72,570 v1(3605,570) ; v1@3699.22,596.44 3700.69,597.9 3707.41,597.9 U13.B2@3708.44,596.87
  Bottom Layer w5: R62.2@3585,570 v1(3605,570) ; v1@3688.84,596.44 v1(3695,596.44)
  Bottom Layer w6: v1(3605,570) 3647,570 3649.12,572.12 ccw(c3643.46,577.78) 3649.12,583.44 3614.53,618.03 cw(c3620.18,623.69) 3614.53,629.34 cw(c3620.18,623.69) 3625.84,629.34 3660.43,594.75 ccw(c3666.09,600.41) 3671.75,594.75 3673.43,596.44 3688.56,596.44 v1@3688.84,596.44
OSPI0_D0: R44.1 R53.1 U12.M3 | length 411.3
  Top Layer w5: 3489.75,485.25 v1(3505,470) R53.1@3553.98,470
  Top Layer w6: v1(3236.13,524.71) 3238.43,527 3238.43,532.78 3241.93,536.28 U12.M3@3241.93,538.39 ; v1(3385,510) 3388.25,510 3394.25,516 3451.75,516 3482.75,485 3489.5,485
  Bottom Layer w5: v1(3236.13,524.71) 3250.84,510 v1(3385,510) ; v1(3505,470) 3507.18,467.82 R44.1@3553.98,467.82
OSPI0_D1: R45.1 R54.1 U12.M2 | length 328.2
  Top Layer w4: U12.M2@3267.52,538.39 3280.72,551.59 3298.24,551.59 3302.63,555.98 3517.13,555.98 3530,543.11 v1(3530,540) 3533.79,540 3538.79,545 R54.1@3553.98,545
  Bottom Layer w4: v1(3530,540) R45.1@3553.98,540
OSPI0_D2: R46.1 R55.1 U12.P1 | length 311.9
  Top Layer w5: v1@3530.93,635 3542.13,623.8 3550.18,623.8 R55.1@3553.98,620
  Top Layer w6: U12.P1@3293.11,589.57 3419.57,589.57 3465,635 v1(3530,635) v1@3530.93,635
  Bottom Layer w5: v1(3530,635) 3533.52,635 3538.52,640 R46.1@3553.98,640
OSPI0_D3: R47.1 R56.1 U12.L1 | length 305.2
  Top Layer w4: 3540.89,495 R56.1@3553.98,495
  Top Layer w6: U12.L1@3293.11,512.8 3357.8,512.8 3371,526 3460.56,526 3491.56,495 v1(3530,495) 3540.89,495
  Bottom Layer w6: v1(3530,495) 3533.25,495 3538.25,490 R47.1@3553.98,490
OSPI0_D4: R48.1 R57.1 U12.R4 | length 395.4
  Top Layer w5: v1(3530,685) 3532.49,682.51 3540.68,682.51 3553.19,670 R57.1@3553.98,670
  Top Layer w6: U12.R4@3216.34,615.16 3216.42,615.08 3239.92,615.08 v1(3240,615)
  Bottom Layer w5: v1@3533.52,685 3538.52,690 R48.1@3553.98,690
  Bottom Layer w6: v1(3240,615) 3254.3,615 3324.3,685 v1(3530,685)
OSPI0_D5: R49.1 R58.1 U12.K1 | length 299.4
  Top Layer w4: v1(3535,445) R58.1@3553.98,445
  Top Layer w6: U12.K1@3293.11,487.2 3322.8,487.2 3329,481 3386.63,481 3388.63,479 3455,479 3489,445 v1(3535,445)
  Bottom Layer w6: v1(3535,445) 3537.3,442.7 3549.89,442.7 3552.59,440 R49.1@3553.98,440
OSPI0_D6: R50.1 R59.1 U12.P2 | length 374.2
  Top Layer w4: U12.P2@3267.52,589.57 3282.28,604.33 3286.42,604.33 3287.98,602.77 3310,602.77
  Top Layer w5: R59.1@3553.19,645 R59.1@3553.98,645
  Top Layer w6: 3310,602.77 3402.77,602.77 3460,660 v1(3505,660) 3538.19,660 R59.1@3553.19,645
  Bottom Layer w5: v1(3505,660) 3508.52,660 3513.52,665
  Bottom Layer w6: 3513.52,665 R50.1@3553.98,665
OSPI0_D7: R51.1 R60.1 U12.L4 | length 454.5
  Top Layer w5: v1(3340,530) 3342.93,530 3349.43,536.5 3468.5,536.5 3488.33,516.67 3498.33,516.67 v1(3500,515) 3503.52,515 3508.52,520 R60.1@3553.98,520 R60.1@3558.34,520
  Top Layer w6: v1(3210.21,534.14) 3210.21,530.89 3214.85,526.26 3214.85,514.28 U12.L4@3216.34,512.8
  Bottom Layer w5: v1(3210.21,534.14) 3211.83,534.14 3222.69,545 3245,545 3265,525 3315.22,525 3320.22,530 v1(3340,530) ; v1(3500,515) R51.1@3553.98,515
OSPI0_DQS: R52.1 R61.2 U12.N2 | length 349.7
  Top Layer w4: U12.N2@3267.52,563.98 3279.91,576.37 3310,576.37 ; v1(3505,605) 3520,605 3530,595 R52.1@3553.98,595
  Top Layer w6: 3310,576.37 3446.37,576.37 3475,605 v1(3505,605)
  Bottom Layer w4: v1(3505,605) 3525,605 3530,610 R61.2@3545,610
OSPI0_ECC_FAIL: R42.1 U12.J3 U13.A5 | length 910.5
  Top Layer w5: v1(3380,465) 3446.31,465 3491.31,420 3730,420 3765,455 3765,475.83 3789.17,500 3840,500 3850,510 3850,605 v1(3835,620) 3830.42,624.58 3830.42,637.06 U13.A5@3828.74,638.74
  Top Layer w6: v1(3234,477.75) 3236.29,475.46 3236.29,469.36 3241.93,463.72 U12.J3@3241.93,461.61
  Bottom Layer w5: v1(3234,477.75) 3312.25,477.75 3322.51,467.49 3377.51,467.49 v1(3380,465) ; R42.1@3805,660 3805,630 3815,620 v1(3835,620)
OSPI0_RST: R97.1 R98.1 U18.1 | length 83.7
  Top Layer w10: v1(3920,523.16) R98.1@3920,537.72 R97.1@3920,585
  Bottom Layer w10: v1@3920,525 3921.2,526.2 3921.2,544.67 U18.1@3922.4,545.87
OSPI1_C\S\: R64.1 R87.1 R88.1 U12.V20 | length 439
  Top Layer w4: R87.1@2582.72,875 v1(2605,875) ; v1(2675,705) 2695,705 2708.07,691.93 2785,691.93 U12.V20@2806.89,691.93
  Bottom Layer w4: R88.1@2582.72,875 v1(2605,875) 2636.21,875 2651.21,860 2685,826.21 2685,825 2685.77,824.23 2685.77,720.22 2679.38,713.83 2679.38,713.17 2675,708.79 v1(2675,705)
  Bottom Layer w6: R88.1@2582.72,875 2583.86,873.86 2583.86,846.14 R64.1@2585,845
OSPI1_CLK: R84.2 R86.1 U14.B2 | length 431.1
  Top Layer w4: v1(2570,770) R86.1@2603.98,770
  Top Layer w6: U14.B2@2320.63,819.37 2320.63,829.89 v1(2338.26,847.52)
  Bottom Layer w4: v1(2570,770) R84.2@2585,770
  Bottom Layer w6: v1(2338.26,847.52) 2387.52,847.52 2410,870 2451.33,870 2454.33,870 ccw(c2454.33,878) 2462.33,878 2462.33,893.72 cw(c2470.33,893.72) 2478.33,893.72 2478.33,878 ccw(c2486.33,878) 2486.33,870 2492.66,870 2500.18,862.48 2530.5,832.16 2530.5,830.1 2534.6,826 2536.66,826 2570,792.66 v1(2570,770)
OSPI1_D0: R65.1 R75.1 U12.V19 | length 249
  Top Layer w4: R75.1@2626.02,695 2646.21,695 2651.21,690 2685,690 2695.46,679.54 2820.09,679.54 U12.V19@2832.48,691.93
  Bottom Layer w4: R65.1@2626.02,695 2646.21,695 2651.21,690 v1(2655,690)
OSPI1_D1: R66.1 R76.1 U12.Y18 | length 296.2
  Top Layer w4: R76.1@2626.02,845 v1(2645,845) 2745,845 2822,768 2838.31,768 2853.1,753.21 2855.4,750.91 2855.4,750.34 2856.2,749.54 2856.2,744.98 U12.Y18@2858.07,743.11
  Bottom Layer w4: R66.1@2626.02,845 v1(2645,845)
OSPI1_D2: R67.1 R77.1 U12.W18 | length 329.8
  Top Layer w4: R77.1@2626.02,820 v1(2670,820) 2726.31,820 2786.31,760 2835,760 2845.6,749.4 2845.6,729.99 U12.W18@2858.07,717.52
  Bottom Layer w4: R67.1@2626.02,820 v1(2670,820)
OSPI1_D3: R68.1 R78.1 U12.Y19 | length 257.8
  Top Layer w4: R78.1@2626.02,795 v1(2645,795) 2715,795 2780,730 2819.37,730 U12.Y19@2832.48,743.11
  Bottom Layer w4: R68.1@2626.02,795 v1(2645,795)
OSPI1_D4: R69.1 R79.1 U12.W19 | length 322.2
  Top Layer w4: R79.1@2626.02,745 v1(2670,745) 2681,745 2683,745 ccw(c2683,752) 2690,752 2690,755 cw(c2697,755) 2704,755 2704,735 ccw(c2711,735) 2718,735 2718,738 cw(c2725,738) 2725,745 2738.69,745 2778.69,705 2819.96,705 U12.W19@2832.48,717.52
  Bottom Layer w4: R69.1@2626.02,745 v1(2670,745)
OSPI1_D5: R70.1 R80.1 U12.U20 | length 218.8
  Top Layer w4: R80.1@2626.02,670 2639.11,670 2649.11,660 v1(2650,660) 2651.21,660 2661.21,670 2695,670 2698.66,666.34 U12.U20@2806.89,666.34
  Bottom Layer w4: R70.1@2626.02,670 2630.32,665.7 2640.51,665.7 2646.21,660 v1(2650,660)
OSPI1_D6: R71.1 R81.1 U12.T20 | length 224.8
  Top Layer w4: R81.1@2626.02,620 2637.98,620 2642.38,624.41 2650.62,624.41 2651.21,625 2675,625 2695.95,645.95 2789.8,645.95 2795,640.75 U12.T20@2806.89,640.75
  Bottom Layer w4: R71.1@2626.02,620 2646.21,620 2651.21,625 v1(2655,625)
OSPI1_D7: R72.1 R82.1 U12.V18 | length 296.5
  Top Layer w4: R82.1@2626.02,720 v1(2645,720) 2728.79,720 2738.79,710 v1(2740,710)
  Top Layer w5: U12.V18@2858.07,691.93 2860.45,691.93 2866.03,697.51 2872.51,697.51 v1(2875,700)
  Bottom Layer w4: R72.1@2626.02,720 v1(2645,720) ; v1(2740,710) 2741.21,710 2751.21,700 v1(2875,700)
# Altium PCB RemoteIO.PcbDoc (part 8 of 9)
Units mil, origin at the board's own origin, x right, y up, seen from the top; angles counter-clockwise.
Board outline 7874.02 x 2362.2 mil, 6 copper layers (Top Layer, GND1, Layer 2, PWR, GND2, Bottom Layer), stack 60.956 mil thick; 686 components, 447 nets, 2681 pads, 1481 vias.

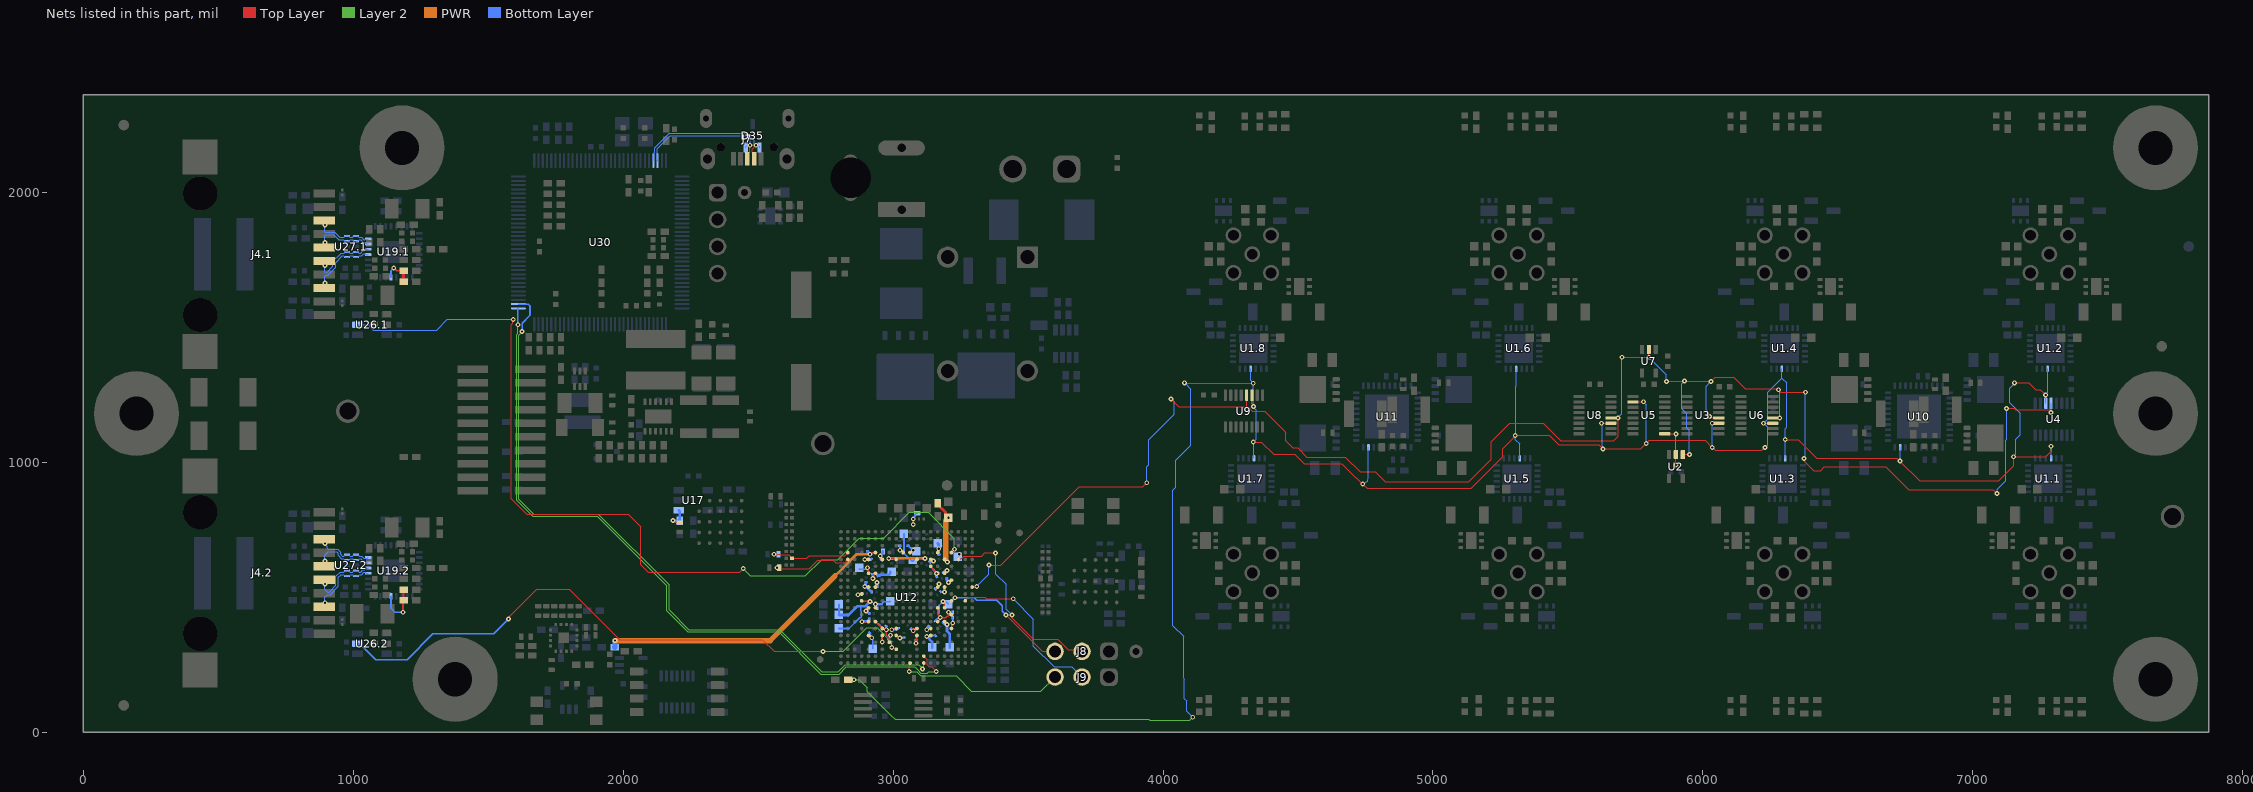
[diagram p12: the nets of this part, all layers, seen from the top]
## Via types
v1: diameter 18, hole 8, Top Layer to Bottom Layer, tented both sides, 1314 vias
v2: diameter 19.68, hole 7.87, Top Layer to Bottom Layer, tented both sides, 133 vias
v3: diameter 19.68, hole 7.87, Top Layer to Bottom Layer, 34 vias

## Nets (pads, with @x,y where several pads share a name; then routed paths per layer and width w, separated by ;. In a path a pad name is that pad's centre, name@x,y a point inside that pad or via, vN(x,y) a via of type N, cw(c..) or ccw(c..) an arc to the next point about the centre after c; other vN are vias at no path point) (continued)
OSPI1_DQS: R74.1 R83.2 U12.U19 | length 304.1
  Top Layer w4: v1(2558.8,660) 2579.6,660 2582.3,657.3 2613.55,657.3 2620.94,649.91 2620.94,649.3 R74.1@2625.24,645 ; R74.1@2626.02,645 2680,645 2688.95,653.95 2820.09,653.95 U12.U19@2832.48,666.34
  Bottom Layer w4: v1(2558.8,660) 2572.62,660 R83.2@2574,661.38
OSPI1_ECC_FAIL: R63.1 R73.1 U12.T19 | length 296.4
  Top Layer w4: v1(2570,610) R73.1@2577.72,610 2581.65,606.06 2689.75,606.06 2721.64,637.95 2778.26,637.95 2787.86,628.36 2820.09,628.36 U12.T19@2832.48,640.75
  Bottom Layer w4: v1(2570,610) R63.1@2580,610
OSPI1_RST: R95.1 R99.1 U17.1 | length 94.3
  Top Layer w4: v1(2185,785) 2192.28,777.72 R99.1@2210,777.72
  Bottom Layer w5: v1(2185,785) 2208.62,785 R95.1@2210,783.62
  Bottom Layer w10: U17.1@2205.87,822.6 2210,818.46 R95.1@2210,783.62
RD.1_N: J4.1.8 U19.1.4 U27.1.1 U27.1.10 | length 262.8
  Top Layer w4.32: J4.1.8@892.91,1646.65 892.91,1662.91 v1(895,1665)
  Bottom Layer w4.32: v1(895,1665) 895,1690.31 897.53,1692.84 904.97,1692.84 934.41,1722.28 934.41,1740.7 959.52,1765.81 965.63,1765.81 968.16,1763.28 968.16,1762.41 969.94,1760.63 U27.1.1@977.13,1760.63 984.31,1760.63 986.09,1762.41 986.09,1763.28 988.62,1765.81 998.51,1765.81 1001.04,1763.28 1001.04,1762.41 1002.81,1760.63 U27.1.10@1010,1760.63 1017.19,1760.63 1018.96,1762.41 1018.96,1763.28 1021.49,1765.81 1031.46,1765.81 1039.75,1774.1 1044.68,1774.1 1048.62,1770.16 U19.1.4@1055.51,1770.16
RD.1_P: J4.1.6 U19.1.5 U27.1.2 U27.1.9 | length 262.1
  Top Layer w4.32: J4.1.6@892.91,1746.65 895,1744.57 v1(895,1730)
  Bottom Layer w4.32: v1(895,1730) 895,1704.69 897.53,1702.16 901.11,1702.16 925.09,1726.14 925.09,1744.56 955.66,1775.13 965.63,1775.13 968.16,1777.66 968.16,1778.54 969.94,1780.32 U27.1.2@977.13,1780.32 984.31,1780.32 986.09,1778.54 986.09,1777.66 988.62,1775.13 998.51,1775.13 1001.04,1777.66 1001.04,1778.54 1002.81,1780.32 U27.1.9@1010,1780.32 1017.19,1780.32 1018.96,1778.54 1018.96,1777.66 1021.49,1775.13 1027.6,1775.13 1035.89,1783.42 1042.2,1783.42 1048.62,1789.84 U19.1.5@1055.51,1789.84
RD.2_N: J4.2.8 U19.2.4 U27.2.1 U27.2.10 | length 280.3
  Top Layer w4.32: J4.2.8@892.91,465.55 897.36,470 J4.2.8@920,470
  Bottom Layer w4.32: v1(895,480) 895,500.68 905,510.68 914.54,510.68 945,541.14 945,574.71 955,584.71 959.52,584.71 965.63,584.71 968.16,582.18 968.16,581.3 969.94,579.53 U27.2.1@977.13,579.53 984.31,579.53 986.09,581.3 986.09,582.18 988.62,584.71 998.51,584.71 1001.04,582.18 1001.04,581.3 1002.81,579.53 U27.2.10@1010,579.53 1017.19,579.53 1018.96,581.3 1018.96,582.18 1021.49,584.71 1031.46,584.71 1039.75,593 1044.68,593 1048.62,589.06 U19.2.4@1055.51,589.06
RD.2_P: J4.2.6 U19.2.5 U27.2.2 U27.2.9 | length 268.1
  Top Layer w4.32: J4.2.6@892.91,565.55 895,563.46 v1(895,550)
  Bottom Layer w4.32: v1(895,550) 895,530 905,520 910.68,520 935.68,545 935.68,578.57 951.14,594.03 955.66,594.03 965.63,594.03 968.16,596.56 968.16,597.44 969.94,599.21 U27.2.2@977.13,599.21 984.31,599.21 986.09,597.44 986.09,596.56 988.62,594.03 998.51,594.03 1001.04,596.56 1001.04,597.44 1002.81,599.21 U27.2.9@1010,599.21 1017.19,599.21 1018.96,597.44 1018.96,596.56 1021.49,594.03 1027.6,594.03 1035.89,602.32 1042.2,602.32 1048.62,608.74 U19.2.5@1055.51,608.74
RESET_PHY0: U12.U4 U26.1.2 | length 3316.1
  Top Layer w4: v1(1593,1530) 1591,1528 1591,1515 1586,1510 1586,865.31 1643.31,808 2018.12,808 2065,761.12 2065,620.51 2092.51,593 2431.37,593 v1(2445,606.63)
  Top Layer w6: U12.U4@3216.34,666.34 3216.34,666.95 3227.5,678.11 v1(3227.5,678.72)
  Layer 2 w4: v1(2445,606.63) 2471.63,580 2675,580 2735,640 2785,640 2794.49,640 2874.49,720 2965,720 3060,815 3130,815 3227.5,717.5 v1(3227.5,678.72)
  Bottom Layer w4: U26.1.2@1015.87,1510 1055,1510 1074.59,1490.41 1308.67,1490.41 1348.27,1530 v1(1593,1530)
RESET_PHY1: U12.C12 U26.2.2 | length 2308.5
  Top Layer w4: v1(1575,420) 1574.16,420.84 1574.16,424.16 1680,530 1801.06,530 1826.06,505 1826.21,505 1987.21,344 2515.49,344 2559.49,300 v1(2740,300) ; v1(2995.01,314.28) 2998.8,314.28 3003.13,309.94 3009.74,309.94 U12.C12@3011.61,308.07
  Layer 2 w4: v1(2740,300) 2785,300 2815.34,300 2902.34,387 2942.49,387 2944.99,384.5 2946.01,384.5 2975.5,355.01 2975.5,353.99 2983.99,345.5 2985.01,345.5 2995.01,335.5 v1(2995.01,314.28)
  Bottom Layer w5: U26.2.2@1015.87,328.9 1023.74,328.9 1082.64,270 1200,270 1295,365 1520,365 v1(1575,420)
SCLK: R40.2 U1.1.22 U1.2.22 U1.3.22 U1.4.22 U1.5.22 U1.6.22 U1.7.22 U1.8.22 U3.11 U4.11 U5.2 U6.11 U8.11 U9.11 U10.9 U11.9 | length 8827.1
  Top Layer w4: R40.2@2833.62,195 v1(2855,195) ; v1(4080,1295) 4080.73,1294.27 4329.54,1294.27 4331.49,1296.22 v1(4334.17,1293.54) ; U9.11@4329.53,1249.06 4329.53,1216.79 4335.53,1210.79 v1(4335.53,1207) ; v1(4334.17,1075.16) 4364.46,1075.16 4409.57,1030.05 4488.63,1030.05 4522.68,996 4661.53,996 4713.67,943.85 4716.12,943.85 v1(4739.98,920) 4755.98,904 5142.5,904 5259,1020.5 5259,1051.21 5298,1090.22 5298,1090.66 5305,1097.66 v1(5305,1100) 5431.31,1100 5466,1065.31 5614.69,1065.31 v1(5630,1050) ; v1(5625,1145) 5625.47,1145.47 U8.11@5659.06,1145.47 ; v1@5628.79,1050 5770,1050 5802,1082 6008,1082 v1(6035,1055) ; U5.2@5740.94,1224.21 5741.34,1224.61 5779.61,1224.61 v1(5780,1225) ; v1(6035,1145) 6058.58,1145 U3.11@6059.06,1145.47 ; v1@6036.21,1055 6046.21,1045 6218.79,1045 6228.79,1055 v1(6230,1055) ; v1(6225,1145) 6225.24,1145.24 6258.82,1145.24 U6.11@6259.06,1145.47 ; v1(6305,1085) 6352.47,1085 6421.47,1016 6719,1016 v1(6730,1005) 6803,932 7095.79,932 7151.21,987.43 7151.21,1018.79 v1(7151.21,1021.21) 7270.44,1021.21 7290,1040.77 v1(7290,1060) ; v1@7160,1295 7207.37,1295 7232.37,1270 7250,1270 v1(7270,1250)
  Layer 2 w4: v1(2855,195) 2875,195 2905,165 2905,151.31 2992.31,64 3008.31,48 3947.63,48 3950.63,45 4099,45 v1(4110,56)
  Bottom Layer w4: v1(4080,1295) 4103.17,1271.83 4103.17,1064.43 4047,1008.25 4047,907.9 4036,896.9 4036,395.66 4076.24,355.41 4076.24,200.46 4079.17,197.53 4079.17,124.51 4087.17,116.51 4087.17,78.83 v1(4110,56) ; U1.8.22@4324.33,1346.91 4324.33,1304.91 4334.17,1295.07 v1(4334.17,1293.54) 4333.77,1293.14 4333.77,1205 4345,1193.77 4345,1085.98 v1(4334.17,1075.16) 4335.63,1073.7 4335.63,1016.75 U1.7.22@4337.09,1015.3 ; v1(4739.98,920) 4743.76,920 4752.1,928.34 4755.64,928.34 4758.52,931.21 4758.52,936.62 4761.1,939.2 U11.9@4761.1,1055.83 ; U1.6.22@5308.58,1346.91 5308.58,1283.58 5307.5,1282.5 5307.5,1102.5 v1(5305,1100) 5305,1085 5321.34,1068.66 U1.5.22@5321.34,1015.3 U1.5.22@5320.63,1016 ; v1(5625,1145) 5627.5,1142.5 5627.5,1052.5 v1(5630,1050) ; v1(5780,1225) 5780,1223.79 5790,1213.79 v1(5790,1070) ; v1(6035,1055) v1(6035,1145) ; v1(6230,1055) 6230,1056.21 6240,1066.21 6240,1130 v1(6225,1145) 6240,1160 6240,1260 6292.83,1312.83 ; U1.4.22@6292.83,1346.91 6292.83,1312.83 ; U1.3.22@6305.59,1015.3 6305.3,1015.59 6305.3,1084.7 v1(6305,1085) 6305,1125 6310,1130 6310,1295.67 6292.83,1312.83 ; v1(6730,1005) 6730.55,1005.55 6730.55,1055.28 U10.9@6731.1,1055.83 ; v1@7151.21,1021.54 7160,1030.33 7160,1086.21 7176,1102.21 7176,1182.69 7137,1221.69 7137,1275.79 7155,1293.79 v1(7155,1295) ; U4.11@7270.47,1219.06 7270.24,1219.29 7270.24,1249.76 v1(7270,1250) 7270,1253.79 7277.09,1260.87 U1.2.22@7277.09,1346.91 ; U1.1.22@7289.84,1015.3 7289.92,1015.37 7289.92,1059.92 v1(7290,1060)
SR_C\S\: U2.1 U3.12 U4.12 U6.12 U7.2 U8.12 U9.12 U12.M1 | length 6498.5
  Top Layer w4: U12.M1@3293.11,538.39 3294.42,539.69 3308.69,539.69 v1(3310,541) ; v1(3355,620) 3398.94,620 3688.94,910 3925,910 v1(3940,925) ; v1(4030,1235) 4059,1206 4309.84,1206 ; U9.12@4309.84,1249.06 4309.84,1206 ; U8.12@5659.06,1165.16 5659.13,1165.08 5684.92,1165.08 v1(5685,1165) 5685.72,1164.28 5685.72,1097.04 5670,1081.31 5472.63,1081.31 5408.94,1145 5283.79,1145 5216.18,1077.39 5216.18,1011.62 5132.55,928 4823.31,928 4786.31,965 4730.3,965 4675.3,1020 4532.62,1020 4498.57,1054.05 4481.2,1054.05 4454.17,1081.08 4454.17,1112.04 4376.21,1190 4331.31,1190 4315.31,1206 4309.84,1206 ; v1(5700,1390) v1(5800,1390) U7.2@5800,1419.29 ; v1(5865,1300) 5865.99,1300.99 5931.01,1300.99 v1(5932,1301.98) 5932.99,1300.99 6029.01,1300.99 v1(6030,1300) 6045,1315 6115,1315 6156.21,1273.79 6271.59,1273.79 6276.21,1269.16 v1(6280,1269.16) 6289.16,1260 v1(6380,1260) ; U2.1@5925.59,1029.29 5926.3,1030 v1(5950,1030) ; v1(6025,1170) 6028.79,1170 6033.63,1165.16 U3.12@6059.06,1165.16 ; U6.12@6259.06,1165.16 6259.13,1165.08 6285,1165.08 v1(6285.08,1165) ; v1(6375,1015) 6376.61,1013.39 6376.61,1003.39 6410,970 6436.21,970 6450.21,984 6678.37,984 6763.37,899 7076,899 v1(7090,885) ; v1(7125,1200) 7153,1200 7157.79,1195.21 7282.31,1195.21 7290,1187.53 v1(7290,1185)
  Bottom Layer w4: v1(3310,541) 3355,586 v1(3355,620) ; v1(3940,925) 3940,983.69 3948,991.69 3948,1084.88 4040.86,1177.74 4040.86,1224.14 v1(4030,1235) ; v1(5685,1165) 5700,1180 v1(5700,1390) ; v1(5800,1390) 5865,1325 v1(5865,1300) ; v1(5932,1301.98) 5922,1291.98 5922,1199.21 5940,1181.21 5940,1129.01 5950,1119.01 v1(5950,1030) ; v1(6025,1170) 6025,1172.34 6018.67,1178.67 6018.67,1189.27 6013,1194.95 6013,1283 v1(6030,1300) ; v1(6280,1269.16) 6280,1265.37 6285.08,1260.3 v1(6285.08,1165) ; v1(6375,1015) 6380,1020 v1(6380,1260) ; v1(7090,885) 7090,900 7122,932 7122,1082.15 7125,1085.15 v1(7125,1200) ; v1(7290,1185) 7290.16,1185.16 U4.12@7290.16,1219.06
SR_OUT: U2.2 U5.9 | length 195.7
  Top Layer w4: U5.9@5859.06,1106.1 5859.61,1105.55 5899.45,1105.55 v1(5900,1105) ; v1(5900,990) U2.2@5900,1029.29
  Bottom Layer w4: v1(5900,990) v1(5900,1105)
Strap3.1: R168.1.1 R178.1.2 U19.1.29 | length 119.1
  Top Layer w6: v1(1150,1720) 1151.63,1720 1161.63,1710 R168.1.1@1186.38,1710
  Top Layer w10: R178.1.2@1186.38,1670 R168.1.1@1186.38,1710
  Bottom Layer w6: U19.1.29@1140.16,1685.51 1140.16,1710.16 v1(1150,1720)
Strap3.2: R168.2.1 R178.2.2 U19.2.29 | length 180
  Top Layer w8: v1(1185,445) 1185,487.52 R178.2.2@1186.38,488.9 R168.2.1@1186.38,528.9
  Bottom Layer w6: U19.2.29@1140.16,504.41 1140.16,459.84 1155,445 v1(1185,445)
TD.1_N: J4.1.5 U19.1.6 U27.1.4 U27.1.7 | length 255.5
  Top Layer w4.32: v1(895,1815) 892.91,1812.91 J4.1.5@892.91,1796.65 J4.1.5@917.91,1796.65
  Bottom Layer w4.32: v1(895,1815) 895,1840.31 897.53,1842.84 927.88,1842.84 945.85,1824.87 965.63,1824.87 968.16,1822.34 968.16,1821.46 969.94,1819.69 U27.1.4@977.13,1819.69 984.31,1819.69 986.09,1821.46 986.09,1822.34 988.62,1824.87 998.51,1824.87 1001.04,1822.34 1001.04,1821.46 1002.81,1819.69 U27.1.7@1010,1819.69 1017.19,1819.69 1018.96,1821.46 1018.96,1822.34 1021.49,1824.87 1027.6,1824.87 1035.89,1816.58 1041.57,1816.58 1048.62,1809.53 U19.1.6@1055.51,1809.53
TD.1_P: J4.1.3 U19.1.7 U27.1.5 U27.1.6 | length 252.3
  Top Layer w4.32: v1(895,1880) 895,1894.57 J4.1.3@892.91,1896.65 J4.1.3@917.91,1896.65
  Bottom Layer w4.32: v1(895,1880) 895,1854.69 897.53,1852.16 931.74,1852.16 949.71,1834.19 965.63,1834.19 968.16,1836.72 968.16,1837.59 969.94,1839.37 U27.1.5@977.13,1839.37 984.31,1839.37 986.09,1837.59 986.09,1836.72 988.62,1834.19 998.51,1834.19 1001.04,1836.72 1001.04,1837.59 1002.81,1839.37 U27.1.6@1010,1839.37 1017.19,1839.37 1018.96,1837.59 1018.96,1836.72 1021.49,1834.19 1031.46,1834.19 1039.75,1825.9 1043.33,1825.9 1043.88,1826.45 1052.75,1826.45 U19.1.7@1055.51,1829.21
TD.2_N: J4.2.5 U19.2.6 U27.2.4 U27.2.7 | length 238.3
  Top Layer w4.32: J4.2.5@892.91,615.55 895,617.64 v1(895,635)
  Bottom Layer w4.32: v1(895,635) 895,655.68 907.73,668.41 938.41,668.41 943.98,662.84 943.98,655.45 955.66,643.76 965.63,643.76 968.16,641.23 968.16,640.36 969.94,638.58 U27.2.4@977.13,638.58 984.31,638.58 986.09,640.36 986.09,641.23 988.62,643.76 998.51,643.76 1001.04,641.23 1001.04,640.36 1002.81,638.58 U27.2.7@1010,638.58 1017.19,638.58 1018.96,640.36 1018.96,641.23 1021.49,643.76 1027.6,643.76 1035.89,635.48 1041.57,635.48 1048.62,628.43 U19.2.6@1055.51,628.43
TD.2_P: J4.2.3 U19.2.7 U27.2.5 U27.2.6 | length 221.7
  Top Layer w4.32: J4.2.3@892.91,715.55 895,713.46 v1(895,700)
  Bottom Layer w4.32: v1(895,700) 895,696.3 903.73,687.57 903.73,681.73 907.73,677.73 942.27,677.73 953.3,666.7 953.3,659.31 959.52,653.09 965.63,653.09 968.16,655.62 968.16,656.49 969.94,658.27 U27.2.5@977.13,658.27 984.31,658.27 986.09,656.49 986.09,655.62 988.62,653.09 998.51,653.09 1001.04,655.62 1001.04,656.49 1002.81,658.27 U27.2.6@1010,658.27 1017.19,658.27 1018.96,656.49 1018.96,655.62 1021.49,653.09 1031.46,653.09 1039.75,644.8 1043.33,644.8 1043.88,645.35 1052.75,645.35 U19.2.7@1055.51,648.11
UART0_RX: U12.A8 U30.34 | length 2634
  Top Layer w4: v1(3109.42,235) 3109.42,238.79 3113.98,243.34 U12.A8@3113.98,256.89
  Layer 2 w4: v1@1625,1482.66 1613,1470.66 1613,863.31 1668.31,808 1908.31,808 2170,546.31 2170,453.43 2243.43,380 2579.75,380 2735.75,224 2797.13,224 2823.13,250 3094.42,250 v1(3109.42,235)
  Bottom Layer w6: U30.34@1611.85,1586.65 1612.21,1586.3 1648.7,1586.3 1655,1580 1655,1545 1626,1516 1626,1486 v1(1625,1485)
UART0_TX: U12.B8 U30.33 | length 2693.8
  Top Layer w4: U12.B8@3113.98,282.48 3127.18,269.28 3127.18,250.23 3135,242.41 3142.59,242.41 v1(3160,225)
  Layer 2 w4: v1(1610,1510) 1610,1478.97 1605,1473.97 1605,860 1665,800 1905,800 2162,543 2162,450.12 2240.12,372 2576.43,372 2732.43,216 2800.45,216 2826.95,242.5 3080.71,242.5 3091.31,231.89 3103.21,220 3127.21,220 3132.21,225 v1(3160,225)
  Bottom Layer w6: v1(1610,1510) 1610,1570.04 1610.87,1570.91 U30.33@1611.85,1570.91
UART1_RX: J8.2 U12.T3 | length 725.1
  Top Layer w4: U12.T3@3241.93,640.75 3243.8,642.62 3251.87,642.62 3262.39,653.14 3328.14,653.14 3340,665 v1(3380,665) ; v1(3440,435) 3441.26,433.74 3441.26,423.05 3519.31,345 3610,345 3648.86,306.14 3693.86,306.14 J8.2@3700,300
  Bottom Layer w4: v1(3380,665) 3380,586.62 3418.66,547.96 3418.66,456.34 v1(3440,435)
UART1_TX: J8.3 U12.K4 | length 485
  Top Layer w4: v1(3418,435) 3553,300 J8.3@3600,300
  Top Layer w6: U12.K4@3216.34,487.2 3217.25,487.2 3228.89,498.84 v1(3229.8,498.84) 3229.8,499.8 v1@3230,500
  Bottom Layer w5: v1(3229.8,498.84) 3301.16,498.84 3310,490 3385,490 3405.01,469.99 3405.01,447.99 v1(3418,435)
UART2.RX: J9.2 U12.K2 | length 618.6
  Top Layer w4: U12.K2@3267.52,487.2 3280.31,500 3340,500 3345,495 v1(3445,495)
  Bottom Layer w4: v1(3445,495) 3520,420 3520,320 3596.52,243.48 3661.52,243.48 J9.2@3700,205
UART2.TX: J9.3 U12.A10 | length 624.4
  Top Layer w4: v1(3060,225) 3060,241.46 3062.54,244 3062.54,256.64 U12.A10@3062.8,256.89
  Layer 2 w4: v1(3060,225) 3086.89,225 3101.89,210 3233.43,210 3290.43,153 3548,153 J9.3@3600,205
USB_N: D35.1 J7.2 U30.93 | length 551
  Top Layer w4.32: J7.2@2485.59,2125 2485.59,2141.73 2477.46,2149.87 2477.46,2160.03 2492,2174.57 v1(2492,2175)
  Bottom Layer w4.32: U30.93@2111.85,2118.15 2111.85,2142.73 2117.63,2148.51 2117.63,2165.81 2171.14,2219.32 2458.86,2219.32 2486.24,2191.94 2486.24,2178.17 2489.41,2175 v1(2492,2175) 2499.88,2175 2505.59,2169.29 D35.1@2505.59,2166.69
USB_P: D35.2 J7.3 U30.94 | length 507.9
  Top Layer w4.32: J7.3@2460,2125 2460,2141.73 2468.14,2149.87 2468.14,2173.14 v1(2470,2175)
  Bottom Layer w4.32: U30.94@2127.6,2118.15 2126.95,2118.8 2126.95,2161.95 2175,2210 2455,2210 2470,2195 v1(2470,2175) 2460.12,2175 2454.41,2169.29 D35.2@2454.41,2166.69
Vcore: C44.2 C45.2 C46.2 C47.2 C48.2 C49.2 C50.2 C51.2 C52.2 C53.2 C54.2 C55.2 C56.2 C57.2 C58.2 C59.2 C60.2 C61.2 C62.2 C63.2 C64.2 R109.1 U12.D13 U12.F7 U12.F9 U12.F12 U12.F14 U12.G6 U12.G15 U12.H4 U12.J6 U12.J15 U12.K17 U12.M6 U12.M15 U12.P6 U12.P15 U12.R7 | length 1155.1
  Top Layer w6: U12.K17@2883.66,487.2 2884.76,486.1 2913.9,486.1 v1(2915,485) ; v1(2925,570) 2927.3,572.3 2927.3,579.92 2934.84,587.46 U12.P15@2934.84,589.57 U12.P15@2934.49,589.57 ; U12.G15@2934.84,410.43 U12.F14@2960.43,384.84 2961.92,383.35 v1@2968.4,383.35 ; U12.M15@2934.84,538.39 2936.33,539.87 2936.33,548.08 2940,551.75 v1(2940,555) ; v1(2975,380) 2975,360.51 2985.51,350 U12.D13@2985.51,334.17 ; U12.D13@2986.02,333.66 2986.02,352.78 2990,356.75 v1(2990,360) ; v1(2995,380) 2998.25,380 3001.6,383.35 3010.13,383.35 U12.F12@3011.61,384.84 ; v1@3070,380 3073.35,383.35 3086.9,383.35 U12.F9@3088.39,384.84 ; U12.R7@3139.57,615.16 3139.57,613.05 3161.45,591.17 v1(3161.45,588.99) ; U12.G6@3165.16,410.43 3165.16,412.54 3175,422.38 v1(3175,425) ; U12.J6@3165.16,461.61 3165.16,438.09 3175,428.25 v1(3175,425) ; U12.M6@3165.16,538.39 3165.16,540.49 3167.7,543.04 3167.7,547.7 v1(3170,550) ; v1(3205,445) 3208.33,441.67 3209.51,441.67 3215.16,436.02 U12.H4@3216.34,436.02 3214.85,434.54 3207.78,434.54 3203.25,430 3200,430 3195,425 v1(3175,425)
  Bottom Layer w6: C44.2@2799.53,385 2836.92,385 2876.92,425 2880,425 2882.18,427.18 2882.18,447.5 2880,449.68 2880,467.75 2880,470 ; C63.2@2799.53,475 2799.53,435.47 C61.2@2800,435 ; C62.2@2926.13,585.2 2939.8,585.2 C57.2@2943.88,581.12 ; v1(2935,475) 2937.3,472.7 2937.3,465.81 2941.34,461.77 C52.2@2941.34,460 ; C48.2@2948.88,398.88 2965.45,382.3 2972.7,382.3 v1(2975,380) 2975.13,380.13 2975.13,392.62 C60.2@2973.88,393.88 ; 2957.26,475 2965.93,483.67 2988.19,483.67 C46.2@2990,485.47 ; C49.2@2983.88,346.12 2983.88,347.73 2987.7,351.56 2987.7,357.7 v1(2990,360) ; v1(2995,380) 3015,380 C50.2@3020,385 ; C56.2@3066.12,383.88 3066.84,383.88 3075,375.72 v1@3075,375 ; v1(3075,790) 3075,793.25 3081.19,799.44 3081.19,807.41 3086.06,812.28 R109.1@3090,812.28 ; v1(3125,380) 3127.3,382.3 3127.3,388.44 3131.12,392.27 C51.2@3131.12,393.88 ; C59.2@3151.12,601.12 3151.12,600.22 3161.45,589.89 v1(3161.45,588.99) 3159.87,587.41 3159.87,577.38 C64.2@3161.12,576.12 ; C47.2@3156.12,413.88 3164.95,422.7 3172.7,422.7 v1(3175,425) ; C55.2@3156.12,531.12 3155.68,531.57 3155.68,533.18 3170,547.5 v1(3170,550) ; v1(3205,445) C58.2@3221.34,445
  Bottom Layer w10: C61.2@2800,435 2835,435 2867.75,467.75 2880,467.75 2897.75,467.75 v1(2915,485) ; v1(2925,570) C62.2@2925,585 ; v1(2935,475) 2957.26,475 ; v1(2940,555) 2940.67,554.33 2940.67,540.67 C53.2@2941.34,540 ; C57.2@2943.9,581.15 2950.53,581.15 2953.86,584.47 2984.72,584.47 2990,589.75 C45.2@2990,595
  other v1: 3074.92,376.51 3075,770
VDDA18: C75.2 C76.2 C77.2 C78.2 C121.2 C122.2 L2.2 L9.2 U12.T5 U12.U10 U12.U11 U12.U15 | length 1491.1
  Top Layer w6: v1(2915,660) 2918.25,660 2923.1,664.85 2933.35,664.85 U12.U15@2934.84,666.34 ; v1(3025.19,674.76) 3025.43,675 3030,675 3037.2,667.8 U12.U11@3037.2,666.34
  Top Layer w8: U12.U10@3062.8,666.34 3064.36,666.34 3072.78,674.76 v1(3074.81,674.76)
  Top Layer w10: L2.2@3165,848.62 3165,844.68 3194.25,815.43 3194.25,805.75 v1(3205,795) C121.2@3210,790 ; U12.T5@3190.75,640.75 3190.89,640.75 3200.86,630.77 v1(3201,630.77)
  PWR w10: 2785,580 2865,660 v1(2915,660)
  PWR w20: v1(1970,340) 2545,340 2785,580 ; 3195,642.42 3195,785 v1(3205,795)
  Bottom Layer w8: v1@3025,675 3025.1,675.1 3025.1,691.24 C122.2@3025,691.34 ; C77.2@3055,691.34 3056.77,691.34 3065.89,682.22 C75.2@3073.25,682.22 ; C78.2@3190,656.34 3191.77,656.34 3191.91,656.2 3191.91,654.43 3199.08,647.25 3199.08,632.69 v1(3201,630.77)
  Bottom Layer w10: C76.2@2905,671.34 2915,661.38 v1(2915,660)
  Bottom Layer w20: L9.2@1968.62,315 1970,316.38 v1(1970,340)
VDDA33: C100.2 C101.2 C102.2 L3.1 U12.T9 U12.T12 | length 357.1
  Top Layer w6: v1(2983.92,644.55) 3001.92,644.55 3004.23,642.24 3010.13,642.24 U12.T12@3011.61,640.75 ; U12.T9@3088.39,640.75 v1@3110.47,640.75
  PWR w10: v1(2983.92,644.55) 2984.03,644.66 v1@3114.66,644.66
  Bottom Layer w6: C100.2@3040,735.47 3040.69,734.78 3040.69,663.99 3069.68,635 L3.1@3073.62,635 ; L3.1@3075,635 3083.66,643.66 C101.2@3105,643.66
  Bottom Layer w10: v1(2983.92,644.55) 2984.36,644.11 2994.56,644.11 C102.2@2995,643.66 ; C101.2@3105,643.66 3105.56,644.22 3117.18,644.22 v1(3117.74,644.77)
VDDS18: C65.2 C66.2 C67.2 C68.2 C69.2 C70.2 C71.2 C72.2 C73.2 C74.2 U12.E9 U12.E14 U12.F4 U12.G16 U12.L17 U12.N4 U12.T16 U12.U6 | length 358.2
  Top Layer w6: v1(2870,510) 2871.4,511.4 2882.26,511.4 U12.L17@2883.66,512.8 ; v1(2885,410) 2885.22,410.22 2909.04,410.22 U12.G16@2909.25,410.43 ; v1(2960,335) 2960.22,335.22 2960.22,359.04 U12.E14@2960.43,359.25 ; v1(3085,330) 3086.9,331.9 3086.9,357.76 U12.E9@3088.39,359.25 ; U12.U6@3165.16,666.34 3166.65,667.83 3166.65,674.24 3169.27,676.87 v1(3169.27,680.11) ; U12.F4@3216.34,386.95 U12.F4@3216.34,384.84 3217.83,386.33 3217.83,398.89 3220.91,401.97 v1(3220.91,405.22) ; v1(3245,660) v1@3250,660
  Top Layer w10: v1(2895,640) 2895.37,640.37 2908.88,640.37 U12.T16@2909.25,640.75 ; v1(3205,555) 3206.34,555 3215.32,563.98 U12.N4@3216.34,563.98
  Bottom Layer w6: v1(2960,335) 2959.87,335.13 2959.87,362.62 C67.2@2961.12,363.88 ; v1(3085,330) C70.2@3085,341.34 ; v1@3220,405 3221.12,406.12 3221.12,424.78 C69.2@3221.34,425
  Bottom Layer w8: v1(2870,510) 2872.71,510 2875.8,513.09 2886.2,513.09 2886.34,513.23 C74.2@2886.34,515 ; v1(2885,410) 2886.91,411.91 2903.25,411.91 2909.43,418.09 2911.2,418.09 2911.34,418.23 C68.2@2911.34,420
  Bottom Layer w10: v1@2903.26,641.1 C73.2@2918.85,641.1 ; C66.2@3165,700.47 3169.27,696.2 v1(3169.27,680.11) 3169.64,679.75 3169.64,659.02 C72.2@3170,658.66 ; C71.2@3198.66,570 3199.53,569.13 3199.53,562.64 3205,557.16 v1(3205,555)
VDDSHV: C83.2 C84.2 C85.2 C86.2 C87.2 C88.2 C89.2 C90.2 C91.2 C92.2 C93.2 C94.2 C95.2 C96.2 C97.2 C98.2 C99.2 R110.1 U12.E7 U12.E12 U12.E16 U12.G5 U12.J5 U12.J16 U12.M5 U12.M16 U12.P5 U12.P16 U12.T7 U12.T14 | length 697.9
  Top Layer w6: v1(2895,540) 2895.81,539.19 2908.44,539.19 U12.M16@2909.25,538.39 ; v1@2905,605 2905,601.75 2907.76,598.99 2907.76,591.06 U12.P16@2909.25,589.57 ; U12.E16@2909.25,359.25 2910.74,359.25 v1@2919.99,350 ; U12.E12@3011.61,359.25 3013.68,359.25 3022.93,350 v1(3025,350) ; v1(3125,355) 3128.25,355 3131.01,357.76 3138.08,357.76 U12.E7@3139.57,359.25 ; U12.T7@3139.57,640.75 U12.T7@3141.67,640.75 ; v1(3150,635) v1@3147.42,635 ; v1@3189.26,477.49 3189.26,463.1 U12.J5@3190.75,461.61 ; v1(3190,520) 3190.37,520.37 3190.37,538.01 U12.M5@3190.75,538.39 ; U12.P5@3190.75,589.57 3190.75,590.16 3200,599.41 v1(3200,600) ; U12.T7@3141.67,640.75 v1@3147.42,635 ; U12.T7@3141.67,640.75 v1@3147.42,635
  Top Layer w10: v1(2900.3,450.25) 2900.3,451.63 2909.25,460.59 U12.J16@2909.25,461.61 ; v1(2952.37,653.23) 2953.9,651.7 2953.9,648.3 2960.43,641.77 U12.T14@2960.43,640.75 ; U12.G5@3190.75,410.43 3190.75,409.95 3200,400.69 v1(3200,400.21)
  Bottom Layer w6: C84.2@2875,605.47 2875.47,605 v1@2905,605 ; C94.2@2913.88,368.88 2915.13,367.62 2915.13,359.61 v1@2920,354.73 ; C91.2@2924.53,310 v1@2924.53,343.71 ; C88.2@2958.23,638.66 C88.2@2960,638.66 ; v1(3025,350) C97.2@3040,350 ; v1(3125,355) 3143,355 3147,359 3156.5,359 C98.2@3157.75,357.75 ; C83.2@3136.12,631.12 3137.38,629.87 3138.98,629.87 3140.23,631.12 3142.88,631.12 3146.75,635 v1(3150,635) ; C87.2@3170,445 3170,470 v1(3185,485) 3195,485 C86.2@3205,475 ; C89.2@3176.12,521.12 3177.38,519.87 3189.87,519.87 v1(3190,520) ; C90.2@3186.12,593.88 3187.73,593.88 3191.56,597.7 3197.7,597.7 v1(3200,600)
  Bottom Layer w10: v1(2895,540) 2896.53,538.47 2902.25,538.47 2916.3,524.43 2916.3,523.7 C96.2@2920,520 ; v1@2899.09,546.26 2899.09,555.47 C85.2@2900,556.34 ; v1(2900.3,450.25) 2901.13,450.25 C95.2@2911.34,440 ; C88.2@2958.23,638.66 2953.9,642.99 2953.9,651.7 v1(2952.37,653.23) 2953.9,654.76 2953.9,657.68 2962.28,666.06 R110.1@2962.28,670 ; v1(3125,355) 3145,335 C92.2@3145,314.53 ; C99.2@3186.12,406.12 3187.35,406.12 3191.74,401.74 3198.47,401.74 v1(3200,400.21) 3200,375 3210,365 C93.2@3210,314.53
  other v1: 2920.93,350.56 2905,610
pads on no net: FID1.1 FID2.1 FID3.1 FID4.1 FID5.1 FID6.1 H1.1 H3.1 H5.0 H6.0 H7.0 H9.1 H10.0 H11.1 H12.1 H13.0 H14.0 J1.1.5 J1.2.5 J1.3.5 J1.4.5 J1.5.5 J1.6.5 J1.7.5 J1.8.5 J3.2 J3.6 J3.8 J3.9 J3.13 J3.14 J3.15 J3.17 J3.18 J3.19 J4.1.MH1 J4.1.MH2 J4.2.MH1 J4.2.MH2 J7. J7.4 LBL1.0 Q1.9A Q1.9B Q1.9C Q1.9D Q2.9A Q2.9B Q2.9C Q2.9D Q3.9A Q3.9B Q3.9C Q3.9D Q4.9A Q4.9B Q4.9C Q4.9D Q5.9A Q5.9B Q5.9C Q5.9D Q6.9A Q6.9B Q6.9C Q6.9D Q7.9A Q7.9B Q7.9C Q7.9D Q8.9A Q8.9B Q8.9C Q8.9D Q9.9@3251.59,1397.72 Q9.9@3292.64,1295.55 Q9.9@3292.64,1340.83 Q9.9@3292.64,1386.1 Q9.9@3345,1295.55 Q9.9@3345,1335.51 Q9.9@3345,1340.83 Q9.9@3345,1386.1 Q9.9@3397.36,1295.55 Q9.9@3397.36,1340.83 Q9.9@3397.36,1386.1 Q9.9@3438.41,1397.72 Q10.9@2951.59,1392.64 Q10.9@2992.64,1290.47 Q10.9@2992.64,1335.75 Q10.9@2992.64,1381.02 Q10.9@3045,1290.47 Q10.9@3045,1330.43 Q10.9@3045,1335.75 Q10.9@3045,1381.02 Q10.9@3097.36,1290.47 Q10.9@3097.36,1335.75 Q10.9@3097.36,1381.02 Q10.9@3138.41,1392.64 U1.1.5 U1.1.14 U1.1.18 U1.2.5 U1.2.14 U1.2.18 U1.3.5 U1.3.14 U1.3.18 U1.4.5 U1.4.14 U1.4.18 U1.5.5 U1.5.14 U1.5.18 U1.6.5 U1.6.14 U1.6.18 U1.7.5 U1.7.14 U1.7.18 U1.8.5 U1.8.14 U1.8.18 U5.7 U7.1 U9.9 U10.1 U10.22 U10.23 U10.24 U10.25 U10.26 U10.27 U11.1 U11.22 U11.23 U11.24 U11.25 U11.26 U11.27 U12.A2 U12.A4 U12.A5 U12.A6 U12.A7 U12.A9 U12.A14 U12.A17 U12.B3 U12.B4 U12.B5 U12.B6 U12.B7 U12.B9 U12.B14 U12.B16 U12.B19 U12.C14 U12.C19 U12.D10 U12.E19 U12.H1 U12.J2 U12.J19 U12.J20 U12.T2 U12.U17 U12.W4 U12.W5 U12.Y2 U13.A2 U13.A3 U13.B1 U13.B5 U13.C5 U14.A2 U14.B1 U14.B5 U14.C5 U16.1 U19.1.8 U19.1.28 U19.2.8 U19.2.28 U21.1 U22.11 U23.6 U25.3 U27.1.3@977.13,1800 U27.1.8@1010,1800 U27.2.3@977.13,618.9 U27.2.8@1010,618.9 U29.5 U29.7@2545,1894.57 U29.7@2545,1930 U30.1 U30.2 U30.5 U30.6 U30.11 U30.12 U30.13 U30.14 U30.15 U30.18 U30.19 U30.20 U30.21 U30.22 U30.23 U30.24 U30.25 U30.27 U30.29 U30.30 U30.31 U30.32 U30.40 U30.41 U30.42 U30.43 U30.44 U30.45 U30.46 U30.49 U30.50 U30.53 U30.54 U30.56 U30.57 U30.65 U30.67 U30.71 U30.72 U30.73 U30.74 U30.75 U30.76 U30.77 U30.78 U30.81 U30.82 U30.83 U30.84 U30.85 U30.86 U30.91 U30.92 U30.95 U30.102 U30.103 U30.104 U30.105 U30.106 U30.107 U30.108 U30.109 U30.110 U30.111 U30.112 U30.116 U30.117 U30.118 U30.119 U30.120 U30.121 U30.123 U30.124 U30.125 U30.126 U30.127 U30.128 U31.1.7@7110,692.28 U31.1.7@7110,727.72 U31.2.7@7456.93,1634.49 U31.2.7@7456.93,1669.92 U31.3.7@6125.75,692.28 U31.3.7@6125.75,727.72 U31.4.7@6472.68,1634.49 U31.4.7@6472.68,1669.92 U31.5.7@5141.5,692.28 U31.5.7@5141.5,727.72 U31.6.7@5488.43,1634.49 U31.6.7@5488.43,1669.92 U31.7.7@4157.24,692.28 U31.7.7@4157.24,727.72 U31.8.7@4504.17,1634.49 U31.8.7@4504.17,1669.92 U32.1.7@7372.28,430 U32.1.7@7407.72,430 U32.2.7@7159.21,1932.2 U32.2.7@7194.65,1932.2 U32.3.7@6388.03,430 U32.3.7@6423.46,430 U32.4.7@6174.96,1932.2 U32.4.7@6210.39,1932.2 U32.5.7@5403.78,430 U32.5.7@5439.21,430 U32.6.7@5190.71,1932.2 U32.6.7@5226.14,1932.2 U32.7.7@4419.53,430 U32.7.7@4454.96,430 U32.8.7@4206.46,1932.2 U32.8.7@4241.89,1932.2

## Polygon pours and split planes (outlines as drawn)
L+7 on Top Layer "TOP_LAYER_L+7_P370" (solid, remove dead copper, pour order 370): 4137.24,790.75 4137.24,650 4192.24,595 4337.24,595 4337.24,700.75 4396.5,760 4486.5,760 4596.5,870 4596.5,980 4471.5,980 4371.5,880 4226.5,880
NetQ8_1 on Top Layer "TOP_LAYER_NETQ8_1_P374" (solid, remove dead copper, pour order 374): 4607.96,1296.54 4657.96,1296.54 4657.96,1221.54 4607.96,1221.54
NetC165.7_2 on Top Layer "TOP_LAYER_NETC165.7_2_P371" (solid, remove dead copper, pour order 371): 4342.24,600 4511.5,600 4511.5,750 4386.5,750 4342.24,705.75
GND on Top Layer "TOP_LAYER_GND_P368" (solid, remove dead copper, pour order 368): 4057.24,770 4057.24,840 4130,840 4140,830 4140,780 4130,770
L+5 on Top Layer "TOP_LAYER_L+5_P365" (solid, remove dead copper, pour order 365): 5075.39,950 5065.39,960 5065.39,1025 5045.39,1045 5045.39,1145 5160.39,1145 5160.39,950
NetC165.1_2 on Top Layer "TOP_LAYER_NETC165.1_2_P194" (solid, remove dead copper, pour order 194): 7295,600 7470,600 7470,785 7295,785
NetC165.5_2 on Top Layer "TOP_LAYER_NETC165.5_2_P364" (solid, remove dead copper, pour order 364): 5326.5,600 5500,600 5500,785 5326.5,785
GND on Top Layer "TOP_LAYER_GND_P363" (solid, remove dead copper, pour order 363): 5316.5,375 5500,375 5500,585 5316.5,585
L+5 on Top Layer "TOP_LAYER_L+5_P362" (solid, remove dead copper, pour order 362): 5121.5,745 5121.5,660 5121.5,655 5181.5,595 5311.5,595 5311.5,745 5241.5,745 5211.5,775 5211.5,840 5166.5,840 5121.5,795
NetC166.5_2 on Top Layer "TOP_LAYER_NETC166.5_2_P361" (solid, remove dead copper, pour order 361): 5176.5,590 5311.5,590 5311.5,375 5176.5,375
GND on Top Layer "TOP_LAYER_GND_P360" (solid, remove dead copper, pour order 360): 5041.5,770 5041.5,840 5101.5,840 5111.5,830 5111.5,780 5101.5,770
L+5 on Top Layer "TOP_LAYER_L+5_P359" (solid, remove dead copper, pour order 359): 5121.5,745 5121.5,660 5121.5,655 5181.5,595 5311.5,595 5311.5,745 5241.5,745 5211.5,775 5211.5,840 5166.5,840 5121.5,795
24V on Top Layer "TOP_LAYER_24V_P357" (solid, remove dead copper, pour order 357): 5035,1250 5035,1145 4949.59,1145 4949.59,1250
NetQ5_1 on Top Layer "TOP_LAYER_NETQ5_1_P352" (solid, remove dead copper, pour order 352): 4990,1140 5040,1140 5040,1065 4990,1065
L+7 on Top Layer "TOP_LAYER_L+7_P351" (solid, remove dead copper, pour order 351): 4505,1140 4605,1140 4605,1040 4505,1040
NetQ7_1 on Top Layer "TOP_LAYER_NETQ7_1_P350" (solid, remove dead copper, pour order 350): 4624.92,1130 4675,1130 4675,1095 4615,1095 4615,1120.08
24V on Top Layer "TOP_LAYER_24V_P349" (solid, remove dead copper, pour order 349): 4710.41,1235.12 4710.41,1130.12 4625,1130.12 4625,1235.12
GND on Top Layer "TOP_LAYER_GND_P348" (solid, remove dead copper, pour order 348): 4670,1410 5000,1410 5000,950 4670,950
GND on Top Layer "TOP_LAYER_GND_P344" (solid, remove dead copper, pour order 344): 4670,1410 4670,1350 4610,1350 4610,1410
L+6 on Top Layer "TOP_LAYER_L+6_P343" (solid, remove dead copper, pour order 343): 5183.53,1625 5330,1625 5330,1505 5295,1470 5260,1470 5145,1355 5145,1220 5045,1220 5045,1494.17
L+8 on Top Layer "TOP_LAYER_L+8_P341" (solid, remove dead copper, pour order 341): 4497.93,1215 4607.93,1215 4607.93,1325 4582.93,1350 4582.93,1415 4572.93,1415 4497.93,1415
L+8 on Top Layer "TOP_LAYER_L+8_P340" (solid, remove dead copper, pour order 340): 4501.5,1410 4586.5,1410 4586.5,1475 4551.5,1510 4521.5,1540 4521.5,1764.77 4326.5,1764.77 4326.5,1595 4436.5,1595 4436.5,1520 4476.5,1480 4476.5,1435
NetC165.8_2 on Top Layer "TOP_LAYER_NETC165.8_2_P339" (solid, remove dead copper, pour order 339): 4319.17,1762.2 4147.24,1762.2 4147.24,1730 4242.8,1634.45 4319.17,1634.45
NetC165.6_2 on Top Layer "TOP_LAYER_NETC165.6_2_P338" (solid, remove dead copper, pour order 338): 5303.43,1762.2 5131.5,1762.2 5131.5,1730 5227.05,1634.45 5303.43,1634.45
NetC165.4_2 on Top Layer "TOP_LAYER_NETC165.4_2_P337" (solid, remove dead copper, pour order 337): 6287.68,1762.2 6115.75,1762.2 6115.75,1730 6211.3,1634.45 6287.68,1634.45
GND on Top Layer "TOP_LAYER_GND_P336" (solid, remove dead copper, pour order 336): 4329.17,1987.2 4147.24,1987.2 4147.24,1777.2 4329.17,1777.2
GND on Top Layer "TOP_LAYER_GND_P335" (solid, remove dead copper, pour order 335): 5313.43,1987.2 5131.5,1987.2 5131.5,1777.2 5313.43,1777.2
GND on Top Layer "TOP_LAYER_GND_P334" (solid, remove dead copper, pour order 334): 6297.68,1987.2 6115.75,1987.2 6115.75,1777.2 6297.68,1777.2
GND on Top Layer "TOP_LAYER_GND_P333" (solid, remove dead copper, pour order 333): 5055.39,1010 5055.39,950 4995.39,950 4995.39,1010
L+6 on Top Layer "TOP_LAYER_L+6_P330" (solid, remove dead copper, pour order 330): 5511.5,1500 5511.5,1715 5456.5,1770 5306.5,1770 5306.5,1625 5216.5,1625 5216.5,1500
GND on Top Layer "TOP_LAYER_GND_P326" (solid, remove dead copper, pour order 326): 4603.82,1592.8 4603.82,1522.8 4543.82,1522.8 4533.82,1532.8 4533.82,1582.8 4543.82,1592.8
GND on Top Layer "TOP_LAYER_GND_P325" (solid, remove dead copper, pour order 325): 5588.07,1592.8 5588.07,1522.8 5528.07,1522.8 5518.07,1532.8 5518.07,1582.8 5528.07,1592.8
NetU31.5_4 on Top Layer "TOP_LAYER_NETU31.5_4_P214" (solid, remove dead copper, pour order 214): 5061.5,750 5121.5,750 5121.5,665 5061.5,665
GND on Top Layer "TOP_LAYER_GND_P239" (solid, remove dead copper, pour order 239): 5231.5,835 5231.5,765 5171.5,765 5161.5,775 5161.5,825 5171.5,835
NetC166.6_2 on Top Layer "TOP_LAYER_NETC166.6_2_P159" (solid, remove dead copper, pour order 159): 5453.43,1772.2 5318.43,1772.2 5318.43,1987.2 5453.43,1987.2
NetU31.6_4 on Top Layer "TOP_LAYER_NETU31.6_4_P231" (solid, remove dead copper, pour order 231): 5568.43,1612.2 5508.43,1612.2 5508.43,1697.2 5568.43,1697.2
NetC166.2_2 on Top Layer "TOP_LAYER_NETC166.2_2_P155" (solid, remove dead copper, pour order 155): 7421.93,1772.2 7286.93,1772.2 7286.93,1987.2 7421.93,1987.2
L+2 on Top Layer "TOP_LAYER_L+2_P163" (solid, remove dead copper, pour order 163): 7480,1500 7480,1715 7425,1770 7275,1770 7275,1625 7185,1625 7185,1500
GND on Top Layer "TOP_LAYER_GND_P171" (solid, remove dead copper, pour order 171): 7281.93,1987.2 7100,1987.2 7100,1777.2 7281.93,1777.2
NetC165.2_2 on Top Layer "TOP_LAYER_NETC165.2_2_P195" (solid, remove dead copper, pour order 195): 7271.93,1762.2 7100,1762.2 7100,1730 7195.55,1634.45 7271.93,1634.45
NetU31.2_4 on Top Layer "TOP_LAYER_NETU31.2_4_P211" (solid, remove dead copper, pour order 211): 7536.93,1612.2 7476.93,1612.2 7476.93,1697.2 7536.93,1697.2
GND on Top Layer "TOP_LAYER_GND_P235" (solid, remove dead copper, pour order 235): 7553.07,1592.8 7553.07,1522.8 7493.07,1522.8 7483.07,1532.8 7483.07,1582.8 7493.07,1592.8
GND on Top Layer "TOP_LAYER_GND_P321" (solid, remove dead copper, pour order 321): 7010,770 7010,840 7070,840 7080,830 7080,780 7070,770
GND on Top Layer "TOP_LAYER_GND_P130" (solid, remove dead copper, pour order 130): 2753.69,780 3325.45,780 3325.45,207.5 2753.69,207.5
L+3 on Top Layer "TOP_LAYER_L+3_P320" (solid, remove dead copper, pour order 320): 6475,1140 6575,1140 6575,1040 6475,1040
EARTH on Top Layer "TOP_LAYER_EARTH_P309" (solid, remove dead copper, pour order 309): 500,0 500,2365 0,2365 0,0
GND on Top Layer "TOP_LAYER_GND_P308" (solid, remove dead copper, pour order 308): 560,1330 680,1330 680,1030 560,1030
GND on Top Layer "TOP_LAYER_GND_P307" (solid, remove dead copper, pour order 307): 1380,2020 1380,1453.19 955,1453.19 955,2020
NetC132.1_1 on Top Layer "TOP_LAYER_NETC132.1_1_P306" (solid, remove dead copper, pour order 306): 19 vertices, not listed, extent 1210,1810 1335,1985
NetC129.1_1 on Top Layer "TOP_LAYER_NETC129.1_1_P305" (solid, remove dead copper, pour order 305): 979.68,1535 979.68,1680 1034.68,1680 1064.68,1710 1064.68,1735 1014.68,1735 1014.68,1765 1094.68,1765 1094.68,1535
GND on Top Layer "TOP_LAYER_GND_P304" (solid, remove dead copper, pour order 304): 2615,1715 2730,1715 2730,1530 2615,1530
GND on Top Layer "TOP_LAYER_GND_P301" (solid, remove dead copper, pour order 301): 6640,1410 6640,1350 6580,1350 6580,1410
L+3 on Top Layer "TOP_LAYER_L+3_P164" (solid, remove dead copper, pour order 164): 6105.75,790.75 6105.75,650 6160.75,595 6305.75,595 6305.75,700.75 6365,760 6455,760 6565,870 6565,995 6455,995 6340,880 6195,880
NetQ3_1 on Top Layer "TOP_LAYER_NETQ3_1_P296" (solid, remove dead copper, pour order 296): 6594.92,1130 6645,1130 6645,1095 6585,1095 6585,1120.08
NetQ4_1 on Top Layer "TOP_LAYER_NETQ4_1_P295" (solid, remove dead copper, pour order 295): 6577.96,1296.54 6627.96,1296.54 6627.96,1221.54 6577.96,1221.54
L+4 on Top Layer "TOP_LAYER_L+4_P290" (solid, remove dead copper, pour order 290): 6470,1215 6580,1215 6580,1325 6555,1350 6555,1415 6545,1415 6470,1415
24V on Top Layer "TOP_LAYER_24V_P289" (solid, remove dead copper, pour order 289): 6680.41,1235.12 6680.41,1130.12 6595,1130.12 6595,1235.12
L+5 on Top Layer "TOP_LAYER_L+5_P285" (solid, remove dead copper, pour order 285): 5045,1320 5145,1320 5145,1220 5045,1220
24V on Top Layer "TOP_LAYER_24V_P281" (solid, remove dead copper, pour order 281): 2450,1175 2450,1220 2475,1245 2515,1245 2515,1205 2485,1175
GND on Top Layer "TOP_LAYER_GND_P259" (solid, remove dead copper, pour order 259): 2470,1850 2470,1985 2675,1985 2675,1850
NetQ2_1 on Top Layer "TOP_LAYER_NETQ2_1_P257" (solid, remove dead copper, pour order 257): 6955,1295 7000,1295 7000,1260 6940,1260 6940,1280
L+2 on Top Layer "TOP_LAYER_L+2_P255" (solid, remove dead copper, pour order 255): 7153.53,1625 7300,1625 7300,1505 7265,1470 7230,1470 7115,1355 7115,1220 7015,1220 7015,1494.17
24V on Top Layer "TOP_LAYER_24V_P249" (solid, remove dead copper, pour order 249): 7005,1250 7005,1145 6919.59,1145 6919.59,1250
GND on Top Layer "TOP_LAYER_GND_P248" (solid, remove dead copper, pour order 248): 6640,1410 6960,1410 6960,960 6640,960
GND on Top Layer "TOP_LAYER_GND_P246" (solid, remove dead copper, pour order 246): 7025,1010 7025,950 6965,950 6965,1010
NetQ1_1 on Top Layer "TOP_LAYER_NETQ1_1_P244" (solid, remove dead copper, pour order 244): 6960,1140 7010,1140 7010,1065 6960,1065
L+1 on Top Layer "TOP_LAYER_L+1_P243" (solid, remove dead copper, pour order 243): 7045,950 7035,960 7035,1025 7015,1045 7015,1145 7130,1145 7130,950
NetC166.8_2 on Top Layer "TOP_LAYER_NETC166.8_2_P161" (solid, remove dead copper, pour order 161): 4469.17,1772.2 4334.17,1772.2 4334.17,1987.2 4469.17,1987.2
NetU31.8_4 on Top Layer "TOP_LAYER_NETU31.8_4_P234" (solid, remove dead copper, pour order 234): 4584.17,1612.2 4524.17,1612.2 4524.17,1697.2 4584.17,1697.2
NetC166.7_2 on Top Layer "TOP_LAYER_NETC166.7_2_P160" (solid, remove dead copper, pour order 160): 4192.24,590 4327.24,590 4327.24,375 4192.24,375
GND on Top Layer "TOP_LAYER_GND_P193" (solid, remove dead copper, pour order 193): 4332.24,375 4510,375 4510,585 4332.24,585
NetU31.7_4 on Top Layer "TOP_LAYER_NETU31.7_4_P232" (solid, remove dead copper, pour order 232): 4077.24,760 4137.24,760 4137.24,640 4077.24,640
NetC166.4_2 on Top Layer "TOP_LAYER_NETC166.4_2_P158" (solid, remove dead copper, pour order 158): 6437.68,1772.2 6302.68,1772.2 6302.68,1987.2 6437.68,1987.2
L+4 on Top Layer "TOP_LAYER_L+4_P169" (solid, remove dead copper, pour order 169): 6470,1410 6555,1410 6555,1475 6520,1510 6490,1540 6490,1764.77 6295,1764.77 6295,1595 6405,1595 6405,1520 6445,1480 6445,1435
NetU31.4_4 on Top Layer "TOP_LAYER_NETU31.4_4_P213" (solid, remove dead copper, pour order 213): 6552.68,1612.2 6492.68,1612.2 6492.68,1697.2 6552.68,1697.2
GND on Top Layer "TOP_LAYER_GND_P237" (solid, remove dead copper, pour order 237): 6572.32,1592.8 6572.32,1522.8 6512.32,1522.8 6502.32,1532.8 6502.32,1582.8 6512.32,1592.8
NetC166.3_2 on Top Layer "TOP_LAYER_NETC166.3_2_P156" (solid, remove dead copper, pour order 156): 6160.75,590 6295.75,590 6295.75,375 6160.75,375
GND on Top Layer "TOP_LAYER_GND_P191" (solid, remove dead copper, pour order 191): 6300.75,375 6480,375 6480,585 6300.75,585
NetC165.3_2 on Top Layer "TOP_LAYER_NETC165.3_2_P209" (solid, remove dead copper, pour order 209): 6310.75,600 6480,600 6480,750 6355,750 6310.75,705.75
NetU31.3_4 on Top Layer "TOP_LAYER_NETU31.3_4_P212" (solid, remove dead copper, pour order 212): 6045.75,750 6105.75,750 6105.75,665 6045.75,665
GND on Top Layer "TOP_LAYER_GND_P236" (solid, remove dead copper, pour order 236): 6029.25,770 6029.25,840 6089.25,840 6099.25,830 6099.25,780 6089.25,770
NetU31.1_4 on Top Layer "TOP_LAYER_NETU31.1_4_P210" (solid, remove dead copper, pour order 210): 7030,750 7090,750 7090,665 7030,665
GND on Top Layer "TOP_LAYER_GND_P170" (solid, remove dead copper, pour order 170): 7285,375 7470,375 7470,585 7285,585
L+1 on Top Layer "TOP_LAYER_L+1_P162" (solid, remove dead copper, pour order 162): 7090,745 7090,660 7090,655 7150,595 7280,595 7280,745 7210,745 7180,775 7180,840 7135,840 7090,795
NetC166.1_2 on Top Layer "TOP_LAYER_NETC166.1_2_P154" (solid, remove dead copper, pour order 154): 7140,590 7280,590 7280,375 7140,375
1V25 on Top Layer "TOP_LAYER_1V25_P153" (solid, remove dead copper, pour order 153): 1940,1130 1995,1130 1995,1090 1940,1090
3V3 on Top Layer "TOP_LAYER_3V3_P152" (solid, remove dead copper, pour order 152): 1975,1235 1930,1235 1930,1285 1975,1285
GND on Top Layer "TOP_LAYER_GND_P151" (solid, remove dead copper, pour order 151): 1750,1095 1800,1095 1820,1115 1820,1255 1830,1265 1830,1320 1805,1320 1750,1265
NetC113_1 on Top Layer "TOP_LAYER_NETC113_1_P148" (solid, remove dead copper, pour order 148): 1850,1295 1875,1295 1910,1260 1925,1260 1925,1235 1935,1225 1975,1225 1975,1200 1935,1200 1925,1190 1925,1180 1875,1180 1850,1205
NetC114_2 on Top Layer "TOP_LAYER_NETC114_2_P146" (solid, remove dead copper, pour order 146): 1935,1095 1820,1095 1820,1115 1870,1165 1980,1165 1980,1135 1935,1135
NetC129.2_1 on Top Layer "TOP_LAYER_NETC129.2_1_P107" (solid, remove dead copper, pour order 107): 980,350 980,495 1035,495 1065,525 1065,550 1015,550 1015,580 1095,580 1095,350
GND on Top Layer "TOP_LAYER_GND_P145" (solid, remove dead copper, pour order 145): 1355,860 1355,275 925,275 925,860
NetC132.2_1 on Top Layer "TOP_LAYER_NETC132.2_1_P144" (solid, remove dead copper, pour order 144): 19 vertices, not listed, extent 1210,625 1335,800
3V3 on Top Layer "TOP_LAYER_3V3_P142" (solid, remove dead copper, pour order 142): 2315,1490 2315,1540 2415,1540 2415,1490
NetC104_2 on Top Layer "TOP_LAYER_NETC104_2_P138" (solid, remove dead copper, pour order 138): 2135,1130 2450,1130 2450,1165 2490,1165 2490,1130 2490,1070 2160,1070 2135,1095
NetC108_1 on Top Layer "TOP_LAYER_NETC108_1_P137" (solid, remove dead copper, pour order 137): 2010,1490 2230,1490 2260,1490 2260,1445 2365,1445 2365,1483.12 2395,1483.12 2395,1445 2420,1445 2420,1390 2420,1365 2245,1365 2245,1390 2010,1390
NetC103_1 on Top Layer "TOP_LAYER_NETC103_1_P109" (solid, remove dead copper, pour order 109): 2190,1210 2130,1210 2130,1260 2120,1270 2010,1270 2009.76,1270.24 2009.76,1340.63 2230.24,1340.63 2230,1340.39 2230,1270 2200,1270 2190,1260
GND on Top Layer "TOP_LAYER_GND_P136" (solid, remove dead copper, pour order 136): 2075,1200 2075,1140 2210,1140 2255,1185 2440,1185 2440,1340 2240,1340 2240,1260 2200,1260 2200,1200
24V on Top Layer "TOP_LAYER_24V_P135" (solid, remove dead copper, pour order 135): 2600,1425 2600.82,1425.82 3150,1425.82 3150,1185 2600,1185
GND on Top Layer "TOP_LAYER_GND_P133" (solid, remove dead copper, pour order 133): 3460,1635 3740,1635 3740,1290 3345,1290 3345,1520
Vcore on Top Layer "TOP_LAYER_VCORE_P128" (solid, remove dead copper, pour order 128): 3160,470 3175,470 3190,455 3220,455 3225,450 3225,430 3215,420 3190,420 3170,400 3160,400 3155,405 3155,465
Vcore on Top Layer "TOP_LAYER_VCORE_P129" (solid, remove dead copper, pour order 129): 2905,650 2950,650 2950,417.76 2965,400 3140,400 3140,610 3185,610 3185,360 3000,360 3000,325 2970,325 2970,362.07 2905,424.08
GND on Bottom Layer "BOTTOM_LAYER_GND_P373" (solid, remove dead copper, pour order 373): 4605,1010 4670,1010 4670,930 4605,930
L+7 on Bottom Layer "BOTTOM_LAYER_L+7_P372" (solid, remove dead copper, pour order 372): 4500,1145 4605,1145 4605,1030 4595,1020 4595,945 4500,945
GND on Bottom Layer "BOTTOM_LAYER_GND_P367" (solid, remove dead copper, pour order 367): 4182.24,770 4182.24,840 4242.24,840 4252.24,830 4252.24,780 4242.24,770
GND on Bottom Layer "BOTTOM_LAYER_GND_P358" (solid, remove dead copper, pour order 358): 5166.5,770 5166.5,840 5226.5,840 5236.5,830 5236.5,780 5226.5,770
24V on Bottom Layer "BOTTOM_LAYER_24V_P356" (solid, remove dead copper, pour order 356): 5035.39,1210 5035.39,1127.5 4925.39,1127.5 4925.39,1210
24V on Bottom Layer "BOTTOM_LAYER_24V_P355" (solid, remove dead copper, pour order 355): 4730,1211.25 4730,1128.75 4620,1128.75 4620,1211.25
NetQ7_1 on Bottom Layer "BOTTOM_LAYER_NETQ7_1_P354" (solid, remove dead copper, pour order 354): 4730,1130 4730,1090 4700,1090 4675,1065 4610,1065 4610,1140 4655,1140 4665,1130
NetQ5_1 on Bottom Layer "BOTTOM_LAYER_NETQ5_1_P353" (solid, remove dead copper, pour order 353): 4930.39,1140 4930.39,1095 4960.39,1095 4995.39,1060 5040,1060 5040,1140
NetQ8_1 on Bottom Layer "BOTTOM_LAYER_NETQ8_1_P347" (solid, remove dead copper, pour order 347): 4730,1210 4730,1245 4715,1245 4655,1305 4610,1305 4610,1220 4690,1220 4700,1210
NetQ6_1 on Bottom Layer "BOTTOM_LAYER_NETQ6_1_P345" (solid, remove dead copper, pour order 345): 4930,1245 4955,1245 4965,1255 4965,1275 4980,1290 5030,1290 5030,1225 5015,1210 4930,1210
L+8 on Bottom Layer "BOTTOM_LAYER_L+8_P342" (solid, remove dead copper, pour order 342): 4346.5,1760 4476.5,1760 4526.5,1710 4526.5,1615 4581.5,1560 4581.5,1335 4501.5,1335 4501.5,1420 4346.5,1575
GND on Bottom Layer "BOTTOM_LAYER_GND_P332" (solid, remove dead copper, pour order 332): 5050,1410 5050,1350 4990,1350 4990,1410
L+6 on Bottom Layer "BOTTOM_LAYER_L+6_P331" (solid, remove dead copper, pour order 331): 5045,1220 5150,1220 5150,1410 5070,1410 5070,1345 5045,1320
GND on Bottom Layer "BOTTOM_LAYER_GND_P328" (solid, remove dead copper, pour order 328): 4478.82,1592.8 4478.82,1522.8 4418.82,1522.8 4408.82,1532.8 4408.82,1582.8 4418.82,1592.8
GND on Bottom Layer "BOTTOM_LAYER_GND_P327" (solid, remove dead copper, pour order 327): 5463.07,1592.8 5463.07,1522.8 5403.07,1522.8 5393.07,1532.8 5393.07,1582.8 5403.07,1592.8
NetU31.5_4 on Bottom Layer "BOTTOM_LAYER_NETU31.5_4_P098" (solid, remove dead copper, pour order 98): 5381.5,405 5381.5,375 5171.5,375 5171.5,595 5124,642.5 5124,750 5061.5,750 5061.5,400 5061.5,330 5481.5,330 5561.5,410 5561.5,745 5491.5,745 5491.5,425 5471.5,405
NetC166.5_2 on Bottom Layer "BOTTOM_LAYER_NETC166.5_2_P182" (solid, remove dead copper, pour order 182): 5176.5,375 5311.5,375 5311.5,550 5176.5,550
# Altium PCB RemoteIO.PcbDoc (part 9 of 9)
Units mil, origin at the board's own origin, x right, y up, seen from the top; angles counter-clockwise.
Board outline 7874.02 x 2362.2 mil, 6 copper layers (Top Layer, GND1, Layer 2, PWR, GND2, Bottom Layer), stack 60.956 mil thick; 686 components, 447 nets, 2681 pads, 1481 vias.

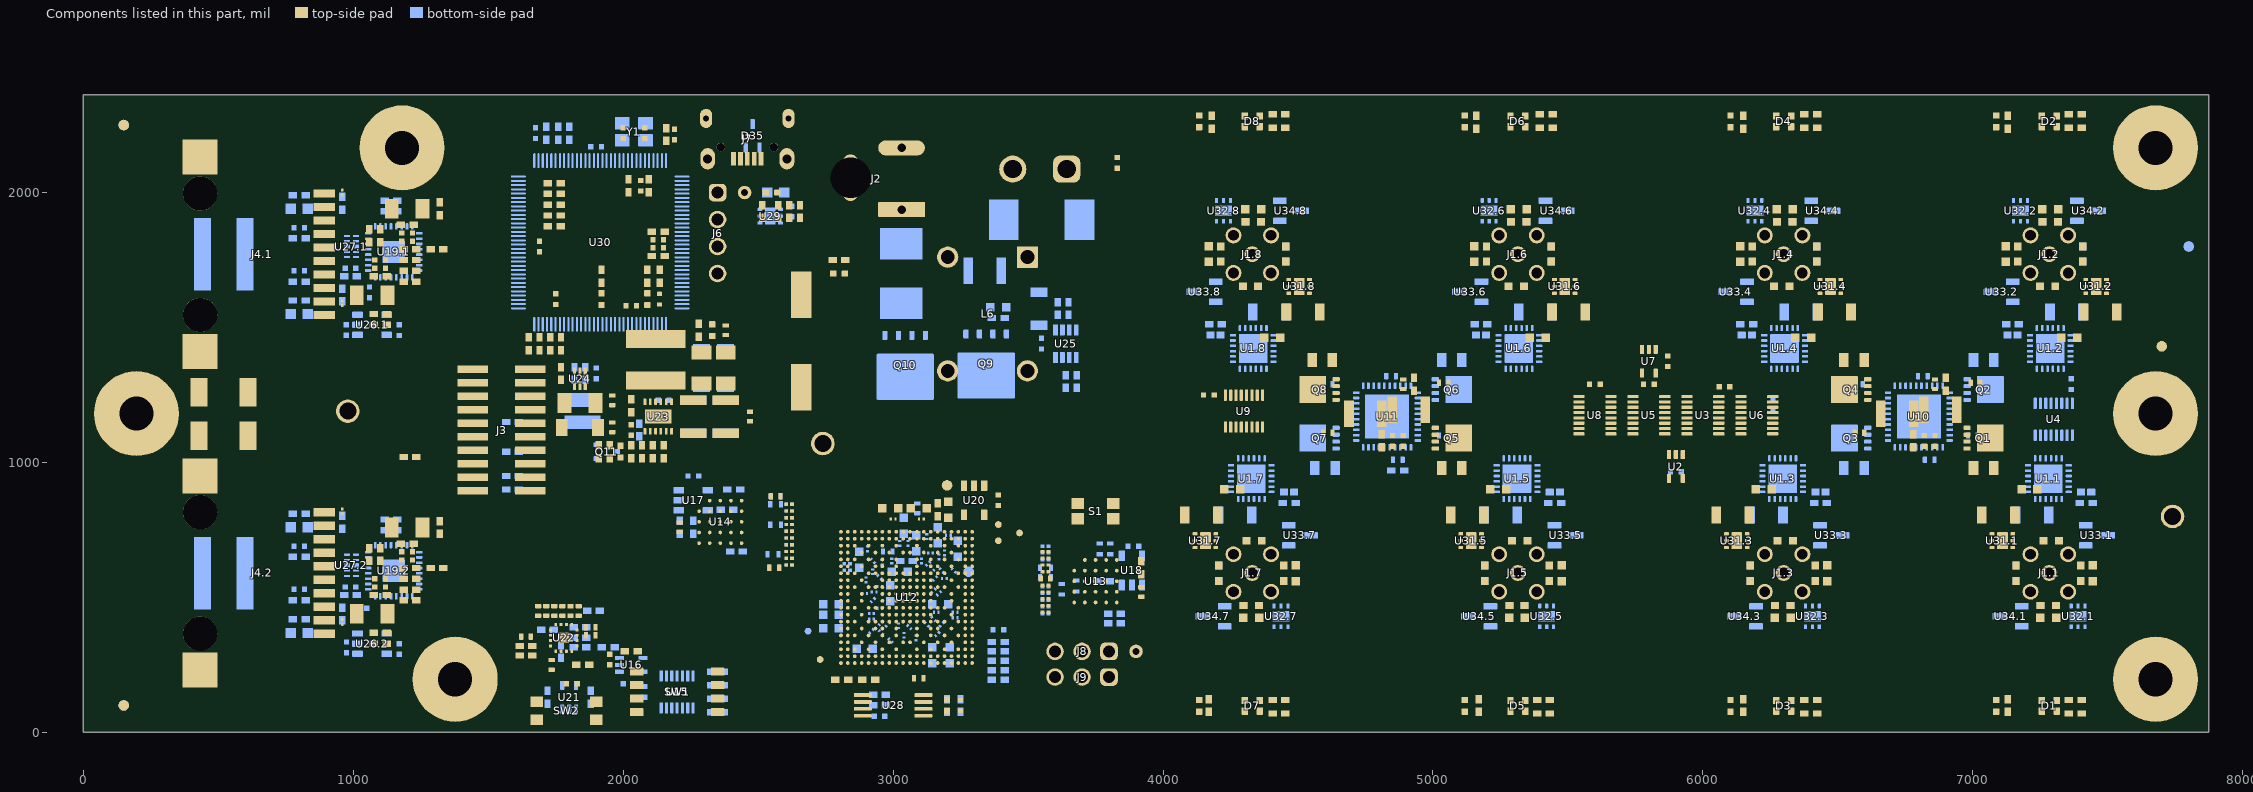
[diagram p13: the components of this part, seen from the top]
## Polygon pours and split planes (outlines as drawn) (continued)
GND on Bottom Layer "BOTTOM_LAYER_GND_P190" (solid, remove dead copper, pour order 190): 5316.5,375 5486.5,375 5486.5,585 5316.5,585
NetC165.5_2 on Bottom Layer "BOTTOM_LAYER_NETC165.5_2_P206" (solid, remove dead copper, pour order 206): 5326.5,600 5486.5,600 5486.5,785 5326.5,785
NetC165.5_2 on Bottom Layer "BOTTOM_LAYER_NETC165.5_2_P222" (solid, remove dead copper, pour order 222): 5256.5,880 5291.5,880 5291.5,800 5256.5,800
L+5 on Bottom Layer "BOTTOM_LAYER_L+5_P317" (solid, remove dead copper, pour order 317): 5179.25,600 5129.25,650 5129.25,740 5289.25,740 5289.25,620 5269.25,600
NetU31.6_4 on Bottom Layer "BOTTOM_LAYER_NETU31.6_4_P101" (solid, remove dead copper, pour order 101): 5248.43,1957.2 5248.43,1987.2 5458.43,1987.2 5458.43,1767.2 5505.93,1719.7 5505.93,1612.2 5568.43,1612.2 5568.43,1962.2 5568.43,2032.2 5148.43,2032.2 5068.43,1952.2 5068.43,1617.2 5138.43,1617.2 5138.43,1937.2 5158.43,1957.2
NetC166.6_2 on Bottom Layer "BOTTOM_LAYER_NETC166.6_2_P183" (solid, remove dead copper, pour order 183): 5453.43,1987.2 5318.43,1987.2 5318.43,1812.2 5453.43,1812.2
GND on Bottom Layer "BOTTOM_LAYER_GND_P199" (solid, remove dead copper, pour order 199): 5313.43,1987.2 5143.43,1987.2 5143.43,1777.2 5313.43,1777.2
NetC165.6_2 on Bottom Layer "BOTTOM_LAYER_NETC165.6_2_P215" (solid, remove dead copper, pour order 215): 5303.43,1762.2 5143.43,1762.2 5143.43,1577.2 5303.43,1577.2
NetC165.6_2 on Bottom Layer "BOTTOM_LAYER_NETC165.6_2_P233" (solid, remove dead copper, pour order 233): 5373.43,1482.2 5338.43,1482.2 5338.43,1562.2 5373.43,1562.2
L+6 on Bottom Layer "BOTTOM_LAYER_L+6_P313" (solid, remove dead copper, pour order 313): 5450.67,1762.2 5500.67,1712.2 5500.67,1622.2 5340.67,1622.2 5340.67,1742.2 5360.67,1762.2
GND on Bottom Layer "BOTTOM_LAYER_GND_P324" (solid, remove dead copper, pour order 324): 6154.25,770 6154.25,840 6214.25,840 6224.25,830 6224.25,780 6214.25,770
GND on Bottom Layer "BOTTOM_LAYER_GND_P086" (solid, remove dead copper, pour order 86): 6447.32,1592.8 6447.32,1522.8 6387.32,1522.8 6377.32,1532.8 6377.32,1582.8 6387.32,1592.8
GND on Bottom Layer "BOTTOM_LAYER_GND_P323" (solid, remove dead copper, pour order 323): 7433.07,1592.8 7433.07,1522.8 7373.07,1522.8 7363.07,1532.8 7363.07,1582.8 7373.07,1592.8
L+2 on Bottom Layer "BOTTOM_LAYER_L+2_P316" (solid, remove dead copper, pour order 316): 7419.17,1762.2 7469.17,1712.2 7469.17,1622.2 7309.17,1622.2 7309.17,1742.2 7329.17,1762.2
GND on Bottom Layer "BOTTOM_LAYER_GND_P262" (solid, remove dead copper, pour order 262): 7020,1410 7020,1350 6960,1350 6960,1410
NetC166.2_2 on Bottom Layer "BOTTOM_LAYER_NETC166.2_2_P179" (solid, remove dead copper, pour order 179): 7421.93,1987.2 7286.93,1987.2 7286.93,1812.2 7421.93,1812.2
GND on Bottom Layer "BOTTOM_LAYER_GND_P187" (solid, remove dead copper, pour order 187): 7281.93,1987.2 7111.93,1987.2 7111.93,1777.2 7281.93,1777.2
NetU31.2_4 on Bottom Layer "BOTTOM_LAYER_NETU31.2_4_P091" (solid, remove dead copper, pour order 91): 7216.93,1957.2 7216.93,1987.2 7426.93,1987.2 7426.93,1767.2 7474.43,1719.7 7474.43,1612.2 7536.93,1612.2 7536.93,1962.2 7536.93,2032.2 7116.93,2032.2 7036.93,1952.2 7036.93,1617.2 7106.93,1617.2 7106.93,1937.2 7126.93,1957.2
NetC165.2_2 on Bottom Layer "BOTTOM_LAYER_NETC165.2_2_P203" (solid, remove dead copper, pour order 203): 7271.93,1762.2 7111.93,1762.2 7111.93,1577.2 7271.93,1577.2
NetC165.2_2 on Bottom Layer "BOTTOM_LAYER_NETC165.2_2_P219" (solid, remove dead copper, pour order 219): 7341.93,1482.2 7306.93,1482.2 7306.93,1562.2 7341.93,1562.2
GND on Bottom Layer "BOTTOM_LAYER_GND_P241" (solid, remove dead copper, pour order 241): 7135,770 7135,840 7195,840 7205,830 7205,780 7195,770
L+4 on Bottom Layer "BOTTOM_LAYER_L+4_P322" (solid, remove dead copper, pour order 322): 6475,1320 6575,1320 6575,1220 6475,1220
L+5 on Bottom Layer "BOTTOM_LAYER_L+5_P319" (solid, remove dead copper, pour order 319): 5050,1150 5160,1150 5160,1030 5050,1030
L+7 on Bottom Layer "BOTTOM_LAYER_L+7_P318" (solid, remove dead copper, pour order 318): 4195,600 4145,650 4145,740 4305,740 4305,620 4285,600
L+1 on Bottom Layer "BOTTOM_LAYER_L+1_P315" (solid, remove dead copper, pour order 315): 7147.76,600 7097.76,650 7097.76,740 7257.76,740 7257.76,620 7237.76,600
L+3 on Bottom Layer "BOTTOM_LAYER_L+3_P314" (solid, remove dead copper, pour order 314): 6163.5,600 6113.5,650 6113.5,740 6273.5,740 6273.5,620 6253.5,600
EARTH on Bottom Layer "BOTTOM_LAYER_EARTH_P311" (solid, remove dead copper, pour order 311): 500,0 500,2365 0,2365 0,0
L+4 on Bottom Layer "BOTTOM_LAYER_L+4_P310" (solid, remove dead copper, pour order 310): 6315,1760 6445,1760 6495,1710 6495,1615 6550,1560 6550,1335 6470,1335 6470,1420 6315,1575
GND on Bottom Layer "BOTTOM_LAYER_GND_P302" (solid, remove dead copper, pour order 302): 6575,1010 6640,1010 6640,930 6575,930
L+3 on Bottom Layer "BOTTOM_LAYER_L+3_P300" (solid, remove dead copper, pour order 300): 6470,1145 6575,1145 6575,1030 6565,1020 6565,945 6470,945
NetQ4_1 on Bottom Layer "BOTTOM_LAYER_NETQ4_1_P297" (solid, remove dead copper, pour order 297): 6700,1210 6700,1245 6685,1245 6625,1305 6580,1305 6580,1220 6660,1220 6670,1210
NetQ3_1 on Bottom Layer "BOTTOM_LAYER_NETQ3_1_P294" (solid, remove dead copper, pour order 294): 6700,1130 6700,1090 6670,1090 6645,1065 6580,1065 6580,1140 6625,1140 6635,1130
24V on Bottom Layer "BOTTOM_LAYER_24V_P293" (solid, remove dead copper, pour order 293): 6700,1211.25 6700,1128.75 6590,1128.75 6590,1211.25
L+8 on Bottom Layer "BOTTOM_LAYER_L+8_P088" (solid, remove dead copper, pour order 88): 4500,1220 4620,1220 4620,1320 4500,1320
GND on Bottom Layer "BOTTOM_LAYER_GND_P263" (solid, remove dead copper, pour order 263): 2470,1850 2470,2025 2675,2025 2675,1850
+3V3_XDS110 on Bottom Layer "BOTTOM_LAYER_+3V3_XDS110_P089" (solid, remove dead copper, pour order 89): 2025,1480 2070,1480 2070,1570 2025,1570
L+2 on Bottom Layer "BOTTOM_LAYER_L+2_P256" (solid, remove dead copper, pour order 256): 7015,1220 7120,1220 7120,1410 7040,1410 7040,1345 7015,1320
NetQ2_1 on Bottom Layer "BOTTOM_LAYER_NETQ2_1_P252" (solid, remove dead copper, pour order 252): 6900,1245 6925,1245 6935,1255 6935,1275 6950,1290 7000,1290 7000,1225 6985,1210 6900,1210
24V on Bottom Layer "BOTTOM_LAYER_24V_P251" (solid, remove dead copper, pour order 251): 7005,1210 7005,1127.5 6895,1127.5 6895,1210
L+1 on Bottom Layer "BOTTOM_LAYER_L+1_P250" (solid, remove dead copper, pour order 250): 7005,1145 7115,1145 7115,1040 7005,1040
NetQ1_1 on Bottom Layer "BOTTOM_LAYER_NETQ1_1_P247" (solid, remove dead copper, pour order 247): 6900,1134.05 6900,1095 6930,1095 6945,1080 7000,1080 7000,1134.05
NetC166.8_2 on Bottom Layer "BOTTOM_LAYER_NETC166.8_2_P185" (solid, remove dead copper, pour order 185): 4469.17,1987.2 4334.17,1987.2 4334.17,1812.2 4469.17,1812.2
GND on Bottom Layer "BOTTOM_LAYER_GND_P201" (solid, remove dead copper, pour order 201): 4329.17,1987.2 4159.17,1987.2 4159.17,1777.2 4329.17,1777.2
NetU31.8_4 on Bottom Layer "BOTTOM_LAYER_NETU31.8_4_P103" (solid, remove dead copper, pour order 103): 4264.17,1957.2 4264.17,1987.2 4474.17,1987.2 4474.17,1767.2 4521.67,1719.7 4521.67,1612.2 4584.17,1612.2 4584.17,1962.2 4584.17,2032.2 4164.17,2032.2 4084.17,1952.2 4084.17,1617.2 4154.17,1617.2 4154.17,1937.2 4174.17,1957.2
NetC165.8_2 on Bottom Layer "BOTTOM_LAYER_NETC165.8_2_P217" (solid, remove dead copper, pour order 217): 4319.17,1762.2 4159.17,1762.2 4159.17,1577.2 4319.17,1577.2
NetC165.8_2 on Bottom Layer "BOTTOM_LAYER_NETC165.8_2_P245" (solid, remove dead copper, pour order 245): 4389.17,1482.2 4354.17,1482.2 4354.17,1562.2 4389.17,1562.2
NetC166.7_2 on Bottom Layer "BOTTOM_LAYER_NETC166.7_2_P184" (solid, remove dead copper, pour order 184): 4192.24,375 4327.24,375 4327.24,550 4192.24,550
GND on Bottom Layer "BOTTOM_LAYER_GND_P200" (solid, remove dead copper, pour order 200): 4332.24,375 4502.24,375 4502.24,585 4332.24,585
NetU31.7_4 on Bottom Layer "BOTTOM_LAYER_NETU31.7_4_P102" (solid, remove dead copper, pour order 102): 4397.24,405 4397.24,375 4187.24,375 4187.24,595 4139.74,642.5 4139.74,760 4077.24,760 4077.24,400 4077.24,330 4497.24,330 4577.24,410 4577.24,745 4507.24,745 4507.24,425 4487.24,405
NetC165.7_2 on Bottom Layer "BOTTOM_LAYER_NETC165.7_2_P216" (solid, remove dead copper, pour order 216): 4342.24,600 4502.24,600 4502.24,785 4342.24,785
NetC165.7_2 on Bottom Layer "BOTTOM_LAYER_NETC165.7_2_P242" (solid, remove dead copper, pour order 242): 4272.24,880 4307.24,880 4307.24,800 4272.24,800
NetC166.4_2 on Bottom Layer "BOTTOM_LAYER_NETC166.4_2_P181" (solid, remove dead copper, pour order 181): 6437.68,1987.2 6302.68,1987.2 6302.68,1812.2 6437.68,1812.2
GND on Bottom Layer "BOTTOM_LAYER_GND_P189" (solid, remove dead copper, pour order 189): 6297.68,1987.2 6127.68,1987.2 6127.68,1777.2 6297.68,1777.2
NetU31.4_4 on Bottom Layer "BOTTOM_LAYER_NETU31.4_4_P093" (solid, remove dead copper, pour order 93): 6232.68,1957.2 6232.68,1987.2 6442.68,1987.2 6442.68,1767.2 6490.18,1719.7 6490.18,1612.2 6552.68,1612.2 6552.68,1962.2 6552.68,2032.2 6132.68,2032.2 6052.68,1952.2 6052.68,1617.2 6122.68,1617.2 6122.68,1937.2 6142.68,1957.2
NetC165.4_2 on Bottom Layer "BOTTOM_LAYER_NETC165.4_2_P205" (solid, remove dead copper, pour order 205): 6287.68,1762.2 6127.68,1762.2 6127.68,1577.2 6287.68,1577.2
NetC165.4_2 on Bottom Layer "BOTTOM_LAYER_NETC165.4_2_P221" (solid, remove dead copper, pour order 221): 6357.68,1482.2 6322.68,1482.2 6322.68,1562.2 6357.68,1562.2
NetC166.3_2 on Bottom Layer "BOTTOM_LAYER_NETC166.3_2_P180" (solid, remove dead copper, pour order 180): 6160.75,375 6295.75,375 6295.75,550 6160.75,550
GND on Bottom Layer "BOTTOM_LAYER_GND_P188" (solid, remove dead copper, pour order 188): 6300.75,375 6470.75,375 6470.75,585 6300.75,585
NetU31.3_4 on Bottom Layer "BOTTOM_LAYER_NETU31.3_4_P092" (solid, remove dead copper, pour order 92): 6365.75,405 6365.75,375 6155.75,375 6155.75,595 6108.25,642.5 6108.25,750 6045.75,750 6045.75,400 6045.75,330 6465.75,330 6545.75,410 6545.75,745 6475.75,745 6475.75,425 6455.75,405
NetC165.3_2 on Bottom Layer "BOTTOM_LAYER_NETC165.3_2_P204" (solid, remove dead copper, pour order 204): 6310.75,600 6470.75,600 6470.75,785 6310.75,785
NetC165.3_2 on Bottom Layer "BOTTOM_LAYER_NETC165.3_2_P220" (solid, remove dead copper, pour order 220): 6240.75,880 6275.75,880 6275.75,800 6240.75,800
NetC165.1_2 on Bottom Layer "BOTTOM_LAYER_NETC165.1_2_P218" (solid, remove dead copper, pour order 218): 7225,880 7260,880 7260,800 7225,800
NetC165.1_2 on Bottom Layer "BOTTOM_LAYER_NETC165.1_2_P202" (solid, remove dead copper, pour order 202): 7295,600 7455,600 7455,785 7295,785
NetU31.1_4 on Bottom Layer "BOTTOM_LAYER_NETU31.1_4_P090" (solid, remove dead copper, pour order 90): 7350,405 7350,375 7140,375 7140,595 7092.5,642.5 7092.5,750 7030,750 7030,400 7030,330 7450,330 7530,410 7530,745 7450,745 7450,440 7415,405
GND on Bottom Layer "BOTTOM_LAYER_GND_P186" (solid, remove dead copper, pour order 186): 7285,375 7455,375 7455,585 7285,585
NetC166.1_2 on Bottom Layer "BOTTOM_LAYER_NETC166.1_2_P178" (solid, remove dead copper, pour order 178): 7145,375 7280,375 7280,550 7145,550
NetC114_2 on Bottom Layer "BOTTOM_LAYER_NETC114_2_P177" (solid, remove dead copper, pour order 177): 1780,1175 1780,1120 1820,1120 1820,1095 1920,1095 1920,1175
GND on Bottom Layer "BOTTOM_LAYER_GND_P176" (solid, remove dead copper, pour order 176): 565,1910 680,1910 680,450 565,450
NetC104_2 on Bottom Layer "BOTTOM_LAYER_NETC104_2_P175" (solid, remove dead copper, pour order 175): 2440,1130 2440,1070 2160,1070 2135,1095 2135,1130
NetC108_1 on Bottom Layer "BOTTOM_LAYER_NETC108_1_P150" (solid, remove dead copper, pour order 150): 2250,1445 2420,1445 2420,1365 2250,1365
GND on Bottom Layer "BOTTOM_LAYER_GND_P143" (solid, remove dead copper, pour order 143): 2080,1200 2080,1140 2210,1140 2255,1185 2440,1185 2440,1340 2240,1340 2240,1260 2200,1260 2200,1200
24V on Bottom Layer "BOTTOM_LAYER_24V_P141" (solid, remove dead copper, pour order 141): 2600,1425 2600.82,1425.82 3150,1425.82 3150,1185 2600,1185
GND on Bottom Layer "BOTTOM_LAYER_GND_P134" (solid, remove dead copper, pour order 134): 3500,1650 3500,1580 3580,1580 3580,1650
NetQ9_1 on Bottom Layer "BOTTOM_LAYER_NETQ9_1_P087" (solid, remove dead copper, pour order 87): 2915,1535 2915,1435 3400,1435 3400,1535
NetC117_2 on Bottom Layer "BOTTOM_LAYER_NETC117_2_P132" (solid, remove dead copper, pour order 132): 3160,1450 3160,1230 3450,1230 3450,1385 3480,1385 3535,1440 3627.2,1440 3627.2,1570 3540,1570 3450,1480 3450,1450
NetC120_2 on Bottom Layer "BOTTOM_LAYER_NETC120_2_P131" (solid, remove dead copper, pour order 131): 2935,1525 3115,1525 3175,1525 3315,1665 3315,1800 3150,1800 3150,1750 3100,1700 2935,1700
NetC120_1 on Bottom Layer "BOTTOM_LAYER_NETC120_1_P122" (solid, remove dead copper, pour order 122): 23 vertices, not listed, extent 2800,1650 3765,2335
NetD25_2 on Bottom Layer "BOTTOM_LAYER_NETD25_2_P121" (solid, remove dead copper, pour order 121): 2945,1750 3110,1750 3110,1800 3135,1825 3485,1825 3510,1850 3510,2110 3470,2150 3200,2150 3050,2000 2945,2000 2935,1990 2935,1760
GND on Bottom Layer "BOTTOM_LAYER_GND_P106" (solid, remove dead copper, pour order 106): 1715,450 1840,450 1840,285 1715,285
3V3 on Bottom Layer "BOTTOM_LAYER_3V3_P108" (solid, remove dead copper, pour order 108): 3020.75,632.05 3020.75,875 2965,875 2965,632.05
Vcore on Bottom Layer "BOTTOM_LAYER_VCORE_P115" (solid, remove dead copper, pour order 115): 3060,820 3105,820 3105,780 3080,755 3060,755
1V25 on Bottom Layer "BOTTOM_LAYER_1V25_P118" (solid, remove dead copper, pour order 118): 3065,890 3140,890 3145,885 3145,835 3140,830 3065,830 3060,835 3060,885
Vcore on Bottom Layer "BOTTOM_LAYER_VCORE_P116" (solid, remove dead copper, pour order 116): 2950,530 2920,530 2910,540 2910,580 2925,595 2980,595 2985,600 2985,580 2955,580 2950,575
GND on Bottom Layer "BOTTOM_LAYER_GND_P117" (solid, remove dead copper, pour order 117): 2720,825 3310,825 3310,210 2720,210
3V3 on PWR "PWR_3V3_P149" (solid, remove dead copper, pour order 149): 26 vertices, not listed, extent 920,0 7874.02,2362.2
24V on PWR "PWR_24V_P270" (solid, remove dead copper, pour order 270): 3185,930 3185,1020 3120,1085 2455,1085 2455,1280 3565,1280 3565,1515 3850,1515 3850,2150 7565,2150 7565,300 4050,300 4050,930 3805,930
+3V3_XDS110 on PWR "PWR_+3V3_XDS110_P254" (solid, remove dead copper, pour order 254): 1550,2300 2750,2300 2750,1550 1550,1550
1V25 on PWR "PWR_1V25_P085" (solid, remove dead copper, pour order 85): 1945,1135 2010,1135 2010,1090 2030,1070 3090,1070 3145,1015 3145,840 3080,840 3005,915 1955,915 1945,925
24V on PWR "PWR_24V_P139" (solid, remove dead copper, pour order 139): 2455,1425.82 3150,1425.82 3150,1185 2455,1185
NetQ9_1 on PWR "PWR_NETQ9_1_P125" (solid, remove dead copper, pour order 125): 2965,1520 2965,1425 3395,1425 3395,1520
VDDS18 on PWR "PWR_VDDS18_P104" (solid, remove dead copper, pour order 104): 33 vertices, not listed, extent 2795,255 3310,680
VDDSHV on PWR "PWR_VDDSHV_P110" (solid, remove dead copper, pour order 110): 2855,700 3245,700 3245,325 2855,325
VDDA18 on PWR "PWR_VDDA18_P097" (solid, remove dead copper, pour order 97): 2905,695 2905,630 2940,630 2940,670 2965,670 2965,630 3210,630 3210,695
L+5 on Layer 2 "LAYER_2_L+5_P366" (solid, remove dead copper, pour order 366): 5045.39,1145 5045.39,670 5115.39,600 5285.39,600 5295.39,610 5295.39,745 5290.39,745 5170.39,865 5170.39,1145
L+1 on Layer 2 "LAYER_2_L+1_P303" (solid, remove dead copper, pour order 303): 7015,1145 7015,670 7085,600 7255,600 7265,610 7265,745 7260,745 7140,865 7140,1145
L+7 on Layer 2 "LAYER_2_L+7_P261" (solid, remove dead copper, pour order 261): 4615,1220 4615,1545 4525,1635 4525,1710 4480,1755 4350,1755 4350,1655 4515,1490 4515,1220
24V on Layer 2 "LAYER_2_24V_P124" (solid, remove dead copper, pour order 124): 2600,1425 2600.82,1425.82 3150,1425.82 3150,1185 2600,1185
Vcore on Layer 2 "LAYER_2_VCORE_P095" (solid, remove dead copper, pour order 95): 2915,625 2900,610 2900,353.81 2928.81,325 3162.32,325 3190,352.68 3190,625 3190,710 3095,805 3065,805 2940,680 2940,650
VDDS18 on Layer 2 "LAYER_2_VDDS18_P094" (solid, remove dead copper, pour order 94): 17 vertices, not listed, extent 2820,275 3280,700
GND on GND2 "GND2_GND_P298" (solid, remove dead copper, pour order 298): 2790,2362.2 2790,1635 2900,1635 2900,1500 3395,1500 3395,1635 3800,1635 3800,2362.2 7875,2362.2 7875,0 745.98,0 745.98,2362.2
24V on GND2 "GND2_24V_P126" (solid, remove dead copper, pour order 126): 2600,1425 2600.82,1425.82 3150,1425.82 3150,1185 2600,1185
CS1 on GND2 "GND2_CS1_P111" (solid, remove dead copper, pour order 111): 2165,980 2685,980 2685,590 2165,590
GND on GND1 "GND1_GND_P229" (solid, remove dead copper, pour order 229): 2790,2362.2 2790,1635 2900,1635 2900,1500 3400,1500 3400,1635 3800,1635 3800,2362.2 7874.02,2362.2 7874.02,0 635,0 635,2362.2
24V on GND1 "GND1_24V_P123" (solid, remove dead copper, pour order 123): 2600,1425 2600.82,1425.82 3150,1425.82 3150,1185 2600,1185

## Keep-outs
Keep-Out Layer:
  text ".Layer_Name" at 577,-858.49 h60

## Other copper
Top Layer:
  text "Eth 1" at 590.04,2130.58 h100
  text "GND" at 3540,1911.08 h100
  text "+" at 3306,1889.34 h100
  text "24V 5A max" at 2758.92,1784.92 h100 r90
  text "IO 8" at 4793.92,1691.69 h100 r90
  text "IO 6" at 5778.92,1691.77 h100 r90
  text "IO 4" at 6764.67,1691.9 h100 r90
  text "IO 2" at 7748.92,1692.08 h100 r90
  text "24V 9A max" at 3930,1600 h100 r90
  text "IO 1" at 7748.92,517.93 h100 r90
  text "IO 7" at 4793.92,511.75 h100 r90
  text "IO 5" at 5778.92,511.52 h100 r90
  text "IO 3" at 6763.88,511.75 h100 r90
  text "Eth 2" at 590.04,180.58 h100
  text ".Layer_Name" at 577,-858.49 h60
Bottom Layer:
  text ".Layer_Name" at 577,-858.49 h60

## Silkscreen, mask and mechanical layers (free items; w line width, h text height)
Top Overlay:
  circle w10: c3670,640 r10
  lines w10: 3630,400 3630.03,400.03 3869.97,400.03 3870,400.06 3870,720 3630,720 3630,400
  text "XDS110" at 2264,2096 h30 r90
  text "JTAG" at 1496,816 h30
  text "Bootmode" at 2106,296 h30
  text "'.PRJ_Number'.PCB_Rev" at 470,50 h108.27
  text "RUN" at 3389.13,50.03 h80 r90
  text "ERR" at 3460,50.03 h80 r90
  text "Reset" at 1634,36 h30 r90
  text ".Layer_Name" at 577,-858.49 h60
Bottom Overlay:
  text ".Layer_Name" at 577,-858.49 h60
Top Paste:
  text ".Layer_Name" at 577,-858.49 h60
Bottom Paste:
  text ".Layer_Name" at 577,-858.49 h60
Top Solder:
  text "Eth 1" at 590.04,2130.58 h100
  text "GND" at 3540,1911.08 h100
  text "+" at 3306,1889.34 h100
  text "24V 5A max" at 2758.92,1784.92 h100 r90
  text "IO 4" at 6764.67,1693 h100 r90
  text "IO 2" at 7748.92,1693.08 h100 r90
  text "IO 8" at 4793.92,1691.69 h100 r90
  text "IO 6" at 5778.92,1691.77 h100 r90
  text "24V 9A max" at 3928.92,1599.92 h100 r90
  text "IO 1" at 7748.92,517.93 h100 r90
  text "IO 7" at 4793.92,511.75 h100 r90
  text "IO 5" at 5778.92,511.52 h100 r90
  text "IO 3" at 6764.62,511.75 h100 r90
  text "Eth 2" at 590.04,180.58 h100
  text ".Layer_Name" at 577,-858.49 h60
  text ".Layer_Name" at 577,-858.49 h60
Bottom Solder:
  text ".Layer_Name" at 577,-858.49 h60
Drill Guide:
  text ".Layer_Name" at 577,-858.49 h60
M1 Board Outline:
  the board outline again, w10
  text ".Layer_Name" at 577,-858.49 h60
M2 Board Dimensions:
  rectangle: 0,-275 125,-150
  rectangle: 125,-400 500,-275
  lines w7: 0,-275 1000,-275 ; 125,-400 125,-150 ; 250,-400 250,-150 ; 500,-400 500,-150 ; 750,-400 750,-150 ; 0,-400 1000,-400 1000,-150 0,-150 0,-400
  text ".Layer_Name" at 577,-858.49 h60
M3 3D STEP Top:
  text ".Layer_Name" at 577,-858.49 h60
M4 3D STEP Bottom:
  text ".Layer_Name" at 577,-858.49 h60
M5 Assembly Top:
  lines w10: -292,-930.17 6308,-930.17 ; -292,-726.83 6310,-726.83 ; -292,-523.5 -292,-1133.5 3713,-1133.5 6310,-1133.5 6310,-523.5 -291.5,-523.5 -291.5,-1133.5 1284,-1133.5 ; 2173,-1133.5 2173,-523.5 ; 3440,-726.83 3440,-523.5 ; 4280,-726.83 4280,-523.5 ; 4902,-1140 4902,-937.17
  text "COMPONENTS MARKED 'DNP' SHOULD NOT BE POPULATED." at 1153.5,-318.5 h60
  text "ASSEMBLY VARIANT:" at 1153,-434 h60
  text ".VariantName" at 2189,-434 h60
  text "PCB VIEWED FROM TOP SIDE" at -228.5,-655.67 h60
  text "BOARD #:" at 2248,-655.67 h60
  text ".PRJ_Number" at 2793.5,-655.67 h60
  text "REV:" at 3638,-655.67 h60
  text ".PCB_Rev" at 3929.5,-655.67 h60
  text "SVN REV:" at 4476,-655.67 h60
  text ".VersionControl_RevNumber" at 4982,-655.67 h60
  text "TID #:" at 2248,-859 h60
  text ".TID" at 2793.5,-859 h60
  text "PLOT NAME =" at -228.5,-1064.34 h60
  text ".plot_File_Name" at 577,-1064.34 h60
  text "GENERATED    :" at 2250,-1064.34 h60
  text ".Print_Date" at 3119.5,-1064.34 h60
  text ".Print_Time" at 3848.5,-1064.34 h60
  text "TEXAS INSTRUMENTS" at 5113,-1064.34 h60
M6 Assembly Bottom:
  lines w10: -292.5,-727.33 6309.5,-727.33 ; -290.5,-930.67 6309.5,-930.67 ; 1115.5,-1140.5 1115.5,-937.67 ; 1737.5,-727.33 1737.5,-524 ; 2577.5,-727.33 2577.5,-524 ; 3844.5,-1134 3844.5,-524 ; 4733.5,-1134 6309,-1134 6309,-524 -292.5,-524 -292.5,-1134 2304.5,-1134 6309.5,-1134 6309.5,-524
  text "COMPONENTS MARKED 'DNP' SHOULD NOT BE POPULATED." at 6102,-318 h60
  text ".VariantName" at 5058,-434 h60
  text "ASSEMBLY VARIANT:" at 6097,-434 h60
  text ".VersionControl_RevNumber" at 1035.5,-656.17 h60
  text "SVN REV:" at 1541.5,-656.17 h60
  text ".PCB_Rev" at 2088,-656.17 h60
  text "REV:" at 2379.5,-656.17 h60
  text ".PRJ_Number" at 3224,-656.17 h60
  text "BOARD #:" at 3769.5,-656.17 h60
  text "PCB VIEWED FROM BOTTOM SIDE" at 6246,-656.17 h60
  text ".TID" at 3224,-859.5 h60
  text "TID #:" at 3769.5,-859.5 h60
  text "TEXAS INSTRUMENTS" at 904.5,-1064.84 h60
  text ".Print_Time" at 2169,-1064.84 h60
  text ".Print_Date" at 2898,-1064.84 h60
  text "GENERATED    :" at 3767.5,-1064.84 h60
  text ".plot_File_Name" at 5440.5,-1064.84 h60
  text "PLOT NAME =" at 6246,-1064.84 h60
M9 Title Sheet:
  drawing of 57 lines, arcs and shapes, not listed
  text "1" at 739.84,8036.5 h70
  text "2" at 3235.5,8036.5 h70
  text "3" at 5724.84,8036.5 h70
  text "4" at 8231.51,8036.5 h70
  text "5" at 10730.5,8036.5 h70
  text "6" at 13235.5,8036.5 h70
  text "A" at -416.5,6893.5 h70
  text "A" at 14383.5,6893.5 h70
  text "B" at -416.5,4513.5 h70
  text "B" at 14383.5,4513.5 h70
  text "C" at -416.5,2138.5 h70
  text "C" at 14383.5,2138.5 h70
  text "PROJECT TITLE:" at 11343.5,277.5 h45
  text ".PRJ_Title" at 11393.5,144.17 h70
  text "DESIGNED FOR:" at 11343.5,-23.5 h45
  text ".PRJ_Customer" at 11393.5,-163.5 h70
  text "D" at -416.5,-231.5 h70
  text "D" at 14383.5,-231.5 h70
  text "FILE NAME:" at 11343.5,-323.5 h45
  text ".PCB_File_Name_No_Path" at 11393.5,-443.5 h70
  text "Texas Instruments (TI) and/or its licensors do not warrant the accuracy or completeness of this specification" at 6374,-605.34 h45
  text "ENGINEER:" at 11343.5,-613.5 h45
  text "LAYOUT BY:" at 12848.5,-613.5 h45
  text "or any information contained therein. TI and/or its licensors do not warrant that this design will meet" at 6329.01,-718 h45
  text ".PRJ_Engineer" at 11393.5,-768.49 h70
  text ".PCB_Layout" at 12899,-768.49 h70
  text "the specifications, will be suitable for your application or fit for any particular purpose, or will operate in" at 6329.01,-830.67 h45
  text ".Layer_Name" at 577,-858.49 h60
  text "ALTIUM DESIGNER VERSION:" at 12848.5,-923.5 h45
  text "an implementation. TI and/or its licensors do not warrant that the design is production worthy. You should" at 6329.01,-943.33 h45
  text "completely validate and test your design implementation to confirm the system functionality for your application." at 6374,-1056 h45
  text ".print_Scale" at 11393.5,-1056.83 h70
  text ".Application_BuildNumber" at 12899,-1056.83 h70
  text "1" at 739.84,-1263.5 h70
  text "2" at 3235.5,-1263.5 h70
  text "3" at 5724.84,-1263.5 h70
  text "4" at 8231.51,-1263.5 h70
  text "5" at 10730.5,-1263.5 h70
  text "6" at 13235.5,-1263.5 h70
M10 Fab Notes:
  drawing of 189 lines, arcs and shapes, not listed
  text "DESIGN INFORMATION" at 12382.02,6356.17 h60
  text "MIN. TRACK WIDTH:" at 11737.46,6224.05 h60
  text "4" at 12833.7,6224.05 h60
  text "MIL" at 12988.46,6224.05 h60
  text "4" at 12667.32,6102.36 h60
  text "MIN. CLEARANCE:" at 11737.46,6099.92 h60
  text "MIL" at 12988.46,6099.92 h60
  text "MIN. VIA PAD SIZE:" at 11737.46,5975.8 h60
  text "18" at 12803.71,5975.8 h60
  text "MIL" at 12988.46,5975.8 h60
  text "0.05mm (2MIL)" at 12432.46,5845.9 h60
  text "MINIMUM ANNULAR RING" at 11408.23,5837.67 h60
  text "EXTERNAL" at 13140.46,5837.67 h60
  text "PER" at 11608.23,5727.55 h60
  text "IPC-D-275 CLASS 2 LEVEL C" at 11828.23,5727.54 h60
  text "MIL, HOLES" at 13316.46,5627.07 h60
  text "+/-" at 12924,5618.48 h60
  text "+/-" at 13778,5618.48 h60
  text "REGISTRATION TOLERANCES:" at 11408.23,5617.42 h60
  text "METAL" at 12608,5617.42 h60
  text "5" at 13184.2,5617.42 h60
  text "3" at 14017.2,5617.42 h60
  text "MIL" at 14133.46,5617.42 h60
  text "HOLE SIZE TOLERANCE (UNLESS OTHERWISE SPECIFIED):" at 11408.23,5519.1 h60
  text "+/-" at 13778,5516.23 h60
  text "3" at 14017.2,5515.17 h60
  text "MIL" at 14133.46,5515.17 h60
  text "MATERIAL:" at 11333.46,5377.52 h60
  text "FR-4 High Tg" at 12319.9,5249 h60
  text "X" at 12175.46,5241.01 h60
  text "FR-4" at 11754.46,5236.49 h60
  text "OTHER" at 13242.46,5236.49 h60
  text "62 MIL (1.6mm) +/-10%" at 12074.56,5093.46 h60
  text "X" at 11954.46,5091.01 h60
  text "THICKNESS:" at 11408.23,5085.24 h60
  text "OTHER" at 13359.46,5085.24 h60
  text "TOLERANCE:" at 11408.23,4946.92 h60
  text "X" at 12256.46,4946.92 h60
  text "ANSI IPC-6012 TYPE 3 CLASS 2" at 12434.48,4946.92 h60
  text "OTHER +/-" at 12434.46,4802.73 h60
  text "BOW & TWIST:" at 11408.23,4657.54 h60
  text "X" at 12256.46,4657.54 h60
  text "ANSI IPC-6012 TYPE 3 CLASS 2" at 12434.48,4657.54 h60
  text "OTHER +/-" at 12434.46,4510.85 h60
  text "DRILLING:" at 11333.46,4380.23 h60
  text "NC_DRILL FILES" at 13094.46,4275.04 h60
  text "REFERENCE:" at 11408.23,4271.1 h60
  text "X" at 12065.46,4271.01 h60
  text "AS SHOWN" at 12243.46,4271.1 h60
  text "X" at 12966.46,4271.1 h60
  text "OTHER" at 13392.46,4128.85 h60
  text "PTH COPPER THICKNESS:" at 11407.91,4125.32 h60
  text "X" at 12547.14,4125.32 h60
  text "20-30 um" at 12675.14,4125.32 h60
  text "BOARD FINISH:" at 11333.46,3977.73 h60
  text "SILKSCREEN:" at 11488.68,3867.6 h60
  text "X" at 12446.46,3867.6 h60
  text "TOP" at 12563.46,3867.6 h60
  text "X" at 12956.46,3867.6 h60
  text "BOTTOM" at 13074.46,3867.6 h60
  text "SILKSCREEN COLOR:" at 11488.68,3712.41 h60
  text "X" at 12445.46,3712.41 h60
  text "WHITE" at 12563.46,3712.41 h60
  text "OTHER" at 13074.46,3712.41 h60
  text "X" at 12576.46,3568.96 h60
  text "GREEN" at 12694.46,3568.96 h60
  text "OTHER" at 13312.46,3568.96 h60
  text "SOLDER RESIST COLOR:" at 11488.68,3562.1 h60
  text "X" at 12576.46,3414.71 h60
  text "MATTE" at 12694.46,3414.71 h60
  text "SEMI-GLOSS" at 13312,3414.07 h60
  text "IMMERSION GOLD (ENIG)" at 12394.46,3241.94 h60
  text "ENEPIG" at 13732,3234.72 h60
  text "SURFACE FINISH:" at 11333.46,3233.72 h60
  text "X" at 12216.46,3233.72 h60
  text "IMM. TIN/SILVER OR EQUIV" at 11663,3096.4 h60
  text "OTHER" at 13094.46,3092.47 h60
  text "ARRAY/PANEL:" at 11333.46,2937.09 h60
  text "CUT AND TRIM PER M1 BOARD OUTLINE" at 12394.46,2928.87 h60
  text "N.C. ROUTE" at 12394.46,2792.9 h60
  text "X" at 13082.46,2792.9 h60
  text "V. SCORE" at 13260.46,2792.9 h60
  text "CERTIFICATION:" at 11333.46,2663.77 h60
  text "MATERIALS AND WORKMANSHIP FOR ALL PCBS" at 12058.46,2663.77 h60
  text "TO MEET OR EXCEED THE REQUIREMENTS OF:" at 12058.46,2569.71 h60
  text "X" at 11695.97,2441.08 h60
  text "ANSI IPC-A-600F CLASS ->" at 11823.96,2441.08 h60
  text "X" at 13471.97,2441.08 h60
  text "2" at 13581.96,2441.08 h60
  text "1" at 13266.96,2439.58 h60
  text "3" at 13935.96,2439.58 h60
  text "X" at 12507.97,2293.39 h60
  text "RoHS" at 12635.96,2293.39 h60
  text "OTHER" at 13280.36,2293.39 h60
  text "PER ORDER" at 13677.42,2293.39 h60
  text "ALL BOARDS MUST MEET OR EXCEED UL94-V0 REQUIREMENTS." at 11361,2139.57 h60
  text "PCB MUST BEAR THE UL94V-0 UL REGISTERED MATERIAL ID NUMBER" at 11361,2023.5 h60
  text "ADDITIONAL REQUIREMENTS:" at 11333.46,1854.08 h60
  text "MICROSECTION:" at 11408.23,1746.95 h60
  text "YES" at 12313.96,1746.95 h60
  text "REQUIRED" at 13175.46,1602.62 h60
  text "BARE BOARD ELEC. TEST:" at 11408.23,1599.76 h60
  text "NONE" at 12713.96,1599.76 h60
  text "X" at 13057.46,1599.76 h60
  text "PER ORDER" at 13767.46,1599.76 h60
  text "XX MIL VIAS REQUIRE NON-CONDUCTIVE FILL AND PLANARIZE" at 11576.38,1394.82 h59
  text "XX MIL VIAS REQUIRE CONDUCTIVE FILL AND PLANARIZE" at 11584.38,1290.84 h60
  text "OUTER 6.4 MIL TRACES REQUIRE 50 OHM SINGLE-ENDED IMPEDANCE" at 11583.39,1127.46 h58
  text "X" at 11459.75,1122.18 h60
  text "LAYER 2 & 3 (INNER LAYERS) XX MIL WIDE, XX MIL SPACE / TRACES REQUIRE 100 OHM DIFFERENTIAL IMPEDANCE" at 11575.39,891.74 h60
  text ".Layer_Name" at 577,-858.49 h60
M11 Gerber Information:
  lines w10: -292,-930.17 6308,-930.17 ; -292,-726.83 6310,-726.83 ; -292,-523.5 -292,-1133.5 3713,-1133.5 6310,-1133.5 6310,-523.5 -291.5,-523.5 -291.5,-1133.5 1284,-1133.5 ; 2173,-1133.5 2173,-523.5 ; 3440,-726.83 3440,-523.5 ; 4280,-726.83 4280,-523.5 ; 4902,-1140 4902,-937.17
  text "ALL ARTWORK VIEWED FROM TOP SIDE" at -228.5,-655.67 h60
  text "BOARD #:" at 2248,-655.67 h60
  text ".PRJ_Number" at 2793.5,-655.67 h60
  text "REV:" at 3638,-655.67 h60
  text ".PCB_Rev" at 3929.5,-655.67 h60
  text "SVN REV:" at 4476,-655.67 h60
  text ".VersionControl_RevNumber" at 4982,-655.67 h60
  text "LAYER NAME =" at -228.5,-858.49 h60
  text "TID #:" at 2248,-859 h60
  text ".TID" at 2793.5,-859 h60
  text "PLOT NAME =" at -228.5,-1064.34 h60
  text ".plot_File_Name" at 577,-1064.34 h60
  text "GENERATED    :" at 2250,-1064.34 h60
  text ".Print_Date" at 3119.5,-1064.34 h60
  text ".Print_Time" at 3848.5,-1064.34 h60
  text "TEXAS INSTRUMENTS" at 5113,-1064.34 h60
M12 Stackup:
  drawing of 399 lines, arcs and shapes, not listed
  text "Layer" at 6734.21,7814.1 h60
  text "Name" at 7144.13,7814.1 h60
  text "Material" at 8073.87,7814.1 h60
  text "Thickness" at 8933.64,7814.1 h60
  text "Constant" at 9583.47,7814.1 h60
  text "Board Layer Stack" at 10153.33,7814.1 h60
  text "Top Overlay" at 7144.13,7694.1 h60
  text "Top Solder" at 7144.13,7574.1 h60
  text "Solder Resist" at 8073.87,7574.1 h60
  text "0.40mil" at 8933.64,7574.1 h60
  text "3.5" at 9583.47,7574.1 h60
  text "1" at 6734.21,7454.1 h60
  text "Top Layer" at 7144.13,7454.1 h60
  text "1.40mil" at 8933.64,7454.1 h60
  text "Dielectric 1" at 7144.13,7334.1 h60
  text "PP-015" at 8073.87,7334.1 h60
  text "3.91mil" at 8933.64,7334.1 h60
  text "4.3" at 9583.47,7334.1 h60
  text "2" at 6734.21,7214.1 h60
  text "GND1" at 7144.13,7214.1 h60
  text "CF-004" at 8073.87,7214.1 h60
  text "0.69mil" at 8933.64,7214.1 h60
  text "Dielectric 2" at 7144.13,7094.1 h60
  text "Core-037" at 8073.87,7094.1 h60
  text "21.65mil" at 8933.64,7094.1 h60
  text "4.8" at 9583.47,7094.1 h60
  text "3" at 6734.21,6974.1 h60
  text "Layer 2" at 7144.13,6974.1 h60
  text "CF-004" at 8073.87,6974.1 h60
  text "0.69mil" at 8933.64,6974.1 h60
  text "Dielectric1" at 7144.13,6854.1 h60
  text "PP-016" at 8073.87,6854.1 h60
  text "4.28mil" at 8933.64,6854.1 h60
  text "4.4" at 9583.47,6854.1 h60
  text "4" at 6734.21,6734.1 h60
  text "PWR" at 7144.13,6734.1 h60
  text "CF-004" at 8073.87,6734.1 h60
  text "0.69mil" at 8933.64,6734.1 h60
  text "Dielectric 3" at 7144.13,6614.1 h60
  text "Core-037" at 8073.87,6614.1 h60
  text "21.65mil" at 8933.64,6614.1 h60
  text "4.8" at 9583.47,6614.1 h60
  text "5" at 6734.21,6494.1 h60
  text "GND2" at 7144.13,6494.1 h60
  text "CF-004" at 8073.87,6494.1 h60
  text "0.69mil" at 8933.64,6494.1 h60
  text "Dielectric 4" at 7144.13,6374.1 h60
  text "PP-015" at 8073.87,6374.1 h60
  text "3.91mil" at 8933.64,6374.1 h60
  text "4.3" at 9583.47,6374.1 h60
  text "6" at 6734.21,6254.1 h60
  text "Bottom Layer" at 7144.13,6254.1 h60
  text "1.40mil" at 8933.64,6254.1 h60
  text "Bottom Solder" at 7144.13,6134.1 h60
  text "Solder Resist" at 8073.87,6134.1 h60
  text "0.40mil" at 8933.64,6134.1 h60
  text "3.5" at 9583.47,6134.1 h60
  text "Bottom Overlay" at 7144.13,6014.1 h60
  text ".Layer_Name" at 577,-858.49 h60
M13 Component Bodies Top:
  text ".Layer_Name" at 577,-858.49 h60
M14 Component Bodies Bottom:
  text ".Layer_Name" at 577,-858.49 h60
M15 Courtyards Top:
  text ".Layer_Name" at 577,-858.49 h60
M16 Courtyards Bottom:
  text ".Layer_Name" at 577,-858.49 h60
Drill Drawing:
  drawing of 184 lines, arcs and shapes, not listed
  text "Symbol" at 3378.45,7781.6 h72
  text "Quantity" at 3679.03,7781.6 h72
  text "Finished Hole Size" at 4011.13,7781.6 h72
  text "Plated" at 4647.77,7781.6 h72
  text "Hole Type" at 4906.98,7781.6 h72
  text "Drill Layer Pair" at 5282.23,7781.6 h72
  text "Hole Tolerance" at 6006.84,7781.6 h72
  text "2" at 3679.03,7657.29 h60
  text "31.50mil (0.800mm)" at 4011.13,7657.29 h60
  text "NPTH" at 4647.77,7657.29 h60
  text "Round" at 4906.98,7657.29 h60
  text "Top Layer - Bottom Layer" at 5282.23,7657.29 h60
  text "4" at 3679.03,7532.98 h60
  text "126.77mil (3.220mm)" at 4011.13,7532.98 h60
  text "NPTH" at 4647.77,7532.98 h60
  text "Round" at 4906.98,7532.98 h60
  text "Top Layer - Bottom Layer" at 5282.23,7532.98 h60
  text "167" at 3679.03,7408.67 h60
  text "7.87mil (0.200mm)" at 4011.13,7408.67 h60
  text "PTH" at 4647.77,7408.67 h60
  text "Round" at 4906.98,7408.67 h60
  text "Top Layer - Bottom Layer" at 5282.23,7408.67 h60
  text "1314" at 3679.03,7284.35 h60
  text "8.00mil (0.203mm)" at 4011.13,7284.35 h60
  text "PTH" at 4647.77,7284.35 h60
  text "Round" at 4906.98,7284.35 h60
  text "Top Layer - Bottom Layer" at 5282.23,7284.35 h60
  text "2" at 3679.03,7160.04 h60
  text "25.00mil (0.635mm)" at 4011.13,7160.04 h60
  text "PTH" at 4647.77,7160.04 h60
  text "Round" at 4906.98,7160.04 h60
  text "Top Layer - Bottom Layer" at 5282.23,7160.04 h60
  text "40" at 3679.03,7035.73 h60
  text "39.37mil (1.000mm)" at 4011.13,7035.73 h60
  text "PTH" at 4647.77,7035.73 h60
  text "Round" at 4906.98,7035.73 h60
  text "Top Layer - Bottom Layer" at 5282.23,7035.73 h60
  text "10" at 3679.03,6911.42 h60
  text "45.28mil (1.150mm)" at 4011.13,6911.42 h60
  text "PTH" at 4647.77,6911.42 h60
  text "Round" at 4906.98,6911.42 h60
  text "Top Layer - Bottom Layer" at 5282.23,6911.42 h60
  text "4" at 3679.03,6787.11 h60
  text "51.18mil (1.300mm)" at 4011.13,6787.11 h60
  text "PTH" at 4647.77,6787.11 h60
  text "Round" at 4906.98,6787.11 h60
  text "Top Layer - Bottom Layer" at 5282.23,6787.11 h60
  text "3" at 3679.03,6662.79 h60
  text "63.00mil (1.600mm)" at 4011.13,6662.79 h60
  text "PTH" at 4647.77,6662.79 h60
  text "Round" at 4906.98,6662.79 h60
  text "Top Layer - Bottom Layer" at 5282.23,6662.79 h60
  text "2" at 3679.03,6538.48 h60
  text "66.93mil (1.700mm)" at 4011.13,6538.48 h60
  text "PTH" at 4647.77,6538.48 h60
  text "Round" at 4906.98,6538.48 h60
  text "Top Layer - Bottom Layer" at 5282.23,6538.48 h60
  text "6" at 3679.03,6414.17 h60
  text "125.98mil (3.200mm)" at 4011.13,6414.17 h60
  text "PTH" at 4647.77,6414.17 h60
  text "Round" at 4906.98,6414.17 h60
  text "Top Layer - Bottom Layer" at 5282.23,6414.17 h60
  text "2" at 3679.03,6289.86 h60
  text "21.65mil (0.550mm)" at 4011.13,6289.86 h60
  text "PTH" at 4647.77,6289.86 h60
  text "Slot" at 4906.98,6289.86 h60
  text "Top Layer - Bottom Layer" at 5282.23,6289.86 h60
  text "2" at 3679.03,6165.54 h60
  text "31.50mil (0.800mm)" at 4011.13,6165.54 h60
  text "PTH" at 4647.77,6165.54 h60
  text "Slot" at 4906.98,6165.54 h60
  text "Top Layer - Bottom Layer" at 5282.23,6165.54 h60
  text "2" at 3679.03,6041.23 h60
  text "33.47mil (0.850mm)" at 4011.13,6041.23 h60
  text "PTH" at 4647.77,6041.23 h60
  text "Slot" at 4906.98,6041.23 h60
  text "Top Layer - Bottom Layer" at 5282.23,6041.23 h60
  text "1" at 3679.03,5916.92 h60
  text "149.61mil (3.800mm)" at 4011.13,5916.92 h60
  text "PTH" at 4647.77,5916.92 h60
  text "Slot" at 4906.98,5916.92 h60
  text "Top Layer - Bottom Layer" at 5282.23,5916.92 h60
  text "1561 Total" at 3679.03,5792.61 h60
  text "Slot definitions :" at 3378.45,5705.59 h60
  text "Routed Path Length" at 3829.19,5705.59 h60
  text "= Calculated from tool start centre position to tool end centre position." at 4369.04,5705.59 h60
  text "Hole Length" at 3829.19,5655.86 h60
  text "= Routed Path Length + Tool Size = Slot length as defined in the PCB layout" at 4169.19,5655.86 h60
  text ".Layer_Name" at 577,-858.49 h60
M17 Embedded Cavity:
  text ".Layer_Name" at 577,-858.49 h60
M18 Embedded Assembly:
  text ".Layer_Name" at 577,-858.49 h60
M19 Embedded Keepout:
  text ".Layer_Name" at 577,-858.49 h60

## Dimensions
0,-400 to 1000,-400 on M2 Board Dimensions
0,0 to 0,2362.2 on M2 Board Dimensions
0,0 to 7874.02,0 on M2 Board Dimensions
